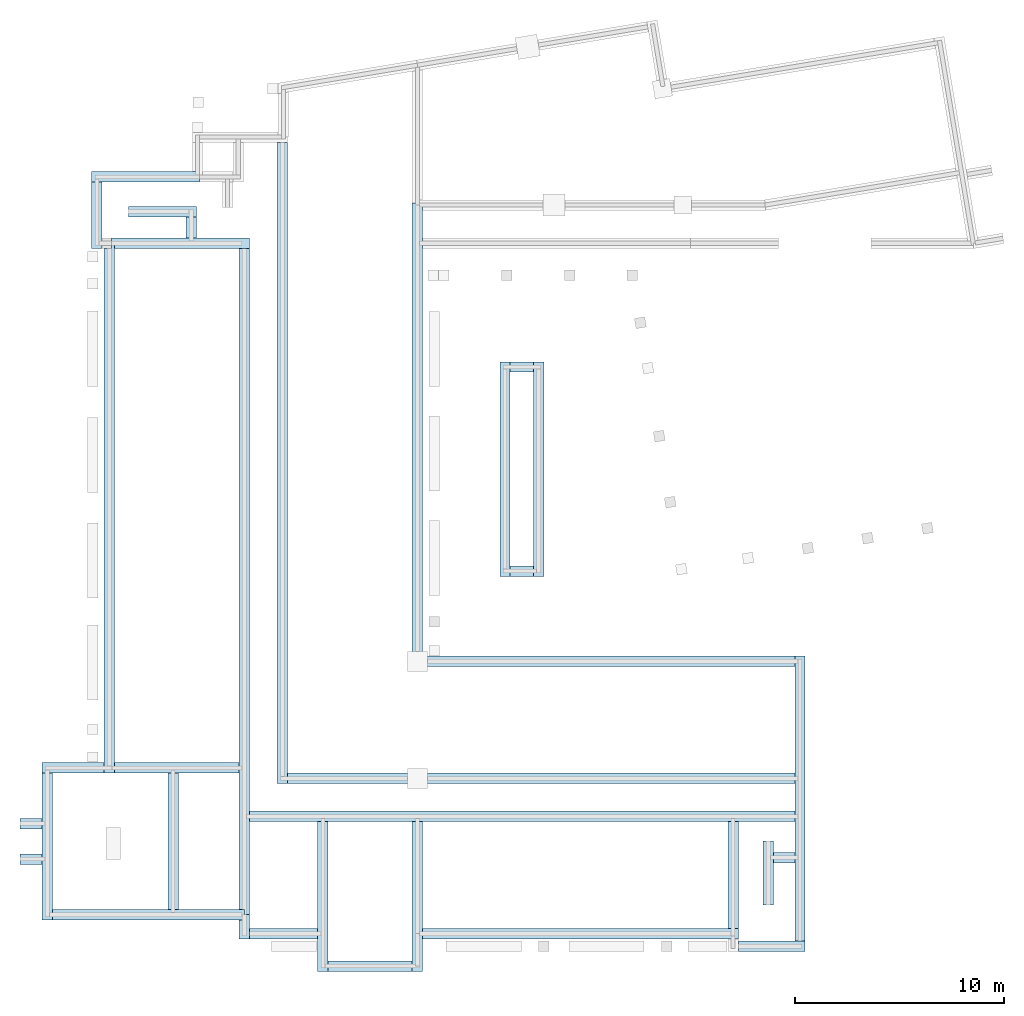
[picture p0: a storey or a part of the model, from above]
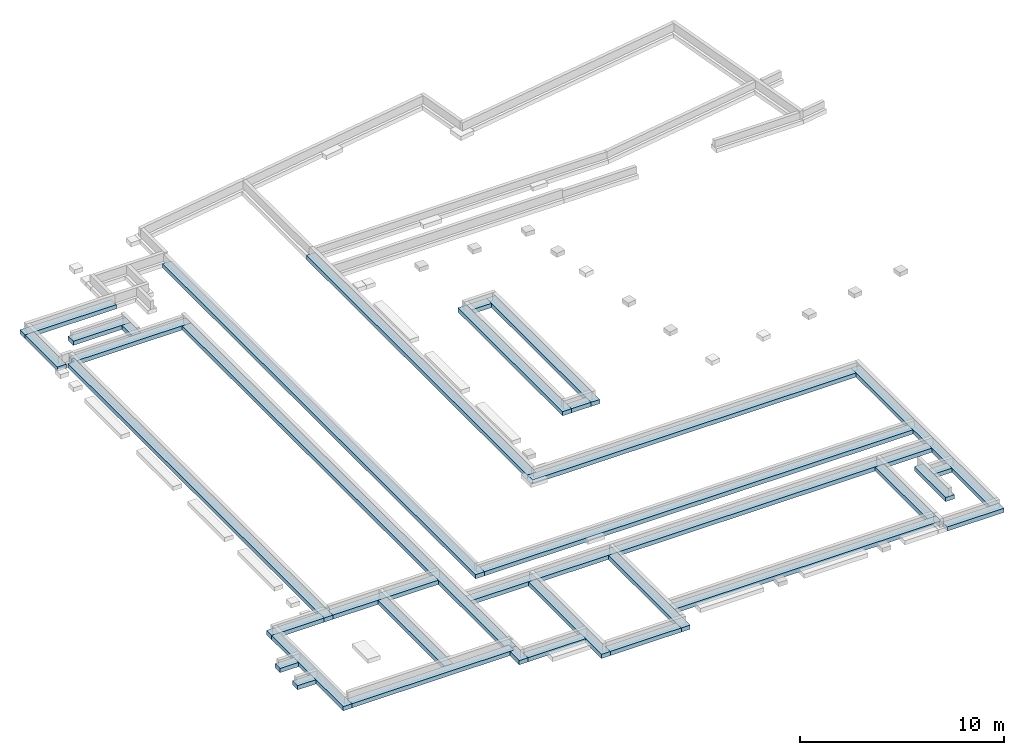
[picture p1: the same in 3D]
Properties of the parts of a building model (IFC4), part 1 of 5

# File
Description: ViewDefinition [ReferenceView_V1.2], ExchangeRequirement [Architecture]
File name: 0001
Time: 2023-01-23T10:33:38+01:00
Written by: ODA SDAI 22.12
Made in: 23.0.11.19 - Exporter 23.0.11.19 - Interface utilisateur alternative 23.0.11.19

# IfcProject, 0001
LongName: Nom du projet; Phase: Etat du projet

# IfcSite, Default
RefLatitude: 48, 51, 23, 999633; RefLongitude: 2, 21, 3, 553905; RefElevation: 0 m
Pset_SiteCommon - Reference: Informations sur le projet

# IfcBuilding
Pset_BuildingCommon - Reference: Informations sur le projet; NumberOfStoreys: 9
Pset_BuildingElementProxyCommon - Reference: Informations sur le projet; IsExternal: no
Pset_BuildingStoreyCommon - Reference: Informations sur le projet; sets with these values: 2

# IfcBuildingStorey: Niveau:Ligne du Niveau (9)
Pset_BuildingStoreyCommon - Reference: Ligne du Niveau
Name | LongName | Elevation (m)
Arase inf soubassement | Arase inf soubassement | -0.88
Arase inf longrines | Arase inf longrines | -0.63
RDC | RDC | 0
R+1 fini | R+1 fini | 3.6
Aras inf plancher haut RDC (dalle 29cm) | Aras inf plancher haut RDC (dalle 29cm) | 3.7
Aras sup plancher haut RDC | Aras sup plancher haut RDC | 3.99
Aras plafond 2.6 R+1 | Aras plafond 2.6 R+1 | 6.2
Aras plafond 3 R+1 | Aras plafond 3 R+1 | 6.6
Aras sup mur R+1 | Aras sup mur R+1 | 7.1

# IfcSpace: Agent entretien 4:1338018, 4
In: RDC
LongName: Agent entretien; PredefinedType: SPACE
Pset_SpaceCommon - IsExternal: no; Reference: Agent entretien 4
Pset_SpaceHeaterTypeCommon - Reference: Agent entretien 4
Qto_SpaceBaseQuantities - Height: 2.4384 m; GrossVolume: 48.8675 m3; NetVolume: 48.8675 m3

# IfcSpace: Animateur 7:1338027, 7
In: RDC
LongName: Animateur; PredefinedType: SPACE
Pset_SpaceCommon - IsExternal: no; Reference: Animateur 7
Pset_SpaceHeaterTypeCommon - Reference: Animateur 7
Qto_SpaceBaseQuantities - Height: 2.4384 m; GrossVolume: 35.9447 m3; NetVolume: 35.9447 m3

# IfcSpace: Ascenseur 79:1772514, 79
In: RDC
LongName: Ascenseur; PredefinedType: SPACE
Pset_SpaceCommon - IsExternal: no; Reference: Ascenseur 79
Pset_SpaceHeaterTypeCommon - Reference: Ascenseur 79
Qto_SpaceBaseQuantities - Height: 2.6 m; GrossVolume: 7.735 m3; NetVolume: 7.735 m3

# IfcSpace: Bagagerie 3:1338015, 3
In: RDC
LongName: Bagagerie; PredefinedType: SPACE
Pset_SpaceCommon - IsExternal: no; Reference: Bagagerie 3
Pset_SpaceHeaterTypeCommon - Reference: Bagagerie 3
Qto_SpaceBaseQuantities - Height: 2.4384 m; GrossVolume: 51.1568 m3; NetVolume: 51.1568 m3

# IfcSpace: Billard 2:1338012, 2
In: RDC
LongName: Billard; PredefinedType: SPACE
Pset_SpaceCommon - IsExternal: no; Reference: Billard 2
Pset_SpaceHeaterTypeCommon - Reference: Billard 2
Qto_SpaceBaseQuantities - Height: 2.4384 m; GrossVolume: 53.5814 m3; NetVolume: 53.5814 m3

# IfcSpace: Blanchisserie 6:1338024, 6
In: RDC
LongName: Blanchisserie; PredefinedType: SPACE
Pset_SpaceCommon - IsExternal: no; Reference: Blanchisserie 6
Pset_SpaceHeaterTypeCommon - Reference: Blanchisserie 6
Qto_SpaceBaseQuantities - Height: 2.4384 m; GrossVolume: 48.788 m3; NetVolume: 48.788 m3

# IfcSpace: Chambre 1 47:1339767, 47
In: RDC
LongName: Chambre 1; PredefinedType: SPACE
Pset_SpaceCommon - IsExternal: no; Reference: Chambre 1 47
Pset_SpaceHeaterTypeCommon - Reference: Chambre 1 47
Qto_SpaceBaseQuantities - Height: 2.4384 m; GrossVolume: 58.6162 m3; NetVolume: 58.6162 m3

# IfcSpace: Chambre 10 36:1339734, 36
In: RDC
LongName: Chambre 10; PredefinedType: SPACE
Pset_SpaceCommon - IsExternal: no; Reference: Chambre 10 36
Pset_SpaceHeaterTypeCommon - Reference: Chambre 10 36
Qto_SpaceBaseQuantities - Height: 2.4384 m; GrossVolume: 26.3973 m3; NetVolume: 26.3973 m3

# IfcSpace: Chambre 11 37:1339737, 37
In: RDC
LongName: Chambre 11; PredefinedType: SPACE
Pset_SpaceCommon - IsExternal: no; Reference: Chambre 11 37
Pset_SpaceHeaterTypeCommon - Reference: Chambre 11 37
Qto_SpaceBaseQuantities - Height: 2.4384 m; GrossVolume: 27.7189 m3; NetVolume: 27.7189 m3

# IfcSpace: Chambre 12 27:1338818, 27
In: RDC
LongName: Chambre 12; PredefinedType: SPACE
Pset_SpaceCommon - IsExternal: no; Reference: Chambre 12 27
Pset_SpaceHeaterTypeCommon - Reference: Chambre 12 27
Qto_SpaceBaseQuantities - Height: 2.4384 m; GrossVolume: 28.3696 m3; NetVolume: 28.3696 m3

# IfcSpace: Chambre 13 28:1339710, 28
In: RDC
LongName: Chambre 13; PredefinedType: SPACE
Pset_SpaceCommon - IsExternal: no; Reference: Chambre 13 28
Pset_SpaceHeaterTypeCommon - Reference: Chambre 13 28
Qto_SpaceBaseQuantities - Height: 2.4384 m; GrossVolume: 28.4378 m3; NetVolume: 28.4378 m3

# IfcSpace: Chambre 14 29:1339713, 29
In: RDC
LongName: Chambre 14; PredefinedType: SPACE
Pset_SpaceCommon - IsExternal: no; Reference: Chambre 14 29
Pset_SpaceHeaterTypeCommon - Reference: Chambre 14 29
Qto_SpaceBaseQuantities - Height: 2.4384 m; GrossVolume: 27.6278 m3; NetVolume: 27.6278 m3

# IfcSpace: Chambre 15 30:1339716, 30
In: RDC
LongName: Chambre 15; PredefinedType: SPACE
Pset_SpaceCommon - IsExternal: no; Reference: Chambre 15 30
Pset_SpaceHeaterTypeCommon - Reference: Chambre 15 30
Qto_SpaceBaseQuantities - Height: 2.4384 m; GrossVolume: 27.1823 m3; NetVolume: 27.1823 m3

# IfcSpace: Chambre 16 31:1339719, 31
In: RDC
LongName: Chambre 16; PredefinedType: SPACE
Pset_SpaceCommon - IsExternal: no; Reference: Chambre 16 31
Pset_SpaceHeaterTypeCommon - Reference: Chambre 16 31
Qto_SpaceBaseQuantities - Height: 2.4384 m; GrossVolume: 26.2068 m3; NetVolume: 26.2068 m3

# IfcSpace: Chambre 17 32:1339722, 32
In: RDC
LongName: Chambre 17; PredefinedType: SPACE
Pset_SpaceCommon - IsExternal: no; Reference: Chambre 17 32
Pset_SpaceHeaterTypeCommon - Reference: Chambre 17 32
Qto_SpaceBaseQuantities - Height: 2.4384 m; GrossVolume: 26.0209 m3; NetVolume: 26.0209 m3

# IfcSpace: Chambre 18 41:1339749, 41
In: RDC
LongName: Chambre 18; PredefinedType: SPACE
Pset_SpaceCommon - IsExternal: no; Reference: Chambre 18 41
Pset_SpaceHeaterTypeCommon - Reference: Chambre 18 41
Qto_SpaceBaseQuantities - Height: 2.4384 m; GrossVolume: 59.6883 m3; NetVolume: 59.6883 m3

# IfcSpace: Chambre 19 42:1339752, 42
In: RDC
LongName: Chambre 19; PredefinedType: SPACE
Pset_SpaceCommon - IsExternal: no; Reference: Chambre 19 42
Pset_SpaceHeaterTypeCommon - Reference: Chambre 19 42
Qto_SpaceBaseQuantities - Height: 2.4384 m; GrossVolume: 61.8927 m3; NetVolume: 61.8927 m3

# IfcSpace: Chambre 2 44:1339758, 44
In: RDC
LongName: Chambre 2; PredefinedType: SPACE
Pset_SpaceCommon - IsExternal: no; Reference: Chambre 2 44
Pset_SpaceHeaterTypeCommon - Reference: Chambre 2 44
Qto_SpaceBaseQuantities - Height: 2.4384 m; GrossVolume: 59.9449 m3; NetVolume: 59.9449 m3

# IfcSpace: Chambre 20 45:1339761, 45
In: RDC
LongName: Chambre 20; PredefinedType: SPACE
Pset_SpaceCommon - IsExternal: no; Reference: Chambre 20 45
Pset_SpaceHeaterTypeCommon - Reference: Chambre 20 45
Qto_SpaceBaseQuantities - Height: 2.4384 m; GrossVolume: 60.4265 m3; NetVolume: 60.4265 m3

# IfcSpace: Chambre 21 46:1339764, 46
In: RDC
LongName: Chambre 21; PredefinedType: SPACE
Pset_SpaceCommon - IsExternal: no; Reference: Chambre 21 46
Pset_SpaceHeaterTypeCommon - Reference: Chambre 21 46
Qto_SpaceBaseQuantities - Height: 2.4384 m; GrossVolume: 61.8682 m3; NetVolume: 61.8682 m3

# IfcSpace: Chambre 22 74:1519061, 74
In: R+1 fini
LongName: Chambre 22; PredefinedType: SPACE
Pset_SpaceCommon - IsExternal: no; Reference: Chambre 22 74
Pset_SpaceHeaterTypeCommon - Reference: Chambre 22 74
Qto_SpaceBaseQuantities - Height: 2.6 m; GrossVolume: 62.5554 m3; NetVolume: 62.5554 m3

# IfcSpace: Chambre 23 71:1519052, 71
In: R+1 fini
LongName: Chambre 23; PredefinedType: SPACE
Pset_SpaceCommon - IsExternal: no; Reference: Chambre 23 71
Pset_SpaceHeaterTypeCommon - Reference: Chambre 23 71
Qto_SpaceBaseQuantities - Height: 2.6 m; GrossVolume: 63.4638 m3; NetVolume: 63.4638 m3

# IfcSpace: Chambre 24 70:1519049, 70
In: R+1 fini
LongName: Chambre 24; PredefinedType: SPACE
Pset_SpaceCommon - IsExternal: no; Reference: Chambre 24 70
Pset_SpaceHeaterTypeCommon - Reference: Chambre 24 70
Qto_SpaceBaseQuantities - Height: 2.6 m; GrossVolume: 64.3113 m3; NetVolume: 64.3113 m3

# IfcSpace: Chambre 25 67:1519040, 67
In: R+1 fini
LongName: Chambre 25; PredefinedType: SPACE
Pset_SpaceCommon - IsExternal: no; Reference: Chambre 25 67
Pset_SpaceHeaterTypeCommon - Reference: Chambre 25 67
Qto_SpaceBaseQuantities - Height: 2.6 m; GrossVolume: 61.9334 m3; NetVolume: 61.9334 m3

# IfcSpace: Chambre 26 (PMR) 66:1519037, 66
In: R+1 fini
LongName: Chambre 26 (PMR); PredefinedType: SPACE
Pset_SpaceCommon - IsExternal: no; Reference: Chambre 26 (PMR) 66
Pset_SpaceHeaterTypeCommon - Reference: Chambre 26 (PMR) 66
Qto_SpaceBaseQuantities - Height: 2.6 m; GrossVolume: 62.758 m3; NetVolume: 62.758 m3

# IfcSpace: Chambre 27 (veilleur de nuit) 62:1519025, 62
In: R+1 fini
LongName: Chambre 27 (veilleur de nuit); PredefinedType: SPACE
Pset_SpaceCommon - IsExternal: no; Reference: Chambre 27 (veilleur de nuit) 62
Pset_SpaceHeaterTypeCommon - Reference: Chambre 27 (veilleur de nuit) 62
Qto_SpaceBaseQuantities - Height: 2.6 m; GrossVolume: 29.6416 m3; NetVolume: 29.6416 m3

# IfcSpace: Chambre 28 (PMR) 61:1519022, 61
In: R+1 fini
LongName: Chambre 28 (PMR); PredefinedType: SPACE
Pset_SpaceCommon - IsExternal: no; Reference: Chambre 28 (PMR) 61
Pset_SpaceHeaterTypeCommon - Reference: Chambre 28 (PMR) 61
Qto_SpaceBaseQuantities - Height: 2.6 m; GrossVolume: 34.8429 m3; NetVolume: 34.8429 m3

# IfcSpace: Chambre 29 59:1519016, 59
In: R+1 fini
LongName: Chambre 29; PredefinedType: SPACE
Pset_SpaceCommon - IsExternal: no; Reference: Chambre 29 59
Pset_SpaceHeaterTypeCommon - Reference: Chambre 29 59
Qto_SpaceBaseQuantities - Height: 2.6 m; GrossVolume: 33.7835 m3; NetVolume: 33.7835 m3

# IfcSpace: Chambre 3 43:1339755, 43
In: RDC
LongName: Chambre 3; PredefinedType: SPACE
Pset_SpaceCommon - IsExternal: no; Reference: Chambre 3 43
Pset_SpaceHeaterTypeCommon - Reference: Chambre 3 43
Qto_SpaceBaseQuantities - Height: 2.4384 m; GrossVolume: 59.8766 m3; NetVolume: 59.8766 m3

# IfcSpace: Chambre 30 58:1519013, 58
In: R+1 fini
LongName: Chambre 30; PredefinedType: SPACE
Pset_SpaceCommon - IsExternal: no; Reference: Chambre 30 58
Pset_SpaceHeaterTypeCommon - Reference: Chambre 30 58
Qto_SpaceBaseQuantities - Height: 2.6 m; GrossVolume: 28.125 m3; NetVolume: 28.125 m3

# IfcSpace: Chambre 31 57:1519010, 57
In: R+1 fini
LongName: Chambre 31; PredefinedType: SPACE
Pset_SpaceCommon - IsExternal: no; Reference: Chambre 31 57
Pset_SpaceHeaterTypeCommon - Reference: Chambre 31 57
Qto_SpaceBaseQuantities - Height: 2.6 m; GrossVolume: 28.1467 m3; NetVolume: 28.1467 m3

# IfcSpace: Chambre 32 56:1519007, 56
In: R+1 fini
LongName: Chambre 32; PredefinedType: SPACE
Pset_SpaceCommon - IsExternal: no; Reference: Chambre 32 56
Pset_SpaceHeaterTypeCommon - Reference: Chambre 32 56
Qto_SpaceBaseQuantities - Height: 2.6 m; GrossVolume: 28.2171 m3; NetVolume: 28.2171 m3

# IfcSpace: Chambre 33 55:1519004, 55
In: R+1 fini
LongName: Chambre 33; PredefinedType: SPACE
Pset_SpaceCommon - IsExternal: no; Reference: Chambre 33 55
Pset_SpaceHeaterTypeCommon - Reference: Chambre 33 55
Qto_SpaceBaseQuantities - Height: 2.6 m; GrossVolume: 29.4854 m3; NetVolume: 29.4854 m3

# IfcSpace: Chambre 35 50:1518989, 50
In: R+1 fini
LongName: Chambre 35; PredefinedType: SPACE
Pset_SpaceCommon - IsExternal: no; Reference: Chambre 35 50
Pset_SpaceHeaterTypeCommon - Reference: Chambre 35 50
Qto_SpaceBaseQuantities - Height: 2.6 m; GrossVolume: 30.2575 m3; NetVolume: 30.2575 m3

# IfcSpace: Chambre 36 51:1518992, 51
In: R+1 fini
LongName: Chambre 36; PredefinedType: SPACE
Pset_SpaceCommon - IsExternal: no; Reference: Chambre 36 51
Pset_SpaceHeaterTypeCommon - Reference: Chambre 36 51
Qto_SpaceBaseQuantities - Height: 2.6 m; GrossVolume: 29.3948 m3; NetVolume: 29.3948 m3

# IfcSpace: Chambre 37 52:1518995, 52
In: R+1 fini
LongName: Chambre 37; PredefinedType: SPACE
Pset_SpaceCommon - IsExternal: no; Reference: Chambre 37 52
Pset_SpaceHeaterTypeCommon - Reference: Chambre 37 52
Qto_SpaceBaseQuantities - Height: 2.6 m; GrossVolume: 28.9234 m3; NetVolume: 28.9234 m3

# IfcSpace: Chambre 38 53:1518998, 53
In: R+1 fini
LongName: Chambre 38; PredefinedType: SPACE
Pset_SpaceCommon - IsExternal: no; Reference: Chambre 38 53
Pset_SpaceHeaterTypeCommon - Reference: Chambre 38 53
Qto_SpaceBaseQuantities - Height: 2.6 m; GrossVolume: 27.8849 m3; NetVolume: 27.8849 m3

# IfcSpace: Chambre 39 54:1519001, 54
In: R+1 fini
LongName: Chambre 39; PredefinedType: SPACE
Pset_SpaceCommon - IsExternal: no; Reference: Chambre 39 54
Pset_SpaceHeaterTypeCommon - Reference: Chambre 39 54
Qto_SpaceBaseQuantities - Height: 2.6 m; GrossVolume: 27.6892 m3; NetVolume: 27.6892 m3

# IfcSpace: Chambre 4 40:1339746, 40
In: RDC
LongName: Chambre 4; PredefinedType: SPACE
Pset_SpaceCommon - IsExternal: no; Reference: Chambre 4 40
Pset_SpaceHeaterTypeCommon - Reference: Chambre 4 40
Qto_SpaceBaseQuantities - Height: 2.4384 m; GrossVolume: 58.1102 m3; NetVolume: 58.1102 m3

# IfcSpace: Chambre 40 68:1519043, 68
In: R+1 fini
LongName: Chambre 40; PredefinedType: SPACE
Pset_SpaceCommon - IsExternal: no; Reference: Chambre 40 68
Pset_SpaceHeaterTypeCommon - Reference: Chambre 40 68
Qto_SpaceBaseQuantities - Height: 2.6 m; GrossVolume: 63.1735 m3; NetVolume: 63.1735 m3

# IfcSpace: Chambre 41 69:1519046, 69
In: R+1 fini
LongName: Chambre 41; PredefinedType: SPACE
Pset_SpaceCommon - IsExternal: no; Reference: Chambre 41 69
Pset_SpaceHeaterTypeCommon - Reference: Chambre 41 69
Qto_SpaceBaseQuantities - Height: 2.6 m; GrossVolume: 66.1915 m3; NetVolume: 66.1915 m3

# IfcSpace: Chambre 42 72:1519055, 72
In: R+1 fini
LongName: Chambre 42; PredefinedType: SPACE
Pset_SpaceCommon - IsExternal: no; Reference: Chambre 42 72
Pset_SpaceHeaterTypeCommon - Reference: Chambre 42 72
Qto_SpaceBaseQuantities - Height: 2.6 m; GrossVolume: 64.2993 m3; NetVolume: 64.2993 m3

# IfcSpace: Chambre 43 73:1519058, 73
In: R+1 fini
LongName: Chambre 43; PredefinedType: SPACE
Pset_SpaceCommon - IsExternal: no; Reference: Chambre 43 73
Pset_SpaceHeaterTypeCommon - Reference: Chambre 43 73
Qto_SpaceBaseQuantities - Height: 2.6 m; GrossVolume: 65.6704 m3; NetVolume: 65.6704 m3

# IfcSpace: Chambre 44 75:1519064, 75
In: R+1 fini
LongName: Chambre 44; PredefinedType: SPACE
Pset_SpaceCommon - IsExternal: no; Reference: Chambre 44 75
Pset_SpaceHeaterTypeCommon - Reference: Chambre 44 75
Qto_SpaceBaseQuantities - Height: 2.6 m; GrossVolume: 64.3191 m3; NetVolume: 64.3191 m3

# IfcSpace: Chambre 5 PMR 39:1339743, 39
In: RDC
LongName: Chambre 5 PMR; PredefinedType: SPACE
Pset_SpaceCommon - IsExternal: no; Reference: Chambre 5 PMR 39
Pset_SpaceHeaterTypeCommon - Reference: Chambre 5 PMR 39
Qto_SpaceBaseQuantities - Height: 2.4384 m; GrossVolume: 58.8659 m3; NetVolume: 58.8659 m3

# IfcSpace: Chambre 6 38:1339740, 38
In: RDC
LongName: Chambre 6; PredefinedType: SPACE
Pset_SpaceCommon - IsExternal: no; Reference: Chambre 6 38
Pset_SpaceHeaterTypeCommon - Reference: Chambre 6 38
Qto_SpaceBaseQuantities - Height: 2.4384 m

# IfcSpace: Chambre 7 33:1339725, 33
In: RDC
LongName: Chambre 7; PredefinedType: SPACE
Pset_SpaceCommon - IsExternal: no; Reference: Chambre 7 33
Pset_SpaceHeaterTypeCommon - Reference: Chambre 7 33
Qto_SpaceBaseQuantities - Height: 2.4384 m; GrossVolume: 31.6837 m3; NetVolume: 31.6837 m3

# IfcSpace: Chambre 8 34:1339728, 34
In: RDC
LongName: Chambre 8; PredefinedType: SPACE
Pset_SpaceCommon - IsExternal: no; Reference: Chambre 8 34
Pset_SpaceHeaterTypeCommon - Reference: Chambre 8 34
Qto_SpaceBaseQuantities - Height: 2.4384 m; GrossVolume: 26.3973 m3; NetVolume: 26.3973 m3

# IfcSpace: Chambre 9 35:1339731, 35
In: RDC
LongName: Chambre 9; PredefinedType: SPACE
Pset_SpaceCommon - IsExternal: no; Reference: Chambre 9 35
Pset_SpaceHeaterTypeCommon - Reference: Chambre 9 35
Qto_SpaceBaseQuantities - Height: 2.4384 m; GrossVolume: 26.3973 m3; NetVolume: 26.3973 m3

# IfcSpace: Chambre34 49:1518985, 49
In: R+1 fini
LongName: Chambre34; PredefinedType: SPACE
Pset_SpaceCommon - IsExternal: no; Reference: Chambre34 49
Pset_SpaceHeaterTypeCommon - Reference: Chambre34 49
Qto_SpaceBaseQuantities - Height: 2.6 m; GrossVolume: 30.1847 m3; NetVolume: 30.1847 m3

# IfcSpace: Chaufferie 18:1338604, 18
In: RDC
LongName: Chaufferie; PredefinedType: SPACE
Pset_SpaceCommon - IsExternal: no; Reference: Chaufferie 18
Pset_SpaceHeaterTypeCommon - Reference: Chaufferie 18
Qto_SpaceBaseQuantities - Height: 2.4384 m; GrossVolume: 121.654 m3; NetVolume: 121.654 m3

# IfcSpace: Dégagement 15:1338595, 15
In: RDC
LongName: Dégagement; PredefinedType: SPACE
Pset_SpaceCommon - IsExternal: no; Reference: Dégagement 15
Pset_SpaceHeaterTypeCommon - Reference: Dégagement 15
Qto_SpaceBaseQuantities - Height: 2.4384 m; GrossVolume: 36.2378 m3; NetVolume: 36.2378 m3

# IfcSpace: Dégagement 16:1338598, 16
In: RDC
LongName: Dégagement; PredefinedType: SPACE
Pset_SpaceCommon - IsExternal: no; Reference: Dégagement 16
Pset_SpaceHeaterTypeCommon - Reference: Dégagement 16
Qto_SpaceBaseQuantities - Height: 2.4384 m; GrossVolume: 148.132 m3; NetVolume: 148.132 m3

# IfcSpace: Dégagement 17:1338601, 17
In: RDC
LongName: Dégagement; PredefinedType: SPACE
Pset_SpaceCommon - IsExternal: no; Reference: Dégagement 17
Pset_SpaceHeaterTypeCommon - Reference: Dégagement 17
Qto_SpaceBaseQuantities - Height: 2.4384 m; GrossVolume: 88.0575 m3; NetVolume: 88.0575 m3

# IfcSpace: Dégagement 26:1338812, 26
In: RDC
LongName: Dégagement; PredefinedType: SPACE
Pset_SpaceCommon - IsExternal: no; Reference: Dégagement 26
Pset_SpaceHeaterTypeCommon - Reference: Dégagement 26
Qto_SpaceBaseQuantities - Height: 2.4384 m; GrossVolume: 28.3128 m3; NetVolume: 28.3128 m3

# IfcSpace: Dégagement 48:1345402, 48
In: RDC
LongName: Dégagement; PredefinedType: SPACE
Pset_SpaceCommon - IsExternal: no; Reference: Dégagement 48
Pset_SpaceHeaterTypeCommon - Reference: Dégagement 48
Qto_SpaceBaseQuantities - Height: 2.4384 m; GrossVolume: 59.0178 m3; NetVolume: 59.0178 m3

# IfcSpace: Dégagement 76:1519067, 76
In: R+1 fini
LongName: Dégagement; PredefinedType: SPACE
Pset_SpaceCommon - IsExternal: no; Reference: Dégagement 76
Pset_SpaceHeaterTypeCommon - Reference: Dégagement 76
Qto_SpaceBaseQuantities - Height: 2.6 m; GrossVolume: 63.8807 m3; NetVolume: 63.8807 m3

# IfcSpace: Dégagement 77:1519070, 77
In: R+1 fini
LongName: Dégagement; PredefinedType: SPACE
Pset_SpaceCommon - IsExternal: no; Reference: Dégagement 77
Pset_SpaceHeaterTypeCommon - Reference: Dégagement 77
Qto_SpaceBaseQuantities - Height: 2.6 m; GrossVolume: 91.2279 m3; NetVolume: 91.2279 m3

# IfcSpace: Dégagement 78:1519073, 78
In: R+1 fini
LongName: Dégagement; PredefinedType: SPACE
Pset_SpaceCommon - IsExternal: no; Reference: Dégagement 78
Pset_SpaceHeaterTypeCommon - Reference: Dégagement 78
Qto_SpaceBaseQuantities - Height: 2.6 m; GrossVolume: 92.7482 m3; NetVolume: 92.7482 m3

# IfcSpace: Dépôt 9:1338033, 9
In: RDC
LongName: Dépôt; PredefinedType: SPACE
Pset_SpaceCommon - IsExternal: no; Reference: Dépôt 9
Pset_SpaceHeaterTypeCommon - Reference: Dépôt 9
Qto_SpaceBaseQuantities - Height: 2.4384 m; GrossVolume: 13.607 m3; NetVolume: 13.607 m3

# IfcSpace: Entrée 13:1338589, 13
In: RDC
LongName: Entrée; PredefinedType: SPACE
Pset_SpaceCommon - IsExternal: no; Reference: Entrée 13
Pset_SpaceHeaterTypeCommon - Reference: Entrée 13
Qto_SpaceBaseQuantities - Height: 2.4384 m; GrossVolume: 25.9487 m3; NetVolume: 25.9487 m3

# IfcSpace: Foyer 1:1338004, 1
In: RDC
LongName: Foyer; PredefinedType: SPACE
Pset_SpaceCommon - Reference: Foyer 1; IsExternal: no
Pset_SpaceHeaterTypeCommon - Reference: Foyer 1
Qto_SpaceBaseQuantities - Height: 2.4384 m; GrossVolume: 227.898 m3; NetVolume: 227.898 m3

# IfcSpace: Garage 19:1338607, 19
In: RDC
LongName: Garage; PredefinedType: SPACE
Pset_SpaceCommon - IsExternal: no; Reference: Garage 19
Pset_SpaceHeaterTypeCommon - Reference: Garage 19
Qto_SpaceBaseQuantities - Height: 2.4384 m; GrossVolume: 49.9287 m3; NetVolume: 49.9287 m3

# IfcSpace: Lingerie 60:1519019, 60
In: R+1 fini
LongName: Lingerie; PredefinedType: SPACE
Pset_SpaceCommon - IsExternal: no; Reference: Lingerie 60
Pset_SpaceHeaterTypeCommon - Reference: Lingerie 60
Qto_SpaceBaseQuantities - Height: 2.6 m; GrossVolume: 18.8833 m3; NetVolume: 18.8833 m3

# IfcSpace: Local ménage 20:1338782, 20
In: RDC
LongName: Local ménage; PredefinedType: SPACE
Pset_SpaceCommon - IsExternal: no; Reference: Local ménage 20
Pset_SpaceHeaterTypeCommon - Reference: Local ménage 20
Qto_SpaceBaseQuantities - Height: 2.4384 m; GrossVolume: 16.2834 m3; NetVolume: 16.2834 m3

# IfcSpace: Local ménage 21:1338785, 21
In: RDC
LongName: Local ménage; PredefinedType: SPACE
Pset_SpaceCommon - IsExternal: no; Reference: Local ménage 21
Pset_SpaceHeaterTypeCommon - Reference: Local ménage 21
Qto_SpaceBaseQuantities - Height: 2.4384 m; GrossVolume: 11.8994 m3; NetVolume: 11.8994 m3

# IfcSpace: Local ménage 64:1519031, 64
In: R+1 fini
LongName: Local ménage; PredefinedType: SPACE
Pset_SpaceCommon - IsExternal: no; Reference: Local ménage 64
Pset_SpaceHeaterTypeCommon - Reference: Local ménage 64
Qto_SpaceBaseQuantities - Height: 2.6 m; GrossVolume: 13.9194 m3; NetVolume: 13.9194 m3

# IfcSpace: Musculation 12:1338042, 12
In: RDC
LongName: Musculation; PredefinedType: SPACE
Pset_SpaceCommon - IsExternal: no; Reference: Musculation 12
Pset_SpaceHeaterTypeCommon - Reference: Musculation 12
Qto_SpaceBaseQuantities - Height: 2.4384 m; GrossVolume: 46.9502 m3; NetVolume: 46.9502 m3

# IfcSpace: Réserve 8:1338030, 8
In: RDC
LongName: Réserve; PredefinedType: SPACE
Pset_SpaceCommon - IsExternal: no; Reference: Réserve 8
Pset_SpaceHeaterTypeCommon - Reference: Réserve 8
Qto_SpaceBaseQuantities - Height: 2.4384 m; GrossVolume: 20.3332 m3; NetVolume: 20.3332 m3

# IfcSpace: Salle informatique 5:1338021, 5
In: RDC
LongName: Salle informatique; PredefinedType: SPACE
Pset_SpaceCommon - IsExternal: no; Reference: Salle informatique 5
Pset_SpaceHeaterTypeCommon - Reference: Salle informatique 5
Qto_SpaceBaseQuantities - Height: 2.4384 m; GrossVolume: 48.8675 m3; NetVolume: 48.8675 m3

# IfcSpace: Salle polyvalente 11:1338039, 11
In: RDC
LongName: Salle polyvalente; PredefinedType: SPACE
Pset_SpaceCommon - IsExternal: no; Reference: Salle polyvalente 11
Pset_SpaceHeaterTypeCommon - Reference: Salle polyvalente 11
Qto_SpaceBaseQuantities - Height: 2.4384 m; GrossVolume: 49.4307 m3; NetVolume: 49.4307 m3

# IfcSpace: Sanitaires F 63:1519028, 63
In: R+1 fini
LongName: Sanitaires F; PredefinedType: SPACE
Pset_SpaceCommon - IsExternal: no; Reference: Sanitaires F 63
Pset_SpaceHeaterTypeCommon - Reference: Sanitaires F 63
Qto_SpaceBaseQuantities - Height: 2.6 m; GrossVolume: 12.6625 m3; NetVolume: 12.6625 m3

# IfcSpace: Sanitaires G 65:1519034, 65
In: R+1 fini
LongName: Sanitaires G; PredefinedType: SPACE
Pset_SpaceCommon - IsExternal: no; Reference: Sanitaires G 65
Pset_SpaceHeaterTypeCommon - Reference: Sanitaires G 65
Qto_SpaceBaseQuantities - Height: 2.6 m; GrossVolume: 24.1341 m3; NetVolume: 24.1341 m3

# IfcSpace: Sanitaires filles 22:1338791, 22
In: RDC
LongName: Sanitaires filles; PredefinedType: SPACE
Pset_SpaceCommon - IsExternal: no; Reference: Sanitaires filles 22
Pset_SpaceHeaterTypeCommon - Reference: Sanitaires filles 22
Qto_SpaceBaseQuantities - Height: 2.4384 m; GrossVolume: 7.18231 m3; NetVolume: 7.18231 m3

# IfcSpace: Sanitaires filles 23:1338794, 23
In: RDC
LongName: Sanitaires filles; PredefinedType: SPACE
Pset_SpaceCommon - IsExternal: no; Reference: Sanitaires filles 23
Pset_SpaceHeaterTypeCommon - Reference: Sanitaires filles 23
Qto_SpaceBaseQuantities - Height: 2.4384 m; GrossVolume: 13.1405 m3; NetVolume: 13.1405 m3

# IfcSpace: Sanitaires garçons 24:1338800, 24
In: RDC
LongName: Sanitaires garçons; PredefinedType: SPACE
Pset_SpaceCommon - IsExternal: no; Reference: Sanitaires garçons 24
Pset_SpaceHeaterTypeCommon - Reference: Sanitaires garçons 24
Qto_SpaceBaseQuantities - Height: 2.4384 m; GrossVolume: 22.0787 m3; NetVolume: 22.0787 m3

# IfcSpace: Sanitaires garçons 25:1338803, 25
In: RDC
LongName: Sanitaires garçons; PredefinedType: SPACE
Pset_SpaceCommon - IsExternal: no; Reference: Sanitaires garçons 25
Pset_SpaceHeaterTypeCommon - Reference: Sanitaires garçons 25
Qto_SpaceBaseQuantities - Height: 2.4384 m; GrossVolume: 31.5398 m3; NetVolume: 31.5398 m3

# IfcSpace: TV 10:1338036, 10
In: RDC
LongName: TV; PredefinedType: SPACE
Pset_SpaceCommon - IsExternal: no; Reference: TV 10
Pset_SpaceHeaterTypeCommon - Reference: TV 10
Qto_SpaceBaseQuantities - Height: 2.4384 m; GrossVolume: 96.4751 m3; NetVolume: 96.4808 m3

# IfcAirTerminal: Metalaire V-1:V-1 (7)
Type - Material: Steel
Type - Pset_ManufacturerTypeInformation - Manufacturer: Metalaire ®
Pset_AirTerminalBoxTypeCommon - Reference: V-1; sets with these values: 3
Name (Metalaire V-1:V-1:...) | In
1335432 | 17
1336199 | RDC
1337224 | 16
1337436 | 17
1337644 | RDC
1337893 | RDC
1345734 | 15

# IfcBuildingElementProxy: Door Closers_Door closer DC500_ASSA ABLOY ES_DC500…EV1 with Guide rail G461:Door closer DC500_DC500…EV1 (29)
Type - Material: Silver
Type - Pset_BuildingElementProxyCommon - IsExternal: no
Type - Pset_ManufacturerTypeInformation - ArticleNumber: DC500…EV1; Manufacturer: ASSA ABLOY
Pset_BuildingElementProxyCommon - Reference: Door closer DC500_DC500…EV1
Pset_EnvironmentalImpactIndicators - Reference: Door closer DC500_DC500…EV1
Name (Door Closers_Door closer DC500_ASSA ABLOY ES_DC500…EV1 with Guide rail G461:Door closer DC500_DC500…EV1:...) | In | NetSurfaceArea (m2) | NetVolume (m3)
1307158 | RDC | 0.390628 | 0.00384205
1307209 | RDC | 0.390628 | 0.00384205
1307669 | RDC | 0.390628 | 0.00384205
1307704 | RDC | 0.390628 | 0.00384205
1307769 | RDC | 0.390628 | 0.00384205
1308141 | RDC | 0.360308 | 0.00356485
1308186 | RDC | 0.390628 | 0.00384205
1308226 | RDC | 0.390628 | 0.00384205
1308302 | RDC | 0.390628 | 0.00384205
1308543 | RDC | 0.390628 | 0.00384205
1309056 | RDC | 0.390628 | 0.00384205
1309595 | RDC | 0.390628 | 0.00384205
1309628 | RDC | 0.390628 | 0.00384205
1320047 | RDC | 0.390628 | 0.00384205
1321609 | RDC | 0.390628 | 0.00384205
1348412 | RDC | 0.420948 | 0.00411925
1383802 | R+1 fini | 0.390628 | 0.00384205
1383828 | R+1 fini | 0.390628 | 0.00384205
1384052 | R+1 fini | 0.390628 | 0.00384205
1384083 | R+1 fini | 0.390628 | 0.00384205
1385412 | R+1 fini | 0.390628 | 0.00384205
1385452 | R+1 fini | 0.390628 | 0.00384205
1385711 | R+1 fini | 0.390628 | 0.00384205
1385756 | R+1 fini | 0.390628 | 0.00384205
1385789 | R+1 fini | 0.390628 | 0.00384205
1385851 | R+1 fini | 0.390628 | 0.00384205
1385891 | R+1 fini | 0.390628 | 0.00384205
1385956 | R+1 fini | 0.390628 | 0.00384205
1410007 | R+1 fini | 0.390628 | 0.00384205

# IfcBuildingElementProxy: Electrical_Outlets-Sockets_ELKO_PLUS-switch-1-pole-two-way-screwless-pol:Default (187)
Type - Material: PLUS switch 1-pole/two-way screwless polar white - EKO03891 - white
Type - Pset_BuildingElementProxyCommon - IsExternal: no
Pset_BuildingElementProxyCommon - Reference: Default
Pset_EnvironmentalImpactIndicators - Reference: Default
Qto_BuildingElementProxyQuantities - NetSurfaceArea: 0.0388076 m2; NetVolume: 0.0000849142 m3
Name (Electrical_Outlets-Sockets_ELKO_PLUS-switch-1-pole-two-way-screwless-pol:Default:...) | In
1168618 | 40
1168721 | 40
1168944 | RDC
1169311 | RDC
1169772 | RDC
1170127 | RDC
1171485 | 43
1173084 | RDC
1173319 | RDC
1173722 | RDC
1173855 | RDC
1174014 | 43
1174161 | 43
1176295 | 44
1176562 | RDC
1176791 | RDC
1176940 | 43
1177433 | RDC
1177835 | RDC
1177990 | RDC
1178117 | RDC
1178337 | 44
1180549 | RDC
1180670 | RDC
1180943 | RDC
1181122 | RDC
1181327 | 47
1181572 | 47
1183457 | 46
1183714 | RDC
1183949 | RDC
1184034 | 46
1184437 | RDC
1184648 | RDC
1185069 | RDC
1185264 | RDC
1185413 | RDC
1185586 | RDC
1185953 | RDC
1186082 | 45
1190289 | RDC
1190676 | RDC
1190851 | RDC
1191008 | 42
1191283 | RDC
1191460 | RDC
1191541 | RDC
1191744 | RDC
1191911 | 41
1192050 | RDC
1192553 | RDC
1192658 | RDC
1196246 | RDC
1196457 | RDC
1196730 | 32
1197121 | RDC
1197228 | RDC
1197393 | RDC
1197758 | RDC
1197909 | RDC
1198294 | 29
1198771 | RDC
1199002 | RDC
1199251 | RDC
1199506 | RDC
1199611 | RDC
1199720 | RDC
1199913 | RDC
1200134 | 27
1200591 | RDC
1200854 | RDC
1201176 | RDC
1201496 | RDC
1201687 | RDC
1202020 | RDC
1202153 | RDC
1202616 | RDC
1202653 | RDC
1202800 | RDC
1203037 | RDC
1203166 | RDC
1203335 | RDC
1203442 | 33
1203653 | RDC
1203750 | 18
1203967 | RDC
1204240 | 18
1313866 | RDC
1314507 | RDC
1314972 | RDC
1315123 | RDC
1315316 | RDC
1315459 | RDC
1315706 | RDC
1316368 | RDC
1316775 | RDC
1729687 | 49
1730380 | R+1 fini
1730817 | R+1 fini
1731214 | R+1 fini
1731451 | R+1 fini
1731746 | R+1 fini
1731945 | R+1 fini
1732470 | R+1 fini
1732577 | R+1 fini
1732840 | R+1 fini
1732987 | R+1 fini
1733266 | 54
1733413 | R+1 fini
1734254 | R+1 fini
1734439 | R+1 fini
1734672 | R+1 fini
1734923 | R+1 fini
1735306 | R+1 fini
1735589 | 58
1735966 | R+1 fini
1736397 | R+1 fini
1736678 | 59
1736947 | R+1 fini
1737228 | 61
1737497 | R+1 fini
1737768 | R+1 fini
1738133 | R+1 fini
1738450 | 66
1739099 | R+1 fini
1740134 | R+1 fini
1740391 | R+1 fini
1740686 | R+1 fini
1741047 | R+1 fini
1741404 | R+1 fini
1741863 | R+1 fini
1742218 | R+1 fini
1742521 | R+1 fini
1742792 | R+1 fini
1743257 | R+1 fini
1743676 | R+1 fini
1744037 | 73
1744314 | 72
1744707 | R+1 fini
1745178 | R+1 fini
1745771 | 69
1746122 | 68
1746569 | R+1 fini
1747684 | R+1 fini
1748533 | 56
1748992 | R+1 fini
1749941 | 61
1750552 | 49
1751683 | R+1 fini
1751784 | 52
1752567 | 53
1753557 | R+1 fini
1754209 | R+1 fini
1754664 | 66
1754907 | 66
1755336 | 67
1755663 | 67
1755928 | R+1 fini
1756411 | R+1 fini
1756710 | 70
1757223 | 70
1757648 | R+1 fini
1757897 | 71
1758298 | 71
1758883 | R+1 fini
1759108 | 74
1759559 | 74
1760044 | R+1 fini
1760740 | 75
1761043 | 75
1761400 | 75
1761837 | 75
1762168 | 73
1762469 | R+1 fini
1762858 | 73
1763437 | R+1 fini
1763930 | 72
1764513 | 72
1764930 | 72
1765125 | 69
1765370 | 69
1765627 | 69
1766094 | R+1 fini
1766413 | 68
1766678 | 68
1766915 | 68
1767264 | 68

# IfcBuildingElementProxy: Electrical_Outlets-Sockets_ELKO_PLUS-switch-2-circuits-screwless-polar-w:Default (6)
In: RDC
Type - Material: PLUS switch 2-circuits screwless polar white - EKO03890 - white
Type - Pset_BuildingElementProxyCommon - IsExternal: no
Pset_BuildingElementProxyCommon - Reference: Default
Pset_EnvironmentalImpactIndicators - Reference: Default
Qto_BuildingElementProxyQuantities - NetSurfaceArea: 0.0387649 m2; NetVolume: 0.000079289 m3
Name (Electrical_Outlets-Sockets_ELKO_PLUS-switch-2-circuits-screwless-polar-w:Default:...)
1160659
1160898
1161299
1161478
1161855
1162070

# IfcBuildingElementProxy: Electrical_Outlets-Sockets_ELKO_Single-socket-outlet-RS16-flush-PureWhit:Default (410)
Type - Material: Single socket outlet RS16 flush PureWhite - EKO07241 - white
Type - Pset_BuildingElementProxyCommon - IsExternal: no
Pset_BuildingElementProxyCommon - Reference: Default
Pset_EnvironmentalImpactIndicators - Reference: Default
Qto_BuildingElementProxyQuantities - NetSurfaceArea: 0.0259509 m2; NetVolume: 0.0000522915 m3
Name (Electrical_Outlets-Sockets_ELKO_Single-socket-outlet-RS16-flush-PureWhit:Default:...) | In
1149916 | 39
1157957 | 39
1157965 | 39
1157975 | 39
1158353 | 39
1158402 | 39
1158483 | 39
1158576 | 39
1158801 | 39
1158995 | RDC
1165972 | 40
1166075 | 40
1166378 | 40
1166489 | 40
1166788 | 40
1166891 | 40
1167018 | 40
1167129 | 40
1167568 | RDC
1168014 | RDC
1170437 | 43
1170576 | 43
1170685 | 43
1170782 | 43
1171548 | 43
1171785 | 43
1171854 | 43
1172145 | 43
1172397 | RDC
1174423 | 44
1174532 | 44
1174661 | 44
1174762 | 44
1175019 | 44
1175250 | 44
1175441 | 44
1175506 | 44
1175695 | 44
1176137 | RDC
1178668 | 47
1178815 | 47
1178914 | 47
1179005 | 47
1179250 | 47
1179496 | RDC
1179792 | 47
1179953 | 47
1180152 | 47
1180241 | 47
1182002 | 46
1182063 | 46
1182110 | 46
1182253 | 46
1182452 | 46
1182565 | 46
1182610 | 46
1182679 | 46
1182816 | 46
1183112 | RDC
1186421 | 45
1186750 | 45
1186867 | 45
1186980 | 45
1187075 | 45
1187376 | 45
1187439 | 45
1187576 | 45
1187681 | 45
1187993 | RDC
1188424 | 42
1188663 | 42
1188760 | 42
1188855 | 42
1188998 | 42
1189141 | 42
1189240 | 42
1189325 | 42
1189400 | 42
1189972 | RDC
1192940 | 41
1193133 | 41
1193286 | 41
1193337 | 41
1193420 | 41
1193485 | 41
1193688 | 41
1193799 | 41
1193902 | 41
1194234 | RDC
1195090 | 32
1195389 | 32
1195466 | 32
1195850 | RDC
1204627 | 18
1204952 | 18
1205007 | 18
1205152 | 33
1205291 | 33
1205352 | 33
1205866 | RDC
1206061 | RDC
1206344 | RDC
1206435 | RDC
1206570 | RDC
1206871 | RDC
1207368 | RDC
1207697 | RDC
1207778 | RDC
1207879 | RDC
1208351 | 18
1208746 | 34
1209053 | 34
1209122 | 35
1209401 | 35
1209460 | 36
1209543 | 36
1209790 | 37
1209879 | 37
1210068 | 37
1210191 | 36
1210518 | 35
1210693 | 34
1211283 | 31
1211420 | 31
1211591 | 30
1211716 | 30
1211781 | 29
1211894 | 29
1212107 | 28
1212172 | 28
1212289 | 27
1212402 | 27
1212688 | 27
1212767 | 28
1212992 | 29
1213483 | 30
1213862 | 31
1214536 | 4
1214711 | RDC
1214784 | 4
1214853 | 4
1215044 | 4
1215115 | 4
1215304 | 4
1215455 | 5
1215670 | 5
1216135 | 5
1216326 | 5
1216415 | 5
1216590 | 5
1216629 | 5
1216676 | 5
1216795 | 5
1216996 | 6
1217245 | 6
1217354 | 6
1217459 | 6
1217646 | 6
1217829 | 6
1217904 | 6
1217959 | 6
1218904 | 7
1218991 | 7
1219030 | 7
1219285 | 7
1219446 | 7
1219515 | 7
1219596 | 7
1219715 | 7
1220166 | 7
1220393 | 10
1220528 | 10
1220569 | 10
1220776 | 10
1220837 | 10
1220924 | 10
1220983 | 10
1221200 | 11
1221327 | 11
1221424 | 11
1221817 | 11
1221834 | 11
1221895 | 11
1221952 | 11
1222097 | 11
1222150 | 11
1222319 | 12
1222374 | 12
1222409 | 12
1223180 | 12
1223464 | 2
1223525 | 2
1223792 | 3
1223861 | 3
1223988 | 1
1224251 | 1
1224320 | 1
1224584 | 1
1224651 | 1
1224698 | 1
1224747 | 1
1224954 | 1
1225053 | 1
1225112 | 1
1225269 | 1
1225440 | 1
1225499 | 1
1225709 | 1
1225938 | 1
1309772 | RDC
1309851 | RDC
1309866 | RDC
1310015 | RDC
1310224 | RDC
1310335 | RDC
1310378 | RDC
1310633 | RDC
1310690 | RDC
1310741 | RDC
1310918 | RDC
1311263 | RDC
1311442 | RDC
1311630 | RDC
1311749 | RDC
1311786 | RDC
1312250 | 19
1312353 | 19
1312672 | 19
1313483 | RDC
1313610 | RDC
1316905 | 18
1317811 | 17
1317908 | 17
1318133 | 17
1318366 | 24
1318479 | 23
1318798 | 21
1318979 | 16
1319152 | 16
1319253 | 16
1319518 | 16
1319723 | 16
1320213 | 26
1320292 | 25
1320429 | RDC
1320814 | 15
1321143 | 15
1321820 | 48
1322097 | 48
1322368 | 13
1443349 | 49
1444538 | 49
1445728 | 49
1447014 | R+1 fini
1447528 | R+1 fini
1448278 | 50
1448791 | 50
1448876 | 50
1450235 | 51
1451390 | 51
1451575 | 51
1452093 | R+1 fini
1452320 | R+1 fini
1452637 | 52
1453246 | 52
1454081 | 52
1454362 | 53
1455420 | R+1 fini
1455988 | 53
1456227 | 53
1456354 | 54
1456685 | 54
1456933 | 54
1457379 | R+1 fini
1458007 | R+1 fini
1458501 | 55
1458662 | 55
1458993 | 55
1459064 | 56
1459629 | 56
1459726 | 56
1460638 | R+1 fini
1460879 | R+1 fini
1462301 | 57
1462668 | 57
1463094 | 57
1463309 | 58
1463708 | 58
1464073 | 58
1464587 | R+1 fini
1464716 | R+1 fini
1465166 | 59
1465427 | 59
1465770 | 59
1465853 | 60
1466466 | 61
1467231 | 61
1467796 | 61
1467877 | 62
1468166 | 62
1469012 | R+1 fini
1469223 | R+1 fini
1469667 | 62
1469976 | 64
1471159 | 63
1471474 | 65
1472103 | 66
1474046 | 66
1474137 | 66
1474470 | 66
1474581 | 66
1475180 | 66
1475277 | 66
1475496 | 66
1475553 | R+1 fini
1476206 | 77
1477147 | 67
1477740 | 67
1478066 | 67
1478325 | 67
1478709 | R+1 fini
1482304 | 67
1482603 | 67
1482864 | 67
1483881 | 67
1484543 | R+1 fini
1485088 | R+1 fini
1485667 | 70
1486158 | 70
1486277 | 70
1486810 | 70
1486909 | R+1 fini
1487496 | 70
1488397 | 70
1488532 | 70
1488801 | 70
1489467 | R+1 fini
1490038 | R+1 fini
1490644 | 71
1490967 | 71
1491310 | 71
1491603 | 71
1492026 | 71
1492464 | 71
1492859 | 71
1492986 | R+1 fini
1494423 | 74
1494754 | 74
1494825 | 74
1495272 | 74
1495470 | 74
1495853 | 74
1495966 | 74
1496559 | 74
1496664 | R+1 fini
1497286 | R+1 fini
1497849 | 75
1498170 | 75
1498613 | 75
1498704 | 75
1499061 | 75
1499154 | 75
1499633 | 75
1499734 | 75
1500047 | 75
1500717 | R+1 fini
1501022 | R+1 fini
1501740 | 73
1502103 | 73
1502202 | 73
1502703 | 73
1502786 | 73
1504347 | 73
1504436 | 73
1504733 | 73
1504882 | 72
1505237 | 72
1505336 | 72
1505691 | 72
1505800 | 72
1506533 | 72
1506650 | 72
1507253 | 72
1507591 | 73
1508206 | 72
1509626 | R+1 fini
1509919 | R+1 fini
1510662 | 69
1510959 | 69
1511178 | 69
1511759 | 69
1511844 | 69
1512375 | 69
1513094 | 69
1513171 | 69
1513822 | 69
1513929 | 68
1514288 | 68
1514421 | 68
1514776 | 68
1514917 | 68
1515851 | R+1 fini
1516577 | 68
1517030 | 68
1517127 | 68
1517646 | 68
1517784 | 77
1729424 | 66
1729432 | 71
1729442 | 74

# IfcBuildingElementProxy: Generic_Summer_Tree_8:Generic_Summer_Tree_8 (2)
In: RDC
Type - Material: <Unnamed>
Type - Pset_BuildingElementProxyCommon - IsExternal: no
Pset_BuildingElementProxyCommon - Reference: Generic_Summer_Tree_8
Pset_EnvironmentalImpactIndicators - Reference: Generic_Summer_Tree_8
Qto_BuildingElementProxyQuantities - NetVolume: 36.8073 m3
Name (Generic_Summer_Tree_8:Generic_Summer_Tree_8:...) | NetSurfaceArea (m2)
1718342 | 9625.2
1718405 | 9625.21

# IfcBuildingElementProxy: Porcher_APPLIQUE-Urinoir-seul:Default (7)
Type - Material: CeramicWhite 9650BEC
Type - Pset_BuildingElementProxyCommon - IsExternal: no
Pset_BuildingElementProxyCommon - Reference: Default
Pset_EnvironmentalImpactIndicators - Reference: Default
Name (Porcher_APPLIQUE-Urinoir-seul:Default:...) | In | NetSurfaceArea (m2) | NetVolume (m3)
1058429 | RDC | 0.521287 | 0.00371267
1058957 | RDC | 0.521287 | 0.00371268
1058967 | RDC | 0.521287 | 0.00371269
1114100 | 24 | 0.521287 | 0.00371271
1262773 | RDC | 0.521288 | 0.00371271
1410220 | 65 | 0.521287 | 0.00371269
1410427 | R+1 fini | 0.521287 | 0.0037127

# IfcBuildingElementProxy: flight_square_shower_tray:Default (44)
Type - Material: ba0d584f_fe2e_4741_8812_9e0282e09522, 201f7047_f655_4de7_ac38_938c31436c9b
Type - Pset_BuildingElementProxyCommon - IsExternal: no
Pset_BuildingElementProxyCommon - Reference: Default
Pset_EnvironmentalImpactIndicators - Reference: Default
Qto_BuildingElementProxyQuantities - NetVolume: 0.0260794 m3
Name (flight_square_shower_tray:Default:...) | In | NetSurfaceArea (m2)
1050406 | RDC | 1.81943
1050692 | RDC | 1.81943
1050988 | RDC | 1.81943
1051059 | RDC | 1.81943
1051164 | RDC | 1.81943
1051301 | RDC | 1.81943
1051444 | RDC | 1.81943
1051561 | RDC | 1.81943
1051569 | RDC | 1.81943
1051577 | RDC | 1.81929
1051587 | RDC | 1.81928
1051911 | RDC | 1.81912
1052655 | RDC | 1.81943
1052665 | RDC | 1.81943
1052673 | RDC | 1.81893
1053862 | RDC | 1.81929
1054070 | RDC | 1.81943
1054078 | RDC | 1.81943
1054086 | RDC | 1.8194
1145299 | RDC | 1.81895
1146282 | RDC | 1.81864
1399749 | R+1 fini | 1.81943
1399827 | R+1 fini | 1.81943
1399901 | R+1 fini | 1.81943
1399978 | R+1 fini | 1.81943
1400052 | R+1 fini | 1.81943
1400156 | R+1 fini | 1.81941
1400266 | R+1 fini | 1.81938
1400595 | R+1 fini | 1.81943
1400699 | R+1 fini | 1.81935
1400790 | R+1 fini | 1.81893
1400847 | R+1 fini | 1.81893
1401948 | R+1 fini | 1.81887
1402055 | R+1 fini | 1.81904
1402119 | R+1 fini | 1.81892
1402276 | R+1 fini | 1.81943
1402332 | R+1 fini | 1.81943
1402390 | R+1 fini | 1.81943
1402441 | R+1 fini | 1.81933
1402763 | R+1 fini | 1.8188
1402821 | R+1 fini | 1.81893
1402913 | R+1 fini | 1.81892
1657257 | R+1 fini | 1.81865
1657267 | R+1 fini | 1.81864

# IfcColumn: P01:P01, P01:P01:338347
In: RDC
Type - PredefinedType: COLUMN; Material: <Unnamed>
Type - Pset_ColumnCommon - IsExternal: no; LoadBearing: yes
Qto_ColumnBaseQuantities - Length: 7.51 m; CrossSectionArea: 0.068 m2; OuterSurfaceArea: 8.1108 m2; GrossVolume: 0.51068 m3; NetVolume: 0.51068 m3
Pset_ColumnCommon - Reference: P01
Pset_EnvironmentalImpactIndicators - Reference: P01; sets with these values: 2

# IfcColumn: P10:P01, P10:P01:573226
In: RDC
Type - PredefinedType: COLUMN; Material: <Unnamed>
Type - Pset_ColumnCommon - IsExternal: no; LoadBearing: yes
Qto_ColumnBaseQuantities - Length: 7.51 m; CrossSectionArea: 0.068 m2; OuterSurfaceArea: 8.1108 m2; GrossVolume: 0.51068 m3; NetVolume: 0.51068 m3
Pset_ColumnCommon - Reference: P01
Pset_EnvironmentalImpactIndicators - Reference: P01; sets with these values: 2

# IfcColumn: P11:P01, P11:P01:573893
In: RDC
Type - PredefinedType: COLUMN; Material: <Unnamed>
Type - Pset_ColumnCommon - IsExternal: no; LoadBearing: yes
Qto_ColumnBaseQuantities - Length: 7.51 m; CrossSectionArea: 0.068 m2; OuterSurfaceArea: 8.1108 m2; GrossVolume: 0.51068 m3; NetVolume: 0.51068 m3
Pset_ColumnCommon - Reference: P01
Pset_EnvironmentalImpactIndicators - Reference: P01; sets with these values: 2

# IfcColumn: P12:P01, P12:P01:970952
In: RDC
Type - PredefinedType: COLUMN; Material: <Unnamed>
Type - Pset_ColumnCommon - IsExternal: no; LoadBearing: yes
Qto_ColumnBaseQuantities - Length: 3.4 m; CrossSectionArea: 0.068 m2; OuterSurfaceArea: 3.672 m2; GrossVolume: 0.2312 m3; NetVolume: 0.2312 m3
Pset_ColumnCommon - Reference: P01
Pset_EnvironmentalImpactIndicators - Reference: P01; sets with these values: 2

# IfcColumn: P13:P01, P13:P01:971308
In: RDC
Type - PredefinedType: COLUMN; Material: <Unnamed>
Type - Pset_ColumnCommon - IsExternal: no; LoadBearing: yes
Qto_ColumnBaseQuantities - Length: 3.4 m; CrossSectionArea: 0.068 m2; OuterSurfaceArea: 3.672 m2; GrossVolume: 0.2312 m3; NetVolume: 0.2312 m3
Pset_ColumnCommon - Reference: P01
Pset_EnvironmentalImpactIndicators - Reference: P01; sets with these values: 2

# IfcColumn: P14:P01, P14:P01:971981
In: RDC
Type - PredefinedType: COLUMN; Material: <Unnamed>
Type - Pset_ColumnCommon - IsExternal: no; LoadBearing: yes
Qto_ColumnBaseQuantities - Length: 3.4 m; CrossSectionArea: 0.068 m2; OuterSurfaceArea: 3.672 m2; GrossVolume: 0.2312 m3; NetVolume: 0.2312 m3
Pset_ColumnCommon - Reference: P01
Pset_EnvironmentalImpactIndicators - Reference: P01; sets with these values: 2

# IfcColumn: P15:P01, P15:P01:972001
In: RDC
Type - PredefinedType: COLUMN; Material: <Unnamed>
Type - Pset_ColumnCommon - IsExternal: no; LoadBearing: yes
Qto_ColumnBaseQuantities - Length: 3.4 m; CrossSectionArea: 0.0686217 m2; OuterSurfaceArea: 3.69314 m2; GrossVolume: 0.233314 m3; NetVolume: 0.233314 m3
Pset_ColumnCommon - Reference: P01
Pset_EnvironmentalImpactIndicators - Reference: P01; sets with these values: 2

# IfcColumn: P16:P01, P16:P01:972488
In: RDC
Type - PredefinedType: COLUMN; Material: <Unnamed>
Type - Pset_ColumnCommon - IsExternal: no; LoadBearing: yes
Qto_ColumnBaseQuantities - Length: 3.4 m; CrossSectionArea: 0.0686217 m2; OuterSurfaceArea: 3.69314 m2; GrossVolume: 0.233314 m3; NetVolume: 0.233314 m3
Pset_ColumnCommon - Reference: P01
Pset_EnvironmentalImpactIndicators - Reference: P01; sets with these values: 2

# IfcColumn: P17:P01, P17:P01:972805
In: RDC
Type - PredefinedType: COLUMN; Material: <Unnamed>
Type - Pset_ColumnCommon - IsExternal: no; LoadBearing: yes
Qto_ColumnBaseQuantities - Length: 3.4 m; CrossSectionArea: 0.0686217 m2; OuterSurfaceArea: 3.69314 m2; GrossVolume: 0.233314 m3; NetVolume: 0.233314 m3
Pset_ColumnCommon - Reference: P01
Pset_EnvironmentalImpactIndicators - Reference: P01; sets with these values: 2

# IfcColumn: P18:P01, P18:P01:973127
In: RDC
Type - PredefinedType: COLUMN; Material: <Unnamed>
Type - Pset_ColumnCommon - IsExternal: no; LoadBearing: yes
Qto_ColumnBaseQuantities - Length: 3.4 m; CrossSectionArea: 0.0686217 m2; OuterSurfaceArea: 3.69314 m2; GrossVolume: 0.233314 m3; NetVolume: 0.233314 m3
Pset_ColumnCommon - Reference: P01
Pset_EnvironmentalImpactIndicators - Reference: P01; sets with these values: 2

# IfcColumn: P19:P01, P19:P01:973333
In: RDC
Type - PredefinedType: COLUMN; Material: <Unnamed>
Type - Pset_ColumnCommon - IsExternal: no; LoadBearing: yes
Qto_ColumnBaseQuantities - Length: 4.39814 m; CrossSectionArea: 0.0621718 m2; OuterSurfaceArea: 4.61198 m2; GrossVolume: 0.27344 m3; NetVolume: 0.27344 m3
Pset_ColumnCommon - Reference: P01
Pset_EnvironmentalImpactIndicators - Reference: P01; sets with these values: 2

# IfcColumn: P1:P01, P1:P01:558573
In: RDC
Type - PredefinedType: COLUMN; Material: <Unnamed>
Type - Pset_ColumnCommon - IsExternal: no; LoadBearing: yes
Qto_ColumnBaseQuantities - Length: 7.51 m; CrossSectionArea: 0.068 m2; OuterSurfaceArea: 8.1108 m2; GrossVolume: 0.51068 m3; NetVolume: 0.51068 m3
Pset_ColumnCommon - Reference: P01
Pset_EnvironmentalImpactIndicators - Reference: P01; sets with these values: 2

# IfcColumn: P20:P01, P20:P01:973715
In: RDC
Type - PredefinedType: COLUMN; Material: <Unnamed>
Type - Pset_ColumnCommon - IsExternal: no; LoadBearing: yes
Qto_ColumnBaseQuantities - Length: 4.39752 m; CrossSectionArea: 0.0648227 m2; OuterSurfaceArea: 4.67928 m2; GrossVolume: 0.285059 m3; NetVolume: 0.285059 m3
Pset_ColumnCommon - Reference: P01
Pset_EnvironmentalImpactIndicators - Reference: P01; sets with these values: 2

# IfcColumn: P21:P01, P21:P01:973735
In: RDC
Type - PredefinedType: COLUMN; Material: <Unnamed>
Type - Pset_ColumnCommon - IsExternal: no; LoadBearing: yes
Qto_ColumnBaseQuantities - Length: 4.39343 m; CrossSectionArea: 0.0649772 m2; OuterSurfaceArea: 4.67888 m2; GrossVolume: 0.285473 m3; NetVolume: 0.285473 m3
Pset_ColumnCommon - Reference: P01
Pset_EnvironmentalImpactIndicators - Reference: P01; sets with these values: 2

# IfcColumn: P22:P01, P22:P01:973753
In: RDC
Type - PredefinedType: COLUMN; Material: <Unnamed>
Type - Pset_ColumnCommon - IsExternal: no; LoadBearing: yes
Qto_ColumnBaseQuantities - Length: 4.39732 m; CrossSectionArea: 0.0649607 m2; OuterSurfaceArea: 4.6826 m2; GrossVolume: 0.285653 m3; NetVolume: 0.285653 m3
Pset_ColumnCommon - Reference: P01
Pset_EnvironmentalImpactIndicators - Reference: P01; sets with these values: 2

# IfcColumn: P23:P01, P23:P01:974791
In: RDC
Type - PredefinedType: COLUMN; Material: <Unnamed>
Type - Pset_ColumnCommon - IsExternal: no; LoadBearing: yes
Qto_ColumnBaseQuantities - Length: 4.39216 m; CrossSectionArea: 0.0686217 m2; OuterSurfaceArea: 4.77084 m2; GrossVolume: 0.301397 m3; NetVolume: 0.301397 m3
Pset_ColumnCommon - Reference: P01
Pset_EnvironmentalImpactIndicators - Reference: P01; sets with these values: 2

# IfcColumn: P24:P01, P24:P01:975086
In: RDC
Type - PredefinedType: COLUMN; Material: <Unnamed>
Type - Pset_ColumnCommon - IsExternal: no; LoadBearing: yes
Qto_ColumnBaseQuantities - Length: 4.38851 m; CrossSectionArea: 0.0686217 m2; OuterSurfaceArea: 4.76687 m2; GrossVolume: 0.301147 m3; NetVolume: 0.301147 m3
Pset_ColumnCommon - Reference: P01
Pset_EnvironmentalImpactIndicators - Reference: P01; sets with these values: 2

# IfcColumn: P25:P01, P25:P01:976207
In: RDC
Type - PredefinedType: COLUMN; Material: <Unnamed>
Type - Pset_ColumnCommon - IsExternal: no; LoadBearing: yes
Qto_ColumnBaseQuantities - Length: 4.39161 m; CrossSectionArea: 0.0686217 m2; OuterSurfaceArea: 4.77024 m2; GrossVolume: 0.30136 m3; NetVolume: 0.30136 m3
Pset_ColumnCommon - Reference: P01
Pset_EnvironmentalImpactIndicators - Reference: P01; sets with these values: 2

# IfcColumn: P26:P01, P26:P01:976577
In: RDC
Type - PredefinedType: COLUMN; Material: <Unnamed>
Type - Pset_ColumnCommon - IsExternal: no; LoadBearing: yes
Qto_ColumnBaseQuantities - Length: 4.40071 m; CrossSectionArea: 0.0686217 m2; OuterSurfaceArea: 4.78012 m2; GrossVolume: 0.301984 m3; NetVolume: 0.301984 m3
Pset_ColumnCommon - Reference: P01
Pset_EnvironmentalImpactIndicators - Reference: P01; sets with these values: 2

# IfcColumn: P27:P01, P27:P01:977055
In: RDC
Type - PredefinedType: COLUMN; Material: <Unnamed>
Type - Pset_ColumnCommon - IsExternal: no; LoadBearing: yes
Qto_ColumnBaseQuantities - Length: 4.39674 m; CrossSectionArea: 0.0686217 m2; OuterSurfaceArea: 4.77582 m2; GrossVolume: 0.301712 m3; NetVolume: 0.301712 m3
Pset_ColumnCommon - Reference: P01
Pset_EnvironmentalImpactIndicators - Reference: P01; sets with these values: 2

# IfcColumn: P28:P01, P28:P01:978856
In: RDC
Type - PredefinedType: COLUMN; Material: <Unnamed>
Type - Pset_ColumnCommon - IsExternal: no; LoadBearing: yes
Qto_ColumnBaseQuantities - Length: 4.38493 m; CrossSectionArea: 0.0686217 m2; OuterSurfaceArea: 4.76298 m2; GrossVolume: 0.300901 m3; NetVolume: 0.300901 m3
Pset_ColumnCommon - Reference: P01
Pset_EnvironmentalImpactIndicators - Reference: P01; sets with these values: 2

# IfcColumn: P2:P01, P2:P01:558919
In: RDC
Type - PredefinedType: COLUMN; Material: <Unnamed>
Type - Pset_ColumnCommon - IsExternal: no; LoadBearing: yes
Qto_ColumnBaseQuantities - Length: 7.51 m; CrossSectionArea: 0.068 m2; OuterSurfaceArea: 8.1108 m2; GrossVolume: 0.51068 m3; NetVolume: 0.51068 m3
Pset_ColumnCommon - Reference: P01
Pset_EnvironmentalImpactIndicators - Reference: P01; sets with these values: 2

# IfcColumn: P3:P01, P3:P01:560454
In: RDC
Type - PredefinedType: COLUMN; Material: <Unnamed>
Type - Pset_ColumnCommon - IsExternal: no; LoadBearing: yes
Qto_ColumnBaseQuantities - Length: 7.51 m; CrossSectionArea: 0.068 m2; OuterSurfaceArea: 8.1108 m2; GrossVolume: 0.51068 m3; NetVolume: 0.51068 m3
Pset_ColumnCommon - Reference: P01
Pset_EnvironmentalImpactIndicators - Reference: P01; sets with these values: 2

# IfcColumn: P4:P01, P4:P01:569721
In: RDC
Type - PredefinedType: COLUMN; Material: <Unnamed>
Type - Pset_ColumnCommon - IsExternal: no; LoadBearing: yes
Qto_ColumnBaseQuantities - Length: 7.51 m; CrossSectionArea: 0.068 m2; OuterSurfaceArea: 8.1108 m2; GrossVolume: 0.51068 m3; NetVolume: 0.51068 m3
Pset_ColumnCommon - Reference: P01
Pset_EnvironmentalImpactIndicators - Reference: P01; sets with these values: 2

# IfcColumn: P5:P01, P5:P01:570127
In: RDC
Type - PredefinedType: COLUMN; Material: <Unnamed>
Type - Pset_ColumnCommon - IsExternal: no; LoadBearing: yes
Qto_ColumnBaseQuantities - Length: 7.51 m; CrossSectionArea: 0.068 m2; OuterSurfaceArea: 8.1108 m2; GrossVolume: 0.51068 m3; NetVolume: 0.51068 m3
Pset_ColumnCommon - Reference: P01
Pset_EnvironmentalImpactIndicators - Reference: P01; sets with these values: 2

# IfcColumn: P6:P01, P6:P01:570771
In: RDC
Type - PredefinedType: COLUMN; Material: <Unnamed>
Type - Pset_ColumnCommon - IsExternal: no; LoadBearing: yes
Qto_ColumnBaseQuantities - Length: 7.51 m; CrossSectionArea: 0.068 m2; OuterSurfaceArea: 8.1108 m2; GrossVolume: 0.51068 m3; NetVolume: 0.51068 m3
Pset_ColumnCommon - Reference: P01
Pset_EnvironmentalImpactIndicators - Reference: P01; sets with these values: 2

# IfcColumn: P7:P01, P7:P01:571499
In: RDC
Type - PredefinedType: COLUMN; Material: <Unnamed>
Type - Pset_ColumnCommon - IsExternal: no; LoadBearing: yes
Qto_ColumnBaseQuantities - Length: 7.51 m; CrossSectionArea: 0.068 m2; OuterSurfaceArea: 8.1108 m2; GrossVolume: 0.51068 m3; NetVolume: 0.51068 m3
Pset_ColumnCommon - Reference: P01
Pset_EnvironmentalImpactIndicators - Reference: P01; sets with these values: 2

# IfcColumn: P8:P01, P8:P01:571884
In: RDC
Type - PredefinedType: COLUMN; Material: <Unnamed>
Type - Pset_ColumnCommon - IsExternal: no; LoadBearing: yes
Qto_ColumnBaseQuantities - Length: 7.51 m; CrossSectionArea: 0.068 m2; OuterSurfaceArea: 8.1108 m2; GrossVolume: 0.51068 m3; NetVolume: 0.51068 m3
Pset_ColumnCommon - Reference: P01
Pset_EnvironmentalImpactIndicators - Reference: P01; sets with these values: 2

# IfcColumn: P9:P01, P9:P01:572352
In: RDC
Type - PredefinedType: COLUMN; Material: <Unnamed>
Type - Pset_ColumnCommon - IsExternal: no; LoadBearing: yes
Qto_ColumnBaseQuantities - Length: 7.51 m; CrossSectionArea: 0.068 m2; OuterSurfaceArea: 8.1108 m2; GrossVolume: 0.51068 m3; NetVolume: 0.51068 m3
Pset_ColumnCommon - Reference: P01
Pset_EnvironmentalImpactIndicators - Reference: P01; sets with these values: 2

# IfcColumn: Poteaux support métallique10:Poteaux support métallique, Poteaux support métallique10:Poteaux support métallique:1629356
In: Arase inf longrines
Type - PredefinedType: COLUMN; Material: Maçonnerie - Béton
Type - Pset_ColumnCommon - IsExternal: no
Qto_ColumnBaseQuantities - Length: 3.33465 m; CrossSectionArea: 0.0628235 m2; OuterSurfaceArea: 2.9631 m2; GrossVolume: 0.209495 m3; NetVolume: 0.209513 m3
Pset_ColumnCommon - Reference: Poteaux support métallique
Pset_EnvironmentalImpactIndicators - Reference: Poteaux support métallique; sets with these values: 2

# IfcColumn: Poteaux support métallique11:Poteaux support métallique, Poteaux support métallique11:Poteaux support métallique:1629373
In: Arase inf longrines
Type - PredefinedType: COLUMN; Material: Maçonnerie - Béton
Type - Pset_ColumnCommon - IsExternal: no
Qto_ColumnBaseQuantities - Length: 3.35323 m; CrossSectionArea: 0.0628235 m2; OuterSurfaceArea: 2.97961 m2; GrossVolume: 0.210662 m3; NetVolume: 0.21068 m3
Pset_ColumnCommon - Reference: Poteaux support métallique
Pset_EnvironmentalImpactIndicators - Reference: Poteaux support métallique; sets with these values: 2

# IfcColumn: Poteaux support métallique12:Poteaux support métallique, Poteaux support métallique12:Poteaux support métallique:1629538
In: Arase inf longrines
Type - PredefinedType: COLUMN; Material: Maçonnerie - Béton
Type - Pset_ColumnCommon - IsExternal: no
Qto_ColumnBaseQuantities - Length: 3.34392 m; CrossSectionArea: 0.0628235 m2; OuterSurfaceArea: 2.97133 m2; GrossVolume: 0.210077 m3; NetVolume: 0.210095 m3
Pset_ColumnCommon - Reference: Poteaux support métallique
Pset_EnvironmentalImpactIndicators - Reference: Poteaux support métallique; sets with these values: 2

# IfcColumn: Poteaux support métallique13:Poteaux support métallique, Poteaux support métallique13:Poteaux support métallique:1629591
In: Arase inf longrines
Type - PredefinedType: COLUMN; Material: Maçonnerie - Béton
Type - Pset_ColumnCommon - IsExternal: no
Qto_ColumnBaseQuantities - Length: 8.13319 m; CrossSectionArea: 0.0628235 m2; OuterSurfaceArea: 7.22697 m2; GrossVolume: 0.510955 m3; NetVolume: 0.510999 m3
Pset_ColumnCommon - Reference: Poteaux support métallique
Pset_EnvironmentalImpactIndicators - Reference: Poteaux support métallique; sets with these values: 2

# IfcColumn: Poteaux support métallique14:Poteaux support métallique, Poteaux support métallique14:Poteaux support métallique:1629606
In: Arase inf longrines
Type - PredefinedType: COLUMN; Material: Maçonnerie - Béton
Type - Pset_ColumnCommon - IsExternal: no
Qto_ColumnBaseQuantities - Length: 8.13318 m; CrossSectionArea: 0.0628235 m2; OuterSurfaceArea: 7.22695 m2; GrossVolume: 0.510954 m3; NetVolume: 0.510998 m3
Pset_ColumnCommon - Reference: Poteaux support métallique
Pset_EnvironmentalImpactIndicators - Reference: Poteaux support métallique; sets with these values: 2

# IfcColumn: Poteaux support métallique15:Poteaux support métallique, Poteaux support métallique15:Poteaux support métallique:1629623
In: Arase inf longrines
Type - PredefinedType: COLUMN; Material: Maçonnerie - Béton
Type - Pset_ColumnCommon - IsExternal: no
Qto_ColumnBaseQuantities - Length: 8.13254 m; CrossSectionArea: 0.0628235 m2; OuterSurfaceArea: 7.22639 m2; GrossVolume: 0.510914 m3; NetVolume: 0.510958 m3
Pset_ColumnCommon - Reference: Poteaux support métallique
Pset_EnvironmentalImpactIndicators - Reference: Poteaux support métallique; sets with these values: 2

# IfcColumn: Poteaux support métallique16:Poteaux support métallique, Poteaux support métallique16:Poteaux support métallique:1629638
In: Arase inf longrines
Type - PredefinedType: COLUMN; Material: Maçonnerie - Béton
Type - Pset_ColumnCommon - IsExternal: no
Qto_ColumnBaseQuantities - Length: 8.13693 m; CrossSectionArea: 0.0628235 m2; OuterSurfaceArea: 7.23029 m2; GrossVolume: 0.51119 m3; NetVolume: 0.511234 m3
Pset_ColumnCommon - Reference: Poteaux support métallique
Pset_EnvironmentalImpactIndicators - Reference: Poteaux support métallique; sets with these values: 2

# IfcColumn: Poteaux support métallique17:Poteaux support métallique, Poteaux support métallique17:Poteaux support métallique:1629655
In: Arase inf longrines
Type - PredefinedType: COLUMN; Material: Maçonnerie - Béton
Type - Pset_ColumnCommon - IsExternal: no
Qto_ColumnBaseQuantities - Length: 8.14792 m; CrossSectionArea: 0.0628235 m2; OuterSurfaceArea: 7.24005 m2; GrossVolume: 0.51188 m3; NetVolume: 0.511925 m3
Pset_ColumnCommon - Reference: Poteaux support métallique
Pset_EnvironmentalImpactIndicators - Reference: Poteaux support métallique; sets with these values: 2

# IfcColumn: Poteaux support métallique18:Poteaux support métallique, Poteaux support métallique18:Poteaux support métallique:1629670
In: Arase inf longrines
Type - PredefinedType: COLUMN; Material: Maçonnerie - Béton
Type - Pset_ColumnCommon - IsExternal: no
Qto_ColumnBaseQuantities - Length: 8.13573 m; CrossSectionArea: 0.0628235 m2; OuterSurfaceArea: 7.22922 m2; GrossVolume: 0.511115 m3; NetVolume: 0.511159 m3
Pset_ColumnCommon - Reference: Poteaux support métallique
Pset_EnvironmentalImpactIndicators - Reference: Poteaux support métallique; sets with these values: 2

# IfcColumn: Poteaux support métallique19:Poteaux support métallique, Poteaux support métallique19:Poteaux support métallique:1629687
In: Arase inf longrines
Type - PredefinedType: COLUMN; Material: Maçonnerie - Béton
Type - Pset_ColumnCommon - IsExternal: no
Qto_ColumnBaseQuantities - Length: 8.13037 m; CrossSectionArea: 0.0628235 m2; OuterSurfaceArea: 7.22446 m2; GrossVolume: 0.510778 m3; NetVolume: 0.510822 m3
Pset_ColumnCommon - Reference: Poteaux support métallique
Pset_EnvironmentalImpactIndicators - Reference: Poteaux support métallique; sets with these values: 2

# IfcColumn: Poteaux support métallique1:Poteaux support métallique, Poteaux support métallique1:Poteaux support métallique:1629158
In: Arase inf longrines
Type - PredefinedType: COLUMN; Material: Maçonnerie - Béton
Type - Pset_ColumnCommon - IsExternal: no
Qto_ColumnBaseQuantities - Length: 3.35312 m; CrossSectionArea: 0.0628235 m2; OuterSurfaceArea: 2.9795 m2; GrossVolume: 0.210654 m3; NetVolume: 0.210673 m3
Pset_ColumnCommon - Reference: Poteaux support métallique
Pset_EnvironmentalImpactIndicators - Reference: Poteaux support métallique; sets with these values: 2

# IfcColumn: Poteaux support métallique20:Poteaux support métallique, Poteaux support métallique20:Poteaux support métallique:1629702
In: Arase inf longrines
Type - PredefinedType: COLUMN; Material: Maçonnerie - Béton
Type - Pset_ColumnCommon - IsExternal: no
Qto_ColumnBaseQuantities - Length: 8.14424 m; CrossSectionArea: 0.0628235 m2; OuterSurfaceArea: 7.23678 m2; GrossVolume: 0.511649 m3; NetVolume: 0.511693 m3
Pset_ColumnCommon - Reference: Poteaux support métallique
Pset_EnvironmentalImpactIndicators - Reference: Poteaux support métallique; sets with these values: 2

# IfcColumn: Poteaux support métallique21:Poteaux support métallique, Poteaux support métallique21:Poteaux support métallique:1629717
In: Arase inf longrines
Type - PredefinedType: COLUMN; Material: Maçonnerie - Béton
Type - Pset_ColumnCommon - IsExternal: no
Qto_ColumnBaseQuantities - Length: 8.1332 m; CrossSectionArea: 0.0628235 m2; OuterSurfaceArea: 7.22697 m2; GrossVolume: 0.510955 m3; NetVolume: 0.511 m3
Pset_ColumnCommon - Reference: Poteaux support métallique
Pset_EnvironmentalImpactIndicators - Reference: Poteaux support métallique; sets with these values: 2

# IfcColumn: Poteaux support métallique22:Poteaux support métallique, Poteaux support métallique22:Poteaux support métallique:1629732
In: Arase inf longrines
Type - PredefinedType: COLUMN; Material: Maçonnerie - Béton
Type - Pset_ColumnCommon - IsExternal: no
Qto_ColumnBaseQuantities - Length: 8.13414 m; CrossSectionArea: 0.0628235 m2; OuterSurfaceArea: 7.22781 m2; GrossVolume: 0.511015 m3; NetVolume: 0.511059 m3
Pset_ColumnCommon - Reference: Poteaux support métallique
Pset_EnvironmentalImpactIndicators - Reference: Poteaux support métallique; sets with these values: 2

# IfcColumn: Poteaux support métallique23:Poteaux support métallique, Poteaux support métallique23:Poteaux support métallique:1629747
In: Arase inf longrines
Type - PredefinedType: COLUMN; Material: Maçonnerie - Béton
Type - Pset_ColumnCommon - IsExternal: no
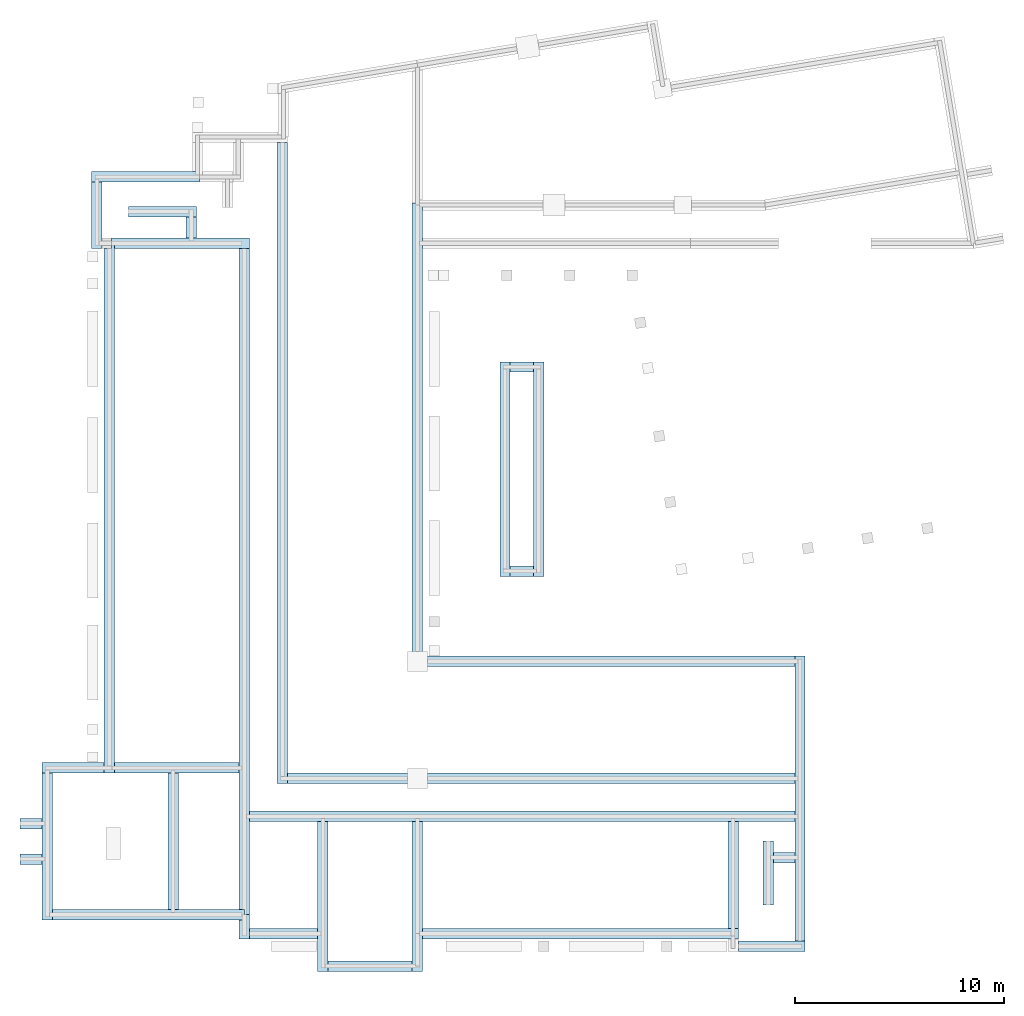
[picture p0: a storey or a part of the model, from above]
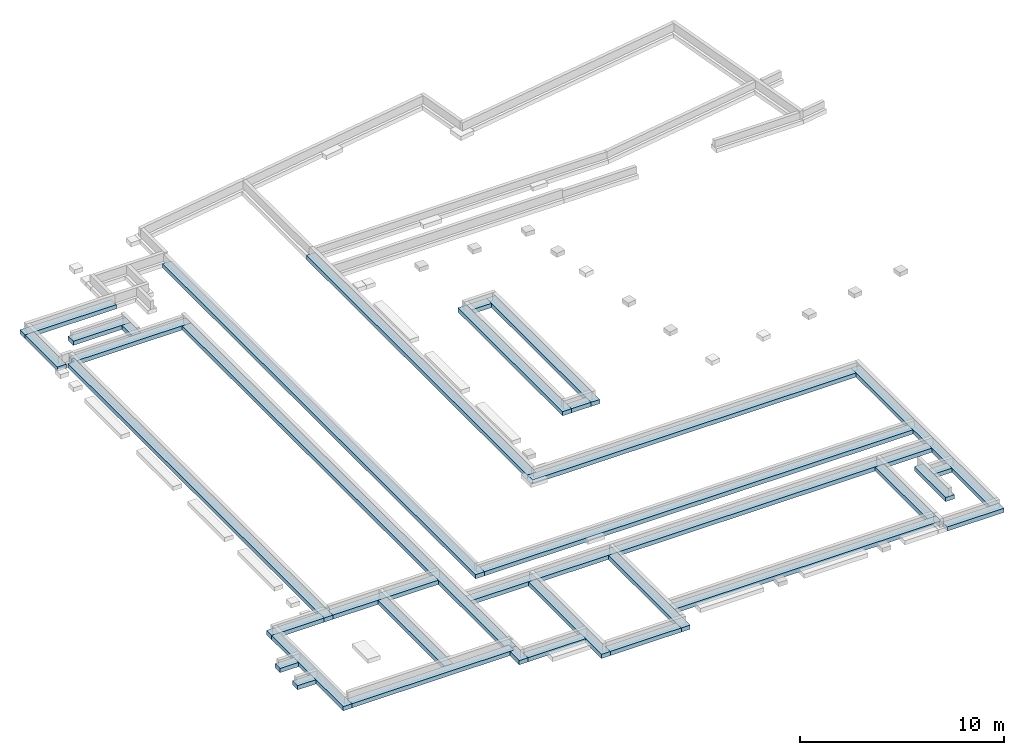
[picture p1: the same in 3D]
Properties of the parts of a building model (IFC4), part 2 of 5

# IfcColumn: Poteaux support métallique23:Poteaux support métallique, Poteaux support métallique23:Poteaux support métallique:1629747
Qto_ColumnBaseQuantities - Length: 8.1483 m; CrossSectionArea: 0.0628235 m2; OuterSurfaceArea: 7.24038 m2; GrossVolume: 0.511904 m3; NetVolume: 0.511948 m3
Pset_ColumnCommon - Reference: Poteaux support métallique
Pset_EnvironmentalImpactIndicators - Reference: Poteaux support métallique; sets with these values: 2

# IfcColumn: Poteaux support métallique24:Poteaux support métallique, Poteaux support métallique24:Poteaux support métallique:1629936
In: Arase inf longrines
Type - PredefinedType: COLUMN; Material: Maçonnerie - Béton
Type - Pset_ColumnCommon - IsExternal: no
Qto_ColumnBaseQuantities - Length: 4.16067 m; CrossSectionArea: 0.0628235 m2; OuterSurfaceArea: 3.69707 m2; GrossVolume: 0.261388 m3; NetVolume: 0.26141 m3
Pset_ColumnCommon - Reference: Poteaux support métallique
Pset_EnvironmentalImpactIndicators - Reference: Poteaux support métallique; sets with these values: 2

# IfcColumn: Poteaux support métallique25:Poteaux support métallique, Poteaux support métallique25:Poteaux support métallique:1629953
In: Arase inf longrines
Type - PredefinedType: COLUMN; Material: Maçonnerie - Béton
Type - Pset_ColumnCommon - IsExternal: no
Qto_ColumnBaseQuantities - Length: 4.14475 m; CrossSectionArea: 0.0628235 m2; OuterSurfaceArea: 3.68293 m2; GrossVolume: 0.260387 m3; NetVolume: 0.26041 m3
Pset_ColumnCommon - Reference: Poteaux support métallique
Pset_EnvironmentalImpactIndicators - Reference: Poteaux support métallique; sets with these values: 2

# IfcColumn: Poteaux support métallique26:Poteaux support métallique, Poteaux support métallique26:Poteaux support métallique:1629968
In: Arase inf longrines
Type - PredefinedType: COLUMN; Material: Maçonnerie - Béton
Type - Pset_ColumnCommon - IsExternal: no
Qto_ColumnBaseQuantities - Length: 4.13504 m; CrossSectionArea: 0.0628235 m2; OuterSurfaceArea: 3.6743 m2; GrossVolume: 0.259777 m3; NetVolume: 0.2598 m3
Pset_ColumnCommon - Reference: Poteaux support métallique
Pset_EnvironmentalImpactIndicators - Reference: Poteaux support métallique; sets with these values: 2

# IfcColumn: Poteaux support métallique27:Poteaux support métallique, Poteaux support métallique27:Poteaux support métallique:1629989
In: Arase inf longrines
Type - PredefinedType: COLUMN; Material: Maçonnerie - Béton
Type - Pset_ColumnCommon - IsExternal: no
Qto_ColumnBaseQuantities - Length: 8.12732 m; CrossSectionArea: 0.0628235 m2; OuterSurfaceArea: 7.22175 m2; GrossVolume: 0.510586 m3; NetVolume: 0.51063 m3
Pset_ColumnCommon - Reference: Poteaux support métallique
Pset_EnvironmentalImpactIndicators - Reference: Poteaux support métallique; sets with these values: 2

# IfcColumn: Poteaux support métallique28:Poteaux support métallique, Poteaux support métallique28:Poteaux support métallique:1630004
In: Arase inf longrines
Type - PredefinedType: COLUMN; Material: Maçonnerie - Béton
Type - Pset_ColumnCommon - IsExternal: no
Qto_ColumnBaseQuantities - Length: 8.15699 m; CrossSectionArea: 0.0628235 m2; OuterSurfaceArea: 7.24811 m2; GrossVolume: 0.51245 m3; NetVolume: 0.512495 m3
Pset_ColumnCommon - Reference: Poteaux support métallique
Pset_EnvironmentalImpactIndicators - Reference: Poteaux support métallique; sets with these values: 2

# IfcColumn: Poteaux support métallique29:Poteaux support métallique, Poteaux support métallique29:Poteaux support métallique:1630023
In: Arase inf longrines
Type - PredefinedType: COLUMN; Material: Maçonnerie - Béton
Type - Pset_ColumnCommon - IsExternal: no
Qto_ColumnBaseQuantities - Length: 8.13044 m; CrossSectionArea: 0.0628235 m2; OuterSurfaceArea: 7.22452 m2; GrossVolume: 0.510782 m3; NetVolume: 0.510826 m3
Pset_ColumnCommon - Reference: Poteaux support métallique
Pset_EnvironmentalImpactIndicators - Reference: Poteaux support métallique; sets with these values: 2

# IfcColumn: Poteaux support métallique2:Poteaux support métallique, Poteaux support métallique2:Poteaux support métallique:1629232
In: Arase inf longrines
Type - PredefinedType: COLUMN; Material: Maçonnerie - Béton
Type - Pset_ColumnCommon - IsExternal: no
Qto_ColumnBaseQuantities - Length: 3.34696 m; CrossSectionArea: 0.0628235 m2; OuterSurfaceArea: 2.97403 m2; GrossVolume: 0.210268 m3; NetVolume: 0.210286 m3
Pset_ColumnCommon - Reference: Poteaux support métallique
Pset_EnvironmentalImpactIndicators - Reference: Poteaux support métallique; sets with these values: 2

# IfcColumn: Poteaux support métallique30:Poteaux support métallique, Poteaux support métallique30:Poteaux support métallique:1630040
In: Arase inf longrines
Type - PredefinedType: COLUMN; Material: Maçonnerie - Béton
Type - Pset_ColumnCommon - IsExternal: no
Qto_ColumnBaseQuantities - Length: 8.13044 m; CrossSectionArea: 0.0628235 m2; OuterSurfaceArea: 7.22452 m2; GrossVolume: 0.510782 m3; NetVolume: 0.510826 m3
Pset_ColumnCommon - Reference: Poteaux support métallique
Pset_EnvironmentalImpactIndicators - Reference: Poteaux support métallique; sets with these values: 2

# IfcColumn: Poteaux support métallique31:Poteaux support métallique, Poteaux support métallique31:Poteaux support métallique:1630057
In: Arase inf longrines
Type - PredefinedType: COLUMN; Material: Maçonnerie - Béton
Type - Pset_ColumnCommon - IsExternal: no
Qto_ColumnBaseQuantities - Length: 8.13696 m; CrossSectionArea: 0.0628235 m2; OuterSurfaceArea: 7.23031 m2; GrossVolume: 0.511192 m3; NetVolume: 0.511236 m3
Pset_ColumnCommon - Reference: Poteaux support métallique
Pset_EnvironmentalImpactIndicators - Reference: Poteaux support métallique; sets with these values: 2

# IfcColumn: Poteaux support métallique32:Poteaux support métallique, Poteaux support métallique32:Poteaux support métallique:1630076
In: Arase inf longrines
Type - PredefinedType: COLUMN; Material: Maçonnerie - Béton
Type - Pset_ColumnCommon - IsExternal: no
Qto_ColumnBaseQuantities - Length: 8.14946 m; CrossSectionArea: 0.0628235 m2; OuterSurfaceArea: 7.24142 m2; GrossVolume: 0.511977 m3; NetVolume: 0.512022 m3
Pset_ColumnCommon - Reference: Poteaux support métallique
Pset_EnvironmentalImpactIndicators - Reference: Poteaux support métallique; sets with these values: 2

# IfcColumn: Poteaux support métallique33:Poteaux support métallique, Poteaux support métallique33:Poteaux support métallique:1630091
In: Arase inf longrines
Type - PredefinedType: COLUMN; Material: Maçonnerie - Béton
Type - Pset_ColumnCommon - IsExternal: no
Qto_ColumnBaseQuantities - Length: 8.1472 m; CrossSectionArea: 0.0628235 m2; OuterSurfaceArea: 7.23941 m2; GrossVolume: 0.511835 m3; NetVolume: 0.511879 m3
Pset_ColumnCommon - Reference: Poteaux support métallique
Pset_EnvironmentalImpactIndicators - Reference: Poteaux support métallique; sets with these values: 2

# IfcColumn: Poteaux support métallique34:Poteaux support métallique, Poteaux support métallique34:Poteaux support métallique:1630106
In: Arase inf longrines
Type - PredefinedType: COLUMN; Material: Maçonnerie - Béton
Type - Pset_ColumnCommon - IsExternal: no
Qto_ColumnBaseQuantities - Length: 8.19522 m; CrossSectionArea: 0.0628235 m2; OuterSurfaceArea: 7.28208 m2; GrossVolume: 0.514852 m3; NetVolume: 0.514896 m3
Pset_ColumnCommon - Reference: Poteaux support métallique
Pset_EnvironmentalImpactIndicators - Reference: Poteaux support métallique; sets with these values: 2

# IfcColumn: Poteaux support métallique35:Poteaux support métallique, Poteaux support métallique35:Poteaux support métallique:1630125
In: Arase inf longrines
Type - PredefinedType: COLUMN; Material: Maçonnerie - Béton
Type - Pset_ColumnCommon - IsExternal: no
Qto_ColumnBaseQuantities - Length: 8.13653 m; CrossSectionArea: 0.0628235 m2; OuterSurfaceArea: 7.22993 m2; GrossVolume: 0.511165 m3; NetVolume: 0.511209 m3
Pset_ColumnCommon - Reference: Poteaux support métallique
Pset_EnvironmentalImpactIndicators - Reference: Poteaux support métallique; sets with these values: 2

# IfcColumn: Poteaux support métallique36:Poteaux support métallique, Poteaux support métallique36:Poteaux support métallique:1630140
In: Arase inf longrines
Type - PredefinedType: COLUMN; Material: Maçonnerie - Béton
Type - Pset_ColumnCommon - IsExternal: no
Qto_ColumnBaseQuantities - Length: 8.1484 m; CrossSectionArea: 0.0628235 m2; OuterSurfaceArea: 7.24047 m2; GrossVolume: 0.51191 m3; NetVolume: 0.511954 m3
Pset_ColumnCommon - Reference: Poteaux support métallique
Pset_EnvironmentalImpactIndicators - Reference: Poteaux support métallique; sets with these values: 2

# IfcColumn: Poteaux support métallique37:Poteaux support métallique, Poteaux support métallique37:Poteaux support métallique:1630157
In: Arase inf longrines
Type - PredefinedType: COLUMN; Material: Maçonnerie - Béton
Type - Pset_ColumnCommon - IsExternal: no
Qto_ColumnBaseQuantities - Length: 8.12167 m; CrossSectionArea: 0.0628235 m2; OuterSurfaceArea: 7.21672 m2; GrossVolume: 0.510231 m3; NetVolume: 0.510275 m3
Pset_ColumnCommon - Reference: Poteaux support métallique
Pset_EnvironmentalImpactIndicators - Reference: Poteaux support métallique; sets with these values: 2

# IfcColumn: Poteaux support métallique38:Poteaux support métallique, Poteaux support métallique38:Poteaux support métallique:1630172
In: Arase inf longrines
Type - PredefinedType: COLUMN; Material: Maçonnerie - Béton
Type - Pset_ColumnCommon - IsExternal: no
Qto_ColumnBaseQuantities - Length: 8.1503 m; CrossSectionArea: 0.0628235 m2; OuterSurfaceArea: 7.24216 m2; GrossVolume: 0.51203 m3; NetVolume: 0.512074 m3
Pset_ColumnCommon - Reference: Poteaux support métallique
Pset_EnvironmentalImpactIndicators - Reference: Poteaux support métallique; sets with these values: 2

# IfcColumn: Poteaux support métallique39:Poteaux support métallique, Poteaux support métallique39:Poteaux support métallique:1630187
In: Arase inf longrines
Type - PredefinedType: COLUMN; Material: Maçonnerie - Béton
Type - Pset_ColumnCommon - IsExternal: no
Qto_ColumnBaseQuantities - Length: 8.16632 m; CrossSectionArea: 0.0628235 m2; OuterSurfaceArea: 7.2564 m2; GrossVolume: 0.513036 m3; NetVolume: 0.513081 m3
Pset_ColumnCommon - Reference: Poteaux support métallique
Pset_EnvironmentalImpactIndicators - Reference: Poteaux support métallique; sets with these values: 2

# IfcColumn: Poteaux support métallique3:Poteaux support métallique, Poteaux support métallique3:Poteaux support métallique:1629247
In: Arase inf longrines
Type - PredefinedType: COLUMN; Material: Maçonnerie - Béton
Type - Pset_ColumnCommon - IsExternal: no
Qto_ColumnBaseQuantities - Length: 3.36218 m; CrossSectionArea: 0.0628235 m2; OuterSurfaceArea: 2.98755 m2; GrossVolume: 0.211224 m3; NetVolume: 0.211242 m3
Pset_ColumnCommon - Reference: Poteaux support métallique
Pset_EnvironmentalImpactIndicators - Reference: Poteaux support métallique; sets with these values: 2

# IfcColumn: Poteaux support métallique40:Poteaux support métallique, Poteaux support métallique40:Poteaux support métallique:1630202
In: Arase inf longrines
Type - PredefinedType: COLUMN; Material: Maçonnerie - Béton
Type - Pset_ColumnCommon - IsExternal: no
Qto_ColumnBaseQuantities - Length: 8.15328 m; CrossSectionArea: 0.0628235 m2; OuterSurfaceArea: 7.24481 m2; GrossVolume: 0.512217 m3; NetVolume: 0.512261 m3
Pset_ColumnCommon - Reference: Poteaux support métallique
Pset_EnvironmentalImpactIndicators - Reference: Poteaux support métallique; sets with these values: 2

# IfcColumn: Poteaux support métallique41:Poteaux support métallique, Poteaux support métallique41:Poteaux support métallique:1631169
In: Arase inf longrines
Type - PredefinedType: COLUMN; Material: Maçonnerie - Béton
Type - Pset_ColumnCommon - IsExternal: no
Qto_ColumnBaseQuantities - Length: 8.15047 m; CrossSectionArea: 0.0628235 m2; OuterSurfaceArea: 7.24232 m2; GrossVolume: 0.512041 m3; NetVolume: 0.512085 m3
Pset_ColumnCommon - Reference: Poteaux support métallique
Pset_EnvironmentalImpactIndicators - Reference: Poteaux support métallique; sets with these values: 2

# IfcColumn: Poteaux support métallique42:Poteaux support métallique, Poteaux support métallique42:Poteaux support métallique:1630274
In: Arase inf longrines
Type - PredefinedType: COLUMN; Material: Maçonnerie - Béton
Type - Pset_ColumnCommon - IsExternal: no
Qto_ColumnBaseQuantities - Length: 8.15908 m; CrossSectionArea: 0.0628235 m2; OuterSurfaceArea: 7.24997 m2; GrossVolume: 0.512581 m3; NetVolume: 0.512626 m3
Pset_ColumnCommon - Reference: Poteaux support métallique
Pset_EnvironmentalImpactIndicators - Reference: Poteaux support métallique; sets with these values: 2

# IfcColumn: Poteaux support métallique43:Poteaux support métallique, Poteaux support métallique43:Poteaux support métallique:1630289
In: Arase inf longrines
Type - PredefinedType: COLUMN; Material: Maçonnerie - Béton
Type - Pset_ColumnCommon - IsExternal: no
Qto_ColumnBaseQuantities - Length: 8.14542 m; CrossSectionArea: 0.0628235 m2; OuterSurfaceArea: 7.23783 m2; GrossVolume: 0.511723 m3; NetVolume: 0.511767 m3
Pset_ColumnCommon - Reference: Poteaux support métallique
Pset_EnvironmentalImpactIndicators - Reference: Poteaux support métallique; sets with these values: 2

# IfcColumn: Poteaux support métallique44:Poteaux support métallique, Poteaux support métallique44:Poteaux support métallique:1630302
In: RDC
Type - PredefinedType: COLUMN; Material: Maçonnerie - Béton
Type - Pset_ColumnCommon - IsExternal: no
Qto_ColumnBaseQuantities - Length: 7.53028 m; CrossSectionArea: 0.0628235 m2; OuterSurfaceArea: 6.69123 m2; GrossVolume: 0.473078 m3; NetVolume: 0.473119 m3
Pset_ColumnCommon - Reference: Poteaux support métallique
Pset_EnvironmentalImpactIndicators - Reference: Poteaux support métallique; sets with these values: 2

# IfcColumn: Poteaux support métallique45:Poteaux support métallique, Poteaux support métallique45:Poteaux support métallique:1630317
In: Arase inf longrines
Type - PredefinedType: COLUMN; Material: Maçonnerie - Béton
Type - Pset_ColumnCommon - IsExternal: no
Qto_ColumnBaseQuantities - Length: 8.13346 m; CrossSectionArea: 0.0628235 m2; OuterSurfaceArea: 7.2272 m2; GrossVolume: 0.510972 m3; NetVolume: 0.511016 m3
Pset_ColumnCommon - Reference: Poteaux support métallique
Pset_EnvironmentalImpactIndicators - Reference: Poteaux support métallique; sets with these values: 2

# IfcColumn: Poteaux support métallique46:Poteaux support métallique, Poteaux support métallique46:Poteaux support métallique:1630332
In: Arase inf longrines
Type - PredefinedType: COLUMN; Material: Maçonnerie - Béton
Type - Pset_ColumnCommon - IsExternal: no
Qto_ColumnBaseQuantities - Length: 8.13003 m; CrossSectionArea: 0.0628235 m2; OuterSurfaceArea: 7.22415 m2; GrossVolume: 0.510757 m3; NetVolume: 0.510801 m3
Pset_ColumnCommon - Reference: Poteaux support métallique
Pset_EnvironmentalImpactIndicators - Reference: Poteaux support métallique; sets with these values: 2

# IfcColumn: Poteaux support métallique47:Poteaux support métallique, Poteaux support métallique47:Poteaux support métallique:1630347
In: Arase inf longrines
Type - PredefinedType: COLUMN; Material: Maçonnerie - Béton
Type - Pset_ColumnCommon - IsExternal: no
Qto_ColumnBaseQuantities - Length: 8.1318 m; CrossSectionArea: 0.0628235 m2; OuterSurfaceArea: 7.22573 m2; GrossVolume: 0.510868 m3; NetVolume: 0.510912 m3
Pset_ColumnCommon - Reference: Poteaux support métallique
Pset_EnvironmentalImpactIndicators - Reference: Poteaux support métallique; sets with these values: 2

# IfcColumn: Poteaux support métallique48:Poteaux support métallique, Poteaux support métallique48:Poteaux support métallique:1630362
In: Arase inf longrines
Type - PredefinedType: COLUMN; Material: Maçonnerie - Béton
Type - Pset_ColumnCommon - IsExternal: no
Qto_ColumnBaseQuantities - Length: 8.14409 m; CrossSectionArea: 0.0628235 m2; OuterSurfaceArea: 7.23665 m2; GrossVolume: 0.51164 m3; NetVolume: 0.511684 m3
Pset_ColumnCommon - Reference: Poteaux support métallique
Pset_EnvironmentalImpactIndicators - Reference: Poteaux support métallique; sets with these values: 2

# IfcColumn: Poteaux support métallique49:Poteaux support métallique, Poteaux support métallique49:Poteaux support métallique:1630377
In: Arase inf longrines
Type - PredefinedType: COLUMN; Material: Maçonnerie - Béton
Type - Pset_ColumnCommon - IsExternal: no
Qto_ColumnBaseQuantities - Length: 8.14289 m; CrossSectionArea: 0.0628235 m2; OuterSurfaceArea: 7.23559 m2; GrossVolume: 0.511565 m3; NetVolume: 0.511609 m3
Pset_ColumnCommon - Reference: Poteaux support métallique
Pset_EnvironmentalImpactIndicators - Reference: Poteaux support métallique; sets with these values: 2

# IfcColumn: Poteaux support métallique4:Poteaux support métallique, Poteaux support métallique4:Poteaux support métallique:1629262
In: Arase inf longrines
Type - PredefinedType: COLUMN; Material: Maçonnerie - Béton
Type - Pset_ColumnCommon - IsExternal: no
Qto_ColumnBaseQuantities - Length: 3.36842 m; CrossSectionArea: 0.0628235 m2; OuterSurfaceArea: 2.9931 m2; GrossVolume: 0.211615 m3; NetVolume: 0.211634 m3
Pset_ColumnCommon - Reference: Poteaux support métallique
Pset_EnvironmentalImpactIndicators - Reference: Poteaux support métallique; sets with these values: 2

# IfcColumn: Poteaux support métallique50:Poteaux support métallique, Poteaux support métallique50:Poteaux support métallique:1630392
In: Arase inf longrines
Type - PredefinedType: COLUMN; Material: Maçonnerie - Béton
Type - Pset_ColumnCommon - IsExternal: no
Qto_ColumnBaseQuantities - Length: 8.1274 m; CrossSectionArea: 0.0628235 m2; OuterSurfaceArea: 7.22181 m2; GrossVolume: 0.510591 m3; NetVolume: 0.510635 m3
Pset_ColumnCommon - Reference: Poteaux support métallique
Pset_EnvironmentalImpactIndicators - Reference: Poteaux support métallique; sets with these values: 2

# IfcColumn: Poteaux support métallique51:Poteaux support métallique, Poteaux support métallique51:Poteaux support métallique:1630407
In: Arase inf longrines
Type - PredefinedType: COLUMN; Material: Maçonnerie - Béton
Type - Pset_ColumnCommon - IsExternal: no
Qto_ColumnBaseQuantities - Length: 8.14166 m; CrossSectionArea: 0.0628235 m2; OuterSurfaceArea: 7.23449 m2; GrossVolume: 0.511487 m3; NetVolume: 0.511531 m3
Pset_ColumnCommon - Reference: Poteaux support métallique
Pset_EnvironmentalImpactIndicators - Reference: Poteaux support métallique; sets with these values: 2

# IfcColumn: Poteaux support métallique52:Poteaux support métallique, Poteaux support métallique52:Poteaux support métallique:1630422
In: Arase inf longrines
Type - PredefinedType: COLUMN; Material: Maçonnerie - Béton
Type - Pset_ColumnCommon - IsExternal: no
Qto_ColumnBaseQuantities - Length: 8.13108 m; CrossSectionArea: 0.0628235 m2; OuterSurfaceArea: 7.22509 m2; GrossVolume: 0.510822 m3; NetVolume: 0.510867 m3
Pset_ColumnCommon - Reference: Poteaux support métallique
Pset_EnvironmentalImpactIndicators - Reference: Poteaux support métallique; sets with these values: 2

# IfcColumn: Poteaux support métallique53:Poteaux support métallique, Poteaux support métallique53:Poteaux support métallique:1630437
In: Arase inf longrines
Type - PredefinedType: COLUMN; Material: Maçonnerie - Béton
Type - Pset_ColumnCommon - IsExternal: no
Qto_ColumnBaseQuantities - Length: 8.14577 m; CrossSectionArea: 0.0628235 m2; OuterSurfaceArea: 7.23814 m2; GrossVolume: 0.511745 m3; NetVolume: 0.51179 m3
Pset_ColumnCommon - Reference: Poteaux support métallique
Pset_EnvironmentalImpactIndicators - Reference: Poteaux support métallique; sets with these values: 2

# IfcColumn: Poteaux support métallique54:Poteaux support métallique, Poteaux support métallique54:Poteaux support métallique:1630452
In: Arase inf longrines
Type - PredefinedType: COLUMN; Material: Maçonnerie - Béton
Type - Pset_ColumnCommon - IsExternal: no
Qto_ColumnBaseQuantities - Length: 8.1218 m; CrossSectionArea: 0.0628235 m2; OuterSurfaceArea: 7.21684 m2; GrossVolume: 0.510239 m3; NetVolume: 0.510283 m3
Pset_ColumnCommon - Reference: Poteaux support métallique
Pset_EnvironmentalImpactIndicators - Reference: Poteaux support métallique; sets with these values: 2

# IfcColumn: Poteaux support métallique55:Poteaux support métallique, Poteaux support métallique55:Poteaux support métallique:1630569
In: Arase inf longrines
Type - PredefinedType: COLUMN; Material: Maçonnerie - Béton
Type - Pset_ColumnCommon - IsExternal: no
Qto_ColumnBaseQuantities - Length: 8.12618 m; CrossSectionArea: 0.0628235 m2; OuterSurfaceArea: 7.22074 m2; GrossVolume: 0.510515 m3; NetVolume: 0.510559 m3
Pset_ColumnCommon - Reference: Poteaux support métallique
Pset_EnvironmentalImpactIndicators - Reference: Poteaux support métallique; sets with these values: 2

# IfcColumn: Poteaux support métallique56:Poteaux support métallique, Poteaux support métallique56:Poteaux support métallique:1631184
In: Arase inf longrines
Type - PredefinedType: COLUMN; Material: Maçonnerie - Béton
Type - Pset_ColumnCommon - IsExternal: no
Qto_ColumnBaseQuantities - Length: 8.14666 m; CrossSectionArea: 0.0628235 m2; OuterSurfaceArea: 7.23893 m2; GrossVolume: 0.511801 m3; NetVolume: 0.511845 m3
Pset_ColumnCommon - Reference: Poteaux support métallique
Pset_EnvironmentalImpactIndicators - Reference: Poteaux support métallique; sets with these values: 2

# IfcColumn: Poteaux support métallique57:Poteaux support métallique, Poteaux support métallique57:Poteaux support métallique:1637283
In: Aras sup plancher haut RDC
Type - PredefinedType: COLUMN; Material: Maçonnerie - Béton
Type - Pset_ColumnCommon - IsExternal: no
Qto_ColumnBaseQuantities - Length: 3.52802 m; CrossSectionArea: 0.0628235 m2; OuterSurfaceArea: 3.13492 m2; GrossVolume: 0.221643 m3; NetVolume: 0.221662 m3
Pset_ColumnCommon - Reference: Poteaux support métallique
Pset_EnvironmentalImpactIndicators - Reference: Poteaux support métallique; sets with these values: 2

# IfcColumn: Poteaux support métallique58:Poteaux support métallique, Poteaux support métallique58:Poteaux support métallique:1637648
In: Aras sup plancher haut RDC
Type - PredefinedType: COLUMN; Material: Maçonnerie - Béton
Type - Pset_ColumnCommon - IsExternal: no
Qto_ColumnBaseQuantities - Length: 3.52877 m; CrossSectionArea: 0.0628235 m2; OuterSurfaceArea: 3.13558 m2; GrossVolume: 0.22169 m3; NetVolume: 0.221709 m3
Pset_ColumnCommon - Reference: Poteaux support métallique
Pset_EnvironmentalImpactIndicators - Reference: Poteaux support métallique; sets with these values: 2

# IfcColumn: Poteaux support métallique59:Poteaux support métallique, Poteaux support métallique59:Poteaux support métallique:1658704
In: Aras sup plancher haut RDC
Type - PredefinedType: COLUMN; Material: Maçonnerie - Béton
Type - Pset_ColumnCommon - IsExternal: no
Qto_ColumnBaseQuantities - Length: 3.52877 m; CrossSectionArea: 0.0628235 m2; OuterSurfaceArea: 3.13558 m2; GrossVolume: 0.22169 m3; NetVolume: 0.221709 m3
Pset_ColumnCommon - Reference: Poteaux support métallique
Pset_EnvironmentalImpactIndicators - Reference: Poteaux support métallique; sets with these values: 2

# IfcColumn: Poteaux support métallique5:Poteaux support métallique, Poteaux support métallique5:Poteaux support métallique:1629277
In: Arase inf longrines
Type - PredefinedType: COLUMN; Material: Maçonnerie - Béton
Type - Pset_ColumnCommon - IsExternal: no
Qto_ColumnBaseQuantities - Length: 3.3397 m; CrossSectionArea: 0.0628235 m2; OuterSurfaceArea: 2.96758 m2; GrossVolume: 0.209811 m3; NetVolume: 0.20983 m3
Pset_ColumnCommon - Reference: Poteaux support métallique
Pset_EnvironmentalImpactIndicators - Reference: Poteaux support métallique; sets with these values: 2

# IfcColumn: Poteaux support métallique60:Poteaux support métallique, Poteaux support métallique60:Poteaux support métallique:1658719
In: Aras sup plancher haut RDC
Type - PredefinedType: COLUMN; Material: Maçonnerie - Béton
Type - Pset_ColumnCommon - IsExternal: no
Qto_ColumnBaseQuantities - Length: 3.52877 m; CrossSectionArea: 0.0628235 m2; OuterSurfaceArea: 3.13558 m2; GrossVolume: 0.22169 m3; NetVolume: 0.221709 m3
Pset_ColumnCommon - Reference: Poteaux support métallique
Pset_EnvironmentalImpactIndicators - Reference: Poteaux support métallique; sets with these values: 2

# IfcColumn: Poteaux support métallique6:Poteaux support métallique, Poteaux support métallique6:Poteaux support métallique:1629292
In: Arase inf longrines
Type - PredefinedType: COLUMN; Material: Maçonnerie - Béton
Type - Pset_ColumnCommon - IsExternal: no
Qto_ColumnBaseQuantities - Length: 3.36342 m; CrossSectionArea: 0.0628235 m2; OuterSurfaceArea: 2.98866 m2; GrossVolume: 0.211302 m3; NetVolume: 0.21132 m3
Pset_ColumnCommon - Reference: Poteaux support métallique
Pset_EnvironmentalImpactIndicators - Reference: Poteaux support métallique; sets with these values: 2

# IfcColumn: Poteaux support métallique7:Poteaux support métallique, Poteaux support métallique7:Poteaux support métallique:1629311
In: RDC
Type - PredefinedType: COLUMN; Material: Maçonnerie - Béton
Type - Pset_ColumnCommon - IsExternal: no
Qto_ColumnBaseQuantities - Length: 3.087 m; CrossSectionArea: 0.0628235 m2; OuterSurfaceArea: 2.74304 m2; GrossVolume: 0.193936 m3; NetVolume: 0.193953 m3
Pset_ColumnCommon - Reference: Poteaux support métallique
Pset_EnvironmentalImpactIndicators - Reference: Poteaux support métallique; sets with these values: 2

# IfcColumn: Poteaux support métallique8:Poteaux support métallique, Poteaux support métallique8:Poteaux support métallique:1629326
In: Arase inf longrines
Type - PredefinedType: COLUMN; Material: Maçonnerie - Béton
Type - Pset_ColumnCommon - IsExternal: no
Qto_ColumnBaseQuantities - Length: 3.36234 m; CrossSectionArea: 0.0628235 m2; OuterSurfaceArea: 2.98769 m2; GrossVolume: 0.211234 m3; NetVolume: 0.211252 m3
Pset_ColumnCommon - Reference: Poteaux support métallique
Pset_EnvironmentalImpactIndicators - Reference: Poteaux support métallique; sets with these values: 2

# IfcColumn: Poteaux support métallique9:Poteaux support métallique, Poteaux support métallique9:Poteaux support métallique:1629341
In: Arase inf longrines
Type - PredefinedType: COLUMN; Material: Maçonnerie - Béton
Type - Pset_ColumnCommon - IsExternal: no
Qto_ColumnBaseQuantities - Length: 3.34426 m; CrossSectionArea: 0.0628235 m2; OuterSurfaceArea: 2.97163 m2; GrossVolume: 0.210098 m3; NetVolume: 0.210116 m3
Pset_ColumnCommon - Reference: Poteaux support métallique
Pset_EnvironmentalImpactIndicators - Reference: Poteaux support métallique; sets with these values: 2

# IfcColumn: Poteaux support métallique:Poteaux support métallique, Poteaux support métallique:Poteaux support métallique:1628664
In: Arase inf longrines
Type - PredefinedType: COLUMN; Material: Maçonnerie - Béton
Type - Pset_ColumnCommon - IsExternal: no
Qto_ColumnBaseQuantities - Length: 3.3348 m; CrossSectionArea: 0.0628235 m2; OuterSurfaceArea: 2.96322 m2; GrossVolume: 0.209503 m3; NetVolume: 0.209522 m3
Pset_ColumnCommon - Reference: Poteaux support métallique
Pset_EnvironmentalImpactIndicators - Reference: Poteaux support métallique; sets with these values: 2

# IfcCovering: Plafond de base:Plafond 600 mm x 1200 mm (67)
Type - PredefinedType: CEILING
Type - Pset_CoveringCommon - IsExternal: no
Material: Faux-plafond - Trame 600 x 600
Pset_CoveringCommon - Reference: Plafond 600 mm x 1200 mm
Pset_EnvironmentalImpactIndicators - Reference: Plafond 600 mm x 1200 mm
Name (Plafond de base:Plafond 600 mm x 1200 mm:...) | In
1259404 | RDC
1259412 | RDC
1259420 | RDC
1259428 | RDC
1259436 | RDC
1259444 | RDC
1259452 | RDC
1259460 | RDC
1259468 | RDC
1259476 | RDC
1259484 | RDC
1259492 | RDC
1259500 | RDC
1259508 | RDC
1259516 | RDC
1259524 | RDC
1259538 | RDC
1259547 | RDC
1259574 | RDC
1259582 | RDC
1259614 | RDC
1259622 | RDC
1259632 | RDC
1259641 | RDC
1259649 | RDC
1259657 | RDC
1259684 | RDC
1259692 | RDC
1259700 | RDC
1259710 | RDC
1259799 | RDC
1259821 | RDC
1259878 | RDC
1292847 | RDC
1292860 | RDC
1292875 | RDC
1306071 | RDC
1519158 | 75
1519168 | 73
1519178 | 72
1519188 | 69
1519198 | 68
1519206 | 74
1519218 | 71
1519230 | 70
1519242 | 67
1519254 | 66
1519267 | 54
1519277 | 53
1519287 | 52
1519297 | 51
1519307 | 50
1519317 | 49
1519327 | 55
1519337 | 56
1519347 | 57
1519358 | 58
1519368 | 59
1519378 | 61
1519638 | 62
1519827 | R+1 fini
1519835 | R+1 fini
1519852 | R+1 fini
1519861 | R+1 fini
1519875 | R+1 fini
1519883 | R+1 fini
1784193 | RDC

# IfcDistributionPort (371)
Description: Flow
Name | FlowDirection | PredefinedType | SystemType
Port_1054396 | SINK | PIPE | DOMESTICCOLDWATER
Port_1054396 | SOURCE | PIPE | SEWAGE
Port_1054515 | SOURCE | PIPE | SEWAGE
Port_1054515 | SINK | PIPE | DOMESTICCOLDWATER
Port_1054692 | SOURCE | PIPE | SEWAGE
Port_1054692 | SINK | PIPE | DOMESTICCOLDWATER
Port_1054869 | SINK | PIPE | DOMESTICCOLDWATER
Port_1054869 | SOURCE | PIPE | SEWAGE
Port_1055000 | SOURCE | PIPE | SEWAGE
Port_1055000 | SINK | PIPE | DOMESTICCOLDWATER
Port_1113427 | SOURCE | PIPE | SEWAGE
Port_1113427 | SINK | PIPE | DOMESTICCOLDWATER
Port_1113542 | SINK | PIPE | DOMESTICCOLDWATER
Port_1113542 | SOURCE | PIPE | SEWAGE
Port_1113601 | SOURCE | PIPE | SEWAGE
Port_1113601 | SINK | PIPE | DOMESTICCOLDWATER
Port_1113758 | SINK | PIPE | DOMESTICCOLDWATER
Port_1113758 | SOURCE | PIPE | SEWAGE
Port_1113811 | SINK | PIPE | DOMESTICCOLDWATER
Port_1113811 | SOURCE | PIPE | SEWAGE
Port_1115067 | SOURCE | PIPE | SEWAGE
Port_1115067 | SINK | PIPE | DOMESTICCOLDWATER
Port_1116840 | SINK | PIPE | DOMESTICCOLDWATER
Port_1116840 | SOURCE | PIPE | SEWAGE
Port_1116975 | SINK | PIPE | DOMESTICCOLDWATER
Port_1116975 | SOURCE | PIPE | SEWAGE
Port_1117072 | SOURCE | PIPE | SEWAGE
Port_1117072 | SINK | PIPE | DOMESTICCOLDWATER
Port_1117151 | SOURCE | PIPE | SEWAGE
Port_1117151 | SINK | PIPE | DOMESTICCOLDWATER
Port_1117240 | SINK | PIPE | DOMESTICCOLDWATER
Port_1117240 | SOURCE | PIPE | SEWAGE
Port_1117479 | SOURCE | PIPE | SEWAGE
Port_1117479 | SINK | PIPE | DOMESTICCOLDWATER
Port_1117574 | SOURCE | PIPE | SEWAGE
Port_1117574 | SINK | PIPE | DOMESTICCOLDWATER
Port_1117655 | SOURCE | PIPE | SEWAGE
Port_1117655 | SINK | PIPE | DOMESTICCOLDWATER
Port_1117730 | SOURCE | PIPE | SEWAGE
Port_1117730 | SINK | PIPE | DOMESTICCOLDWATER
Port_1117837 | SINK | PIPE | DOMESTICCOLDWATER
Port_1117837 | SOURCE | PIPE | SEWAGE
Port_1117892 | SINK | PIPE | DOMESTICCOLDWATER
Port_1117892 | SOURCE | PIPE | SEWAGE
Port_1118042 | SINK | PIPE | DOMESTICCOLDWATER
Port_1118042 | SOURCE | PIPE | SEWAGE
Port_1262448 | SOURCEANDSINK | CABLE | ELECTRICAL
Port_1262819 | SOURCEANDSINK | CABLE | ELECTRICAL
Port_1262829 | SOURCEANDSINK | CABLE | ELECTRICAL
Port_1262837 | SOURCEANDSINK | CABLE | ELECTRICAL
Port_1262845 | SOURCEANDSINK | CABLE | ELECTRICAL
Port_1262855 | SOURCEANDSINK | CABLE | ELECTRICAL
Port_1262863 | SOURCEANDSINK | CABLE | ELECTRICAL
Port_1262873 | SOURCEANDSINK | CABLE | ELECTRICAL
Port_1262883 | SOURCEANDSINK | CABLE | ELECTRICAL
Port_1262891 | SOURCEANDSINK | CABLE | ELECTRICAL
Port_1262899 | SOURCEANDSINK | CABLE | ELECTRICAL
Port_1262907 | SOURCEANDSINK | CABLE | ELECTRICAL
Port_1262919 | SOURCEANDSINK | CABLE | ELECTRICAL
Port_1262929 | SOURCEANDSINK | CABLE | ELECTRICAL
Port_1262939 | SOURCEANDSINK | CABLE | ELECTRICAL
Port_1264078 | SOURCEANDSINK | CABLE | ELECTRICAL
Port_1270324 | SOURCEANDSINK | CABLE | ELECTRICAL
Port_1270332 | SOURCEANDSINK | CABLE | ELECTRICAL
Port_1270344 | SOURCEANDSINK | CABLE | ELECTRICAL
Port_1270352 | SOURCEANDSINK | CABLE | ELECTRICAL
Port_1270360 | SOURCEANDSINK | CABLE | ELECTRICAL
Port_1270370 | SOURCEANDSINK | CABLE | ELECTRICAL
Port_1270378 | SOURCEANDSINK | CABLE | ELECTRICAL
Port_1270386 | SOURCEANDSINK | CABLE | ELECTRICAL
Port_1270394 | SOURCEANDSINK | CABLE | ELECTRICAL
Port_1270406 | SOURCEANDSINK | CABLE | ELECTRICAL
Port_1270414 | SOURCEANDSINK | CABLE | ELECTRICAL
Port_1270424 | SOURCEANDSINK | CABLE | ELECTRICAL
Port_1270432 | SOURCEANDSINK | CABLE | ELECTRICAL
Port_1270440 | SOURCEANDSINK | CABLE | ELECTRICAL
Port_1270448 | SOURCEANDSINK | CABLE | ELECTRICAL
Port_1270456 | SOURCEANDSINK | CABLE | ELECTRICAL
Port_1270470 | SOURCEANDSINK | CABLE | ELECTRICAL
Port_1270482 | SOURCEANDSINK | CABLE | ELECTRICAL
Port_1270494 | SOURCEANDSINK | CABLE | ELECTRICAL
Port_1270506 | SOURCEANDSINK | CABLE | ELECTRICAL
Port_1270514 | SOURCEANDSINK | CABLE | ELECTRICAL
Port_1270522 | SOURCEANDSINK | CABLE | ELECTRICAL
Port_1270530 | SOURCEANDSINK | CABLE | ELECTRICAL
Port_1270538 | SOURCEANDSINK | CABLE | ELECTRICAL
Port_1270546 | SOURCEANDSINK | CABLE | ELECTRICAL
Port_1270556 | SOURCEANDSINK | CABLE | ELECTRICAL
Port_1270564 | SOURCEANDSINK | CABLE | ELECTRICAL
Port_1270574 | SOURCEANDSINK | CABLE | ELECTRICAL
Port_1270582 | SOURCEANDSINK | CABLE | ELECTRICAL
Port_1270590 | SOURCEANDSINK | CABLE | ELECTRICAL
Port_1270598 | SOURCEANDSINK | CABLE | ELECTRICAL
Port_1270606 | SOURCEANDSINK | CABLE | ELECTRICAL
Port_1270612 | SOURCEANDSINK | CABLE | ELECTRICAL
Port_1270785 | SOURCEANDSINK | CABLE | ELECTRICAL
Port_1270795 | SOURCEANDSINK | CABLE | ELECTRICAL
Port_1270805 | SOURCEANDSINK | CABLE | ELECTRICAL
Port_1270813 | SOURCEANDSINK | CABLE | ELECTRICAL
Port_1270821 | SOURCEANDSINK | CABLE | ELECTRICAL
Port_1270829 | SOURCEANDSINK | CABLE | ELECTRICAL
Port_1270839 | SOURCEANDSINK | CABLE | ELECTRICAL
Port_1270847 | SOURCEANDSINK | CABLE | ELECTRICAL
Port_1270855 | SOURCEANDSINK | CABLE | ELECTRICAL
Port_1270863 | SOURCEANDSINK | CABLE | ELECTRICAL
Port_1270871 | SOURCEANDSINK | CABLE | ELECTRICAL
Port_1270932 | SOURCEANDSINK | CABLE | ELECTRICAL
Port_1270938 | SOURCEANDSINK | CABLE | ELECTRICAL
Port_1270946 | SOURCEANDSINK | CABLE | ELECTRICAL
Port_1270956 | SOURCEANDSINK | CABLE | ELECTRICAL
Port_1270964 | SOURCEANDSINK | CABLE | ELECTRICAL
Port_1270974 | SOURCEANDSINK | CABLE | ELECTRICAL
Port_1270982 | SOURCEANDSINK | CABLE | ELECTRICAL
Port_1270990 | SOURCEANDSINK | CABLE | ELECTRICAL
Port_1271000 | SOURCEANDSINK | CABLE | ELECTRICAL
Port_1271826 | SOURCEANDSINK | CABLE | ELECTRICAL
Port_1272537 | SOURCEANDSINK | CABLE | ELECTRICAL
Port_1277623 | SOURCEANDSINK | CABLE | ELECTRICAL
Port_1278510 | SOURCEANDSINK | CABLE | ELECTRICAL
Port_1278511 | SOURCEANDSINK | CABLE | ELECTRICAL
Port_1278591 | SOURCEANDSINK | CABLE | ELECTRICAL
Port_1278592 | SOURCEANDSINK | CABLE | ELECTRICAL
Port_1278602 | SOURCEANDSINK | CABLE | ELECTRICAL
Port_1278603 | SOURCEANDSINK | CABLE | ELECTRICAL
Port_1278661 | SOURCEANDSINK | CABLE | ELECTRICAL
Port_1278662 | SOURCEANDSINK | CABLE | ELECTRICAL
Port_1278701 | SOURCEANDSINK | CABLE | ELECTRICAL
Port_1278745 | SOURCEANDSINK | CABLE | ELECTRICAL
Port_1278805 | SOURCEANDSINK | CABLE | ELECTRICAL
Port_1278813 | SOURCEANDSINK | CABLE | ELECTRICAL
Port_1279236 | SOURCEANDSINK | CABLE | ELECTRICAL
Port_1279237 | SOURCEANDSINK | CABLE | ELECTRICAL
Port_1279243 | SOURCEANDSINK | CABLE | ELECTRICAL
Port_1279244 | SOURCEANDSINK | CABLE | ELECTRICAL
Port_1279252 | SOURCEANDSINK | CABLE | ELECTRICAL
Port_1279253 | SOURCEANDSINK | CABLE | ELECTRICAL
Port_1279261 | SOURCEANDSINK | CABLE | ELECTRICAL
Port_1279262 | SOURCEANDSINK | CABLE | ELECTRICAL
Port_1279272 | SOURCEANDSINK | CABLE | ELECTRICAL
Port_1279273 | SOURCEANDSINK | CABLE | ELECTRICAL
Port_1279310 | SOURCEANDSINK | CABLE | ELECTRICAL
Port_1279318 | SOURCEANDSINK | CABLE | ELECTRICAL
Port_1279326 | SOURCEANDSINK | CABLE | ELECTRICAL
Port_1279334 | SOURCEANDSINK | CABLE | ELECTRICAL
Port_1279500 | SOURCEANDSINK | CABLE | ELECTRICAL
Port_1279530 | SOURCEANDSINK | CABLE | ELECTRICAL
Port_1279584 | SOURCEANDSINK | CABLE | ELECTRICAL
Port_1279703 | SOURCEANDSINK | CABLE | ELECTRICAL
Port_1279771 | SOURCEANDSINK | CABLE | ELECTRICAL
Port_1279779 | SOURCEANDSINK | CABLE | ELECTRICAL
Port_1279938 | SOURCEANDSINK | CABLE | ELECTRICAL
Port_1279946 | SOURCEANDSINK | CABLE | ELECTRICAL
Port_1279956 | SOURCEANDSINK | CABLE | ELECTRICAL
Port_1279990 | SOURCEANDSINK | CABLE | ELECTRICAL
Port_1279998 | SOURCEANDSINK | CABLE | ELECTRICAL
Port_1280006 | SOURCEANDSINK | CABLE | ELECTRICAL
Port_1280053 | SOURCEANDSINK | CABLE | ELECTRICAL
Port_1280061 | SOURCEANDSINK | CABLE | ELECTRICAL
Port_1280975 | SOURCEANDSINK | CABLE | ELECTRICAL
Port_1281329 | SOURCEANDSINK | CABLE | ELECTRICAL
Port_1281449 | SOURCEANDSINK | CABLE | ELECTRICAL
Port_1282304 | SOURCEANDSINK | CABLE | ELECTRICAL
Port_1283196 | SOURCEANDSINK | CABLE | ELECTRICAL
Port_1284496 | SOURCEANDSINK | CABLE | ELECTRICAL
Port_1284953 | SOURCEANDSINK | CABLE | ELECTRICAL
Port_1285541 | SOURCEANDSINK | CABLE | ELECTRICAL
Port_1285883 | SOURCEANDSINK | CABLE | ELECTRICAL
Port_1286123 | SOURCEANDSINK | CABLE | ELECTRICAL
Port_1292902 | SOURCEANDSINK | CABLE | ELECTRICAL
Port_1293112 | SOURCEANDSINK | CABLE | ELECTRICAL
Port_1293442 | SOURCEANDSINK | CABLE | ELECTRICAL
Port_1293602 | SOURCEANDSINK | CABLE | ELECTRICAL
Port_1293842 | SOURCEANDSINK | CABLE | ELECTRICAL
Port_1294112 | SOURCEANDSINK | CABLE | ELECTRICAL
Port_1294412 | SOURCEANDSINK | CABLE | ELECTRICAL
Port_1294612 | SOURCEANDSINK | CABLE | ELECTRICAL
Port_1294902 | SOURCEANDSINK | CABLE | ELECTRICAL
Port_1295102 | SOURCEANDSINK | CABLE | ELECTRICAL
Port_1297216 | SOURCEANDSINK | CABLE | ELECTRICAL
Port_1297438 | SOURCEANDSINK | CABLE | ELECTRICAL
Port_1297788 | SOURCEANDSINK | CABLE | ELECTRICAL
Port_1297948 | SOURCEANDSINK | CABLE | ELECTRICAL
Port_1298238 | SOURCEANDSINK | CABLE | ELECTRICAL
Port_1298518 | SOURCEANDSINK | CABLE | ELECTRICAL
Port_1298788 | SOURCEANDSINK | CABLE | ELECTRICAL
Port_1298988 | SOURCEANDSINK | CABLE | ELECTRICAL
Port_1301492 | SOURCEANDSINK | CABLE | ELECTRICAL
Port_1301561 | SOURCEANDSINK | CABLE | ELECTRICAL
Port_1301750 | SOURCEANDSINK | CABLE | ELECTRICAL
Port_1302616 | SOURCEANDSINK | CABLE | ELECTRICAL
Port_1302713 | SOURCEANDSINK | CABLE | ELECTRICAL
Port_1302798 | SOURCEANDSINK | CABLE | ELECTRICAL
Port_1302972 | SOURCEANDSINK | CABLE | ELECTRICAL
Port_1303047 | SOURCEANDSINK | CABLE | ELECTRICAL
Port_1303155 | SOURCEANDSINK | CABLE | ELECTRICAL
Port_1303216 | SOURCEANDSINK | CABLE | ELECTRICAL
Port_1303281 | SOURCEANDSINK | CABLE | ELECTRICAL
Port_1303361 | SOURCEANDSINK | CABLE | ELECTRICAL
Port_1303449 | SOURCEANDSINK | CABLE | ELECTRICAL
Port_1303516 | SOURCEANDSINK | CABLE | ELECTRICAL
Port_1303572 | SOURCEANDSINK | CABLE | ELECTRICAL
Port_1303646 | SOURCEANDSINK | CABLE | ELECTRICAL
Port_1303711 | SOURCEANDSINK | CABLE | ELECTRICAL
Port_1303914 | SOURCEANDSINK | CABLE | ELECTRICAL
Port_1304065 | SOURCEANDSINK | CABLE | ELECTRICAL
Port_1304136 | SOURCEANDSINK | CABLE | ELECTRICAL
Port_1304228 | SOURCEANDSINK | CABLE | ELECTRICAL
Port_1304279 | SOURCEANDSINK | CABLE | ELECTRICAL
Port_1304386 | SOURCEANDSINK | CABLE | ELECTRICAL
Port_1304542 | SOURCEANDSINK | CABLE | ELECTRICAL
Port_1305290 | SOURCEANDSINK | CABLE | ELECTRICAL
Port_1305780 | SOURCEANDSINK | CABLE | ELECTRICAL
Port_1306140 | SOURCEANDSINK | CABLE | ELECTRICAL
Port_1306202 | SOURCEANDSINK | CABLE | ELECTRICAL
Port_1306442 | SOURCEANDSINK | CABLE | ELECTRICAL
Port_1312796 | SOURCEANDSINK | CABLE | ELECTRICAL
Port_1312874 | SOURCEANDSINK | CABLE | ELECTRICAL
Port_1314657 | SOURCEANDSINK | CABLE | ELECTRICAL
Port_1314685 | SOURCEANDSINK | CABLE | ELECTRICAL
Port_1335432 | SOURCE | DUCT | VENTILATION
Port_1336199 | SOURCE | DUCT | VENTILATION
Port_1337224 | SOURCE | DUCT | VENTILATION
Port_1337436 | SOURCE | DUCT | VENTILATION
Port_1337644 | SOURCE | DUCT | VENTILATION
Port_1337893 | SOURCE | DUCT | VENTILATION
Port_1345734 | SOURCE | DUCT | VENTILATION
Port_1403279 | SOURCE | PIPE | SEWAGE
Port_1403279 | SINK | PIPE | DOMESTICCOLDWATER
Port_1403352 | SINK | PIPE | DOMESTICCOLDWATER
Port_1403352 | SOURCE | PIPE | SEWAGE
Port_1403411 | SOURCE | PIPE | SEWAGE
Port_1403411 | SINK | PIPE | DOMESTICCOLDWATER
Port_1403742 | SINK | PIPE | DOMESTICCOLDWATER
Port_1403742 | SOURCE | PIPE | SEWAGE
Port_1403966 | SINK | PIPE | DOMESTICCOLDWATER
Port_1403966 | SOURCE | PIPE | SEWAGE
Port_1404047 | SINK | PIPE | DOMESTICCOLDWATER
Port_1404047 | SOURCE | PIPE | SEWAGE
Port_1404322 | SOURCE | PIPE | SEWAGE
Port_1404322 | SINK | PIPE | DOMESTICCOLDWATER
Port_1404387 | SOURCE | PIPE | SEWAGE
Port_1404387 | SINK | PIPE | DOMESTICCOLDWATER
Port_1404496 | SINK | PIPE | DOMESTICCOLDWATER
Port_1404496 | SOURCE | PIPE | SEWAGE
Port_1404543 | SOURCE | PIPE | SEWAGE
Port_1404543 | SINK | PIPE | DOMESTICCOLDWATER
Port_1404618 | SOURCE | PIPE | SEWAGE
Port_1404618 | SINK | PIPE | DOMESTICCOLDWATER
Port_1404655 | SINK | PIPE | DOMESTICCOLDWATER
Port_1404655 | SOURCE | PIPE | SEWAGE
Port_1404977 | SOURCE | PIPE | SEWAGE
Port_1404977 | SINK | PIPE | DOMESTICCOLDWATER
Port_1405066 | SINK | PIPE | DOMESTICCOLDWATER
Port_1405066 | SOURCE | PIPE | SEWAGE
Port_1405129 | SOURCE | PIPE | SEWAGE
Port_1405129 | SINK | PIPE | DOMESTICCOLDWATER
Port_1405212 | SINK | PIPE | DOMESTICCOLDWATER
Port_1405212 | SOURCE | PIPE | SEWAGE
Port_1405263 | SINK | PIPE | DOMESTICCOLDWATER
Port_1405263 | SOURCE | PIPE | SEWAGE
Port_1405362 | SINK | PIPE | DOMESTICCOLDWATER
Port_1405362 | SOURCE | PIPE | SEWAGE
Port_1525530 | SOURCEANDSINK | CABLE | ELECTRICAL
Port_1525984 | SOURCEANDSINK | CABLE | ELECTRICAL
Port_1527181 | SOURCEANDSINK | CABLE | ELECTRICAL
Port_1527260 | SOURCEANDSINK | CABLE | ELECTRICAL
Port_1527973 | SOURCEANDSINK | CABLE | ELECTRICAL
Port_1527983 | SOURCEANDSINK | CABLE | ELECTRICAL
Port_1527993 | SOURCEANDSINK | CABLE | ELECTRICAL
Port_1528001 | SOURCEANDSINK | CABLE | ELECTRICAL
Port_1528009 | SOURCEANDSINK | CABLE | ELECTRICAL
Port_1528017 | SOURCEANDSINK | CABLE | ELECTRICAL
Port_1528027 | SOURCEANDSINK | CABLE | ELECTRICAL
Port_1528035 | SOURCEANDSINK | CABLE | ELECTRICAL
Port_1528043 | SOURCEANDSINK | CABLE | ELECTRICAL
Port_1528053 | SOURCEANDSINK | CABLE | ELECTRICAL
Port_1528067 | SOURCEANDSINK | CABLE | ELECTRICAL
Port_1528079 | SOURCEANDSINK | CABLE | ELECTRICAL
Port_1528091 | SOURCEANDSINK | CABLE | ELECTRICAL
Port_1528101 | SOURCEANDSINK | CABLE | ELECTRICAL
Port_1528109 | SOURCEANDSINK | CABLE | ELECTRICAL
Port_1528119 | SOURCEANDSINK | CABLE | ELECTRICAL
Port_1528127 | SOURCEANDSINK | CABLE | ELECTRICAL
Port_1528135 | SOURCEANDSINK | CABLE | ELECTRICAL
Port_1528143 | SOURCEANDSINK | CABLE | ELECTRICAL
Port_1528151 | SOURCEANDSINK | CABLE | ELECTRICAL
Port_1528161 | SOURCEANDSINK | CABLE | ELECTRICAL
Port_1528171 | SOURCEANDSINK | CABLE | ELECTRICAL
Port_1528179 | SOURCEANDSINK | CABLE | ELECTRICAL
Port_1528189 | SOURCEANDSINK | CABLE | ELECTRICAL
Port_1528201 | SOURCEANDSINK | CABLE | ELECTRICAL
Port_1528211 | SOURCEANDSINK | CABLE | ELECTRICAL
Port_1528219 | SOURCEANDSINK | CABLE | ELECTRICAL
Port_1528227 | SOURCEANDSINK | CABLE | ELECTRICAL
Port_1528237 | SOURCEANDSINK | CABLE | ELECTRICAL
Port_1528253 | SOURCEANDSINK | CABLE | ELECTRICAL
Port_1528261 | SOURCEANDSINK | CABLE | ELECTRICAL
Port_1528269 | SOURCEANDSINK | CABLE | ELECTRICAL
Port_1528277 | SOURCEANDSINK | CABLE | ELECTRICAL
Port_1528285 | SOURCEANDSINK | CABLE | ELECTRICAL
Port_1528343 | SOURCEANDSINK | CABLE | ELECTRICAL
Port_1528351 | SOURCEANDSINK | CABLE | ELECTRICAL
Port_1528359 | SOURCEANDSINK | CABLE | ELECTRICAL
Port_1528367 | SOURCEANDSINK | CABLE | ELECTRICAL
Port_1528377 | SOURCEANDSINK | CABLE | ELECTRICAL
Port_1528385 | SOURCEANDSINK | CABLE | ELECTRICAL
Port_1528395 | SOURCEANDSINK | CABLE | ELECTRICAL
Port_1528403 | SOURCEANDSINK | CABLE | ELECTRICAL
Port_1528411 | SOURCEANDSINK | CABLE | ELECTRICAL
Port_1528419 | SOURCEANDSINK | CABLE | ELECTRICAL
Port_1534760 | SOURCEANDSINK | CABLE | ELECTRICAL
Port_1535171 | SOURCEANDSINK | CABLE | ELECTRICAL
Port_1535688 | SOURCEANDSINK | CABLE | ELECTRICAL
Port_1536274 | SOURCEANDSINK | CABLE | ELECTRICAL
Port_1536282 | SOURCEANDSINK | CABLE | ELECTRICAL
Port_1536294 | SOURCEANDSINK | CABLE | ELECTRICAL
Port_1536302 | SOURCEANDSINK | CABLE | ELECTRICAL
Port_1536310 | SOURCEANDSINK | CABLE | ELECTRICAL
Port_1536318 | SOURCEANDSINK | CABLE | ELECTRICAL
Port_1536326 | SOURCEANDSINK | CABLE | ELECTRICAL
Port_1536334 | SOURCEANDSINK | CABLE | ELECTRICAL
Port_1536346 | SOURCEANDSINK | CABLE | ELECTRICAL
Port_1536354 | SOURCEANDSINK | CABLE | ELECTRICAL
Port_1536362 | SOURCEANDSINK | CABLE | ELECTRICAL
Port_1536374 | SOURCEANDSINK | CABLE | ELECTRICAL
Port_1536384 | SOURCEANDSINK | CABLE | ELECTRICAL
Port_1536394 | SOURCEANDSINK | CABLE | ELECTRICAL
Port_1536402 | SOURCEANDSINK | CABLE | ELECTRICAL
Port_1536535 | SOURCEANDSINK | CABLE | ELECTRICAL
Port_1536543 | SOURCEANDSINK | CABLE | ELECTRICAL
Port_1536555 | SOURCEANDSINK | CABLE | ELECTRICAL
Port_1536565 | SOURCEANDSINK | CABLE | ELECTRICAL
Port_1536573 | SOURCEANDSINK | CABLE | ELECTRICAL
Port_1536581 | SOURCEANDSINK | CABLE | ELECTRICAL
Port_1536593 | SOURCEANDSINK | CABLE | ELECTRICAL
Port_1536601 | SOURCEANDSINK | CABLE | ELECTRICAL
Port_1536609 | SOURCEANDSINK | CABLE | ELECTRICAL
Port_1536627 | SOURCEANDSINK | CABLE | ELECTRICAL
Port_1537447 | SOURCEANDSINK | CABLE | ELECTRICAL
Port_1541164 | SOURCEANDSINK | CABLE | ELECTRICAL
Port_1543258 | SOURCEANDSINK | CABLE | ELECTRICAL
Port_1544161 | SOURCEANDSINK | CABLE | ELECTRICAL
Port_1545642 | SOURCEANDSINK | CABLE | ELECTRICAL
Port_1545746 | SOURCEANDSINK | CABLE | ELECTRICAL
Port_1545962 | SOURCEANDSINK | CABLE | ELECTRICAL
Port_1546088 | SOURCEANDSINK | CABLE | ELECTRICAL
Port_1546740 | SOURCEANDSINK | CABLE | ELECTRICAL
Port_1547298 | SOURCEANDSINK | CABLE | ELECTRICAL
Port_1549350 | SOURCEANDSINK | CABLE | ELECTRICAL
Port_1550614 | SOURCEANDSINK | CABLE | ELECTRICAL
Port_1550710 | SOURCEANDSINK | CABLE | ELECTRICAL
Port_1551598 | SOURCEANDSINK | CABLE | ELECTRICAL
Port_1551970 | SOURCEANDSINK | CABLE | ELECTRICAL
Port_1552462 | SOURCEANDSINK | CABLE | ELECTRICAL
Port_1552846 | SOURCEANDSINK | CABLE | ELECTRICAL
Port_1554380 | SOURCEANDSINK | CABLE | ELECTRICAL
Port_1555074 | SOURCEANDSINK | CABLE | ELECTRICAL
Port_1555236 | SOURCEANDSINK | CABLE | ELECTRICAL
Port_1555500 | SOURCEANDSINK | CABLE | ELECTRICAL
Port_1555932 | SOURCEANDSINK | CABLE | ELECTRICAL
Port_1556052 | SOURCEANDSINK | CABLE | ELECTRICAL
Port_1556328 | SOURCEANDSINK | CABLE | ELECTRICAL
Port_1556868 | SOURCEANDSINK | CABLE | ELECTRICAL
Port_1557252 | SOURCEANDSINK | CABLE | ELECTRICAL
Port_1557492 | SOURCEANDSINK | CABLE | ELECTRICAL
Port_1558116 | SOURCEANDSINK | CABLE | ELECTRICAL
Port_1558511 | SOURCEANDSINK | CABLE | ELECTRICAL
Port_1558939 | SOURCEANDSINK | CABLE | ELECTRICAL
Port_1559648 | SOURCEANDSINK | CABLE | ELECTRICAL
Port_1559740 | SOURCEANDSINK | CABLE | ELECTRICAL
Port_1567274 | SOURCEANDSINK | CABLE | ELECTRICAL

# IfcDoor: Doors - Industrial-Novoferm-Porte_de_garage_DL-3D:Doors - Industrial-Novoferm-Porte_de_garage_DL-3D, Doors - Industrial-Novoferm-Porte_de_garage_DL-3D:Doors - Industrial-Novoferm-Porte_de_garage_DL-3D:1701797
In: RDC
Type - PredefinedType: DOOR; Material: Stainless Steel, Aluminium
Type - Pset_DoorCommon - IsExternal: no
Type - Pset_ManufacturerTypeInformation - Manufacturer: Novoferm
OverallHeight: 2.4 m; OverallWidth: 2 m
Pset_DoorCommon - Reference: Doors - Industrial-Novoferm-Porte_de_garage_DL-3D
Pset_EnvironmentalImpactIndicators - Reference: Doors - Industrial-Novoferm-Porte_de_garage_DL-3D
Qto_DoorBaseQuantities - Area: 0 m2

# IfcDoor: Doors-Other- SOGAL-SOG040009:Galandage STD - simple ventail (630mm), Doors-Other- SOGAL-SOG040009:Galandage STD - simple ventail (630mm):1259147
In: RDC
Type - PredefinedType: DOOR; Material: SOGAL Plastique, SOGAL Aluminium, SOGAL TEFLON, SOGAL MDF Chêne Noisette, SOGAL MDF pré-peint Blanc, <Unnamed>
Type - Pset_DoorCommon - IsExternal: no
Type - Pset_ManufacturerTypeInformation - Manufacturer: SOGAL
OverallHeight: 2.2 m; OverallWidth: 2.29032 m
Pset_DoorCommon - Reference: Galandage STD - simple ventail (630mm)
Pset_EnvironmentalImpactIndicators - Reference: Galandage STD - simple ventail (630mm)
Qto_DoorBaseQuantities - Area: 1.90128 m2

# IfcDoor: Doors-Other- SOGAL-SOG040009:Galandage STD - simple ventail (930mm), Doors-Other- SOGAL-SOG040009:Galandage STD - simple ventail (930mm):1391331
In: R+1 fini
Type - PredefinedType: DOOR; Material: SOGAL Plastique, SOGAL Aluminium, SOGAL TEFLON, SOGAL MDF Chêne Noisette, SOGAL MDF pré-peint Blanc, <Unnamed>
Type - Pset_DoorCommon - IsExternal: no
Type - Pset_ManufacturerTypeInformation - Manufacturer: SOGAL
OverallHeight: 2.2 m; OverallWidth: 2.29032 m
Pset_DoorCommon - Reference: Galandage STD - simple ventail (930mm)
Pset_EnvironmentalImpactIndicators - Reference: Galandage STD - simple ventail (930mm)
Qto_DoorBaseQuantities - Area: 1.90128 m2

# IfcDoor: Doorset_Fire Rated Double Door_ASSA ABLOY ES_ES04_Hardware 3D:1200 x 2100 mm (1350 x 2175 mm), Doorset_Fire Rated Double Door_ASSA ABLOY ES_ES04_Hardware 3D:1200 x 2100 mm (1350 x 2175 mm):1308139
In: RDC
Type - PredefinedType: DOOR; OperationType: DOUBLE_DOOR_SINGLE_SWING; Material: Hollow Metal_Natural Anodised, Steel_Natural Anodised
Type - Doorset_Fire Rated Double Door_ASSA ABLOY ES_ES04_Hardware 3D:1200 x 2100 mm (1350 x 2175 mm):1308139:1 - PanelOperation: SWINGING
Type - Pset_DoorCommon - IsExternal: no; FireRating: From El30 to El120 (the range depends of frame and door panel)
OverallHeight: 2.185 m; OverallWidth: 1.37 m
Pset_DoorCommon - Reference: 1200 x 2100 mm (1350 x 2175 mm)
Pset_EnvironmentalImpactIndicators - Reference: 1200 x 2100 mm (1350 x 2175 mm)
IfcPermeableCoveringProperties - FrameDepth: 0.055 m
Qto_DoorBaseQuantities - Area: 2.52 m2

# IfcDoor: Doorset_Fire Rated Double Door_ASSA ABLOY ES_ES04_Hardware 3D:1400 x 2100 mm (1550 x 2175 mm) (10)
In: RDC
Type - PredefinedType: DOOR; OperationType: DOUBLE_DOOR_SINGLE_SWING; Material: Hollow Metal_Natural Anodised, Steel_Natural Anodised
Type - Doorset_Fire Rated Double Door_ASSA ABLOY ES_ES04_Hardware 3D:1400 x 2100 mm (1550 x 2175 mm):1307156:1 - PanelOperation: SWINGING
Type - Pset_DoorCommon - IsExternal: no; FireRating: From El30 to El120 (the range depends of frame and door panel)
OverallHeight: 2.185 m; OverallWidth: 1.57 m
Pset_DoorCommon - Reference: 1400 x 2100 mm (1550 x 2175 mm)
Pset_EnvironmentalImpactIndicators - Reference: 1400 x 2100 mm (1550 x 2175 mm)
IfcPermeableCoveringProperties - FrameDepth: 0.055 m
Qto_DoorBaseQuantities - Area: 2.94 m2
Name (Doorset_Fire Rated Double Door_ASSA ABLOY ES_ES04_Hardware 3D:1400 x 2100 mm (1550 x 2175 mm):...)
1307156
1307207
1307667
1307702
1307767
1308184
1308224
1308300
1308541
1309626

# IfcDoor: Doorset_Fire Rated Double Door_ASSA ABLOY ES_ES04_Hardware 3D:1400 x 2100 mm (1550 x 2175 mm) (3)
In: RDC
Type - PredefinedType: DOOR; OperationType: DOUBLE_DOOR_SINGLE_SWING; Material: Hollow Metal_Natural Anodised, Steel_Natural Anodised
Type - Doorset_Fire Rated Double Door_ASSA ABLOY ES_ES04_Hardware 3D:1400 x 2100 mm (1550 x 2175 mm):1309054:1 - PanelOperation: SWINGING
Type - Pset_DoorCommon - IsExternal: no; FireRating: From El30 to El120 (the range depends of frame and door panel)
OverallHeight: 2.185 m; OverallWidth: 1.57 m
Pset_DoorCommon - Reference: 1400 x 2100 mm (1550 x 2175 mm)
Pset_EnvironmentalImpactIndicators - Reference: 1400 x 2100 mm (1550 x 2175 mm)
IfcPermeableCoveringProperties - FrameDepth: 0.055 m
Qto_DoorBaseQuantities - Area: 2.94 m2
Name (Doorset_Fire Rated Double Door_ASSA ABLOY ES_ES04_Hardware 3D:1400 x 2100 mm (1550 x 2175 mm):...)
1309054
1309593
1321607

# IfcDoor: Doorset_Fire Rated Double Door_ASSA ABLOY ES_ES04_Hardware 3D:1400 x 2100 mm (1550 x 2175 mm) (11)
Type - PredefinedType: DOOR; OperationType: DOUBLE_DOOR_SINGLE_SWING; Material: Hollow Metal_Natural Anodised, Steel_Natural Anodised
Type - Doorset_Fire Rated Double Door_ASSA ABLOY ES_ES04_Hardware 3D:1400 x 2100 mm (1550 x 2175 mm):1320045:1 - PanelOperation: SWINGING
Type - Pset_DoorCommon - IsExternal: no; FireRating: From El30 to El120 (the range depends of frame and door panel)
OverallHeight: 2.185 m; OverallWidth: 1.57 m
Pset_DoorCommon - Reference: 1400 x 2100 mm (1550 x 2175 mm)
Pset_EnvironmentalImpactIndicators - Reference: 1400 x 2100 mm (1550 x 2175 mm)
IfcPermeableCoveringProperties - FrameDepth: 0.055 m
Qto_DoorBaseQuantities - Area: 2.94 m2
Name (Doorset_Fire Rated Double Door_ASSA ABLOY ES_ES04_Hardware 3D:1400 x 2100 mm (1550 x 2175 mm):...) | In
1320045 | RDC
1383800 | R+1 fini
1383826 | R+1 fini
1384050 | R+1 fini
1384081 | R+1 fini
1385410 | R+1 fini
1385450 | R+1 fini
1385709 | R+1 fini
1385754 | R+1 fini
1385787 | R+1 fini
1385889 | R+1 fini

# IfcDoor: Doorset_Fire Rated Double Door_ASSA ABLOY ES_ES04_Hardware 3D:1400 x 2100 mm (1550 x 2175 mm) (2)
In: R+1 fini
Type - PredefinedType: DOOR; OperationType: DOUBLE_DOOR_SINGLE_SWING; Material: Hollow Metal_Natural Anodised, Steel_Natural Anodised
Type - Doorset_Fire Rated Double Door_ASSA ABLOY ES_ES04_Hardware 3D:1400 x 2100 mm (1550 x 2175 mm):1385849:1 - PanelOperation: SWINGING
Type - Pset_DoorCommon - IsExternal: no; FireRating: From El30 to El120 (the range depends of frame and door panel)
OverallHeight: 2.185 m; OverallWidth: 1.57 m
Pset_DoorCommon - Reference: 1400 x 2100 mm (1550 x 2175 mm)
Pset_EnvironmentalImpactIndicators - Reference: 1400 x 2100 mm (1550 x 2175 mm)
IfcPermeableCoveringProperties - FrameDepth: 0.055 m
Qto_DoorBaseQuantities - Area: 2.94 m2
Name (Doorset_Fire Rated Double Door_ASSA ABLOY ES_ES04_Hardware 3D:1400 x 2100 mm (1550 x 2175 mm):...)
1385849
1385954

# IfcDoor: Doorset_Fire Rated Double Door_ASSA ABLOY ES_ES04_Hardware 3D:1400 x 2100 mm (1550 x 2175 mm), Doorset_Fire Rated Double Door_ASSA ABLOY ES_ES04_Hardware 3D:1400 x 2100 mm (1550 x 2175 mm):1410005
In: R+1 fini
Type - PredefinedType: DOOR; OperationType: DOUBLE_DOOR_SINGLE_SWING; Material: Hollow Metal_Natural Anodised, Steel_Natural Anodised
Type - Doorset_Fire Rated Double Door_ASSA ABLOY ES_ES04_Hardware 3D:1400 x 2100 mm (1550 x 2175 mm):1410005:1 - PanelOperation: SWINGING
Type - Pset_DoorCommon - IsExternal: no; FireRating: From El30 to El120 (the range depends of frame and door panel)
OverallHeight: 2.185 m; OverallWidth: 1.57 m
Pset_DoorCommon - Reference: 1400 x 2100 mm (1550 x 2175 mm)
Pset_EnvironmentalImpactIndicators - Reference: 1400 x 2100 mm (1550 x 2175 mm)
IfcPermeableCoveringProperties - FrameDepth: 0.055 m
Qto_DoorBaseQuantities - Area: 2.94 m2

# IfcDoor: Doorset_Fire Rated Double Door_ASSA ABLOY ES_ES04_Hardware 3D:1600 x 2100 mm (1750 x 2175 mm), Doorset_Fire Rated Double Door_ASSA ABLOY ES_ES04_Hardware 3D:1600 x 2100 mm (1750 x 2175 mm):1348410
In: RDC
Type - PredefinedType: DOOR; OperationType: DOUBLE_DOOR_SINGLE_SWING; Material: Hollow Metal_Natural Anodised, Steel_Natural Anodised
Type - Doorset_Fire Rated Double Door_ASSA ABLOY ES_ES04_Hardware 3D:1600 x 2100 mm (1750 x 2175 mm):1348410:1 - PanelOperation: SWINGING
Type - Pset_DoorCommon - IsExternal: no; FireRating: From El30 to El120 (the range depends of frame and door panel)
OverallHeight: 2.185 m; OverallWidth: 1.77 m
Pset_DoorCommon - Reference: 1600 x 2100 mm (1750 x 2175 mm)
Pset_EnvironmentalImpactIndicators - Reference: 1600 x 2100 mm (1750 x 2175 mm)
IfcPermeableCoveringProperties - FrameDepth: 0.055 m
Qto_DoorBaseQuantities - Area: 3.36 m2

# IfcDoor: Int. Simple:PP (0.63m x 2.04m) (22)
Type - PredefinedType: DOOR; Material: Finition Peinture - Blanc satiné, Bois - Panneau de porte, Bois - Cadre de porte (2)
Type - Pset_DoorCommon - IsExternal: no
OverallHeight: 2.075 m; OverallWidth: 0.8 m; Material: Finition Peinture - Blanc satiné, Bois - Panneau de porte, Bois - Cadre de porte
Pset_DoorCommon - Reference: PP (0.63m x 2.04m)
Pset_EnvironmentalImpactIndicators - Reference: PP (0.63m x 2.04m)
Qto_DoorBaseQuantities - Area: 1.4892 m2
Name (Int. Simple:PP (0.63m x 2.04m):...) | In
1017777 | RDC
1017973 | RDC
1018439 | RDC
1018578 | RDC
1043250 | RDC
1043291 | RDC
1043917 | RDC
1043972 | RDC
1045238 | RDC
1307965 | RDC
1383527 | R+1 fini
1383594 | R+1 fini
1383632 | R+1 fini
1390544 | R+1 fini
1390611 | R+1 fini
1390707 | R+1 fini
1390825 | R+1 fini
1390901 | R+1 fini
1390956 | R+1 fini
1390996 | R+1 fini
1391136 | R+1 fini
1391185 | R+1 fini

# IfcDoor: Int. Simple:PP (0.73m x 2.04m) (31)
Type - PredefinedType: DOOR; Material: Finition Peinture - Blanc satiné, Bois - Panneau de porte, Bois - Cadre de porte (2)
Type - Pset_DoorCommon - IsExternal: no; ThermalTransmittance: 3.7021 kg/K/s3
OverallHeight: 2.075 m; OverallWidth: 0.8 m; Material: Finition Peinture - Blanc satiné, Bois - Panneau de porte, Bois - Cadre de porte
Pset_DoorCommon - Reference: PP (0.73m x 2.04m)
Pset_EnvironmentalImpactIndicators - Reference: PP (0.73m x 2.04m)
Qto_DoorBaseQuantities - Area: 1.4892 m2
Name (Int. Simple:PP (0.73m x 2.04m):...) | In
1017392 | RDC
1017514 | RDC
1046237 | RDC
1046280 | RDC
1046309 | RDC
1046356 | RDC
1046381 | RDC
1046417 | RDC
1046453 | RDC
1046531 | RDC
1046565 | RDC
1046593 | RDC
1046623 | RDC
1307840 | RDC
1307901 | RDC
1308352 | RDC
1386057 | R+1 fini
1386096 | R+1 fini
1388147 | R+1 fini
1388201 | R+1 fini
1388227 | R+1 fini
1388277 | R+1 fini
1388305 | R+1 fini
1388345 | R+1 fini
1388387 | R+1 fini
1388460 | R+1 fini
1388488 | R+1 fini
1388513 | R+1 fini
1388550 | R+1 fini
1389227 | R+1 fini
1389253 | R+1 fini

# IfcDoor: Int. Simple:PP (0.83m x 2.04m) (52)
Type - PredefinedType: DOOR; Material: Finition Peinture - Blanc satiné, Bois - Panneau de porte, Bois - Cadre de porte (2)
Type - Pset_DoorCommon - IsExternal: no; ThermalTransmittance: 3.7021 kg/K/s3
OverallHeight: 2.075 m; OverallWidth: 0.9 m; Material: Finition Peinture - Blanc satiné, Bois - Panneau de porte, Bois - Cadre de porte
Pset_DoorCommon - Reference: PP (0.83m x 2.04m)
Pset_EnvironmentalImpactIndicators - Reference: PP (0.83m x 2.04m)
Qto_DoorBaseQuantities - Area: 1.6932 m2
Name (Int. Simple:PP (0.83m x 2.04m):...) | In
1016745 | RDC
1016813 | RDC
1017294 | RDC
1017827 | RDC
1018028 | RDC
1018371 | RDC
1018640 | RDC
1043350 | RDC
1043424 | RDC
1044047 | RDC
1044104 | RDC
1044425 | RDC
1044468 | RDC
1044680 | RDC
1044905 | RDC
1045949 | RDC
1046028 | RDC
1046067 | RDC
1046112 | RDC
1046152 | RDC
1046210 | RDC
1046691 | RDC
1046747 | RDC
1046787 | RDC
1046820 | RDC
1046860 | RDC
1388095 | R+1 fini
1388611 | R+1 fini
1388665 | R+1 fini
1388700 | R+1 fini
1388738 | R+1 fini
1388779 | R+1 fini
1388830 | R+1 fini
1388908 | R+1 fini
1388956 | R+1 fini
1389014 | R+1 fini
1389066 | R+1 fini
1389157 | R+1 fini
1389353 | R+1 fini
1389451 | R+1 fini
1389502 | R+1 fini
1389708 | R+1 fini
1389756 | R+1 fini
1389992 | R+1 fini
1390048 | R+1 fini
1390119 | R+1 fini
1390160 | R+1 fini
1390211 | R+1 fini
1390272 | R+1 fini
1390328 | R+1 fini
1390387 | R+1 fini
1390434 | R+1 fini

# IfcDoor: Int. Simple:PP (0.93m x 2.04m) (35)
Type - PredefinedType: DOOR; Material: Finition Peinture - Blanc satiné, Bois - Panneau de porte, Bois - Cadre de porte (2)
Type - Pset_DoorCommon - IsExternal: no
OverallHeight: 2.075 m; OverallWidth: 1 m; Material: Finition Peinture - Blanc satiné, Bois - Panneau de porte, Bois - Cadre de porte
Pset_DoorCommon - Reference: PP (0.93m x 2.04m)
Pset_EnvironmentalImpactIndicators - Reference: PP (0.93m x 2.04m)
Qto_DoorBaseQuantities - Area: 1.8972 m2
Name (Int. Simple:PP (0.93m x 2.04m):...) | In
1017082 | RDC
1017149 | RDC
1044512 | RDC
1044596 | RDC
1045145 | RDC
1046899 | RDC
1215908 | RDC
1386270 | R+1 fini
1386381 | R+1 fini
1386432 | R+1 fini
1386523 | R+1 fini
1386580 | R+1 fini
1386642 | R+1 fini
1386674 | R+1 fini
1386738 | R+1 fini
1386813 | R+1 fini
1386921 | R+1 fini
1386968 | R+1 fini
1387041 | R+1 fini
1387085 | R+1 fini
1387166 | R+1 fini
1387225 | R+1 fini
1387313 | R+1 fini
1387372 | R+1 fini
1387401 | R+1 fini
1387455 | R+1 fini
1387596 | R+1 fini
1387673 | R+1 fini
1387706 | R+1 fini
1387764 | R+1 fini
1387796 | R+1 fini
1387856 | R+1 fini
1388026 | R+1 fini
1389581 | R+1 fini
1389666 | R+1 fini

# IfcDoor: Int. Simple:PP Iso (0.93m x 2.04m), Int. Simple:PP Iso (0.93m x 2.04m):1046990
In: RDC
Type - PredefinedType: DOOR; Material: Finition Peinture - Blanc satiné, Bois - Panneau de porte, Bois - Cadre de porte (2)
Type - Pset_DoorCommon - IsExternal: no
OverallHeight: 2.075 m; OverallWidth: 1 m; Material: Finition Peinture - Blanc satiné, Bois - Panneau de porte, Bois - Cadre de porte
Pset_DoorCommon - IsExternal: yes; Reference: PP Iso (0.93m x 2.04m)
Pset_EnvironmentalImpactIndicators - Reference: PP Iso (0.93m x 2.04m)
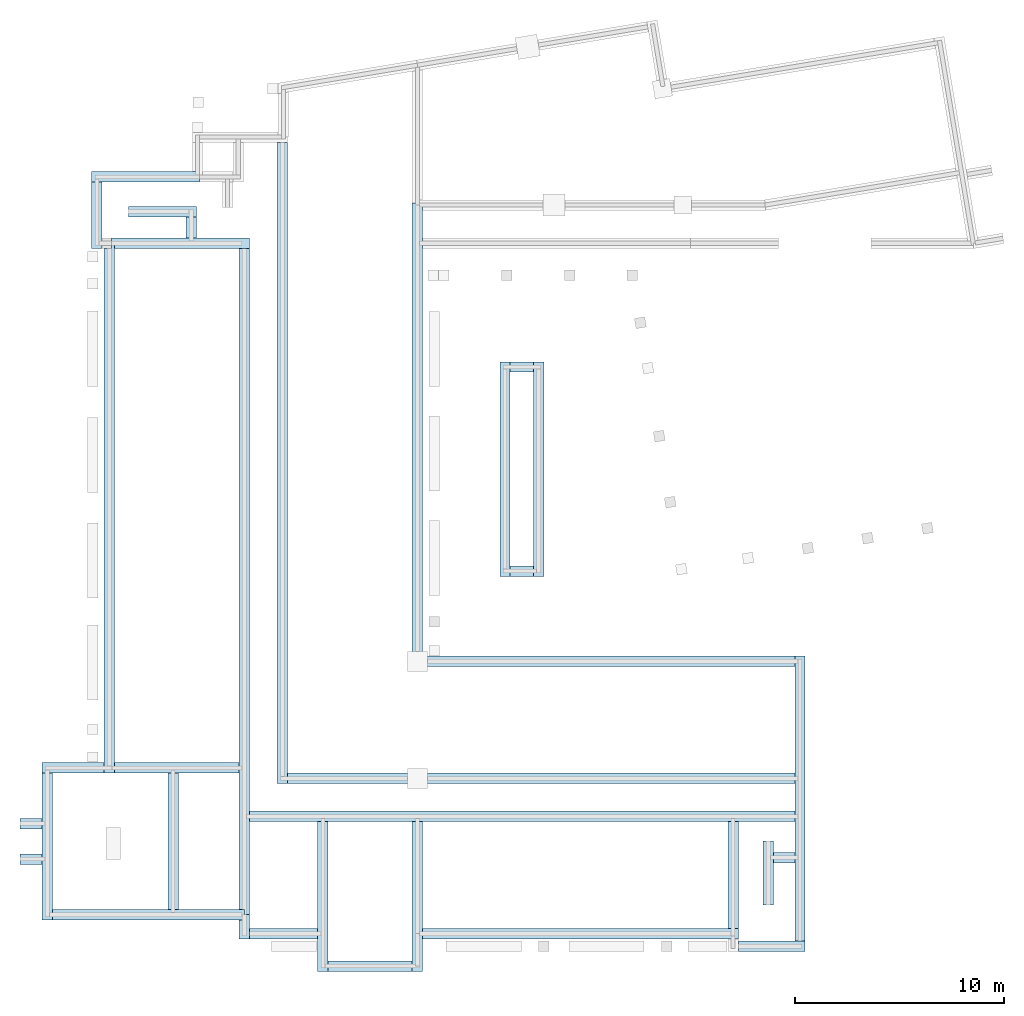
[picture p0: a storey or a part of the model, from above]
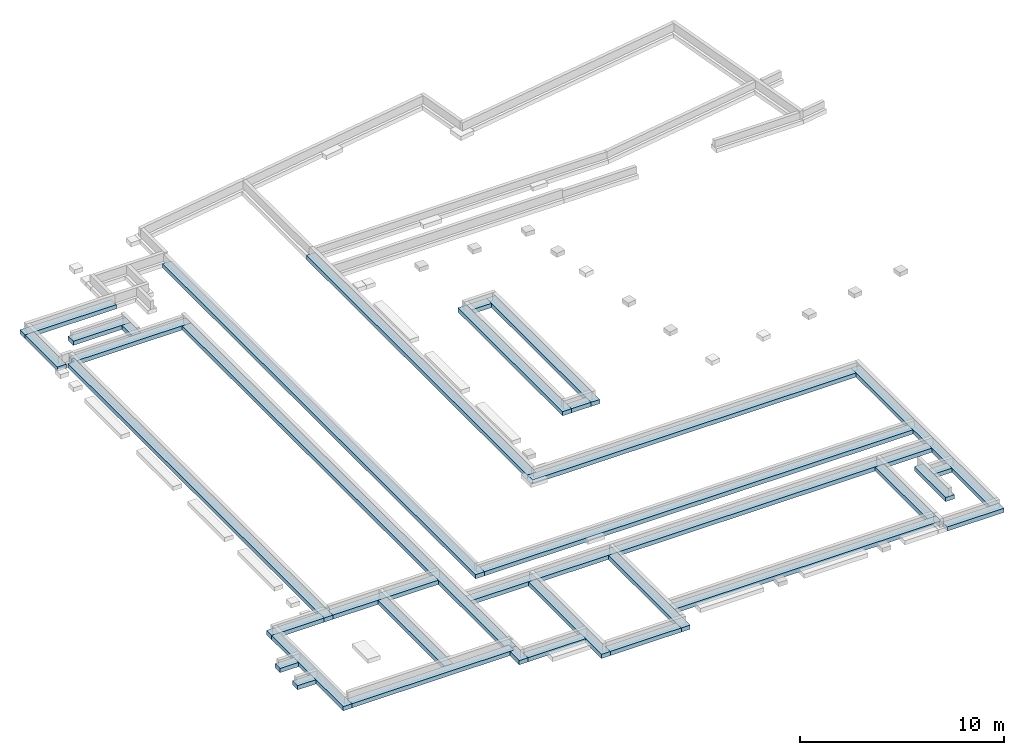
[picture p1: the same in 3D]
Properties of the parts of a building model (IFC4), part 3 of 5

# IfcDoor: Int. Simple:PP Iso (0.93m x 2.04m), Int. Simple:PP Iso (0.93m x 2.04m):1046990
Qto_DoorBaseQuantities - Area: 1.8972 m2

# IfcDoor: Int. Simple:PP PF 1/2h (0.93m x 2.04m) (37)
In: RDC
Type - PredefinedType: DOOR; Material: Finition Peinture - Blanc satiné, Bois - Panneau de porte, Bois - Cadre de porte (2)
Type - Pset_DoorCommon - IsExternal: no
OverallHeight: 2.075 m; OverallWidth: 1 m; Material: Finition Peinture - Blanc satiné, Bois - Panneau de porte, Bois - Cadre de porte
Pset_DoorCommon - Reference: PP PF 1/2h (0.93m x 2.04m)
Pset_EnvironmentalImpactIndicators - Reference: PP PF 1/2h (0.93m x 2.04m)
Qto_DoorBaseQuantities - Area: 1.8972 m2
Name (Int. Simple:PP PF 1/2h (0.93m x 2.04m):...)
1016908
1017017
1017195
1017902
1018095
1018238
1018295
1043497
1043554
1043774
1043852
1044213
1044270
1045014
1045081
1045310
1045332
1045390
1045452
1045503
1045542
1045599
1045657
1045709
1045828
1045900
1047044
1047104
1047146
1047177
1047226
1047337
1047363
1047400
1047440
1047537
1218352

# IfcDoor: K-LINE PORTE GT NEUF KLGT-1VT-FRA:K-LINE PORTE GT NEUF KLGT-1VT-FRA, K-LINE PORTE GT NEUF KLGT-1VT-FRA:K-LINE PORTE GT NEUF KLGT-1VT-FRA:1428674
In: R+1 fini
Type - PredefinedType: DOOR; Classification: B2030110 Exterior Glazed Doors - Aluminum (Uniformat); Material: Acier inoxydable, brossé, Verre, K.Line Intemporel Taupe (7022 S) - JK (2), K.Line Accessoire Blanc - KQ (2), K.Line Vintage Anodisé Argent - AC
Type - Pset_DoorCommon - IsExternal: yes
Type - Pset_ManufacturerTypeInformation - Manufacturer: K.LINE
OverallHeight: 2.132 m; OverallWidth: 1.2765 m; Material: Acier inoxydable, brossé, Verre, K.Line Intemporel Taupe (7022 S) - JK, K.Line Accessoire Blanc - KQ, K.Line Vintage Anodisé Argent - AC
Pset_DoorCommon - Reference: K-LINE PORTE GT NEUF KLGT-1VT-FRA
Pset_EnvironmentalImpactIndicators - Reference: K-LINE PORTE GT NEUF KLGT-1VT-FRA
Qto_DoorBaseQuantities - Area: 2.25225 m2

# IfcDoor: K-LINE PORTE GT RENO-applique-KLGT-2VT-FRA-IM:K-LINE PORTE GT RENO-applique-KLGT-2VT-FRA-IM (3)
In: RDC
Type - PredefinedType: DOOR; Classification: B2030110 Exterior Glazed Doors - Aluminum (Uniformat); Material: K.Line Intemporel Blanc satiné (9016 S) - KQ (4), Bois, Isolant rigide, Verre, Acier inoxydable, brossé, K.Line Vintage Anodisé Argent - AC
Type - Pset_DoorCommon - IsExternal: yes
Type - Pset_ManufacturerTypeInformation - Manufacturer: K.LINE
OverallHeight: 1.8 m; OverallWidth: 2.8 m; Material: K.Line Intemporel Blanc satiné (9016 S) - KQ, Bois, Isolant rigide, Verre, Acier inoxydable, brossé, K.Line Vintage Anodisé Argent - AC
Pset_DoorCommon - Reference: K-LINE PORTE GT RENO-applique-KLGT-2VT-FRA-IM
Pset_EnvironmentalImpactIndicators - Reference: K-LINE PORTE GT RENO-applique-KLGT-2VT-FRA-IM
Qto_DoorBaseQuantities - Area: 5.04 m2
Name (K-LINE PORTE GT RENO-applique-KLGT-2VT-FRA-IM:K-LINE PORTE GT RENO-applique-KLGT-2VT-FRA-IM:...)
847966
848532
1341801

# IfcDoor: K-LINE PORTE GT RENO-applique-KLGT-2VT-FRA:K-LINE PORTE GT RENO-applique-KLGT-2VT-FRA, K-LINE PORTE GT RENO-applique-KLGT-2VT-FRA:K-LINE PORTE GT RENO-applique-KLGT-2VT-FRA:850735
In: RDC
Type - PredefinedType: DOOR; Classification: B2030110 Exterior Glazed Doors - Aluminum (Uniformat); Material: K.Line Intemporel Blanc satiné (9016 S) - KQ (2), Bois, K.Line Intemporel Taupe (7022 S) - JK (2), Verre, K.Line Accessoire Blanc - KQ, Acier inoxydable, brossé, K.Line Accessoires Noir - FQ, K.Line Vintage Anodisé Argent - AC
Type - Pset_DoorCommon - IsExternal: yes
Type - Pset_ManufacturerTypeInformation - Manufacturer: K.LINE
OverallHeight: 1.92 m; OverallWidth: 2.31 m; Material: K.Line Intemporel Blanc satiné (9016 S) - KQ, Bois, K.Line Intemporel Taupe (7022 S) - JK, Verre, K.Line Accessoire Blanc - KQ, Acier inoxydable, brossé, K.Line Accessoires Noir - FQ, K.Line Vintage Anodisé Argent - AC
Pset_DoorCommon - Reference: K-LINE PORTE GT RENO-applique-KLGT-2VT-FRA
Pset_EnvironmentalImpactIndicators - Reference: K-LINE PORTE GT RENO-applique-KLGT-2VT-FRA
Qto_DoorBaseQuantities - Area: 4.4352 m2

# IfcDoor: K-LINE PORTE GT RENO-tunnel-KLGT-2VT-FRA-2F:K-LINE PORTE GT RENO-tunnel-KLGT-2VT-FRA-2F, K-LINE PORTE GT RENO-tunnel-KLGT-2VT-FRA-2F:K-LINE PORTE GT RENO-tunnel-KLGT-2VT-FRA-2F:846886
In: RDC
Type - PredefinedType: DOOR; Classification: B2030110 Exterior Glazed Doors - Aluminum (Uniformat); Material: Verre, K.Line Intemporel Blanc satiné (9016 S) - KQ (3), K.Line Intemporel Taupe (7022 S) - JK (2), K.Line Accessoire Blanc - KQ, Acier inoxydable, brossé, K.Line Accessoires Noir - FQ, K.Line Vintage Anodisé Argent - AC
Type - Pset_DoorCommon - IsExternal: yes
Type - Pset_ManufacturerTypeInformation - Manufacturer: K.LINE
OverallHeight: 3 m; OverallWidth: 2.8 m; Material: Verre, K.Line Intemporel Blanc satiné (9016 S) - KQ, K.Line Intemporel Taupe (7022 S) - JK, K.Line Accessoire Blanc - KQ, Acier inoxydable, brossé, K.Line Accessoires Noir - FQ, K.Line Vintage Anodisé Argent - AC
Pset_DoorCommon - Reference: K-LINE PORTE GT RENO-tunnel-KLGT-2VT-FRA-2F
Pset_EnvironmentalImpactIndicators - Reference: K-LINE PORTE GT RENO-tunnel-KLGT-2VT-FRA-2F
Qto_DoorBaseQuantities - Area: 8.4 m2

# IfcDoor: K-LINE PORTE GT RENO-tunnel-KLGT-2VT-FRA:K-LINE PORTE GT RENO-tunnel-KLGT-2VT-FRA (2)
In: RDC
Type - PredefinedType: DOOR; Classification: B2030110 Exterior Glazed Doors - Aluminum (Uniformat); Material: Verre, K.Line Intemporel Taupe (7022 S) - JK (2), K.Line Intemporel Blanc satiné (9016 S) - KQ (2), K.Line Accessoire Blanc - KQ, Acier inoxydable, brossé, K.Line Accessoires Noir - FQ, K.Line Vintage Anodisé Argent - AC
Type - Pset_DoorCommon - IsExternal: yes
Type - Pset_ManufacturerTypeInformation - Manufacturer: K.LINE
OverallHeight: 2.225 m; OverallWidth: 1.4021 m; Material: Verre, K.Line Intemporel Taupe (7022 S) - JK, K.Line Intemporel Blanc satiné (9016 S) - KQ, K.Line Accessoire Blanc - KQ, Acier inoxydable, brossé, K.Line Accessoires Noir - FQ, K.Line Vintage Anodisé Argent - AC
Pset_DoorCommon - Reference: K-LINE PORTE GT RENO-tunnel-KLGT-2VT-FRA
Pset_EnvironmentalImpactIndicators - Reference: K-LINE PORTE GT RENO-tunnel-KLGT-2VT-FRA
Qto_DoorBaseQuantities - Area: 3.11967 m2
Name (K-LINE PORTE GT RENO-tunnel-KLGT-2VT-FRA:K-LINE PORTE GT RENO-tunnel-KLGT-2VT-FRA:...)
849318
849695

# IfcDoor: K-LINE RENO-tunnel Porte Entrée 1vt - Perspective MAHJONG:K-LINE RENO-tunnel Porte Entrée 1vt - Perspective MAHJONG, K-LINE RENO-tunnel Porte Entrée 1vt - Perspective MAHJONG:K-LINE RENO-tunnel Porte Entrée 1vt - Perspective MAHJONG:958533
In: RDC
Type - PredefinedType: DOOR; Classification: B2030110 Exterior Glazed Doors - Aluminum (Uniformat); Material: K.Line Intemporel Gris foncé (7016 S) - EC (2), K.Line Vintage Anodisé Argent - AC (2), K.Line Acier inoxydable, brossé, Verre sablé, K.Line Tendance Gris sablé (2900) - NX
Type - Pset_DoorCommon - IsExternal: yes
Type - Pset_ManufacturerTypeInformation - Manufacturer: K.LINE
OverallHeight: 0.91 m; OverallWidth: 2.155 m; Material: K.Line Intemporel Gris foncé (7016 S) - EC, K.Line Vintage Anodisé Argent - AC, K.Line Acier inoxydable, brossé, Verre sablé, K.Line Tendance Gris sablé (2900) - NX
Pset_DoorCommon - Reference: K-LINE RENO-tunnel Porte Entrée 1vt - Perspective MAHJONG
Pset_EnvironmentalImpactIndicators - Reference: K-LINE RENO-tunnel Porte Entrée 1vt - Perspective MAHJONG
Qto_DoorBaseQuantities - Area: 1.96105 m2

# IfcFlowTerminal: 135042737:135042737 (71)
Type - Material: CERAMICA BLANCA, <Unnamed>
Pset_EnvironmentalImpactIndicators - Reference: 135042737
Name (135042737:135042737:...) | In
1064316 | RDC
1064507 | RDC
1064711 | RDC
1064789 | RDC
1064841 | RDC
1064873 | RDC
1064907 | RDC
1064939 | RDC
1064973 | RDC
1065005 | RDC
1065043 | RDC
1065075 | RDC
1065109 | RDC
1065126 | RDC
1065149 | RDC
1065168 | RDC
1065187 | RDC
1065206 | RDC
1114299 | RDC
1114586 | RDC
1114671 | RDC
1115221 | 18
1115347 | RDC
1115434 | RDC
1115535 | RDC
1115616 | RDC
1115711 | RDC
1115878 | RDC
1115909 | RDC
1116192 | RDC
1116253 | RDC
1116324 | RDC
1116669 | RDC
1118422 | RDC
1405522 | R+1 fini
1405677 | R+1 fini
1405728 | R+1 fini
1405797 | R+1 fini
1405840 | R+1 fini
1405911 | R+1 fini
1405980 | R+1 fini
1406117 | R+1 fini
1406162 | R+1 fini
1406213 | R+1 fini
1406258 | R+1 fini
1406373 | R+1 fini
1406612 | R+1 fini
1406669 | R+1 fini
1406906 | R+1 fini
1407039 | 64
1407198 | R+1 fini
1407847 | R+1 fini
1407960 | R+1 fini
1408027 | R+1 fini
1408132 | R+1 fini
1408165 | R+1 fini
1408334 | R+1 fini
1408389 | R+1 fini
1408510 | R+1 fini
1408671 | R+1 fini
1408808 | R+1 fini
1408977 | R+1 fini
1409140 | R+1 fini
1409201 | R+1 fini
1409354 | R+1 fini
1409403 | R+1 fini
1409526 | R+1 fini
1409577 | R+1 fini
1409690 | R+1 fini
1409733 | R+1 fini
1409860 | R+1 fini

# IfcFlowTerminal: BC_STROHM_WC_MT-PLUS_BTW WC:Inodoro BTW MT Plus - Blanco (41)
Type - Material: STROHM_Porcelain_White, STROHM_Metal_Chrome
Type - Pset_ManufacturerTypeInformation - Manufacturer: STROHM TEKA
Pset_EnvironmentalImpactIndicators - Reference: Inodoro BTW MT Plus - Blanco
Name (BC_STROHM_WC_MT-PLUS_BTW WC:Inodoro BTW MT Plus - Blanco:...) | In
1054396 | RDC
1054515 | RDC
1054692 | 22
1054869 | RDC
1055000 | RDC
1113427 | RDC
1113542 | RDC
1113601 | RDC
1113758 | RDC
1113811 | RDC
1115067 | 18
1116840 | RDC
1116975 | RDC
1117072 | RDC
1117151 | RDC
1117240 | RDC
1117479 | RDC
1117574 | RDC
1117655 | RDC
1117730 | RDC
1117837 | RDC
1117892 | RDC
1118042 | RDC
1403279 | R+1 fini
1403352 | R+1 fini
1403411 | R+1 fini
1403742 | R+1 fini
1403966 | R+1 fini
1404047 | R+1 fini
1404322 | R+1 fini
1404387 | R+1 fini
1404496 | R+1 fini
1404543 | R+1 fini
1404618 | R+1 fini
1404655 | R+1 fini
1404977 | R+1 fini
1405066 | R+1 fini
1405129 | R+1 fini
1405212 | R+1 fini
1405263 | R+1 fini
1405362 | R+1 fini

# IfcFlowTerminal: Sanitary_Wash-Basins_DELABIE_454122-Wall-mounted-MINERALCAST-wash-tro postraitement:Sanitary_Wash-Basins_DELABIE_454122-Wall-mounted-MINERALCAST-wash-tro postraitement (3)
Type - Material: 454122 Wall-mounted MINERALCAST wash trough - 454122 - BLANC
Pset_EnvironmentalImpactIndicators - Reference: Sanitary_Wash-Basins_DELABIE_454122-Wall-mounted-MINERALCAST-wash-tro postraitement
Name (Sanitary_Wash-Basins_DELABIE_454122-Wall-mounted-MINERALCAST-wash-tro postraitement:Sanitary_Wash-Basins_DELABIE_454122-Wall-mounted-MINERALCAST-wash-tro postraitement:...) | In
1060894 | 25
1114927 | 24
1407619 | 65

# IfcFooting: Semelle filante:SF 50x25ht (55)
In: Arase inf soubassement
Type - PredefinedType: STRIP_FOOTING
Material: Maçonnerie - Béton
Pset_EnvironmentalImpactIndicators - Reference: SF 50x25ht; sets with these values: 4
Qto_FootingBaseQuantities - Length: 0.25 m
Name (Semelle filante:SF 50x25ht:...) | CrossSectionArea (m2) | OuterSurfaceArea (m2) | GrossSurfaceArea (m2) | GrossVolume (m3) = NetVolume (m3) | Width (m) | Height (m)
292364 | 4.9898 | 5.23546 | 15.2151 | 1.24745
292376 | 6.705 | 6.955 | 20.365 | 1.67625 | 13.41 | 0.5
292388 | 1.515 | 1.765 | 4.795 | 0.37875 | 3.03 | 0.5
292396 | 5.58359 | 5.83359 | 17.0008 | 1.3959 | 11.1672 | 0.5
292511 | 3.37672 | 3.62844 | 10.3819 | 0.84418
292529 | 1.05988 | 1.3116 | 3.43135 | 0.264969
294629 | 2.58 | 2.83 | 7.99 | 0.645 | 5.16 | 0.5
294641 | 1.59 | 1.84 | 5.02 | 0.3975 | 3.18 | 0.5
294653 | 0.22 | 0.47 | 0.91 | 0.055 | 0.44 | 0.5
294665 | 12.585 | 12.9225 | 38.0925 | 3.14625
294677 | 1.485 | 1.735 | 4.705 | 0.37125 | 2.97 | 0.5
294685 | 3.51 | 3.76 | 10.78 | 0.8775 | 7.02 | 0.5
294697 | 4.59 | 4.84 | 14.02 | 1.1475 | 0.5 | 9.18
294709 | 0.5175 | 0.83 | 1.865 | 0.129375
294727 | 1.63 | 1.88 | 5.14 | 0.4075 | 3.26 | 0.5
294745 | 7.55 | 7.8 | 22.9 | 1.8875 | 15.1 | 0.5
294757 | 0.3 | 0.55 | 1.15 | 0.075 | 0.6 | 0.5
294769 | 1.6 | 1.85 | 5.05 | 0.4 | 3.2 | 0.5
294797 | 6.815 | 7.065 | 20.695 | 1.70375 | 13.63 | 0.5
294809 | 9.15 | 9.4 | 27.7 | 2.2875 | 18.3 | 0.5
294823 | 10.8375 | 11.0875 | 32.7625 | 2.70937 | 21.675 | 0.5
294841 | 6.40851 | 6.65851 | 19.4755 | 1.60213 | 12.817 | 0.5
299845 | 5.13 | 5.38 | 15.64 | 1.2825 | 10.26 | 0.5
299857 | 5.13 | 5.38 | 15.64 | 1.2825 | 10.26 | 0.5
299869 | 0.555 | 0.805 | 1.915 | 0.13875 | 1.11 | 0.5
299881 | 0.555 | 0.805 | 1.915 | 0.13875 | 1.11 | 0.5
299899 | 2.38402 | 2.69584 | 7.46388 | 0.596005
299911 | 0.665083 | 0.980379 | 2.31054 | 0.166271
299933 | 0.6 | 0.85 | 2.05 | 0.15 | 1.2 | 0.5
299947 | 2.105 | 2.355 | 6.565 | 0.52625 | 4.21 | 0.5
299959 | 8.22738 | 8.56531 | 25.0201 | 2.05685
299979 | 4.63579 | 4.88621 | 14.1578 | 1.15895
299993 | 3.13098 | 3.4202 | 9.68217 | 0.782746
300005 | 2.16705 | 2.53 | 6.8641 | 0.541763
300017 | 0.7375 | 1.075 | 2.55 | 0.184375
300029 | 0.95 | 1.2 | 3.1 | 0.2375 | 1.9 | 0.5
300041 | 0.7625 | 1.05 | 2.575 | 0.190625
300059 | 0.605 | 0.855 | 2.065 | 0.15125 | 1.21 | 0.5
300077 | 1.62 | 1.87 | 5.11 | 0.405 | 3.24 | 0.5
300089 | 0.51 | 0.76 | 1.78 | 0.1275 | 1.02 | 0.5
300101 | 3.2675 | 3.555 | 10.09 | 0.816875
300113 | 15.87 | 16.1825 | 47.9225 | 3.9675
300121 | 15.3375 | 15.5875 | 46.2625 | 3.83437 | 30.675 | 0.5
300133 | 2.98 | 3.23 | 9.19 | 0.745 | 5.96 | 0.5
300145 | 3.26 | 3.51 | 10.03 | 0.815 | 6.52 | 0.5
300157 | 13.04 | 13.29 | 39.37 | 3.26 | 26.08 | 0.5
300169 | 12.13 | 12.38 | 36.64 | 3.0325 | 24.26 | 0.5
300181 | 3.58 | 3.83 | 10.99 | 0.895 | 7.16 | 0.5
300193 | 3.58 | 3.83 | 10.99 | 0.895 | 7.16 | 0.5
300201 | 2.01 | 2.26 | 6.28 | 0.5025 | 4.02 | 0.5
300219 | 2.555 | 2.805 | 7.915 | 0.63875 | 5.11 | 0.5
300237 | 1.535 | 1.785 | 4.855 | 0.38375 | 3.07 | 0.5
300249 | 0.51 | 0.76 | 1.78 | 0.1275 | 1.02 | 0.5
300932 | 0.525 | 0.775 | 1.825 | 0.13125 | 1.05 | 0.5
300950 | 0.525 | 0.775 | 1.825 | 0.13125 | 1.05 | 0.5

# IfcFurniture: Furniture_Armchairs_CIDER-LA-MANUFACTURE_Curl-Fauteuil:Curl-Fauteuil (2)
In: 10
Type - Material: Laiton, Mica Secret
Type - Pset_FurnitureTypeCommon - NominalHeight: 0.74 m
Type - Pset_ManufacturerTypeInformation - Manufacturer: CIDER
Pset_EnvironmentalImpactIndicators - Reference: Curl-Fauteuil; sets with these values: 2
Name (Furniture_Armchairs_CIDER-LA-MANUFACTURE_Curl-Fauteuil:Curl-Fauteuil:...)
1241746
1242144

# IfcFurniture: Furniture_Chairs-Stools-Benches_CIDER-LA-MANUFACTURE_I-Task-Chaise-de-bureau:ITask - Chaise de bureau (2)
Type - Material: Noir, Sera Mare
Type - Pset_ManufacturerTypeInformation - Manufacturer: CIDER
Pset_EnvironmentalImpactIndicators - Reference: ITask - Chaise de bureau; sets with these values: 2
Name (Furniture_Chairs-Stools-Benches_CIDER-LA-MANUFACTURE_I-Task-Chaise-de-bureau:ITask - Chaise de bureau:...) | In
1243950 | 7
1246357 | 4

# IfcFurniture: Furniture_Chairs-Stools-Benches_Enea_Lottus-chair:Lottus chair (136)
Type - Material: <Unnamed>, RAL 9005 - Jet Black
Pset_EnvironmentalImpactIndicators - Reference: Lottus chair; sets with these values: 2
Name (Furniture_Chairs-Stools-Benches_Enea_Lottus-chair:Lottus chair:...) | In
1133052 | 39
1133175 | 39
1133306 | 39
1133471 | 40
1133504 | 40
1135682 | 43
1135715 | 43
1135750 | 44
1135787 | 44
1135824 | 47
1135857 | 47
1140434 | 40
1140638 | 47
1140670 | 47
1141082 | 44
1141116 | 44
1141260 | 43
1141290 | 43
1141591 | 46
1141839 | 46
1142242 | 46
1142335 | 46
1142592 | 45
1142610 | 45
1143006 | 45
1143024 | 45
1143470 | 42
1143490 | 42
1143696 | 42
1143718 | 42
1144064 | 41
1144084 | 41
1144315 | 30
1144333 | 41
1144894 | 31
1144977 | 28
1145144 | 27
1145190 | 32
1145270 | 29
1145742 | 18
1145861 | 33
1145897 | 35
1145931 | 37
1145967 | 34
1146001 | 36
1150254 | 40
1240383 | 11
1240454 | 11
1240579 | 11
1240664 | 11
1244219 | 7
1244406 | 7
1244495 | 7
1244618 | 7
1245444 | 5
1245519 | 5
1245582 | 5
1245651 | 5
1245730 | 5
1245837 | 5
1245894 | 5
1245955 | 5
1246026 | 5
1246069 | 5
1246128 | 5
1246275 | 5
1246358 | 4
1246359 | 4
1246926 | 1
1247031 | 1
1247092 | 1
1247149 | 1
1247204 | 1
1247285 | 1
1247360 | 1
1247421 | 1
1247466 | 1
1247583 | 1
1247670 | 1
1247727 | 1
1247860 | 1
1247933 | 1
1248000 | 1
1248093 | 1
1437041 | 75
1437208 | 75
1437272 | 75
1437351 | 75
1437440 | 73
1437523 | 73
1437576 | 73
1437703 | 73
1437772 | 72
1437873 | 72
1437924 | 69
1437985 | 69
1438048 | 72
1438141 | 72
1438204 | 69
1438291 | 69
1438354 | 68
1438421 | 68
1438486 | 68
1438581 | 68
1438658 | 54
1438817 | 53
1438898 | 51
1438971 | 52
1439062 | 50
1439213 | 49
1439352 | 56
1439433 | 55
1439520 | 57
1439593 | 59
1439678 | 58
1439749 | 61
1439930 | 62
1440013 | 66
1440172 | 66
1440245 | 67
1440328 | 67
1440373 | 66
1440476 | 67
1440531 | 67
1440590 | 70
1440673 | 70
1440714 | 70
1440793 | 70
1440852 | 71
1440909 | 71
1441045 | 71
1441173 | 71
1441226 | 74
1441343 | 74
1441410 | 74
1441497 | 74

# IfcFurniture: Furniture_Sofas-Armchairs_CIDER-LA-MANUFACTURE_Hawai-Canape-Modulable-module-droit:Hawai-Canape_Modulable_Droit (5)
In: 10
Type - Material: Sera Berry, Noir
Type - Pset_ManufacturerTypeInformation - Manufacturer: CIDER
Pset_EnvironmentalImpactIndicators - Reference: Hawai-Canape_Modulable_Droit; sets with these values: 2
Name (Furniture_Sofas-Armchairs_CIDER-LA-MANUFACTURE_Hawai-Canape-Modulable-module-droit:Hawai-Canape_Modulable_Droit:...)
1240925
1241150
1241247
1241426
1241453

# IfcFurniture: SSG_Firehouse_Bed_3_Drawers_LAM:Default (99)
Type - Classification: E20 Furnishings (Uniformat); Material: SSG_Metal_Nickel_Satin, SSG_7929_Huntington_Maple_WI, SSG_Wood_Plywood, SSG_Fabric
Type - Pset_ManufacturerTypeInformation - Manufacturer: Southwest Solutions Group_LEG
Pset_EnvironmentalImpactIndicators - Reference: Default; sets with these values: 2
Name (SSG_Firehouse_Bed_3_Drawers_LAM:Default:...) | In
1128503 | 39
1128882 | 39
1128999 | 39
1133633 | 40
1133643 | 40
1133651 | 40
1133663 | 40
1133673 | 43
1133681 | 43
1133689 | 43
1133697 | 43
1133707 | 44
1133717 | 44
1133725 | 44
1133735 | 44
1133743 | 47
1133751 | 47
1133759 | 47
1133767 | 47
1138631 | 46
1138838 | 46
1138846 | 45
1138854 | 42
1138862 | 41
1138926 | 45
1138934 | 42
1138942 | 41
1138990 | 46
1139057 | 46
1139067 | 45
1139079 | 42
1139089 | 41
1139216 | 45
1139226 | 42
1139236 | 41
1144545 | 30
1144555 | 31
1144978 | 28
1145145 | 27
1145191 | 32
1145268 | 29
1145548 | 18
1145862 | 33
1145898 | 35
1145932 | 37
1145965 | 34
1145999 | 36
1391515 | 49
1391694 | 50
1391799 | 51
1391936 | 52
1392046 | 53
1392161 | 54
1392313 | 55
1392462 | 56
1392573 | 57
1392666 | 58
1392775 | 59
1392931 | 61
1393044 | 62
1393518 | 66
1393631 | 66
1393828 | 66
1393885 | 67
1394016 | 67
1394122 | 67
1394255 | 67
1394320 | 70
1394433 | 70
1394534 | 70
1394779 | 70
1395019 | 71
1395136 | 71
1395227 | 71
1395390 | 71
1395654 | 74
1395777 | 74
1395880 | 74
1396069 | 74
1396291 | 68
1396404 | 68
1396497 | 68
1396694 | 68
1396978 | 69
1397121 | 69
1397385 | 69
1397582 | 69
1397738 | 72
1397895 | 72
1397976 | 72
1398129 | 72
1398393 | 73
1398492 | 73
1398581 | 73
1398822 | 73
1399016 | 75
1399167 | 75
1399252 | 75
1399419 | 75

# IfcFurniture: SSG_Table_Educational_Rectangle_LAM:Default (4)
Type - Classification: E20 Furnishings (Uniformat); Material: <Unnamed>, SSG_MIB_Paint_Silver, SSG_Designer_White_082_HAM
Type - Pset_ManufacturerTypeInformation - Manufacturer: Southwest Solutions Group_MIB
Pset_EnvironmentalImpactIndicators - Reference: Default; sets with these values: 2
Name (SSG_Table_Educational_Rectangle_LAM:Default:...) | In
1242323 | 7
1242568 | 7
1246355 | 4
1246356 | 4

# IfcFurniture: USM Kitos E table 900x900 700-1100:Pos. 1.8 (900x900/700-1110 mm = 35x35/28-44 inch) (100)
Type - Material: Acier, forgé, Caoutchouc, noir, <Unnamed>
Type - Pset_ManufacturerTypeInformation - Manufacturer: USM
Pset_EnvironmentalImpactIndicators - Reference: Pos. 1.8 (900x900/700-1110 mm = 35x35/28-44 inch); sets with these values: 2
Name (USM Kitos E table 900x900 700-1100:Pos. 1.8 (900x900/700-1110 mm = 35x35/28-44 inch):...) | In
1132670 | 39
1132787 | 39
1132882 | 39
1133470 | 40
1133503 | 40
1135681 | 43
1135714 | 43
1135749 | 44
1135786 | 44
1135823 | 47
1135856 | 47
1139433 | 47
1139588 | 47
1139950 | 44
1139984 | 44
1140051 | 43
1140148 | 43
1140234 | 40
1141590 | 46
1141838 | 46
1142241 | 46
1142334 | 46
1142591 | 45
1142609 | 45
1143005 | 45
1143023 | 45
1143469 | 42
1143489 | 42
1143695 | 42
1143717 | 42
1144063 | 41
1144083 | 41
1144314 | 30
1144332 | 41
1144893 | 31
1144976 | 28
1145143 | 27
1145189 | 32
1145269 | 29
1145741 | 18
1145860 | 33
1145896 | 35
1145930 | 37
1145966 | 34
1146000 | 36
1150253 | 40
1239912 | 11
1240336 | 11
1429060 | 49
1429149 | 50
1429325 | 51
1429418 | 52
1429543 | 53
1429628 | 54
1429880 | 59
1430015 | 58
1430072 | 57
1430175 | 56
1430224 | 55
1430603 | 62
1430688 | 61
1430935 | 66
1431014 | 66
1431125 | 66
1431293 | 67
1431428 | 67
1431891 | 67
1432006 | 67
1432485 | 70
1432493 | 70
1432708 | 70
1432718 | 70
1432728 | 71
1432736 | 71
1432744 | 71
1432752 | 71
1432760 | 74
1432768 | 74
1432776 | 74
1432784 | 74
1433874 | 75
1433995 | 75
1434487 | 75
1434568 | 75
1434635 | 73
1434716 | 73
1434791 | 73
1434894 | 73
1434941 | 72
1435016 | 72
1435083 | 72
1435192 | 72
1435245 | 69
1435300 | 69
1435357 | 69
1435416 | 69
1435479 | 68
1435548 | 68
1435597 | 68
1435678 | 68

# IfcFurniture: USM Kitos E table diam 1100 740 mm:Pos. 1.1 (diam 1100/700-1110 mm = 43/28-44 inch) (4)
In: 1
Type - Material: Acier, forgé, Caoutchouc, noir, <Unnamed>
Type - Pset_ManufacturerTypeInformation - Manufacturer: USM
Pset_EnvironmentalImpactIndicators - Reference: Pos. 1.1 (diam 1100/700-1110 mm = 43/28-44 inch); sets with these values: 2
Name (USM Kitos E table diam 1100 740 mm:Pos. 1.1 (diam 1100/700-1110 mm = 43/28-44 inch):...)
1246462
1246583
1246638
1246739

# IfcFurniture: USM Kitos M Plus table 1600x800 700-1200mm:Pos. 1.6 (1600x800/700-1200 mm = 63x32/28-47 inch) (3)
In: 5
Type - Material: Caoutchouc, noir, Acier, forgé, <Unnamed>
Type - Pset_ManufacturerTypeInformation - Manufacturer: USM
Pset_EnvironmentalImpactIndicators - Reference: Pos. 1.6 (1600x800/700-1200 mm = 63x32/28-47 inch); sets with these values: 2
Name (USM Kitos M Plus table 1600x800 700-1200mm:Pos. 1.6 (1600x800/700-1200 mm = 63x32/28-47 inch):...)
1245043
1245212
1245275

# IfcLightFixture: plafonnier led cfa type 2:497537 MADERA 3 LED LED 620X620MM 5200LM 840 IP44 PRM WHITE(41W) (24)
Type - Material: Materiał Przesłony PMMA LENA, WHITE
Type - Pset_ElectricalDeviceCommon - PowerFactor: 0.93
Type - Pset_ManufacturerTypeInformation - Manufacturer: LENA LIGHTING S. A.
Pset_EnvironmentalImpactIndicators - Reference: 497537 MADERA 3 LED LED 620X620MM 5200LM 840 IP44 PRM WHITE(41W); sets with these values: 2
Name (plafonnier led cfa type 2:497537 MADERA 3 LED LED 620X620MM 5200LM 840 IP44 PRM WHITE(41W):...) | In
1264078 | Arase inf longrines
1301492 | RDC
1301561 | RDC
1301750 | RDC
1302616 | RDC
1302713 | RDC
1302798 | RDC
1302972 | RDC
1303047 | RDC
1303155 | RDC
1303216 | RDC
1303281 | RDC
1303361 | RDC
1303449 | RDC
1303516 | RDC
1303572 | RDC
1303646 | RDC
1303711 | RDC
1303914 | RDC
1304065 | RDC
1304136 | RDC
1304228 | RDC
1304279 | RDC
1304386 | RDC

# IfcLightFixture: plafonnier led type 4:TYPE - (Ref 350 - Plafonnier Pline lg1128mm - 17W) Colour - (RADIAL RAL9003) (61)
Type - Material: RADIAN RAL7047, RADIAN RAL9003
Pset_EnvironmentalImpactIndicators - Reference: TYPE - (Ref 350 - Plafonnier Pline lg1128mm - 17W) Colour - (RADIAL RAL9003); sets with these values: 2
Name (plafonnier led type 4:TYPE - (Ref 350 - Plafonnier Pline lg1128mm - 17W) Colour - (RADIAL RAL9003):...) | In
1277623 | RDC
1280975 | RDC
1281329 | RDC
1281449 | RDC
1282304 | RDC
1283196 | RDC
1284496 | RDC
1284953 | RDC
1285541 | RDC
1285883 | RDC
1286123 | RDC
1292902 | RDC
1293112 | RDC
1293442 | RDC
1293602 | RDC
1293842 | RDC
1294112 | RDC
1294412 | RDC
1294612 | RDC
1294902 | RDC
1295102 | RDC
1297216 | RDC
1297438 | RDC
1297788 | RDC
1297948 | RDC
1298238 | RDC
1298518 | RDC
1298788 | RDC
1298988 | RDC
1537447 | RDC
1541164 | R+1 fini
1543258 | RDC
1544161 | RDC
1545642 | RDC
1545746 | RDC
1545962 | RDC
1546088 | RDC
1546740 | R+1 fini
1547298 | R+1 fini
1549350 | R+1 fini
1550614 | R+1 fini
1550710 | R+1 fini
1551598 | R+1 fini
1551970 | R+1 fini
1552462 | R+1 fini
1552846 | R+1 fini
1554380 | R+1 fini
1555074 | R+1 fini
1555236 | R+1 fini
1555500 | R+1 fini
1555932 | R+1 fini
1556052 | R+1 fini
1556328 | R+1 fini
1556868 | R+1 fini
1557252 | R+1 fini
1557492 | R+1 fini
1558116 | R+1 fini
1558511 | R+1 fini
1558939 | R+1 fini
1559648 | R+1 fini
1559740 | R+1 fini

# IfcLightFixture: plafonnier led type 4:TYPE - (Ref 351 - Plafonnier Pline lg1408mm - 21W) Colour - (RADIAL RAL9003) (6)
In: RDC
Type - Material: RADIAN RAL9003, RADIAN RAL7047
Pset_EnvironmentalImpactIndicators - Reference: TYPE - (Ref 351 - Plafonnier Pline lg1408mm - 21W) Colour - (RADIAL RAL9003); sets with these values: 2
Name (plafonnier led type 4:TYPE - (Ref 351 - Plafonnier Pline lg1408mm - 21W) Colour - (RADIAL RAL9003):...)
1304542
1305290
1305780
1306140
1306202
1306442

# IfcLightFixture: spot encastré:210 lm 2W 840 max.700mA 3,1V 90° IP20 (191)
Type - Material: Intra lighting - White
Type - Pset_ManufacturerTypeInformation - Manufacturer: Intra lighting
Pset_EnvironmentalImpactIndicators - Reference: 210 lm 2W 840 max.700mA 3,1V 90° IP20; sets with these values: 2
Name (spot encastré:210 lm 2W 840 max.700mA 3,1V 90° IP20:...) | In
1262448 | RDC
1262819 | RDC
1262829 | RDC
1262837 | RDC
1262845 | RDC
1262855 | RDC
1262863 | RDC
1262873 | RDC
1262883 | RDC
1262891 | RDC
1262899 | RDC
1262907 | RDC
1262919 | RDC
1262929 | RDC
1262939 | RDC
1270324 | RDC
1270332 | RDC
1270344 | RDC
1270352 | RDC
1270360 | RDC
1270370 | RDC
1270378 | RDC
1270386 | RDC
1270394 | RDC
1270406 | RDC
1270414 | RDC
1270424 | RDC
1270432 | RDC
1270440 | RDC
1270448 | RDC
1270456 | RDC
1270470 | RDC
1270482 | RDC
1270494 | RDC
1270506 | RDC
1270514 | RDC
1270522 | RDC
1270530 | RDC
1270538 | RDC
1270546 | RDC
1270556 | RDC
1270564 | RDC
1270574 | RDC
1270582 | RDC
1270590 | RDC
1270598 | RDC
1270606 | RDC
1270612 | RDC
1270785 | RDC
1270795 | RDC
1270805 | RDC
1270813 | RDC
1270821 | RDC
1270829 | RDC
1270839 | RDC
1270847 | RDC
1270855 | RDC
1270863 | RDC
1270871 | RDC
1270932 | RDC
1270938 | RDC
1270946 | RDC
1270956 | RDC
1270964 | RDC
1270974 | RDC
1270982 | RDC
1270990 | RDC
1271000 | RDC
1271826 | RDC
1272537 | 37
1278510 | 36
1278511 | RDC
1278591 | RDC
1278592 | 35
1278602 | 34
1278603 | RDC
1278661 | RDC
1278662 | 33
1278701 | 18
1278745 | 18
1278805 | RDC
1278813 | 32
1279236 | 31
1279237 | RDC
1279243 | RDC
1279244 | 30
1279252 | 29
1279253 | RDC
1279261 | RDC
1279262 | 28
1279272 | RDC
1279273 | 27
1279310 | RDC
1279318 | 39
1279326 | RDC
1279334 | 40
1279500 | 43
1279530 | RDC
1279584 | RDC
1279703 | 44
1279771 | 47
1279779 | RDC
1279938 | 46
1279946 | RDC
1279956 | 45
1279990 | RDC
1279998 | RDC
1280006 | 42
1280053 | 41
1280061 | RDC
1312796 | RDC
1312874 | RDC
1314657 | RDC
1314685 | RDC
1525530 | Aras plafond 2.6 R+1
1525984 | 49
1527181 | Aras inf plancher haut RDC (dalle 29cm)
1527260 | 51
1527973 | Aras plafond 2.6 R+1
1527983 | 50
1527993 | 51
1528001 | Aras plafond 2.6 R+1
1528009 | Aras plafond 2.6 R+1
1528017 | 52
1528027 | 53
1528035 | Aras plafond 2.6 R+1
1528043 | Aras plafond 2.6 R+1
1528053 | 54
1528067 | Aras plafond 2.6 R+1
1528079 | 55
1528091 | 56
1528101 | Aras plafond 2.6 R+1
1528109 | Aras plafond 2.6 R+1
1528119 | 57
1528127 | 58
1528135 | Aras plafond 2.6 R+1
1528143 | Aras plafond 2.6 R+1
1528151 | 59
1528161 | 61
1528171 | Aras plafond 2.6 R+1
1528179 | Aras plafond 2.6 R+1
1528189 | 62
1528201 | 66
1528211 | Aras plafond 2.6 R+1
1528219 | Aras plafond 2.6 R+1
1528227 | 67
1528237 | 70
1528253 | Aras plafond 2.6 R+1
1528261 | Aras plafond 2.6 R+1
1528269 | 71
1528277 | 74
1528285 | Aras plafond 2.6 R+1
1528343 | 75
1528351 | Aras plafond 2.6 R+1
1528359 | Aras plafond 2.6 R+1
1528367 | 73
1528377 | 72
1528385 | Aras plafond 2.6 R+1
1528395 | Aras plafond 2.6 R+1
1528403 | 69
1528411 | 68
1528419 | Aras plafond 2.6 R+1
1534760 | R+1 fini
1535171 | Aras plafond 3 R+1
1535688 | R+1 fini
1536274 | R+1 fini
1536282 | R+1 fini
1536294 | R+1 fini
1536302 | R+1 fini
1536310 | R+1 fini
1536318 | R+1 fini
1536326 | R+1 fini
1536334 | R+1 fini
1536346 | R+1 fini
1536354 | R+1 fini
1536362 | R+1 fini
1536374 | R+1 fini
1536384 | R+1 fini
1536394 | R+1 fini
1536402 | R+1 fini
1536535 | R+1 fini
1536543 | R+1 fini
1536555 | R+1 fini
1536565 | R+1 fini
1536573 | R+1 fini
1536581 | R+1 fini
1536593 | R+1 fini
1536601 | R+1 fini
1536609 | R+1 fini
1536627 | R+1 fini
1567274 | R+1 fini

# IfcOpeningElement (373)
Name | In | PredefinedType | Depth (m) | Height (m) | Width (m)
Mur de base:Ext. Brique 20:322070 | RDC | OPENING | 0.2 | 1.8 | 2.84297 | Pset_EnvironmentalImpactIndicators - Reference: Ext. Brique 20; sets with these values: 2
Mur de base:Ext. Brique 20:322070 | RDC | RECESS | 0.11 | 1.8 | 2.8 | Pset_EnvironmentalImpactIndicators - Reference: K-LINE PORTE GT RENO-applique-KLGT-2VT-FRA-IM; sets with these values: 2
Mur de base:Ext. Brique 20:322618 | RDC | OPENING | 0.2 | 2.9995 | 2.77979 | Pset_EnvironmentalImpactIndicators - Reference: Ext. Brique 20; sets with these values: 2
Mur de base:Ext. Brique 20:322618 | RDC | RECESS | 0.11 | 3 | 2.8 | Pset_EnvironmentalImpactIndicators - Reference: K-LINE PORTE GT RENO-tunnel-KLGT-2VT-FRA-2F; sets with these values: 2
Mur de base:Ext. Brique 20:324371 | RDC | OPENING | 0.8 | 2.075 | 0.18 | Pset_EnvironmentalImpactIndicators - Reference: PP (0.73m x 2.04m); sets with these values: 2
Mur de base:Ext. Brique 20:324371 | RDC | OPENING | 0.8 | 2.075 | 0.2 | Pset_EnvironmentalImpactIndicators - Reference: PP (0.63m x 2.04m); sets with these values: 2
Mur de base:Ext. Brique 20:325546 | RDC | OPENING | Pset_EnvironmentalImpactIndicators - Reference: 2-OF Ouvrant à la française; sets with these values: 2; Qto_OpeningElementBaseQuantities - Area: 1.215 m2; Volume: 0.119252 m3
Mur de base:Ext. Brique 20:326305 | RDC | OPENING | 0.5048 | Pset_EnvironmentalImpactIndicators - Reference: ITE; sets with these values: 2; Qto_OpeningElementBaseQuantities - Area: 187.275 m2
Mur de base:Ext. Brique 20:326305 | RDC | OPENING | Pset_EnvironmentalImpactIndicators - Reference: 1-OF 0.9*1.55; sets with these values: 2; Qto_OpeningElementBaseQuantities - Area: 1.395 m2; Volume: 0.13231 m3
2 x Mur de base:ITE:348913 | RDC | OPENING | Pset_EnvironmentalImpactIndicators - Reference: 2-C Coulissant pvc 1.8*2.25; sets with these values: 2; Qto_OpeningElementBaseQuantities - Area: 4.05 m2; Volume: 0.289453 m3
Mur de base:ITE:348913 | RDC | OPENING | Pset_EnvironmentalImpactIndicators - Reference: 3 - OF Ouvrant francaise 0.9*1.35; sets with these values: 2; Qto_OpeningElementBaseQuantities - Area: 1.215 m2; Volume: 0.119252 m3
Mur de base:ITE:349132 | RDC | OPENING | Pset_EnvironmentalImpactIndicators - Reference: 2-C Coulissant pvc 1.8*2.25; sets with these values: 2; Qto_OpeningElementBaseQuantities - Area: 4.05 m2; Volume: 0.289453 m3
4 x Mur de base:ITE:349132 | RDC | OPENING | Pset_EnvironmentalImpactIndicators - Reference: 3 - OF Ouvrant francaise 0.9*1.35; sets with these values: 2; Qto_OpeningElementBaseQuantities - Area: 1.215 m2; Volume: 0.119252 m3
Mur de base:ITE:349132 | RDC | OPENING | 3.048 | 2 | 2.4 | Pset_EnvironmentalImpactIndicators - Reference: Doors - Industrial-Novoferm-Porte_de_garage_DL-3D; sets with these values: 2
5 x Mur de base:ITE:349801 | RDC | OPENING | Pset_EnvironmentalImpactIndicators - Reference: 1-OF 0.9*1.55; sets with these values: 2; Qto_OpeningElementBaseQuantities - Area: 1.395 m2; Volume: 0.13231 m3
5 x Mur de base:ITE:349801 | RDC | OPENING | Pset_EnvironmentalImpactIndicators - Reference: 2-OF Ouvrant à la française; sets with these values: 2; Qto_OpeningElementBaseQuantities - Area: 1.215 m2; Volume: 0.119252 m3
Mur de base:ITE:350511 | RDC | OPENING | Pset_EnvironmentalImpactIndicators - Reference: EN-2 Ensembles chassis fixes et à soufflet 1*5.65; sets with these values: 2; Qto_OpeningElementBaseQuantities - Area: 5.65 m2; Volume: 0.425762 m3
Mur de base:ITE:350811 | RDC | OPENING | 0.11 | 1.4 | 2.275 | Pset_EnvironmentalImpactIndicators - Reference: ITE; sets with these values: 2
Mur de base:ITE:350811 | RDC | OPENING | 0.2 | 2.225 | 1.4021 | Pset_EnvironmentalImpactIndicators - Reference: K-LINE PORTE GT RENO-tunnel-KLGT-2VT-FRA; sets with these values: 2
Mur de base:ITE:350811 | RDC | OPENING | 0.8 | 2.075 | 0.18 | Pset_EnvironmentalImpactIndicators - Reference: PP (0.73m x 2.04m); sets with these values: 2
Mur de base:ITE:350811 | RDC | OPENING | 0.8 | 2.075 | 0.2 | Pset_EnvironmentalImpactIndicators - Reference: PP (0.63m x 2.04m); sets with these values: 2
Mur de base:ITE:350811 | RDC | OPENING | Pset_EnvironmentalImpactIndicators - Reference: 2-OF Ouvrant à la française; sets with these values: 2; Qto_OpeningElementBaseQuantities - Area: 1.215 m2; Volume: 0.119252 m3
6 x Mur de base:ITE:351062 | RDC | OPENING | Pset_EnvironmentalImpactIndicators - Reference: 1-OF 0.9*1.55; sets with these values: 2; Qto_OpeningElementBaseQuantities - Area: 1.395 m2; Volume: 0.13231 m3
6 x Mur de base:ITE:351062 | RDC | OPENING | Pset_EnvironmentalImpactIndicators - Reference: 2-OF Ouvrant à la française; sets with these values: 2; Qto_OpeningElementBaseQuantities - Area: 1.215 m2; Volume: 0.119252 m3
8 x Mur de base:ITE:351445 | RDC | OPENING | Pset_EnvironmentalImpactIndicators - Reference: 1-OF 0.9*1.55; sets with these values: 2; Qto_OpeningElementBaseQuantities - Area: 1.395 m2; Volume: 0.13231 m3
7 x Mur de base:ITE:351445 | RDC | OPENING | Pset_EnvironmentalImpactIndicators - Reference: 2-OF Ouvrant à la française; sets with these values: 2; Qto_OpeningElementBaseQuantities - Area: 1.215 m2; Volume: 0.119252 m3
Mur de base:ITE:351445 | RDC | OPENING | Pset_EnvironmentalImpactIndicators - Reference: 4-OF fenêtre accés pompier; sets with these values: 2; Qto_OpeningElementBaseQuantities - Area: 1.665 m2; Volume: 0.151897 m3
Mur de base:ITE:351644 | RDC | OPENING | 0.11 | 1.8 | 2.7858 | Pset_EnvironmentalImpactIndicators - Reference: ITE; sets with these values: 2
2 x Mur de base:ITE:351644 | RDC | OPENING | 0.11 | 1.5 | 2.3 | Pset_EnvironmentalImpactIndicators - Reference: ITE; sets with these values: 2
2 x Mur de base:ITE:351940 | RDC | OPENING | Pset_EnvironmentalImpactIndicators - Reference: 1-OS châssis à sopufflet PVC + imposte fixes 1.5*2.3; sets with these values: 2; Qto_OpeningElementBaseQuantities - Area: 3.45 m2; Volume: 0.256752 m3
Mur de base:ITE:352209 | RDC | OPENING | 0.11 | 1.82 | 2.8 | Pset_EnvironmentalImpactIndicators - Reference: ITE; sets with these values: 2
2 x Mur de base:ITE:352209 | RDC | OPENING | Pset_EnvironmentalImpactIndicators - Reference: 1-OS châssis à sopufflet PVC + imposte fixes 1.5*2.3; sets with these values: 2; Qto_OpeningElementBaseQuantities - Area: 3.45 m2; Volume: 0.256752 m3
Mur de base:ITE:352209 | RDC | OPENING | 0.2 | 1.8 | 2.8 | Pset_EnvironmentalImpactIndicators - Reference: K-LINE PORTE GT RENO-applique-KLGT-2VT-FRA-IM; sets with these values: 2
6 x Mur de base:ITE:352759 | RDC | OPENING | Pset_EnvironmentalImpactIndicators - Reference: 1-OB Châssis OB + Imposte fixe 0.8*2.3; sets with these values: 2; Qto_OpeningElementBaseQuantities - Area: 1.84 m2; Volume: 0.168698 m3
4 x Mur de base:ITE:352759 | RDC | OPENING | Pset_EnvironmentalImpactIndicators - Reference: 1-F Châssis fixe + Imposte fixe 0.8*2.3; sets with these values: 2; Qto_OpeningElementBaseQuantities - Area: 1.84 m2; Volume: 0.168698 m3
3 x Mur de base:ITE:352921 | RDC | OPENING | Pset_EnvironmentalImpactIndicators - Reference: 1-F Châssis fixe + Imposte fixe 0.8*2.3; sets with these values: 2; Qto_OpeningElementBaseQuantities - Area: 1.84 m2; Volume: 0.168698 m3
3 x Mur de base:ITE:352921 | RDC | OPENING | Pset_EnvironmentalImpactIndicators - Reference: 1-OB Châssis OB + Imposte fixe 0.8*2.3; sets with these values: 2; Qto_OpeningElementBaseQuantities - Area: 1.84 m2; Volume: 0.168698 m3
4 x Mur de base:ITE:353265 | RDC | OPENING | Pset_EnvironmentalImpactIndicators - Reference: 1-OB Châssis OB + Imposte fixe 0.8*2.3; sets with these values: 2; Qto_OpeningElementBaseQuantities - Area: 1.84 m2; Volume: 0.168698 m3
3 x Mur de base:ITE:353265 | RDC | OPENING | Pset_EnvironmentalImpactIndicators - Reference: 1-F Châssis fixe + Imposte fixe 0.8*2.3; sets with these values: 2; Qto_OpeningElementBaseQuantities - Area: 1.84 m2; Volume: 0.168698 m3
3 x Mur de base:ITE:353265 | RDC | OPENING | Pset_EnvironmentalImpactIndicators - Reference: 2-OS Châssis à souflet 0.7*0.75; sets with these values: 2; Qto_OpeningElementBaseQuantities - Area: 0.525 m2; Volume: 0.0671256 m3
Mur de base:ITE:353755 | RDC | OPENING | Pset_EnvironmentalImpactIndicators - Reference: EN-2 Ensembles chassis fixes et à soufflet 1*5.65; sets with these values: 2; Qto_OpeningElementBaseQuantities - Area: 5.65 m2; Volume: 0.425762 m3
Mur de base:Ext. Brique 20:354626 | RDC | OPENING | 0.2 | 1.92 | 2.36551 | Pset_EnvironmentalImpactIndicators - Reference: Ext. Brique 20; sets with these values: 2
Mur de base:Ext. Brique 20:354626 | RDC | RECESS | 0.11 | 1.92 | 2.31 | Pset_EnvironmentalImpactIndicators - Reference: K-LINE PORTE GT RENO-applique-KLGT-2VT-FRA; sets with these values: 2
Mur de base:ITE:355384 | RDC | OPENING | 0.11 | 1.13649 | 2.1692 | Pset_EnvironmentalImpactIndicators - Reference: ITE; sets with these values: 2
Mur de base:ITE:355384 | RDC | OPENING | Pset_EnvironmentalImpactIndicators - Reference: K-LINE PORTE GT NEUF KLGT-1VT-FRA; sets with these values: 2; Qto_OpeningElementBaseQuantities - Area: 2.25225 m2; Volume: 0.452496 m3
Mur de base:Int. Plâtre 100 mm:980557 | RDC | OPENING | 1 | 2.075 | 0.07 | Pset_EnvironmentalImpactIndicators - Reference: PP PF 1/2h (0.93m x 2.04m); sets with these values: 2
Mur de base:Générique - Int. 70 mm:1004303 | RDC | OPENING | 0.8 | 2.075 | 0.07 | Pset_EnvironmentalImpactIndicators - Reference: PP (0.63m x 2.04m); sets with these values: 2
Mur de base:Générique - Int. 70 mm:1004499 | RDC | OPENING | 0.8 | 2.075 | 0.07 | Pset_EnvironmentalImpactIndicators - Reference: PP (0.63m x 2.04m); sets with these values: 2
Mur de base:Générique - Int. 70 mm:1006930 | RDC | OPENING | 1 | 2.075 | 0.07 | Pset_EnvironmentalImpactIndicators - Reference: PP (0.93m x 2.04m); sets with these values: 2
Mur de base:Générique - Int. 70 mm:1013973 | RDC | OPENING | 0.8 | 2.075 | 0.07 | Pset_EnvironmentalImpactIndicators - Reference: PP (0.63m x 2.04m); sets with these values: 2
Mur de base:Générique - Int. 70 mm:1014823 | RDC | OPENING | 0.8 | 2.075 | 0.07 | Pset_EnvironmentalImpactIndicators - Reference: PP (0.63m x 2.04m); sets with these values: 2
Mur de base:Générique - Int. 70 mm:1015947 | RDC | OPENING | 0.8 | 2.075 | 0.07 | Pset_EnvironmentalImpactIndicators - Reference: PP (0.63m x 2.04m); sets with these values: 2
Mur de base:Int. Plâtre 100 mm:1355637 | R+1 fini | OPENING | 0.9 | 2.075 | 0.1 | Pset_EnvironmentalImpactIndicators - Reference: PP (0.83m x 2.04m); sets with these values: 2
Mur de base:Générique - Int. 70 mm:1380232 | R+1 fini | OPENING | 1 | 2.075 | 0.07 | Pset_EnvironmentalImpactIndicators - Reference: PP (0.93m x 2.04m); sets with these values: 2
Mur de base:Ext. Brique 20:321509 | RDC | OPENING | 0.2 | 1.8 | 2.8
2 x Mur de base:Ext. Brique 20:321509 | RDC | OPENING
2 x Mur de base:Ext. Brique 20:322070 | RDC | OPENING
10 x Mur de base:Ext. Brique 20:322618 | RDC | OPENING
10 x Mur de base:Ext. Brique 20:323265 | RDC | OPENING
12 x Mur de base:Ext. Brique 20:324200 | RDC | OPENING
Mur de base:Ext. Brique 20:324371 | RDC | OPENING | 0.2 | 2.225 | 1.4021
Mur de base:Ext. Brique 20:324371 | RDC | OPENING
Mur de base:Ext. Brique 20:324618 | RDC | OPENING
2 x Mur de base:Ext. Brique 20:325546 | RDC | OPENING
Mur de base:Ext. Brique 20:326493 | RDC | OPENING
Int. Simple:PP PF 1/2h (0.93m x 2.04m):1045081:1 | RDC | OPENING | 0.18 | 1 | 2.075
Int. Simple:PP (0.63m x 2.04m):1045238:1 | RDC | OPENING | 0.18 | 0.8 | 2.075
Int. Simple:PP PF 1/2h (0.93m x 2.04m):1045332:1 | RDC | OPENING | 0.18 | 1 | 2.075
Int. Simple:PP PF 1/2h (0.93m x 2.04m):1045452:1 | RDC | OPENING | 0.18 | 1 | 2.075
Int. Simple:PP PF 1/2h (0.93m x 2.04m):1045542:1 | RDC | OPENING | 0.18 | 1 | 2.075
Int. Simple:PP PF 1/2h (0.93m x 2.04m):1045657:1 | RDC | OPENING | 0.18 | 1 | 2.075
Int. Simple:PP PF 1/2h (0.93m x 2.04m):1045709:1 | RDC | OPENING | 0.18 | 1 | 2.075
Doorset_Fire Rated Double Door_ASSA ABLOY ES_ES04_Hardware 3D:1400 x 2100 mm (1550 x 2175 mm):1307667:1 | RDC | OPENING | 0.18 | 1.57 | 2.185
Doorset_Fire Rated Double Door_ASSA ABLOY ES_ES04_Hardware 3D:1400 x 2100 mm (1550 x 2175 mm):1307702:1 | RDC | OPENING | 0.18 | 1.57 | 2.185
Int. Simple:PP (0.63m x 2.04m):1307965:1 | RDC | OPENING | 0.18 | 0.8 | 2.075
Doorset_Fire Rated Double Door_ASSA ABLOY ES_ES04_Hardware 3D:1400 x 2100 mm (1550 x 2175 mm):1309626:1 | RDC | OPENING | 0.18 | 1.57 | 2.185
Int. Simple:PP PF 1/2h (0.93m x 2.04m):1045014:1 | RDC | OPENING | 0.18 | 1 | 2.075
Int. Simple:PP PF 1/2h (0.93m x 2.04m):1045310:1 | RDC | OPENING | 0.18 | 1 | 2.075
Int. Simple:PP PF 1/2h (0.93m x 2.04m):1045390:1 | RDC | OPENING | 0.18 | 1 | 2.075
Int. Simple:PP PF 1/2h (0.93m x 2.04m):1045503:1 | RDC | OPENING | 0.18 | 1 | 2.075
Int. Simple:PP PF 1/2h (0.93m x 2.04m):1045599:1 | RDC | OPENING | 0.18 | 1 | 2.075
Int. Simple:PP PF 1/2h (0.93m x 2.04m):1045828:1 | RDC | OPENING | 0.18 | 1 | 2.075
Int. Simple:PP PF 1/2h (0.93m x 2.04m):1045900:1 | RDC | OPENING | 0.18 | 1 | 2.075
Doorset_Fire Rated Double Door_ASSA ABLOY ES_ES04_Hardware 3D:1400 x 2100 mm (1550 x 2175 mm):1307207:1 | RDC | OPENING | 0.18 | 1.57 | 2.185
Doorset_Fire Rated Double Door_ASSA ABLOY ES_ES04_Hardware 3D:1400 x 2100 mm (1550 x 2175 mm):1307767:1 | RDC | OPENING | 0.18 | 1.57 | 2.185
Int. Simple:PP (0.73m x 2.04m):1307840:1 | RDC | OPENING | 0.18 | 0.8 | 2.075
Int. Simple:PP (0.73m x 2.04m):1307901:1 | RDC | OPENING | 0.18 | 0.8 | 2.075
Doorset_Fire Rated Double Door_ASSA ABLOY ES_ES04_Hardware 3D:1200 x 2100 mm (1350 x 2175 mm):1308139:1 | RDC | OPENING | 0.18 | 1.37 | 2.185
Int. Simple:PP (0.73m x 2.04m):1017514:1 | RDC | OPENING | 0.18 | 0.8 | 2.075
Int. Simple:PP PF 1/2h (0.93m x 2.04m):1018095:1 | RDC | OPENING | 0.18 | 1 | 2.075
Int. Simple:PP PF 1/2h (0.93m x 2.04m):1018295:1 | RDC | OPENING | 0.18 | 1 | 2.075
Int. Simple:PP PF 1/2h (0.93m x 2.04m):1043554:1 | RDC | OPENING | 0.18 | 1 | 2.075
Int. Simple:PP PF 1/2h (0.93m x 2.04m):1043852:1 | RDC | OPENING | 0.18 | 1 | 2.075
Int. Simple:PP PF 1/2h (0.93m x 2.04m):1044270:1 | RDC | OPENING | 0.18 | 1 | 2.075
Doorset_Fire Rated Double Door_ASSA ABLOY ES_ES04_Hardware 3D:1400 x 2100 mm (1550 x 2175 mm):1308300:1 | RDC | OPENING | 0.18 | 1.57 | 2.185
Int. Simple:PP (0.73m x 2.04m):1308352:1 | RDC | OPENING | 0.18 | 0.8 | 2.075
Doorset_Fire Rated Double Door_ASSA ABLOY ES_ES04_Hardware 3D:1400 x 2100 mm (1550 x 2175 mm):1308541:1 | RDC | OPENING | 0.18 | 1.57 | 2.185
Int. Simple:PP PF 1/2h (0.93m x 2.04m):1047226:1 | RDC | OPENING | 0.18 | 1 | 2.075
Int. Simple:PP PF 1/2h (0.93m x 2.04m):1047337:1 | RDC | OPENING | 0.18 | 1 | 2.075
Int. Simple:PP PF 1/2h (0.93m x 2.04m):1047363:1 | RDC | OPENING | 0.18 | 1 | 2.075
Int. Simple:PP PF 1/2h (0.93m x 2.04m):1047044:1 | RDC | OPENING | 0.18 | 1 | 2.075
Int. Simple:PP PF 1/2h (0.93m x 2.04m):1047104:1 | RDC | OPENING | 0.18 | 1 | 2.075
Int. Simple:PP PF 1/2h (0.93m x 2.04m):1047146:1 | RDC | OPENING | 0.18 | 1 | 2.075
Doorset_Fire Rated Double Door_ASSA ABLOY ES_ES04_Hardware 3D:1400 x 2100 mm (1550 x 2175 mm):1307156:1 | RDC | OPENING | 0.18 | 1.57 | 2.185
Doorset_Fire Rated Double Door_ASSA ABLOY ES_ES04_Hardware 3D:1600 x 2100 mm (1750 x 2175 mm):1348410:1 | RDC | OPENING | 0.2 | 1.77 | 2.185
Mur de base:ITE:348913 | RDC | OPENING | 0.11 | 0.91 | 2.155
Mur de base:ITE:351940 | RDC | OPENING | 0.11 | 1.8 | 2.8
Mur de base:ITE:352759 | RDC | OPENING | 0.11 | 3 | 2.8
Mur de base:ITE:355384 | RDC | OPENING | 0.11 | 2.225 | 1.4021
Mur de base:ITE:355710 | RDC | OPENING | 0.11 | 1.92 | 2.31
Int. Simple:PP (0.93m x 2.04m):1215908:1 | RDC | OPENING | 0.1 | 1 | 2.075
Int. Simple:PP PF 1/2h (0.93m x 2.04m):1047177:1 | RDC | OPENING | 0.1 | 1 | 2.075
Int. Simple:PP PF 1/2h (0.93m x 2.04m):1047440:1 | RDC | OPENING | 0.1 | 1 | 2.075
Int. Simple:PP PF 1/2h (0.93m x 2.04m):1047537:1 | RDC | OPENING | 0.1 | 1 | 2.075
Int. Simple:PP (0.83m x 2.04m):1046210:1 | RDC | OPENING | 0.07 | 0.9 | 2.075
Int. Simple:PP (0.73m x 2.04m):1046356:1 | RDC | OPENING | 0.07 | 0.8 | 2.075
Int. Simple:PP (0.83m x 2.04m):1046152:1 | RDC | OPENING | 0.07 | 0.9 | 2.075
Int. Simple:PP (0.73m x 2.04m):1046309:1 | RDC | OPENING | 0.07 | 0.8 | 2.075
Int. Simple:PP (0.83m x 2.04m):1046112:1 | RDC | OPENING | 0.07 | 0.9 | 2.075
Int. Simple:PP (0.73m x 2.04m):1046280:1 | RDC | OPENING | 0.07 | 0.8 | 2.075
Int. Simple:PP (0.83m x 2.04m):1045949:1 | RDC | OPENING | 0.07 | 0.9 | 2.075
Int. Simple:PP (0.73m x 2.04m):1046237:1 | RDC | OPENING | 0.07 | 0.8 | 2.075
Int. Simple:PP (0.83m x 2.04m):1046067:1 | RDC | OPENING | 0.07 | 0.9 | 2.075
Int. Simple:PP (0.73m x 2.04m):1046417:1 | RDC | OPENING | 0.07 | 0.8 | 2.075
Int. Simple:PP (0.83m x 2.04m):1046028:1 | RDC | OPENING | 0.07 | 0.9 | 2.075
Int. Simple:PP (0.73m x 2.04m):1046381:1 | RDC | OPENING | 0.07 | 0.8 | 2.075
Int. Simple:PP PF 1/2h (0.93m x 2.04m):1047400:1 | RDC | OPENING | 0.1 | 1 | 2.075
Int. Simple:PP (0.73m x 2.04m):1046565:1 | RDC | OPENING | 0.07 | 0.8 | 2.075
Int. Simple:PP (0.83m x 2.04m):1046787:1 | RDC | OPENING | 0.07 | 0.9 | 2.075
Int. Simple:PP (0.73m x 2.04m):1046531:1 | RDC | OPENING | 0.07 | 0.8 | 2.075
Int. Simple:PP (0.83m x 2.04m):1046747:1 | RDC | OPENING | 0.07 | 0.9 | 2.075
Int. Simple:PP (0.73m x 2.04m):1046453:1 | RDC | OPENING | 0.07 | 0.8 | 2.075
Int. Simple:PP (0.83m x 2.04m):1046691:1 | RDC | OPENING | 0.07 | 0.9 | 2.075
Int. Simple:PP (0.73m x 2.04m):1046623:1 | RDC | OPENING | 0.07 | 0.8 | 2.075
Int. Simple:PP (0.83m x 2.04m):1046860:1 | RDC | OPENING | 0.07 | 0.9 | 2.075
Int. Simple:PP (0.73m x 2.04m):1046593:1 | RDC | OPENING | 0.07 | 0.8 | 2.075
Int. Simple:PP (0.83m x 2.04m):1046820:1 | RDC | OPENING | 0.07 | 0.9 | 2.075
Int. Simple:PP PF 1/2h (0.93m x 2.04m):1017195:1 | RDC | OPENING | 0.1 | 1 | 2.075
Int. Simple:PP PF 1/2h (0.93m x 2.04m):1016908:1 | RDC | OPENING | 0.1 | 1 | 2.075
Int. Simple:PP PF 1/2h (0.93m x 2.04m):1017017:1 | RDC | OPENING | 0.1 | 1 | 2.075
Int. Simple:PP (0.93m x 2.04m):1017082:1 | RDC | OPENING | 0.07 | 1 | 2.075
Int. Simple:PP (0.93m x 2.04m):1017149:1 | RDC | OPENING | 0.07 | 1 | 2.075
Int. Simple:PP (0.83m x 2.04m):1017294:1 | RDC | OPENING | 0.07 | 0.9 | 2.075
Int. Simple:PP (0.83m x 2.04m):1016745:1 | RDC | OPENING | 0.07 | 0.9 | 2.075
Int. Simple:PP (0.83m x 2.04m):1016813:1 | RDC | OPENING | 0.07 | 0.9 | 2.075
Int. Simple:PP (0.83m x 2.04m):1018028:1 | RDC | OPENING | 0.07 | 0.9 | 2.075
Int. Simple:PP (0.63m x 2.04m):1017973:1 | RDC | OPENING | 0.07 | 0.8 | 2.075
Int. Simple:PP (0.83m x 2.04m):1018640:1 | RDC | OPENING | 0.07 | 0.9 | 2.075
Int. Simple:PP (0.83m x 2.04m):1043424:1 | RDC | OPENING | 0.07 | 0.9 | 2.075
Int. Simple:PP (0.63m x 2.04m):1018578:1 | RDC | OPENING | 0.07 | 0.8 | 2.075
Int. Simple:PP (0.63m x 2.04m):1043291:1 | RDC | OPENING | 0.07 | 0.8 | 2.075
Int. Simple:PP (0.83m x 2.04m):1044104:1 | RDC | OPENING | 0.07 | 0.9 | 2.075
Int. Simple:PP (0.63m x 2.04m):1043972:1 | RDC | OPENING | 0.07 | 0.8 | 2.075
Int. Simple:PP (0.83m x 2.04m):1044905:1 | RDC | OPENING | 0.1 | 0.9 | 2.075
Int. Simple:PP (0.93m x 2.04m):1044512:1 | RDC | OPENING | 0.07 | 1 | 2.075
Int. Simple:PP (0.83m x 2.04m):1044425:1 | RDC | OPENING | 0.07 | 0.9 | 2.075
Int. Simple:PP (0.83m x 2.04m):1044468:1 | RDC | OPENING | 0.07 | 0.9 | 2.075
Int. Simple:PP (0.93m x 2.04m):1044596:1 | RDC | OPENING | 0.07 | 1 | 2.075
Int. Simple:PP (0.83m x 2.04m):1044680:1 | RDC | OPENING | 0.07 | 0.9 | 2.075
Int. Simple:PP (0.93m x 2.04m):1045145:1 | RDC | OPENING | 0.07 | 1 | 2.075
Int. Simple:PP Iso (0.93m x 2.04m):1046990:1 | RDC | OPENING | 0.32 | 1 | 2.075
Doorset_Fire Rated Double Door_ASSA ABLOY ES_ES04_Hardware 3D:1400 x 2100 mm (1550 x 2175 mm):1320045:1 | RDC | OPENING | 0.2 | 1.57 | 2.185
Mur de base:Int. Plâtre 100 mm:1012093 | RDC | OPENING
Int. Simple:PP (0.63m x 2.04m):1043917:1 | RDC | OPENING | 0.07 | 0.8 | 2.075
Int. Simple:PP (0.83m x 2.04m):1044047:1 | RDC | OPENING | 0.07 | 0.9 | 2.075
Int. Simple:PP (0.83m x 2.04m):1043350:1 | RDC | OPENING | 0.07 | 0.9 | 2.075
Int. Simple:PP (0.83m x 2.04m):1018371:1 | RDC | OPENING | 0.07 | 0.9 | 2.075
Int. Simple:PP (0.63m x 2.04m):1018439:1 | RDC | OPENING | 0.07 | 0.8 | 2.075
Int. Simple:PP (0.63m x 2.04m):1043250:1 | RDC | OPENING | 0.07 | 0.8 | 2.075
Int. Simple:PP (0.83m x 2.04m):1017827:1 | RDC | OPENING | 0.07 | 0.9 | 2.075
Int. Simple:PP (0.63m x 2.04m):1017777:1 | RDC | OPENING | 0.07 | 0.8 | 2.075
Int. Simple:PP (0.93m x 2.04m):1046899:1 | RDC | OPENING | 0.07 | 1 | 2.075
Int. Simple:PP (0.73m x 2.04m):1017392:1 | RDC | OPENING | 0.18 | 0.8 | 2.075
Int. Simple:PP PF 1/2h (0.93m x 2.04m):1017902:1 | RDC | OPENING | 0.18 | 1 | 2.075
Int. Simple:PP PF 1/2h (0.93m x 2.04m):1018238:1 | RDC | OPENING | 0.18 | 1 | 2.075
Int. Simple:PP PF 1/2h (0.93m x 2.04m):1043497:1 | RDC | OPENING | 0.18 | 1 | 2.075
Int. Simple:PP PF 1/2h (0.93m x 2.04m):1043774:1 | RDC | OPENING | 0.18 | 1 | 2.075
Int. Simple:PP PF 1/2h (0.93m x 2.04m):1044213:1 | RDC | OPENING | 0.18 | 1 | 2.075
Int. Simple:PP PF 1/2h (0.93m x 2.04m):1218352:1 | RDC | OPENING | 0.07 | 1 | 2.075
Doorset_Fire Rated Double Door_ASSA ABLOY ES_ES04_Hardware 3D:1400 x 2100 mm (1550 x 2175 mm):1308184:1 | RDC | OPENING | 0.18 | 1.57 | 2.185
Doorset_Fire Rated Double Door_ASSA ABLOY ES_ES04_Hardware 3D:1400 x 2100 mm (1550 x 2175 mm):1308224:1 | RDC | OPENING | 0.18 | 1.57 | 2.185
Doorset_Fire Rated Double Door_ASSA ABLOY ES_ES04_Hardware 3D:1400 x 2100 mm (1550 x 2175 mm):1309054:1 | RDC | OPENING | 0.1 | 1.57 | 2.185
Doorset_Fire Rated Double Door_ASSA ABLOY ES_ES04_Hardware 3D:1400 x 2100 mm (1550 x 2175 mm):1309593:1 | RDC | OPENING | 0.1 | 1.57 | 2.185
Doorset_Fire Rated Double Door_ASSA ABLOY ES_ES04_Hardware 3D:1400 x 2100 mm (1550 x 2175 mm):1321607:1 | RDC | OPENING | 0.1 | 1.57 | 2.185
Mur de base:Ext. Brique 20:1340747 | RDC | OPENING | 0.2 | 1.8 | 2.8
2 x Mur de base:Ext. Brique 20:1340747 | RDC | OPENING
Int. Simple:PP (0.63m x 2.04m):1383527:1 | R+1 fini | OPENING | 0.2 | 0.8 | 2.075
Int. Simple:PP (0.63m x 2.04m):1383594:1 | R+1 fini | OPENING | 0.2 | 0.8 | 2.075
Doorset_Fire Rated Double Door_ASSA ABLOY ES_ES04_Hardware 3D:1400 x 2100 mm (1550 x 2175 mm):1383800:1 | R+1 fini | OPENING | 0.2 | 1.57 | 2.185
Doorset_Fire Rated Double Door_ASSA ABLOY ES_ES04_Hardware 3D:1400 x 2100 mm (1550 x 2175 mm):1384050:1 | R+1 fini | OPENING | 0.2 | 1.57 | 2.185
Doorset_Fire Rated Double Door_ASSA ABLOY ES_ES04_Hardware 3D:1400 x 2100 mm (1550 x 2175 mm):1385450:1 | R+1 fini | OPENING | 0.2 | 1.57 | 2.185
Int. Simple:PP (0.93m x 2.04m):1386270:1 | R+1 fini | OPENING | 0.2 | 1 | 2.075
Int. Simple:PP (0.93m x 2.04m):1386381:1 | R+1 fini | OPENING | 0.2 | 1 | 2.075
Int. Simple:PP (0.93m x 2.04m):1386432:1 | R+1 fini | OPENING | 0.2 | 1 | 2.075
Int. Simple:PP (0.93m x 2.04m):1386523:1 | R+1 fini | OPENING | 0.2 | 1 | 2.075
Int. Simple:PP (0.93m x 2.04m):1386580:1 | R+1 fini | OPENING | 0.2 | 1 | 2.075
Int. Simple:PP (0.93m x 2.04m):1386642:1 | R+1 fini | OPENING | 0.2 | 1 | 2.075
Int. Simple:PP (0.93m x 2.04m):1386674:1 | R+1 fini | OPENING | 0.2 | 1 | 2.075
Doorset_Fire Rated Double Door_ASSA ABLOY ES_ES04_Hardware 3D:1400 x 2100 mm (1550 x 2175 mm):1385787:1 | R+1 fini | OPENING | 0.2 | 1.57 | 2.185
Doorset_Fire Rated Double Door_ASSA ABLOY ES_ES04_Hardware 3D:1400 x 2100 mm (1550 x 2175 mm):1385849:1 | R+1 fini | OPENING | 0.2 | 1.57 | 2.185
Int. Simple:PP (0.73m x 2.04m):1386057:1 | R+1 fini | OPENING | 0.2 | 0.8 | 2.075
Int. Simple:PP (0.93m x 2.04m):1386738:1 | R+1 fini | OPENING | 0.2 | 1 | 2.075
Int. Simple:PP (0.93m x 2.04m):1387455:1 | R+1 fini | OPENING | 0.2 | 1 | 2.075
Int. Simple:PP (0.93m x 2.04m):1387673:1 | R+1 fini | OPENING | 0.2 | 1 | 2.075
Int. Simple:PP (0.93m x 2.04m):1387764:1 | R+1 fini | OPENING | 0.2 | 1 | 2.075
Int. Simple:PP (0.93m x 2.04m):1387856:1 | R+1 fini | OPENING | 0.2 | 1 | 2.075
Int. Simple:PP (0.93m x 2.04m):1388026:1 | R+1 fini | OPENING | 0.2 | 1 | 2.075
Doorset_Fire Rated Double Door_ASSA ABLOY ES_ES04_Hardware 3D:1400 x 2100 mm (1550 x 2175 mm):1385709:1 | R+1 fini | OPENING | 0.2 | 1.57 | 2.185
Doorset_Fire Rated Double Door_ASSA ABLOY ES_ES04_Hardware 3D:1400 x 2100 mm (1550 x 2175 mm):1385754:1 | R+1 fini | OPENING | 0.2 | 1.57 | 2.185
Int. Simple:PP (0.73m x 2.04m):1386096:1 | R+1 fini | OPENING | 0.2 | 0.8 | 2.075
Int. Simple:PP (0.93m x 2.04m):1387372:1 | R+1 fini | OPENING | 0.2 | 1 | 2.075
Int. Simple:PP (0.93m x 2.04m):1387401:1 | R+1 fini | OPENING | 0.2 | 1 | 2.075
Int. Simple:PP (0.93m x 2.04m):1387596:1 | R+1 fini | OPENING | 0.2 | 1 | 2.075
Int. Simple:PP (0.93m x 2.04m):1387706:1 | R+1 fini | OPENING | 0.2 | 1 | 2.075
Int. Simple:PP (0.93m x 2.04m):1387796:1 | R+1 fini | OPENING | 0.2 | 1 | 2.075
Int. Simple:PP (0.63m x 2.04m):1383632:1 | R+1 fini | OPENING | 0.2 | 0.8 | 2.075
Doorset_Fire Rated Double Door_ASSA ABLOY ES_ES04_Hardware 3D:1400 x 2100 mm (1550 x 2175 mm):1383826:1 | R+1 fini | OPENING | 0.2 | 1.57 | 2.185
Doorset_Fire Rated Double Door_ASSA ABLOY ES_ES04_Hardware 3D:1400 x 2100 mm (1550 x 2175 mm):1384081:1 | R+1 fini | OPENING | 0.2 | 1.57 | 2.185
Doorset_Fire Rated Double Door_ASSA ABLOY ES_ES04_Hardware 3D:1400 x 2100 mm (1550 x 2175 mm):1385410:1 | R+1 fini | OPENING | 0.2 | 1.57 | 2.185
Doorset_Fire Rated Double Door_ASSA ABLOY ES_ES04_Hardware 3D:1400 x 2100 mm (1550 x 2175 mm):1385954:1 | R+1 fini | OPENING | 0.2 | 1.57 | 2.185
Int. Simple:PP (0.93m x 2.04m):1386813:1 | R+1 fini | OPENING | 0.2 | 1 | 2.075
Int. Simple:PP (0.93m x 2.04m):1386921:1 | R+1 fini | OPENING | 0.2 | 1 | 2.075
Int. Simple:PP (0.93m x 2.04m):1386968:1 | R+1 fini | OPENING | 0.2 | 1 | 2.075
Int. Simple:PP (0.93m x 2.04m):1387041:1 | R+1 fini | OPENING | 0.2 | 1 | 2.075
Int. Simple:PP (0.93m x 2.04m):1387085:1 | R+1 fini | OPENING | 0.2 | 1 | 2.075
Int. Simple:PP (0.93m x 2.04m):1387166:1 | R+1 fini | OPENING | 0.2 | 1 | 2.075
Int. Simple:PP (0.93m x 2.04m):1387225:1 | R+1 fini | OPENING | 0.2 | 1 | 2.075
Int. Simple:PP (0.93m x 2.04m):1387313:1 | R+1 fini | OPENING | 0.2 | 1 | 2.075
Mur de base:Ext. Brique 20:1358042 | R+1 fini | OPENING
Int. Simple:PP (0.83m x 2.04m):1389451:1 | R+1 fini | OPENING | 0.1 | 0.9 | 2.075
Int. Simple:PP (0.83m x 2.04m):1388095:1 | R+1 fini | OPENING | 0.07 | 0.9 | 2.075
Int. Simple:PP (0.73m x 2.04m):1388147:1 | R+1 fini | OPENING | 0.07 | 0.8 | 2.075
Int. Simple:PP (0.73m x 2.04m):1388201:1 | R+1 fini | OPENING | 0.07 | 0.8 | 2.075
Int. Simple:PP (0.83m x 2.04m):1388611:1 | R+1 fini | OPENING | 0.07 | 0.9 | 2.075
Int. Simple:PP (0.73m x 2.04m):1388227:1 | R+1 fini | OPENING | 0.07 | 0.8 | 2.075
Int. Simple:PP (0.83m x 2.04m):1388665:1 | R+1 fini | OPENING | 0.07 | 0.9 | 2.075
Int. Simple:PP (0.73m x 2.04m):1388277:1 | R+1 fini | OPENING | 0.07 | 0.8 | 2.075
Int. Simple:PP (0.83m x 2.04m):1388700:1 | R+1 fini | OPENING | 0.07 | 0.9 | 2.075
Int. Simple:PP (0.73m x 2.04m):1388305:1 | R+1 fini | OPENING | 0.07 | 0.8 | 2.075
Int. Simple:PP (0.83m x 2.04m):1388738:1 | R+1 fini | OPENING | 0.07 | 0.9 | 2.075
Int. Simple:PP (0.73m x 2.04m):1388345:1 | R+1 fini | OPENING | 0.07 | 0.8 | 2.075
Int. Simple:PP (0.83m x 2.04m):1388779:1 | R+1 fini | OPENING | 0.07 | 0.9 | 2.075
Int. Simple:PP (0.73m x 2.04m):1388387:1 | R+1 fini | OPENING | 0.07 | 0.8 | 2.075
Int. Simple:PP (0.83m x 2.04m):1388830:1 | R+1 fini | OPENING | 0.07 | 0.9 | 2.075
Int. Simple:PP (0.73m x 2.04m):1388460:1 | R+1 fini | OPENING | 0.07 | 0.8 | 2.075
Int. Simple:PP (0.83m x 2.04m):1388908:1 | R+1 fini | OPENING | 0.07 | 0.9 | 2.075
Int. Simple:PP (0.73m x 2.04m):1388488:1 | R+1 fini | OPENING | 0.07 | 0.8 | 2.075
Int. Simple:PP (0.83m x 2.04m):1388956:1 | R+1 fini | OPENING | 0.07 | 0.9 | 2.075
Int. Simple:PP (0.73m x 2.04m):1388513:1 | R+1 fini | OPENING | 0.07 | 0.8 | 2.075
Int. Simple:PP (0.83m x 2.04m):1389014:1 | R+1 fini | OPENING | 0.07 | 0.9 | 2.075
Int. Simple:PP (0.73m x 2.04m):1388550:1 | R+1 fini | OPENING | 0.07 | 0.8 | 2.075
Int. Simple:PP (0.83m x 2.04m):1389066:1 | R+1 fini | OPENING | 0.07 | 0.9 | 2.075
Int. Simple:PP (0.83m x 2.04m):1389157:1 | R+1 fini | OPENING | 0.07 | 0.9 | 2.075
Int. Simple:PP (0.73m x 2.04m):1389227:1 | R+1 fini | OPENING | 0.07 | 0.8 | 2.075
Int. Simple:PP (0.73m x 2.04m):1389253:1 | R+1 fini | OPENING | 0.07 | 0.8 | 2.075
Int. Simple:PP (0.83m x 2.04m):1389353:1 | R+1 fini | OPENING | 0.07 | 0.9 | 2.075
Mur de base:Générique - Int. 70 mm:1373031 | R+1 fini | OPENING
Int. Simple:PP (0.83m x 2.04m):1390048:1 | R+1 fini | OPENING | 0.07 | 0.9 | 2.075
Int. Simple:PP (0.63m x 2.04m):1391136:1 | R+1 fini | OPENING | 0.07 | 0.8 | 2.075
Int. Simple:PP (0.83m x 2.04m):1390160:1 | R+1 fini | OPENING | 0.07 | 0.9 | 2.075
Int. Simple:PP (0.63m x 2.04m):1390996:1 | R+1 fini | OPENING | 0.07 | 0.8 | 2.075
Int. Simple:PP (0.83m x 2.04m):1390272:1 | R+1 fini | OPENING | 0.07 | 0.9 | 2.075
Int. Simple:PP (0.63m x 2.04m):1390825:1 | R+1 fini | OPENING | 0.07 | 0.8 | 2.075
Int. Simple:PP (0.83m x 2.04m):1390328:1 | R+1 fini | OPENING | 0.07 | 0.9 | 2.075
Int. Simple:PP (0.63m x 2.04m):1390707:1 | R+1 fini | OPENING | 0.07 | 0.8 | 2.075
Int. Simple:PP (0.83m x 2.04m):1390387:1 | R+1 fini | OPENING | 0.07 | 0.9 | 2.075
Int. Simple:PP (0.63m x 2.04m):1390611:1 | R+1 fini | OPENING | 0.07 | 0.8 | 2.075
Int. Simple:PP (0.83m x 2.04m):1390211:1 | R+1 fini | OPENING | 0.07 | 0.9 | 2.075
Int. Simple:PP (0.63m x 2.04m):1390901:1 | R+1 fini | OPENING | 0.07 | 0.8 | 2.075
Int. Simple:PP (0.83m x 2.04m):1390119:1 | R+1 fini | OPENING | 0.07 | 0.9 | 2.075
Int. Simple:PP (0.63m x 2.04m):1390956:1 | R+1 fini | OPENING | 0.07 | 0.8 | 2.075
Int. Simple:PP (0.83m x 2.04m):1389992:1 | R+1 fini | OPENING | 0.07 | 0.9 | 2.075
Int. Simple:PP (0.63m x 2.04m):1391185:1 | R+1 fini | OPENING | 0.07 | 0.8 | 2.075
Int. Simple:PP (0.83m x 2.04m):1390434:1 | R+1 fini | OPENING | 0.07 | 0.9 | 2.075
Int. Simple:PP (0.63m x 2.04m):1390544:1 | R+1 fini | OPENING | 0.07 | 0.8 | 2.075
Doorset_Fire Rated Double Door_ASSA ABLOY ES_ES04_Hardware 3D:1400 x 2100 mm (1550 x 2175 mm):1410005:1 | R+1 fini | OPENING | 0.1 | 1.57 | 2.185
Doorset_Fire Rated Double Door_ASSA ABLOY ES_ES04_Hardware 3D:1400 x 2100 mm (1550 x 2175 mm):1385889:1 | R+1 fini | OPENING | 0.2 | 1.57 | 2.185
Int. Simple:PP (0.93m x 2.04m):1389666:1 | R+1 fini | OPENING | 0.07 | 1 | 2.075
Int. Simple:PP (0.83m x 2.04m):1389708:1 | R+1 fini | OPENING | 0.07 | 0.9 | 2.075
Int. Simple:PP (0.83m x 2.04m):1389756:1 | R+1 fini | OPENING | 0.07 | 0.9 | 2.075
Int. Simple:PP (0.93m x 2.04m):1389581:1 | R+1 fini | OPENING | 0.07 | 1 | 2.075
Int. Simple:PP (0.83m x 2.04m):1389502:1 | R+1 fini | OPENING | 0.07 | 0.9 | 2.075
Doors - Industrial-Novoferm-Porte_de_garage_DL-3D:Doors - Industrial-Novoferm-Porte_de_garage_DL-3D:1701797:1 | RDC | OPENING | 0.2 | 2 | 2.4

# IfcRailing: Garde-corps:Remplissage Inférieur, Garde-corps:Remplissage Inférieur:1652658
In: R+1 fini
Material: Métal - Acier inoxydable, poli, Verre, <Unnamed>
Pset_EnvironmentalImpactIndicators - Reference: Remplissage Inférieur
Pset_RailingCommon - IsExternal: no; Reference: Remplissage Inférieur; Height: 0.9 m

# IfcRailing: Garde-corps:Type Bateau, Garde-corps:Type Bateau:1773920
In: RDC
Material: Peinture - Grise, Pin (1)
Pset_EnvironmentalImpactIndicators - Reference: Type Bateau
Pset_RailingCommon - IsExternal: no; Reference: Type Bateau; Height: 0.9 m

# IfcRoof: Sol:Couvertines acier (3)
In: RDC
Type - Material: Acier inoxydable, brossé
Type - Pset_RoofCommon - IsExternal: yes; ThermalTransmittance: 73.6364 kg/K/s3
Pset_EnvironmentalImpactIndicators - Reference: Couvertines acier
Pset_RoofCommon - LoadBearing: no; Reference: Couvertines acier
Name (Sol:Couvertines acier:...)
1658769
1660796
1660862

# IfcRoof: Sol:Couvertines acier 2 (6)
Type - Material: Acier inoxydable, brossé
Type - Pset_RoofCommon - IsExternal: yes; ThermalTransmittance: 162 kg/K/s3
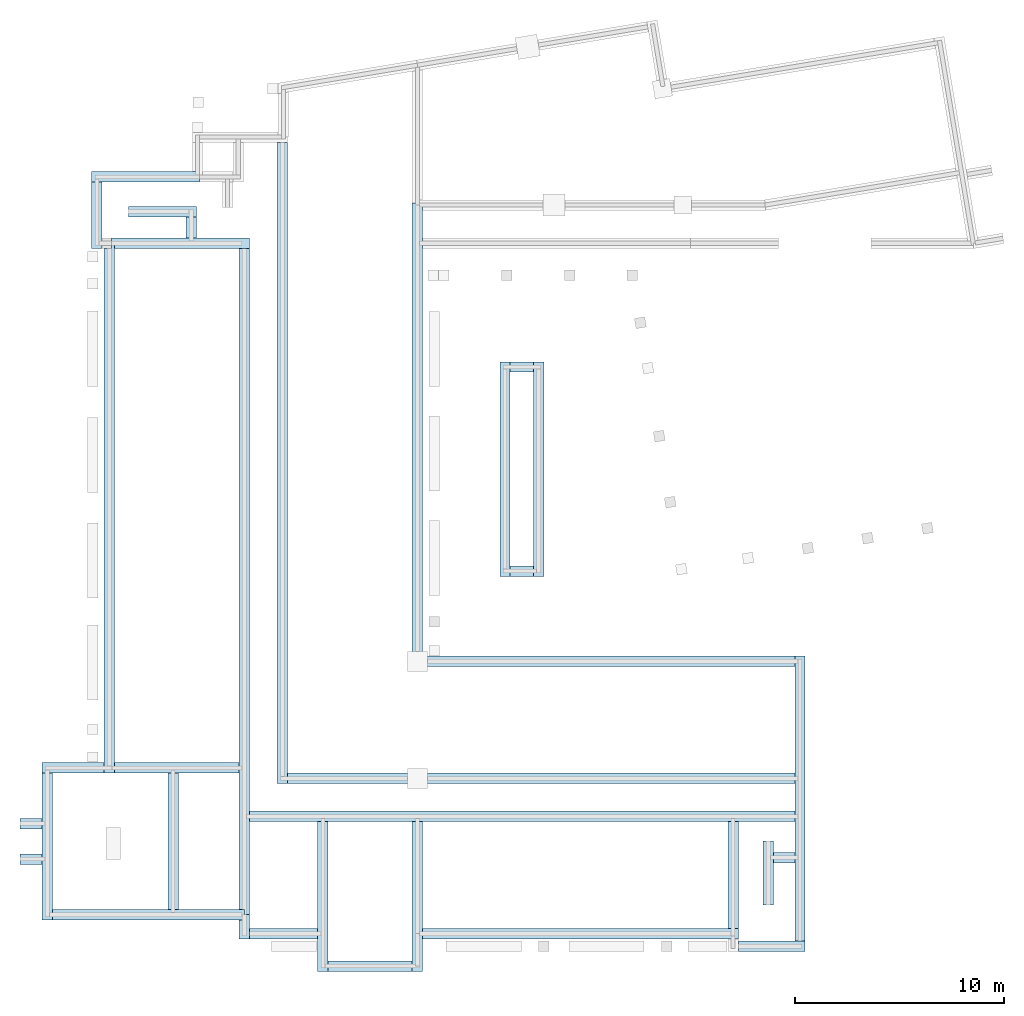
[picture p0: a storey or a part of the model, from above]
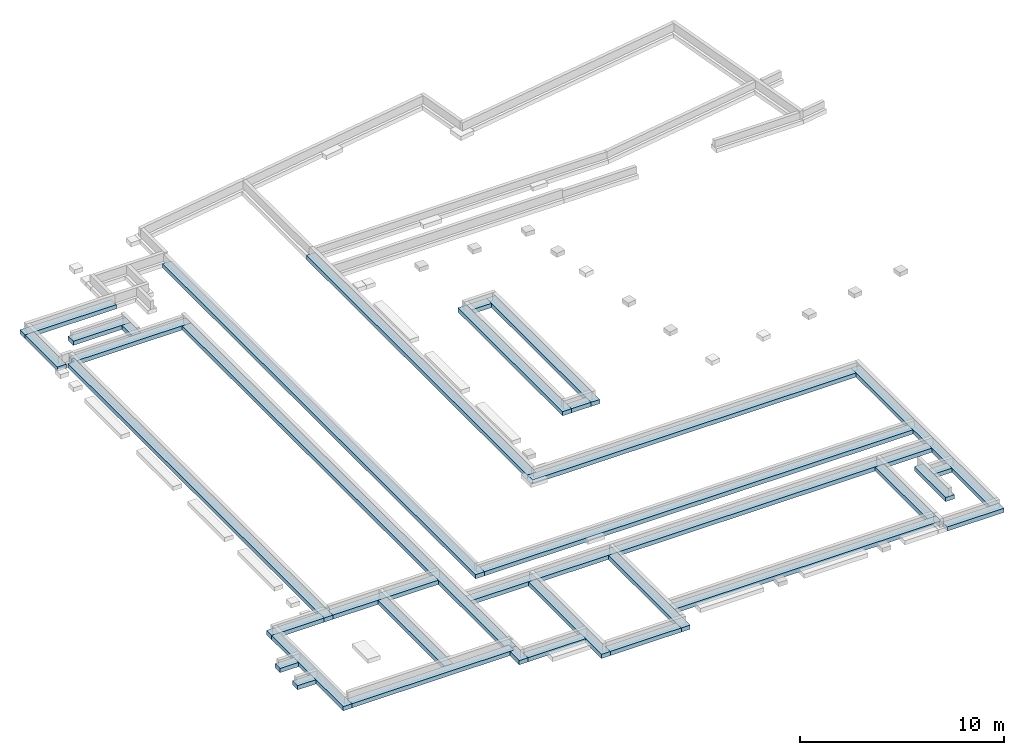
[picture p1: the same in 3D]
Properties of the parts of a building model (IFC4), part 4 of 5

# IfcRoof: Sol:Couvertines acier 2 (6)
Pset_EnvironmentalImpactIndicators - Reference: Couvertines acier 2
Pset_RoofCommon - LoadBearing: no; Reference: Couvertines acier 2
Name (Sol:Couvertines acier 2:...) | In | GrossArea (m2)
1664703 | Aras plafond 3 R+1 | 6.824
1669159 | Aras plafond 3 R+1 | 10.8642
1670787 | Aras plafond 3 R+1 | 4.544
1672299 | Aras sup plancher haut RDC | 29.3428
1675992 | RDC | 2.3684
1676857 | RDC | 6.0264

# IfcRoof: Sol:Préau acier (5)
In: RDC
Type - Material: Acier inoxydable, brossé
Type - Pset_RoofCommon - IsExternal: no; ThermalTransmittance: 202.5 kg/K/s3
Pset_EnvironmentalImpactIndicators - Reference: Préau acier
Pset_RoofCommon - LoadBearing: no; Reference: Préau acier
Name (Sol:Préau acier:...) | GrossArea (m2)
1644276 | 89.6893
1651403 | 8.11715
1714625 | 4.456
1716319 | 7.25549
1716469

# IfcRoof: Toit de base:CTA (2)
In: Aras sup mur R+1
Pset_EnvironmentalImpactIndicators - Reference: CTA
Pset_RoofCommon - IsExternal: yes; Reference: CTA
Qto_RoofBaseQuantities - ProjectedArea: 73.922 m2
Name (Toit de base:CTA:...)
1770260
1770634

# IfcSlab: Lg 02 20*1:Lg 02 20*60, Lg 02 20*1:Lg 02 20*60:304470
In: Arase inf longrines
Type - PredefinedType: BASESLAB
Type - Pset_SlabCommon - IsExternal: no
Pset_EnvironmentalImpactIndicators - Reference: Lg 02 20*60; sets with these values: 2
Pset_SlabCommon - Reference: Lg 02 20*60
Qto_SlabBaseQuantities - Width: 0.49 m; Length: 0.49 m; Depth: 0.49 m; Perimeter: 6.4 m; GrossArea: 0.6 m2; GrossVolume: 0.294 m3; NetVolume: 0.294 m3

# IfcSlab: Lg 02 20*2:Lg 02 20*60, Lg 02 20*2:Lg 02 20*60:304490
In: Arase inf longrines
Type - PredefinedType: BASESLAB
Type - Pset_SlabCommon - IsExternal: no
Pset_EnvironmentalImpactIndicators - Reference: Lg 02 20*60; sets with these values: 2
Pset_SlabCommon - Reference: Lg 02 20*60
Qto_SlabBaseQuantities - Width: 0.49 m; Length: 0.49 m; Depth: 0.49 m; Perimeter: 6.4 m; GrossArea: 0.6 m2; GrossVolume: 0.294 m3; NetVolume: 0.294 m3

# IfcSlab: Lg 02 20*3:Lg 02 20*60, Lg 02 20*3:Lg 02 20*60:304508
In: Arase inf longrines
Type - PredefinedType: BASESLAB
Type - Pset_SlabCommon - IsExternal: no
Pset_EnvironmentalImpactIndicators - Reference: Lg 02 20*60; sets with these values: 2
Pset_SlabCommon - Reference: Lg 02 20*60
Qto_SlabBaseQuantities - Width: 0.49 m; Length: 0.49 m; Depth: 0.49 m; Perimeter: 6.4 m; GrossArea: 0.6 m2; GrossVolume: 0.294 m3; NetVolume: 0.294 m3

# IfcSlab: Lg 02 20*60:Lg 02 20*60, Lg 02 20*60:Lg 02 20*60:304311
In: Arase inf longrines
Type - PredefinedType: BASESLAB
Type - Pset_SlabCommon - IsExternal: no
Pset_EnvironmentalImpactIndicators - Reference: Lg 02 20*60; sets with these values: 2
Pset_SlabCommon - Reference: Lg 02 20*60
Qto_SlabBaseQuantities - Width: 0.49 m; Length: 0.49 m; Depth: 0.49 m; Perimeter: 6.4 m; GrossArea: 0.6 m2; GrossVolume: 0.294 m3; NetVolume: 0.294 m3

# IfcSlab: Lg 03 20*1:Lg 03 20*70, Lg 03 20*1:Lg 03 20*70:305316
In: Arase inf longrines
Type - PredefinedType: BASESLAB
Type - Pset_SlabCommon - IsExternal: no
Pset_EnvironmentalImpactIndicators - Reference: Lg 03 20*70; sets with these values: 2
Pset_SlabCommon - Reference: Lg 03 20*70
Qto_SlabBaseQuantities - Width: 0.63 m; Length: 0.63 m; Depth: 0.63 m; Perimeter: 9.82 m; GrossArea: 0.942 m2; GrossVolume: 0.59346 m3; NetVolume: 0.59346 m3

# IfcSlab: Lg 03 20*2:Lg 03 20*70, Lg 03 20*2:Lg 03 20*70:305338
In: Arase inf longrines
Type - PredefinedType: BASESLAB
Type - Pset_SlabCommon - IsExternal: no
Pset_EnvironmentalImpactIndicators - Reference: Lg 03 20*70; sets with these values: 2
Pset_SlabCommon - Reference: Lg 03 20*70
Qto_SlabBaseQuantities - Width: 0.63 m; Length: 0.63 m; Depth: 0.63 m; Perimeter: 9.33961 m; GrossArea: 0.893961 m2; GrossVolume: 0.563195 m3; NetVolume: 0.563195 m3

# IfcSlab: Lg 03 20*3:Lg 03 20*70, Lg 03 20*3:Lg 03 20*70:305459
In: Arase inf longrines
Type - PredefinedType: BASESLAB
Type - Pset_SlabCommon - IsExternal: no
Pset_EnvironmentalImpactIndicators - Reference: Lg 03 20*70; sets with these values: 2
Pset_SlabCommon - Reference: Lg 03 20*70
Qto_SlabBaseQuantities - Width: 0.63 m; Length: 0.63 m; Depth: 0.63 m; Perimeter: 25.2583 m; GrossArea: 2.48583 m2; GrossVolume: 1.56607 m3; NetVolume: 1.56607 m3

# IfcSlab: Lg 03 20*4:Lg 03 20*70, Lg 03 20*4:Lg 03 20*70:305636
In: Arase inf longrines
Type - PredefinedType: BASESLAB
Type - Pset_SlabCommon - IsExternal: no
Pset_EnvironmentalImpactIndicators - Reference: Lg 03 20*70; sets with these values: 2
Pset_SlabCommon - Reference: Lg 03 20*70
Qto_SlabBaseQuantities - Width: 0.63 m; Length: 0.63 m; Depth: 0.63 m; Perimeter: 20.7537 m; GrossArea: 2.03537 m2; GrossVolume: 1.28228 m3; NetVolume: 1.28228 m3

# IfcSlab: Lg 03 20*70:Lg 03 20*70, Lg 03 20*70:Lg 03 20*70:305188
In: Arase inf longrines
Type - PredefinedType: BASESLAB
Type - Pset_SlabCommon - IsExternal: no
Pset_EnvironmentalImpactIndicators - Reference: Lg 03 20*70; sets with these values: 2
Pset_SlabCommon - Reference: Lg 03 20*70
Qto_SlabBaseQuantities - Width: 0.63 m; Length: 0.63 m; Depth: 0.63 m; Perimeter: 9.18604 m; GrossArea: 0.878604 m2; GrossVolume: 0.553521 m3; NetVolume: 0.553521 m3

# IfcSlab: Lg 04 20*1:Lg 04 20*60, Lg 04 20*1:Lg 04 20*60:306147
In: Arase inf longrines
Type - PredefinedType: BASESLAB
Type - Pset_SlabCommon - IsExternal: no
Pset_EnvironmentalImpactIndicators - Reference: Lg 04 20*60; sets with these values: 2
Pset_SlabCommon - Reference: Lg 04 20*60
Qto_SlabBaseQuantities - Width: 0.6 m; Length: 0.6 m; Depth: 0.6 m; Perimeter: 22.1988 m; GrossArea: 2.17988 m2; GrossVolume: 1.30793 m3; NetVolume: 1.30793 m3

# IfcSlab: Lg 04 20*2:Lg 04 20*60, Lg 04 20*2:Lg 04 20*60:306239
In: Arase inf longrines
Type - PredefinedType: BASESLAB
Type - Pset_SlabCommon - IsExternal: no
Pset_EnvironmentalImpactIndicators - Reference: Lg 04 20*60; sets with these values: 2
Pset_SlabCommon - Reference: Lg 04 20*60
Qto_SlabBaseQuantities - Width: 0.6 m; Length: 0.6 m; Depth: 0.6 m; Perimeter: 9.96321 m; GrossArea: 0.956321 m2; GrossVolume: 0.573793 m3; NetVolume: 0.573793 m3

# IfcSlab: Lg 04 20*60:Lg 04 20*60, Lg 04 20*60:Lg 04 20*60:306053
In: Arase inf longrines
Type - PredefinedType: BASESLAB
Type - Pset_SlabCommon - IsExternal: no
Pset_EnvironmentalImpactIndicators - Reference: Lg 04 20*60; sets with these values: 2
Pset_SlabCommon - Reference: Lg 04 20*60
Qto_SlabBaseQuantities - Width: 0.6 m; Length: 0.6 m; Depth: 0.6 m; Perimeter: 23.775 m; GrossArea: 2.3375 m2; GrossVolume: 1.4025 m3; NetVolume: 1.4025 m3

# IfcSlab: Lg01 20*10:Lg01 20*30, Lg01 20*10:Lg01 20*30:304832
In: Arase inf longrines
Type - PredefinedType: BASESLAB
Type - Pset_SlabCommon - IsExternal: no
Pset_EnvironmentalImpactIndicators - Reference: Lg01 20*30; sets with these values: 2
Pset_SlabCommon - Reference: Lg01 20*30
Qto_SlabBaseQuantities - Width: 0.48 m; Length: 0.48 m; Depth: 0.48 m; Perimeter: 6.46673 m; GrossArea: 0.606673 m2; GrossVolume: 0.291203 m3; NetVolume: 0.291203 m3

# IfcSlab: Lg01 20*11:Lg01 20*30, Lg01 20*11:Lg01 20*30:305011
In: Arase inf longrines
Type - PredefinedType: BASESLAB
Type - Pset_SlabCommon - IsExternal: no
Pset_EnvironmentalImpactIndicators - Reference: Lg01 20*30; sets with these values: 2
Pset_SlabCommon - Reference: Lg01 20*30
Qto_SlabBaseQuantities - Width: 0.3 m; Length: 0.3 m; Depth: 0.3 m; Perimeter: 6.26341 m; GrossArea: 0.586341 m2; GrossVolume: 0.175902 m3; NetVolume: 0.175902 m3

# IfcSlab: Lg01 20*1:Lg01 20*30, Lg01 20*1:Lg01 20*30:303951
In: Arase inf longrines
Type - PredefinedType: BASESLAB
Type - Pset_SlabCommon - IsExternal: no
Pset_EnvironmentalImpactIndicators - Reference: Lg01 20*30; sets with these values: 2
Pset_SlabCommon - Reference: Lg01 20*30
Qto_SlabBaseQuantities - Width: 0.48 m; Length: 0.48 m; Depth: 0.48 m; Perimeter: 6.9 m; GrossArea: 0.65 m2; GrossVolume: 0.312 m3; NetVolume: 0.312 m3

# IfcSlab: Lg01 20*2:Lg01 20*30, Lg01 20*2:Lg01 20*30:304030
In: Arase inf longrines
Type - PredefinedType: BASESLAB
Type - Pset_SlabCommon - IsExternal: no
Pset_EnvironmentalImpactIndicators - Reference: Lg01 20*30; sets with these values: 2
Pset_SlabCommon - Reference: Lg01 20*30
Qto_SlabBaseQuantities - Width: 0.48 m; Length: 0.48 m; Depth: 0.48 m; Perimeter: 6.9 m; GrossArea: 0.65 m2; GrossVolume: 0.312 m3; NetVolume: 0.312 m3

# IfcSlab: Lg01 20*30:Lg01 20*30, Lg01 20*30:Lg01 20*30:303809
In: Arase inf longrines
Type - PredefinedType: BASESLAB
Type - Pset_SlabCommon - IsExternal: no
Pset_EnvironmentalImpactIndicators - Reference: Lg01 20*30; sets with these values: 2
Pset_SlabCommon - Reference: Lg01 20*30
Qto_SlabBaseQuantities - Width: 0.48 m; Length: 0.48 m; Depth: 0.48 m; Perimeter: 6.71214 m; GrossArea: 0.631214 m2; GrossVolume: 0.302983 m3; NetVolume: 0.302983 m3

# IfcSlab: Lg01 20*3:Lg01 20*30, Lg01 20*3:Lg01 20*30:304100
In: Arase inf longrines
Type - PredefinedType: BASESLAB
Type - Pset_SlabCommon - IsExternal: no
Pset_EnvironmentalImpactIndicators - Reference: Lg01 20*30; sets with these values: 2
Pset_SlabCommon - Reference: Lg01 20*30
Qto_SlabBaseQuantities - Width: 0.48 m; Length: 0.48 m; Depth: 0.48 m; Perimeter: 4.86734 m; GrossArea: 0.446734 m2; GrossVolume: 0.214432 m3; NetVolume: 0.214432 m3

# IfcSlab: Lg01 20*4:Lg01 20*30, Lg01 20*4:Lg01 20*30:304213
In: Arase inf longrines
Type - PredefinedType: BASESLAB
Type - Pset_SlabCommon - IsExternal: no
Pset_EnvironmentalImpactIndicators - Reference: Lg01 20*30; sets with these values: 2
Pset_SlabCommon - Reference: Lg01 20*30
Qto_SlabBaseQuantities - Width: 0.48 m; Length: 0.48 m; Depth: 0.48 m; Perimeter: 4.96 m; GrossArea: 0.456 m2; GrossVolume: 0.21888 m3; NetVolume: 0.21888 m3

# IfcSlab: Lg01 20*5:Lg01 20*30, Lg01 20*5:Lg01 20*30:304400
In: Arase inf longrines
Type - PredefinedType: BASESLAB
Type - Pset_SlabCommon - IsExternal: no
Pset_EnvironmentalImpactIndicators - Reference: Lg01 20*30; sets with these values: 2
Pset_SlabCommon - Reference: Lg01 20*30
Qto_SlabBaseQuantities - Width: 0.3 m; Length: 0.3 m; Depth: 0.3 m; Perimeter: 3.34321 m; GrossArea: 0.294321 m2; GrossVolume: 0.0882963 m3; NetVolume: 0.0882963 m3

# IfcSlab: Lg01 20*6:Lg01 20*30, Lg01 20*6:Lg01 20*30:304565
In: Arase inf longrines
Type - PredefinedType: BASESLAB
Type - Pset_SlabCommon - IsExternal: no
Pset_EnvironmentalImpactIndicators - Reference: Lg01 20*30; sets with these values: 2
Pset_SlabCommon - Reference: Lg01 20*30
Qto_SlabBaseQuantities - Width: 0.48 m; Length: 0.48 m; Depth: 0.48 m; Perimeter: 7.07869 m; GrossArea: 0.667869 m2; GrossVolume: 0.320577 m3; NetVolume: 0.320577 m3

# IfcSlab: Lg01 20*7:Lg01 20*30, Lg01 20*7:Lg01 20*30:304744
In: Arase inf longrines
Type - PredefinedType: BASESLAB
Type - Pset_SlabCommon - IsExternal: no
Pset_EnvironmentalImpactIndicators - Reference: Lg01 20*30; sets with these values: 2
Pset_SlabCommon - Reference: Lg01 20*30
Qto_SlabBaseQuantities - Width: 0.48 m; Length: 0.48 m; Depth: 0.48 m; Perimeter: 7.07869 m; GrossArea: 0.667869 m2; GrossVolume: 0.320577 m3; NetVolume: 0.320577 m3

# IfcSlab: Lg01 20*8:Lg01 20*30, Lg01 20*8:Lg01 20*30:304766
In: Arase inf longrines
Type - PredefinedType: BASESLAB
Type - Pset_SlabCommon - IsExternal: no
Pset_EnvironmentalImpactIndicators - Reference: Lg01 20*30; sets with these values: 2
Pset_SlabCommon - Reference: Lg01 20*30
Qto_SlabBaseQuantities - Width: 0.48 m; Length: 0.48 m; Depth: 0.48 m; Perimeter: 7.07869 m; GrossArea: 0.667869 m2; GrossVolume: 0.320577 m3; NetVolume: 0.320577 m3

# IfcSlab: Lg01 20*9:Lg01 20*30, Lg01 20*9:Lg01 20*30:304790
In: Arase inf longrines
Type - PredefinedType: BASESLAB
Type - Pset_SlabCommon - IsExternal: no
Pset_EnvironmentalImpactIndicators - Reference: Lg01 20*30; sets with these values: 2
Pset_SlabCommon - Reference: Lg01 20*30
Qto_SlabBaseQuantities - Width: 0.48 m; Length: 0.48 m; Depth: 0.48 m; Perimeter: 7.07869 m; GrossArea: 0.667869 m2; GrossVolume: 0.320577 m3; NetVolume: 0.320577 m3

# IfcSlab: Palier monobloc:Epaisseur 150 mm (2)
In: RDC
Type - PredefinedType: LANDING
Type - Pset_SlabCommon - IsExternal: no
Material: Maçonnerie - Béton
Pset_EnvironmentalImpactIndicators - Reference: Epaisseur 150 mm; sets with these values: 2
Pset_SlabCommon - PitchAngle: 0 deg; Reference: Epaisseur 150 mm
Name (Escalier coulé sur place:Escalier:...) | NetVolume (m3)
1565086 Landing 1 | 0.649701
1567286 Landing 1 | 0.680524

# IfcSlab: SF 01:SF 01, SF 01:SF 01:289747
In: Arase inf soubassement
Type - PredefinedType: BASESLAB
Type - Pset_SlabCommon - IsExternal: no
Pset_EnvironmentalImpactIndicators - Reference: SF 01; sets with these values: 2
Pset_SlabCommon - Reference: SF 01
Qto_SlabBaseQuantities - Width: 0.25 m; Length: 0.25 m; Depth: 0.25 m; Perimeter: 8.2 m; GrossArea: 1.8 m2; GrossVolume: 0.45 m3; NetVolume: 0.45 m3

# IfcSlab: SF 1:SF 01, SF 1:SF 01:290068
In: Arase inf soubassement
Type - PredefinedType: BASESLAB
Type - Pset_SlabCommon - IsExternal: no
Pset_EnvironmentalImpactIndicators - Reference: SF 01; sets with these values: 2
Pset_SlabCommon - Reference: SF 01
Qto_SlabBaseQuantities - Width: 0.25 m; Length: 0.25 m; Depth: 0.25 m; Perimeter: 8.2 m; GrossArea: 1.8 m2; GrossVolume: 0.45 m3; NetVolume: 0.45 m3

# IfcSlab: SF 2:SF 01, SF 2:SF 01:290088
In: Arase inf soubassement
Type - PredefinedType: BASESLAB
Type - Pset_SlabCommon - IsExternal: no
Pset_EnvironmentalImpactIndicators - Reference: SF 01; sets with these values: 2
Pset_SlabCommon - Reference: SF 01
Qto_SlabBaseQuantities - Width: 0.25 m; Length: 0.25 m; Depth: 0.25 m; Perimeter: 8.2 m; GrossArea: 1.8 m2; GrossVolume: 0.45 m3; NetVolume: 0.45 m3

# IfcSlab: SF 3:SF 01, SF 3:SF 01:290106
In: Arase inf soubassement
Type - PredefinedType: BASESLAB
Type - Pset_SlabCommon - IsExternal: no
Pset_EnvironmentalImpactIndicators - Reference: SF 01; sets with these values: 2
Pset_SlabCommon - Reference: SF 01
Qto_SlabBaseQuantities - Width: 0.25 m; Length: 0.25 m; Depth: 0.25 m; Perimeter: 8.2 m; GrossArea: 1.8 m2; GrossVolume: 0.45 m3; NetVolume: 0.45 m3

# IfcSlab: SF 4:SF 01, SF 4:SF 01:290126
In: Arase inf soubassement
Type - PredefinedType: BASESLAB
Type - Pset_SlabCommon - IsExternal: no
Pset_EnvironmentalImpactIndicators - Reference: SF 01; sets with these values: 2
Pset_SlabCommon - Reference: SF 01
Qto_SlabBaseQuantities - Width: 0.25 m; Length: 0.25 m; Depth: 0.25 m; Perimeter: 8.2 m; GrossArea: 1.8 m2; GrossVolume: 0.45 m3; NetVolume: 0.45 m3

# IfcSlab: SF 5:SF 01, SF 5:SF 01:290144
In: Arase inf soubassement
Type - PredefinedType: BASESLAB
Type - Pset_SlabCommon - IsExternal: no
Pset_EnvironmentalImpactIndicators - Reference: SF 01; sets with these values: 2
Pset_SlabCommon - Reference: SF 01
Qto_SlabBaseQuantities - Width: 0.25 m; Length: 0.25 m; Depth: 0.25 m; Perimeter: 8.2 m; GrossArea: 1.8 m2; GrossVolume: 0.45 m3; NetVolume: 0.45 m3

# IfcSlab: SF 6:SF 01, SF 6:SF 01:290166
In: Arase inf soubassement
Type - PredefinedType: BASESLAB
Type - Pset_SlabCommon - IsExternal: no
Pset_EnvironmentalImpactIndicators - Reference: SF 01; sets with these values: 2
Pset_SlabCommon - Reference: SF 01
Qto_SlabBaseQuantities - Width: 0.25 m; Length: 0.25 m; Depth: 0.25 m; Perimeter: 8.2 m; GrossArea: 1.8 m2; GrossVolume: 0.45 m3; NetVolume: 0.45 m3

# IfcSlab: SF 7:SF 01, SF 7:SF 01:290568
In: Arase inf soubassement
Type - PredefinedType: BASESLAB
Type - Pset_SlabCommon - IsExternal: no
Pset_EnvironmentalImpactIndicators - Reference: SF 01; sets with these values: 2
Pset_SlabCommon - Reference: SF 01
Qto_SlabBaseQuantities - Width: 0.25 m; Length: 0.25 m; Depth: 0.25 m; Perimeter: 8.2 m; GrossArea: 1.8 m2; GrossVolume: 0.45 m3; NetVolume: 0.45 m3

# IfcSlab: SF 8:SF 01, SF 8:SF 01:290666
In: Arase inf soubassement
Type - PredefinedType: BASESLAB
Type - Pset_SlabCommon - IsExternal: no
Pset_EnvironmentalImpactIndicators - Reference: SF 01; sets with these values: 2
Pset_SlabCommon - Reference: SF 01
Qto_SlabBaseQuantities - Width: 0.25 m; Length: 0.25 m; Depth: 0.25 m; Perimeter: 8.2 m; GrossArea: 1.8 m2; GrossVolume: 0.45 m3; NetVolume: 0.45 m3

# IfcSlab: SF01:SF01, SF01:SF01:291165
In: Arase inf soubassement
Type - PredefinedType: BASESLAB
Type - Pset_SlabCommon - IsExternal: no
Pset_EnvironmentalImpactIndicators - Reference: SF01; sets with these values: 2
Pset_SlabCommon - Reference: SF01
Qto_SlabBaseQuantities - Width: 0.25 m; Length: 0.25 m; Depth: 0.25 m; Perimeter: 4.76 m; GrossArea: 0.94 m2; GrossVolume: 0.235 m3; NetVolume: 0.235 m3

# IfcSlab: SF:SF, SF:SF:290996
In: Arase inf soubassement
Type - PredefinedType: BASESLAB
Type - Pset_SlabCommon - IsExternal: no
Pset_EnvironmentalImpactIndicators - Reference: SF; sets with these values: 2
Pset_SlabCommon - Reference: SF
Qto_SlabBaseQuantities - Width: 0.25 m; Length: 0.25 m; Depth: 0.25 m; Perimeter: 5.3 m; GrossArea: 1.075 m2; GrossVolume: 0.26875 m3; NetVolume: 0.26875 m3

# IfcSlab: SI 01:SI 01, SI 01:SI 01:285066
In: Arase inf soubassement
Type - PredefinedType: BASESLAB
Type - Pset_SlabCommon - IsExternal: no
Pset_EnvironmentalImpactIndicators - Reference: SI 01; sets with these values: 2
Pset_SlabCommon - Reference: SI 01
Qto_SlabBaseQuantities - Width: 0.25 m; Length: 0.25 m; Depth: 0.25 m; Perimeter: 3.4 m; GrossArea: 0.7225 m2; GrossVolume: 0.180625 m3; NetVolume: 0.180625 m3

# IfcSlab: SI 02:SI 02, SI 02:SI 02:285431
In: Arase inf soubassement
Type - PredefinedType: BASESLAB
Type - Pset_SlabCommon - IsExternal: no
Pset_EnvironmentalImpactIndicators - Reference: SI 02; sets with these values: 2
Pset_SlabCommon - Reference: SI 02
Qto_SlabBaseQuantities - Width: 0.25 m; Length: 0.25 m; Depth: 0.25 m; Perimeter: 3.8 m; GrossArea: 0.9025 m2; GrossVolume: 0.225625 m3; NetVolume: 0.225625 m3

# IfcSlab: SI 03:SI 03, SI 03:SI 03:285782
In: Arase inf soubassement
Type - PredefinedType: BASESLAB
Type - Pset_SlabCommon - IsExternal: no
Pset_EnvironmentalImpactIndicators - Reference: SI 03; sets with these values: 2
Pset_SlabCommon - Reference: SI 03
Qto_SlabBaseQuantities - Width: 0.25 m; Length: 0.25 m; Depth: 0.25 m; Perimeter: 4.2 m; GrossArea: 1.1025 m2; GrossVolume: 0.275625 m3; NetVolume: 0.275625 m3

# IfcSlab: SI 04:SI 04, SI 04:SI 04:286489
In: Arase inf soubassement
Type - PredefinedType: BASESLAB
Type - Pset_SlabCommon - IsExternal: no
Pset_EnvironmentalImpactIndicators - Reference: SI 04; sets with these values: 2
Pset_SlabCommon - Reference: SI 04
Qto_SlabBaseQuantities - Width: 0.25 m; Length: 0.25 m; Depth: 0.25 m; Perimeter: 4.5 m; GrossArea: 1.085 m2; GrossVolume: 0.27125 m3; NetVolume: 0.27125 m3

# IfcSlab: SI 10:SI 05, SI 10:SI 05:288213
In: Arase inf soubassement
Type - PredefinedType: BASESLAB
Type - Pset_SlabCommon - IsExternal: no
Pset_EnvironmentalImpactIndicators - Reference: SI 05; sets with these values: 2
Pset_SlabCommon - Reference: SI 05
Qto_SlabBaseQuantities - Width: 0.25 m; Length: 0.25 m; Depth: 0.25 m; Perimeter: 1.99705 m; GrossArea: 0.249261 m2; GrossVolume: 0.0623154 m3; NetVolume: 0.0623154 m3

# IfcSlab: SI 11:SI 05, SI 11:SI 05:288231
In: Arase inf soubassement
Type - PredefinedType: BASESLAB
Type - Pset_SlabCommon - IsExternal: no
Pset_EnvironmentalImpactIndicators - Reference: SI 05; sets with these values: 2
Pset_SlabCommon - Reference: SI 05
Qto_SlabBaseQuantities - Width: 0.25 m; Length: 0.25 m; Depth: 0.25 m; Perimeter: 2 m; GrossArea: 0.25 m2; GrossVolume: 0.0625 m3; NetVolume: 0.0625 m3

# IfcSlab: SI 12:SI 05, SI 12:SI 05:288251
In: Arase inf soubassement
Type - PredefinedType: BASESLAB
Type - Pset_SlabCommon - IsExternal: no
Pset_EnvironmentalImpactIndicators - Reference: SI 05; sets with these values: 2
Pset_SlabCommon - Reference: SI 05
Qto_SlabBaseQuantities - Width: 0.25 m; Length: 0.25 m; Depth: 0.25 m; Perimeter: 2 m; GrossArea: 0.25 m2; GrossVolume: 0.0625 m3; NetVolume: 0.0625 m3

# IfcSlab: SI 13:SI 05, SI 13:SI 05:288269
In: Arase inf soubassement
Type - PredefinedType: BASESLAB
Type - Pset_SlabCommon - IsExternal: no
Pset_EnvironmentalImpactIndicators - Reference: SI 05; sets with these values: 2
Pset_SlabCommon - Reference: SI 05
Qto_SlabBaseQuantities - Width: 0.25 m; Length: 0.25 m; Depth: 0.25 m; Perimeter: 2 m; GrossArea: 0.25 m2; GrossVolume: 0.0625 m3; NetVolume: 0.0625 m3

# IfcSlab: SI 14:SI 05, SI 14:SI 05:288289
In: Arase inf soubassement
Type - PredefinedType: BASESLAB
Type - Pset_SlabCommon - IsExternal: no
Pset_EnvironmentalImpactIndicators - Reference: SI 05; sets with these values: 2
Pset_SlabCommon - Reference: SI 05
Qto_SlabBaseQuantities - Width: 0.25 m; Length: 0.25 m; Depth: 0.25 m; Perimeter: 2 m; GrossArea: 0.25 m2; GrossVolume: 0.0625 m3; NetVolume: 0.0625 m3

# IfcSlab: SI 15:SI 05, SI 15:SI 05:288307
In: Arase inf soubassement
Type - PredefinedType: BASESLAB
Type - Pset_SlabCommon - IsExternal: no
Pset_EnvironmentalImpactIndicators - Reference: SI 05; sets with these values: 2
Pset_SlabCommon - Reference: SI 05
Qto_SlabBaseQuantities - Width: 0.25 m; Length: 0.25 m; Depth: 0.25 m; Perimeter: 2 m; GrossArea: 0.25 m2; GrossVolume: 0.0625 m3; NetVolume: 0.0625 m3

# IfcSlab: SI 16:SI 05, SI 16:SI 05:288327
In: Arase inf soubassement
Type - PredefinedType: BASESLAB
Type - Pset_SlabCommon - IsExternal: no
Pset_EnvironmentalImpactIndicators - Reference: SI 05; sets with these values: 2
Pset_SlabCommon - Reference: SI 05
Qto_SlabBaseQuantities - Width: 0.25 m; Length: 0.25 m; Depth: 0.25 m; Perimeter: 2 m; GrossArea: 0.25 m2; GrossVolume: 0.0625 m3; NetVolume: 0.0625 m3

# IfcSlab: SI 17:SI 05, SI 17:SI 05:288345
In: Arase inf soubassement
Type - PredefinedType: BASESLAB
Type - Pset_SlabCommon - IsExternal: no
Pset_EnvironmentalImpactIndicators - Reference: SI 05; sets with these values: 2
Pset_SlabCommon - Reference: SI 05
Qto_SlabBaseQuantities - Width: 0.25 m; Length: 0.25 m; Depth: 0.25 m; Perimeter: 2 m; GrossArea: 0.25 m2; GrossVolume: 0.0625 m3; NetVolume: 0.0625 m3

# IfcSlab: SI 18:SI 05, SI 18:SI 05:288797
In: Arase inf soubassement
Type - PredefinedType: BASESLAB
Type - Pset_SlabCommon - IsExternal: no
Pset_EnvironmentalImpactIndicators - Reference: SI 05; sets with these values: 2
Pset_SlabCommon - Reference: SI 05
Qto_SlabBaseQuantities - Width: 0.25 m; Length: 0.25 m; Depth: 0.25 m; Perimeter: 2 m; GrossArea: 0.25 m2; GrossVolume: 0.0625 m3; NetVolume: 0.0625 m3

# IfcSlab: SI 19:SI 05, SI 19:SI 05:288815
In: Arase inf soubassement
Type - PredefinedType: BASESLAB
Type - Pset_SlabCommon - IsExternal: no
Pset_EnvironmentalImpactIndicators - Reference: SI 05; sets with these values: 2
Pset_SlabCommon - Reference: SI 05
Qto_SlabBaseQuantities - Width: 0.25 m; Length: 0.25 m; Depth: 0.25 m; Perimeter: 2 m; GrossArea: 0.25 m2; GrossVolume: 0.0625 m3; NetVolume: 0.0625 m3

# IfcSlab: SI 1:SI 01, SI 1:SI 01:285173
In: Arase inf soubassement
Type - PredefinedType: BASESLAB
Type - Pset_SlabCommon - IsExternal: no
Pset_EnvironmentalImpactIndicators - Reference: SI 01; sets with these values: 2
Pset_SlabCommon - Reference: SI 01
Qto_SlabBaseQuantities - Width: 0.25 m; Length: 0.25 m; Depth: 0.25 m; Perimeter: 3.4 m; GrossArea: 0.7225 m2; GrossVolume: 0.180625 m3; NetVolume: 0.180625 m3

# IfcSlab: SI 20:SI 05, SI 20:SI 05:288833
In: Arase inf soubassement
Type - PredefinedType: BASESLAB
Type - Pset_SlabCommon - IsExternal: no
Pset_EnvironmentalImpactIndicators - Reference: SI 05; sets with these values: 2
Pset_SlabCommon - Reference: SI 05
Qto_SlabBaseQuantities - Width: 0.25 m; Length: 0.25 m; Depth: 0.25 m; Perimeter: 2 m; GrossArea: 0.25 m2; GrossVolume: 0.0625 m3; NetVolume: 0.0625 m3

# IfcSlab: SI 22:SI 05, SI 22:SI 05:289016
In: Arase inf soubassement
Type - PredefinedType: BASESLAB
Type - Pset_SlabCommon - IsExternal: no
Pset_EnvironmentalImpactIndicators - Reference: SI 05; sets with these values: 2
Pset_SlabCommon - Reference: SI 05
Qto_SlabBaseQuantities - Width: 0.25 m; Length: 0.25 m; Depth: 0.25 m; Perimeter: 2 m; GrossArea: 0.25 m2; GrossVolume: 0.0625 m3; NetVolume: 0.0625 m3

# IfcSlab: SI 23:SI 05, SI 23:SI 05:289148
In: Arase inf soubassement
Type - PredefinedType: BASESLAB
Type - Pset_SlabCommon - IsExternal: no
Pset_EnvironmentalImpactIndicators - Reference: SI 05; sets with these values: 2
Pset_SlabCommon - Reference: SI 05
Qto_SlabBaseQuantities - Width: 0.25 m; Length: 0.25 m; Depth: 0.25 m; Perimeter: 2 m; GrossArea: 0.25 m2; GrossVolume: 0.0625 m3; NetVolume: 0.0625 m3

# IfcSlab: SI 24:SI 05, SI 24:SI 05:289214
In: Arase inf soubassement
Type - PredefinedType: BASESLAB
Type - Pset_SlabCommon - IsExternal: no
Pset_EnvironmentalImpactIndicators - Reference: SI 05; sets with these values: 2
Pset_SlabCommon - Reference: SI 05
Qto_SlabBaseQuantities - Width: 0.25 m; Length: 0.25 m; Depth: 0.25 m; Perimeter: 2 m; GrossArea: 0.25 m2; GrossVolume: 0.0625 m3; NetVolume: 0.0625 m3

# IfcSlab: SI 25:SI 05, SI 25:SI 05:289236
In: Arase inf soubassement
Type - PredefinedType: BASESLAB
Type - Pset_SlabCommon - IsExternal: no
Pset_EnvironmentalImpactIndicators - Reference: SI 05; sets with these values: 2
Pset_SlabCommon - Reference: SI 05
Qto_SlabBaseQuantities - Width: 0.25 m; Length: 0.25 m; Depth: 0.25 m; Perimeter: 2 m; GrossArea: 0.25 m2; GrossVolume: 0.0625 m3; NetVolume: 0.0625 m3

# IfcSlab: SI 26:SI 05, SI 26:SI 05:289254
In: Arase inf soubassement
Type - PredefinedType: BASESLAB
Type - Pset_SlabCommon - IsExternal: no
Pset_EnvironmentalImpactIndicators - Reference: SI 05; sets with these values: 2
Pset_SlabCommon - Reference: SI 05
Qto_SlabBaseQuantities - Width: 0.25 m; Length: 0.25 m; Depth: 0.25 m; Perimeter: 2 m; GrossArea: 0.25 m2; GrossVolume: 0.0625 m3; NetVolume: 0.0625 m3

# IfcSlab: SI 27:SI 05, SI 27:SI 05:289272
In: Arase inf soubassement
Type - PredefinedType: BASESLAB
Type - Pset_SlabCommon - IsExternal: no
Pset_EnvironmentalImpactIndicators - Reference: SI 05; sets with these values: 2
Pset_SlabCommon - Reference: SI 05
Qto_SlabBaseQuantities - Width: 0.25 m; Length: 0.25 m; Depth: 0.25 m; Perimeter: 2 m; GrossArea: 0.25 m2; GrossVolume: 0.0625 m3; NetVolume: 0.0625 m3

# IfcSlab: SI 28:SI 05, SI 28:SI 05:289384
In: Arase inf soubassement
Type - PredefinedType: BASESLAB
Type - Pset_SlabCommon - IsExternal: no
Pset_EnvironmentalImpactIndicators - Reference: SI 05; sets with these values: 2
Pset_SlabCommon - Reference: SI 05
Qto_SlabBaseQuantities - Width: 0.25 m; Length: 0.25 m; Depth: 0.25 m; Perimeter: 2 m; GrossArea: 0.25 m2; GrossVolume: 0.0625 m3; NetVolume: 0.0625 m3

# IfcSlab: SI 29:SI 05, SI 29:SI 05:289404
In: Arase inf soubassement
Type - PredefinedType: BASESLAB
Type - Pset_SlabCommon - IsExternal: no
Pset_EnvironmentalImpactIndicators - Reference: SI 05; sets with these values: 2
Pset_SlabCommon - Reference: SI 05
Qto_SlabBaseQuantities - Width: 0.25 m; Length: 0.25 m; Depth: 0.25 m; Perimeter: 2 m; GrossArea: 0.25 m2; GrossVolume: 0.0625 m3; NetVolume: 0.0625 m3

# IfcSlab: SI 2:SI 02, SI 2:SI 02:285623
In: Arase inf soubassement
Type - PredefinedType: BASESLAB
Type - Pset_SlabCommon - IsExternal: no
Pset_EnvironmentalImpactIndicators - Reference: SI 02; sets with these values: 2
Pset_SlabCommon - Reference: SI 02
Qto_SlabBaseQuantities - Width: 0.25 m; Length: 0.25 m; Depth: 0.25 m; Perimeter: 3.8 m; GrossArea: 0.9025 m2; GrossVolume: 0.225625 m3; NetVolume: 0.225625 m3

# IfcSlab: SI 30:SI 05, SI 30:SI 05:289424
In: Arase inf soubassement
Type - PredefinedType: BASESLAB
Type - Pset_SlabCommon - IsExternal: no
Pset_EnvironmentalImpactIndicators - Reference: SI 05; sets with these values: 2
Pset_SlabCommon - Reference: SI 05
Qto_SlabBaseQuantities - Width: 0.25 m; Length: 0.25 m; Depth: 0.25 m; Perimeter: 2 m; GrossArea: 0.25 m2; GrossVolume: 0.0625 m3; NetVolume: 0.0625 m3

# IfcSlab: SI 31:SI 05, SI 31:SI 05:289444
In: Arase inf soubassement
Type - PredefinedType: BASESLAB
Type - Pset_SlabCommon - IsExternal: no
Pset_EnvironmentalImpactIndicators - Reference: SI 05; sets with these values: 2
Pset_SlabCommon - Reference: SI 05
Qto_SlabBaseQuantities - Width: 0.25 m; Length: 0.25 m; Depth: 0.25 m; Perimeter: 2 m; GrossArea: 0.25 m2; GrossVolume: 0.0625 m3; NetVolume: 0.0625 m3

# IfcSlab: SI 32:SI 05, SI 32:SI 05:289464
In: Arase inf soubassement
Type - PredefinedType: BASESLAB
Type - Pset_SlabCommon - IsExternal: no
Pset_EnvironmentalImpactIndicators - Reference: SI 05; sets with these values: 2
Pset_SlabCommon - Reference: SI 05
Qto_SlabBaseQuantities - Width: 0.25 m; Length: 0.25 m; Depth: 0.25 m; Perimeter: 2 m; GrossArea: 0.25 m2; GrossVolume: 0.0625 m3; NetVolume: 0.0625 m3

# IfcSlab: SI 3:SI 02, SI 3:SI 02:285641
In: Arase inf soubassement
Type - PredefinedType: BASESLAB
Type - Pset_SlabCommon - IsExternal: no
Pset_EnvironmentalImpactIndicators - Reference: SI 02; sets with these values: 2
Pset_SlabCommon - Reference: SI 02
Qto_SlabBaseQuantities - Width: 0.25 m; Length: 0.25 m; Depth: 0.25 m; Perimeter: 3.8 m; GrossArea: 0.9025 m2; GrossVolume: 0.225625 m3; NetVolume: 0.225625 m3

# IfcSlab: SI 4:SI 02, SI 4:SI 02:285663
In: Arase inf soubassement
Type - PredefinedType: BASESLAB
Type - Pset_SlabCommon - IsExternal: no
Pset_EnvironmentalImpactIndicators - Reference: SI 02; sets with these values: 2
Pset_SlabCommon - Reference: SI 02
Qto_SlabBaseQuantities - Width: 0.25 m; Length: 0.25 m; Depth: 0.25 m; Perimeter: 3.8 m; GrossArea: 0.9025 m2; GrossVolume: 0.225625 m3; NetVolume: 0.225625 m3

# IfcSlab: SI 5:SI 03, SI 5:SI 03:285881
In: Arase inf soubassement
Type - PredefinedType: BASESLAB
Type - Pset_SlabCommon - IsExternal: no
Pset_EnvironmentalImpactIndicators - Reference: SI 03; sets with these values: 2
Pset_SlabCommon - Reference: SI 03
Qto_SlabBaseQuantities - Width: 0.25 m; Length: 0.25 m; Depth: 0.25 m; Perimeter: 4.2 m; GrossArea: 1.1025 m2; GrossVolume: 0.275625 m3; NetVolume: 0.275625 m3

# IfcSlab: SI 6:SI 05, SI 6:SI 05:288074
In: Arase inf soubassement
Type - PredefinedType: BASESLAB
Type - Pset_SlabCommon - IsExternal: no
Pset_EnvironmentalImpactIndicators - Reference: SI 05; sets with these values: 2
Pset_SlabCommon - Reference: SI 05
Qto_SlabBaseQuantities - Width: 0.25 m; Length: 0.25 m; Depth: 0.25 m; Perimeter: 2 m; GrossArea: 0.25 m2; GrossVolume: 0.0625 m3; NetVolume: 0.0625 m3

# IfcSlab: SI 7:SI 05, SI 7:SI 05:288092
In: Arase inf soubassement
Type - PredefinedType: BASESLAB
Type - Pset_SlabCommon - IsExternal: no
Pset_EnvironmentalImpactIndicators - Reference: SI 05; sets with these values: 2
Pset_SlabCommon - Reference: SI 05
Qto_SlabBaseQuantities - Width: 0.25 m; Length: 0.25 m; Depth: 0.25 m; Perimeter: 2 m; GrossArea: 0.25 m2; GrossVolume: 0.0625 m3; NetVolume: 0.0625 m3

# IfcSlab: SI 8:SI 05, SI 8:SI 05:288110
In: Arase inf soubassement
Type - PredefinedType: BASESLAB
Type - Pset_SlabCommon - IsExternal: no
Pset_EnvironmentalImpactIndicators - Reference: SI 05; sets with these values: 2
Pset_SlabCommon - Reference: SI 05
Qto_SlabBaseQuantities - Width: 0.25 m; Length: 0.25 m; Depth: 0.25 m; Perimeter: 2 m; GrossArea: 0.25 m2; GrossVolume: 0.0625 m3; NetVolume: 0.0625 m3

# IfcSlab: SI 9:SI 05, SI 9:SI 05:288128
In: Arase inf soubassement
Type - PredefinedType: BASESLAB
Type - Pset_SlabCommon - IsExternal: no
Pset_EnvironmentalImpactIndicators - Reference: SI 05; sets with these values: 2
Pset_SlabCommon - Reference: SI 05
Qto_SlabBaseQuantities - Width: 0.25 m; Length: 0.25 m; Depth: 0.25 m; Perimeter: 2 m; GrossArea: 0.25 m2; GrossVolume: 0.0625 m3; NetVolume: 0.0625 m3

# IfcSlab: Sol:Dalle en béton - 250 mm (8)
In: RDC
Type - PredefinedType: FLOOR; Material: Maçonnerie - Béton
Type - Pset_SlabCommon - IsExternal: no
Pset_EnvironmentalImpactIndicators - Reference: Dalle en béton - 250 mm; sets with these values: 2
Pset_SlabCommon - Reference: Dalle en béton - 250 mm; PitchAngle: 0 deg; LoadBearing: no
Qto_SlabBaseQuantities - Width: 0.28 m; Length: 0.28 m; Depth: 0.28 m
Name (Sol:Dalle en béton - 250 mm:...) | Perimeter (m) | GrossArea (m2) | GrossVolume (m3) = NetVolume (m3)
310518 | 50.4532 | 156.561 | 43.837
313709 | 88.5265 | 339.167 | 94.9667
315388 | 72.9835 | 232.956 | 65.2276
316358 | 18.8759 | 19.0611 | 5.33711
317067 | 26.48 | 43.4644 | 12.17
317523 | 21.66 | 26.0642 | 7.29798
318080 | 148.97 | 463.114 | 129.672
320012 | 110.726 | 300.175 | 84.049

# IfcSlab: Sol:Etanchéité bitumé (2.5cm) (2)
Type - PredefinedType: FLOOR; Material: Asphalte, bitume
Type - Pset_SlabCommon - IsExternal: yes; ThermalTransmittance: 46 kg/K/s3
Pset_EnvironmentalImpactIndicators - Reference: Etanchéité bitumé (2.5cm); sets with these values: 2
Pset_SlabCommon - PitchAngle: 0 deg; LoadBearing: no; Reference: Etanchéité bitumé (2.5cm)
Qto_SlabBaseQuantities - Width: 0.025 m; Length: 0.025 m; Depth: 0.025 m
Name (Sol:Etanchéité bitumé (2.5cm):...) | In | Perimeter (m) | GrossArea (m2) | GrossVolume (m3) = NetVolume (m3)
1613169 | Aras sup plancher haut RDC | 106.124 | 388.883 | 9.72208
1616642 | Aras sup mur R+1 | 143.85 | 729.633 | 18.2408

# IfcSlab: Sol:Isolant toit plat (14 cm) (2)
Type - PredefinedType: FLOOR; Material: Maçonnerie - Isolant
Type - Pset_SlabCommon - IsExternal: yes
Pset_EnvironmentalImpactIndicators - Reference: Isolant toit plat (14 cm); sets with these values: 2
Pset_SlabCommon - PitchAngle: 0 deg; LoadBearing: no; Reference: Isolant toit plat (14 cm)
Qto_SlabBaseQuantities - Width: 0.14 m; Length: 0.14 m; Depth: 0.14 m
Name (Sol:Isolant toit plat (14 cm):...) | In | Perimeter (m) | GrossArea (m2) | GrossVolume (m3) = NetVolume (m3)
1609589 | Aras sup plancher haut RDC | 106.263 | 389.861 | 54.5805
1619376 | Aras sup mur R+1 | 143.85 | 729.633 | 102.149

# IfcSlab: Sol:Plancher béton 10cm, Sol:Plancher béton 10cm:1779210
In: RDC
Type - PredefinedType: FLOOR; Material: Maçonnerie - Béton
Type - Pset_SlabCommon - IsExternal: no
Pset_EnvironmentalImpactIndicators - Reference: Plancher béton 10cm; sets with these values: 2
Pset_SlabCommon - PitchAngle: 0 deg; LoadBearing: no; Reference: Plancher béton 10cm
Qto_SlabBaseQuantities - Width: 0.1 m; Length: 0.1 m; Depth: 0.1 m; Perimeter: 36.0932 m; GrossArea: 59.5621 m2; GrossVolume: 5.95621 m3; NetVolume: 5.95621 m3

# IfcSlab: Sol:Plancher béton 19 cm, Sol:Plancher béton 19 cm:1583300
In: RDC
Type - PredefinedType: FLOOR; Material: Maçonnerie - Béton
Type - Pset_SlabCommon - IsExternal: no
Pset_EnvironmentalImpactIndicators - Reference: Plancher béton 19 cm; sets with these values: 2
Pset_SlabCommon - PitchAngle: 0 deg; LoadBearing: no; Reference: Plancher béton 19 cm
Qto_SlabBaseQuantities - Width: 0.19 m; Length: 0.19 m; Depth: 0.19 m; Perimeter: 17.7889 m; GrossArea: 16.2222 m2; GrossVolume: 3.08222 m3; NetVolume: 3.08222 m3

# IfcSlab: Sol:Plancher béton 20cm (8)
Type - PredefinedType: FLOOR; Material: Maçonnerie - Béton
Type - Pset_SlabCommon - IsExternal: no
Pset_EnvironmentalImpactIndicators - Reference: Plancher béton 20cm; sets with these values: 2
Pset_SlabCommon - PitchAngle: 0 deg; Reference: Plancher béton 20cm
Qto_SlabBaseQuantities - Width: 0.2 m; Length: 0.2 m; Depth: 0.2 m
Name (Sol:Plancher béton 20cm:...) | In | LoadBearing | Perimeter (m) | GrossArea (m2) | GrossVolume (m3) = NetVolume (m3)
1346920 | RDC | yes | 72.2566 | 226.735 | 45.347
1569570 | R+1 fini | no | 9.96 | 5.96 | 1.192
1576678 | RDC | no | 72.2685 | 225.589 | 45.1179
1580209 | RDC | no | 33.8459 | 60.9752 | 12.195
1585653 | RDC | no | 134.81 | 650.151 | 130.03
1590752 | R+1 fini | no | 143.85 | 730.135 | 146.027
1598574 | R+1 fini | no | 32.1 | 62.9486 | 12.5897
1713550 | RDC | no | 9.49232 | 4.40623 | 0.881246

# IfcSlab: Sol:Plancher béton 29cm, Sol:Plancher béton 29cm:1346220
In: Aras inf plancher haut RDC (dalle 29cm)
Type - PredefinedType: FLOOR; Material: Maçonnerie - Béton
Type - Pset_SlabCommon - IsExternal: no
Pset_EnvironmentalImpactIndicators - Reference: Plancher béton 29cm; sets with these values: 2
Pset_SlabCommon - LoadBearing: yes; PitchAngle: 0 deg; Reference: Plancher béton 29cm
Qto_SlabBaseQuantities - Width: 0.29 m; Length: 0.29 m; Depth: 0.29 m; Perimeter: 49.1093 m; GrossArea: 148.683 m2; GrossVolume: 43.1181 m3; NetVolume: 43.1181 m3

# IfcSlab: Toit de base:CTA (4)
In: Aras sup mur R+1
Type - PredefinedType: ROOF
Type - Pset_SlabCommon - IsExternal: yes; ThermalTransmittance: 225 kg/K/s3
Material: Steel, S 460
Pset_EnvironmentalImpactIndicators - Reference: CTA; sets with these values: 2
Pset_SlabCommon - Reference: CTA; PitchAngle: 30 deg
Qto_SlabBaseQuantities - Length: 0.2 m; Depth: 0.2 m; Perimeter: 37.4516 m; GrossArea: 3.965 m2; GrossVolume: 0.793 m3; NetVolume: 17.0716 m3
Name (Toit de base:CTA:...)
2 x 1770260
2 x 1770634

# IfcStair: Escalier coulé sur place:Monobloc (2)
In: RDC
Type - PredefinedType: HALF_TURN_STAIR
Type - Pset_StairCommon - IsExternal: no; NosingLength: 0 m; NumberOfRiser: 0; NumberOfTreads: 0
Type - Pset_StairFlightCommon - NosingLength: 0 m; NumberOfRiser: 0; NumberOfTreads: 0
Pset_EnvironmentalImpactIndicators - Reference: Monobloc
Pset_StairCommon - Reference: Monobloc; RiserHeight: 0.163636 m; TreadLength: 0.29 m; TreadLengthAtOffset: 0.29 m; TreadLengthAtInnerSide: 0.29 m
Pset_StairFlightCommon - Reference: Monobloc; RiserHeight: 0.163636 m; TreadLength: 0.29 m; TreadLengthAtOffset: 0.29 m; TreadLengthAtInnerSide: 0.29 m
Name (Escalier coulé sur place:Escalier:...) | Pset_StairCommon, NumberOfRiser = Pset_StairFlightCommon, NumberOfRiser | Pset_StairCommon, NumberOfTreads = Pset_StairFlightCommon, NumberOfTreads | Pset_StairCommon, WalkingLineOffset (m) = Pset_StairFlightCommon, WalkingLineOffset (m)
1565086 | 23 | 21 | 2.42782
1567286 | 22 | 20 | 2.3294

# IfcStair: Escalier coulé sur place:Monobloc, Escalier coulé sur place:Escalier:1772541
In: RDC
Type - Pset_StairCommon - IsExternal: no; NosingLength: 0 m; NumberOfRiser: 0; NumberOfTreads: 0
Type - Pset_StairFlightCommon - NosingLength: 0 m; NumberOfRiser: 0; NumberOfTreads: 0
Pset_EnvironmentalImpactIndicators - Reference: Monobloc
Pset_StairCommon - Reference: Monobloc; NumberOfRiser: 15; NumberOfTreads: 14; RiserHeight: 0.189474 m; TreadLength: 0.251053 m; WalkingLineOffset: 1.44357 m; TreadLengthAtOffset: 0.251053 m; TreadLengthAtInnerSide: 0.251053 m
Pset_StairFlightCommon - Reference: Monobloc; NumberOfRiser: 15; NumberOfTreads: 14; RiserHeight: 0.189474 m; TreadLength: 0.251053 m; WalkingLineOffset: 1.44357 m; TreadLengthAtOffset: 0.251053 m; TreadLengthAtInnerSide: 0.251053 m

# IfcStairFlight: Volée monobloc:Profondeur de structure 80 mm (4)
In: RDC
Type - PredefinedType: STRAIGHT
Material: Maçonnerie - Béton
Pset_EnvironmentalImpactIndicators - Reference: Profondeur de structure 80 mm
Pset_StairFlightCommon - NosingLength: 0 m; Reference: Profondeur de structure 80 mm; RiserHeight: 0.163636 m; TreadLength: 0.29 m; TreadLengthAtOffset: 0.29 m; TreadLengthAtInnerSide: 0.29 m
Name (Escalier coulé sur place:Escalier:...) | NumberOfRiser | NumberOfTreads | WalkingLineOffset (m) | Length (m) | NetVolume (m3)
1565086 Run 1 | 12 | 11 | 2.42782 | 3.19 | 0.80889
1565086 Run 2 | 11 | 10 | 2.13255 | 2.9 | 0.654756
1567286 Run 1 | 12 | 11 | 2.3294 | 3.19 | 0.786714
1567286 Run 2 | 10 | 9 | 2.3294 | 2.61 | 0.633058

# IfcStairFlight: Volée monobloc:Profondeur de structure 80 mm, Escalier coulé sur place:Escalier:1772541 Run 1
In: RDC
Type - PredefinedType: WINDER
Material: Maçonnerie - Béton
Pset_EnvironmentalImpactIndicators - Reference: Profondeur de structure 80 mm
Pset_StairFlightCommon - NosingLength: 0 m; Reference: Profondeur de structure 80 mm; NumberOfRiser: 15; NumberOfTreads: 14; RiserHeight: 0.189474 m; TreadLength: 0.251053 m; WalkingLineOffset: 1.44357 m; TreadLengthAtOffset: 0.251053 m; TreadLengthAtInnerSide: 0.251053 m
Qto_StairFlightBaseQuantities - Length: 3.52283 m; NetVolume: 0.634043 m3

# IfcWall: Mur de base:Brise vue ext (52)
Type - PredefinedType: STANDARD
Type - Pset_WallCommon - IsExternal: yes; ThermalTransmittance: 110 kg/K/s3
Material: Verre sablé
Qto_WallBaseQuantities - Width: 0.01 m
Pset_EnvironmentalImpactIndicators - Reference: Brise vue ext; sets with these values: 2
Pset_WallCommon - ExtendToStructure: no; LoadBearing: no; Reference: Brise vue ext
Name (Mur de base:Brise vue ext:...) | In | Height (m) | Length (m) | GrossFootprintArea (m2) | GrossVolume (m3) = NetVolume (m3) | GrossSideArea (m2) = NetSideArea (m2)
1720242 | RDC | 1.7 | 1.15858 | 0.0115858 | 0.0196958 | 1.96958
1720597 | RDC | 1.7 | 1.21358 | 0.0121358 | 0.0206308 | 2.06308
1720607 | RDC | 1.7 | 1.28893 | 0.0128893 | 0.0219119 | 2.19119
1720619 | RDC | 1.7 | 1.17716 | 0.0117716 | 0.0200117 | 2.00117
1720629 | RDC | 1.7 | 1.23716 | 0.0123716 | 0.0210317 | 2.10317
1720637 | RDC | 1.7 | 1.17716 | 0.0117716 | 0.0200117 | 2.00117
1720649 | RDC | 1.7 | 1.21358 | 0.0121358 | 0.0206308 | 2.06308
1720657 | RDC | 1.7 | 1.11716 | 0.0111716 | 0.0189917 | 1.89917
1721235 | RDC | 1.7 | 1.07716 | 0.0107716 | 0.0183117 | 1.83117
1721243 | RDC | 1.7 | 1.19716 | 0.0119716 | 0.0203517 | 2.03517
1721251 | RDC | 1.7 | 1.16216 | 0.0116216 | 0.0197567 | 1.97567
1721259 | RDC | 1.7 | 1.13751 | 0.0113751 | 0.0193377 | 1.93377
1721269 | RDC | 1.7 | 1.07716 | 0.0107716 | 0.0183117 | 1.83117
1721277 | RDC | 1.7 | 1.09725 | 0.0109725 | 0.0186532 | 1.86532
1721285 | RDC | 1.7 | 1.07716 | 0.0107716 | 0.0183117 | 1.83117
1721295 | RDC | 1.7 | 1.09725 | 0.0109725 | 0.0186532 | 1.86532
1721305 | RDC | 1.7 | 1.16251 | 0.0116251 | 0.0197627 | 1.97627
1721313 | RDC | 1.7 | 1.08285 | 0.0108285 | 0.0184084 | 1.84084
1722578 | R+1 fini | 1.63 | 1.07716 | 0.0107716 | 0.0175577 | 1.75577
1722832 | R+1 fini | 1.63 | 1.15393 | 0.0115393 | 0.0188091 | 1.88091
1722842 | R+1 fini | 1.63 | 1.16216 | 0.0116216 | 0.0189432 | 1.89432
1722850 | R+1 fini | 1.63 | 1.2 | 0.012 | 0.01956 | 1.956
1722862 | R+1 fini | 1.63 | 1.08 | 0.0108 | 0.017604 | 1.7604
1722870 | R+1 fini | 1.63 | 1.1 | 0.011 | 0.01793 | 1.793
1722878 | R+1 fini | 1.63 | 1.09358 | 0.0109358 | 0.0178253 | 1.78253
1722886 | R+1 fini | 1.63 | 1.11393 | 0.0111393 | 0.0181571 | 1.81571
1722894 | R+1 fini | 1.63 | 1.16107 | 0.0116107 | 0.0189254 | 1.89254
1722904 | R+1 fini | 1.63 | 1.08927 | 0.0108927 | 0.0177551 | 1.77551
1723470 | R+1 fini | 1.63 | 1.12 | 0.0112 | 0.018256 | 1.8256
1723478 | R+1 fini | 1.63 | 1.21358 | 0.0121358 | 0.0197813 | 1.97813
1723488 | R+1 fini | 1.63 | 1.18 | 0.0118 | 0.019234 | 1.9234
1723496 | R+1 fini | 1.63 | 1.23642 | 0.0123642 | 0.0201537 | 2.01537
1723518 | R+1 fini | 1.63 | 1.28 | 0.0128 | 0.020864 | 2.0864
1723528 | R+1 fini | 1.63 | 1.20009 | 0.0120009 | 0.0195614 | 1.95614
1723538 | R+1 fini | 1.59221 | 1.47142 | 0.0147142 | 0.0234282 | 2.34282
1723548 | R+1 fini | 1.63 | 1.12178 | 0.0112178 | 0.0182849 | 1.82849
1723556 | R+1 fini | 1.63 | 1.14035 | 0.0114035 | 0.0185878 | 1.85878
1724447 | RDC | 1.7 | 1.03716 | 0.0103716 | 0.0176317 | 1.76317
1725130 | RDC | 1.7 | 1.20393 | 0.0120393 | 0.0204669 | 2.04669
1725142 | RDC | 1.7 | 1.10695 | 0.0110695 | 0.0188181 | 1.88181
1725152 | RDC | 1.7 | 1.22195 | 0.0122195 | 0.0207731 | 2.07731
1725160 | RDC | 1.7 | 1.32195 | 0.0132195 | 0.0224731 | 2.24731
1725168 | RDC | 1.7 | 1.14012 | 0.0114012 | 0.019382 | 1.9382
1725543 | R+1 fini | 1.63 | 1.03716 | 0.0103716 | 0.0169057 | 1.69057
1725735 | R+1 fini | 1.63 | 0.970376 | 0.00970376 | 0.0158171 | 1.58171
1725749 | R+1 fini | 1.63 | 1.20393 | 0.0120393 | 0.0196241 | 1.96241
1725759 | R+1 fini | 1.63 | 1.1 | 0.011 | 0.01793 | 1.793
1725769 | R+1 fini | 1.63 | 1.21 | 0.0121 | 0.019723 | 1.9723
1725777 | R+1 fini | 1.63 | 1.32 | 0.0132 | 0.021516 | 2.1516
1725785 | R+1 fini | 1.63 | 1.13839 | 0.0113839 | 0.0185557 | 1.85557
1727096 | RDC | 5.79902 | 1.08 | 0.0108 | 0.0626295 | 6.26295
1727650 | RDC | 5.79902 | 1.08 | 0.0108 | 0.0626295 | 6.26295

# IfcWall: Mur de base:CTA (4)
In: Aras sup mur R+1
Type - PredefinedType: STANDARD
Type - Pset_WallCommon - IsExternal: yes; ThermalTransmittance: 450 kg/K/s3
Material: Steel, S 460
Qto_WallBaseQuantities - Height: 1.33791 m; Length: 4.6 m; Width: 0.1 m; GrossFootprintArea: 0.46 m2; GrossVolume: 0.310018 m3; GrossSideArea: 3.10018 m2; NetSideArea: 3.10018 m2; NetVolume: 0.310018 m3
Pset_EnvironmentalImpactIndicators - Reference: CTA; sets with these values: 2
Pset_WallCommon - LoadBearing: no; ExtendToStructure: yes; Reference: CTA
Name (Mur de base:CTA:...)
1771624
1771780
1771870
1772287

# IfcWall: Mur de base:Ext. Brique 20 (51)
Type - PredefinedType: STANDARD
Type - Pset_WallCommon - IsExternal: yes; ThermalTransmittance: 2.7 kg/K/s3
Material: Brique, commune
Pset_EnvironmentalImpactIndicators - Reference: Ext. Brique 20; sets with these values: 2
Pset_WallCommon - LoadBearing: no; Reference: Ext. Brique 20
Name (Mur de base:Ext. Brique 20:...) | In | Height (m) | Length (m) | Width (m) | GrossFootprintArea (m2) | GrossVolume (m3) | GrossSideArea (m2) | NetSideArea (m2) | NetVolume (m3) | ExtendToStructure
321509 | RDC | 4.4 | 13.6149 | 0.2 | 2.72299 | 10.9731 | 54.8657 | 47.8828 | 9.54835 | no
322070 | RDC | 4.4 | 12.2198 | 0.2 | 2.44063 | 9.75215 | 48.7608 | 41.7779 | 8.31271 | no
322618 | RDC | 4.4 | 19.9125 | 0.2 | 3.9825 | 15.8654 | 79.327 | 60.7061 | 12.0004 | no
322892 | RDC |  |  |  |  |  |  |  | 4.31731 | no
323027 | RDC | 4.4 | 3.03 | 0.2 | 0.606 | 2.6664 | 13.332 | 13.332 | 2.6664 | no
323265 | RDC | 4.4 | 17.9841 | 0.2 | 3.59349 | 15.826 | 79.1299 | 64.3158 | 12.7648 | no
323441 | RDC |  |  |  |  |  |  |  | 2.01214 | no
324018 | RDC |  |  |  |  |  |  |  | 25.7783 | no
324200 | RDC | 7.51 | 18.3 | 0.2 | 3.66 | 0.32 | 1.6 | 121.475 | 24.1871 | no
324371 | RDC | 7.51 | 13.63 | 0.2 | 2.726 | 19.8483 | 99.2416 | 98.0018 | 19.592 | no
324618 | RDC | 7.51 | 3.2 | 0.2 | 0.64 | 4.8064 | 24.032 | 18.3544 | 3.63668 | no
324713 | RDC | 7.51 | 0.6 | 0.2 | 0.12 | 0.9012 | 4.506 | 4.506 | 0.9012 | no
325112 | RDC |  |  |  |  |  |  |  | 19.6424 | no
325546 | RDC | 7.51 | 3.86 | 0.2 | 0.772 | 5.65445 | 28.2722 | 25.6125 | 5.10033 | no
325605 | RDC |  |  |  |  |  |  |  | 1.08662 | no
325714 | RDC |  |  |  |  |  |  |  | 9.6188 | no
325846 | RDC |  |  |  |  |  |  |  | 6.84928 | no
325992 | RDC | 6.5 | 2.77 | 0.2 | 0.554 | 3.601 | 18.005 | 18.005 | 3.601 | no
326305 | RDC | 3.6 | 25.195 | 0.2 | 5.039 | 0.288 | 1.44 | 1.44 | 0.216 | no
326350 | RDC | 3.5 | 6.2375 | 0.2 | 1.2475 | 4.36625 | 21.8313 | 21.8313 | 4.36625 | no
326493 | RDC | 7.51 | 3.18 | 0.2 | 0.636 | 4.77636 | 23.8818 | 18.2042 | 3.60664 | no
326686 | RDC | 3.3 | 6.76 | 0.2 | 1.352 | 4.4616 | 22.308 | 22.308 | 4.4616 | no
354562 | RDC | 4.01 | 1.55 | 0.2 | 0.31 | 1.2431 | 6.2155 | 6.2155 | 1.2431 | no
354626 | RDC | 4.01 | 4.52 | 0.2 | 0.904 | 2.73073 | 13.6536 | 13.6536 | 2.73073 | no
354754 | RDC | 4.01 | 6.97 | 0.2 | 1.394 | 5.58994 | 27.9497 | 27.9497 | 5.58994 | no
355014 | RDC |  |  |  |  |  |  |  | 3.0102 | no
355142 | RDC |  |  |  |  |  |  |  | 4.85094 | no
557306 | RDC |  |  |  |  |  |  |  | 32.4219 | no
1011427 | RDC | 3.3 | 1.7 | 0.2 | 0.34 | 1.122 | 5.61 | 5.61 | 1.122 | no
1011802 | RDC | 3.4 | 2.98 | 0.2 | 0.596 | 1.34031 | 6.70155 | 6.70155 | 1.34031 | yes
1340747 | RDC | 4.4 | 13.0105 | 0.2 | 2.59876 | 10.4412 | 52.206 | 45.2232 | 9.00176 | no
1355973 | R+1 fini | 3.3 | 24.75 | 0.2 | 4.95 | 10.7077 | 53.5387 | 53.5387 | 10.7077 | no
1356223 | R+1 fini | 3.3 | 30.465 | 0.2 | 6.093 | 15.9127 | 79.5636 | 79.5636 | 15.9127 | no
1356430 | R+1 fini | 3.3 | 25.095 | 0.2 | 5.019 | 12.7835 | 63.9176 | 63.9176 | 12.7835 | no
1356617 | R+1 fini | 3.3 | 26.38 | 0.2 | 5.276 | 11.0144 | 55.0722 | 55.0722 | 11.0144 | no
1356857 | R+1 fini | 3.3 | 5.42 | 0.2 | 1.084 | 3.5772 | 17.886 | 17.886 | 3.5772 | no
1358042 | R+1 fini | 3.91 | 4.62 | 0.2 | 0.924 | 3.50814 | 17.5407 | 17.5407 | 3.50395 | no
1358543 | R+1 fini | 3.3 | 5.42 | 0.2 | 1.084 | 3.5772 | 17.886 | 17.886 | 3.5772 | no
1365402 | R+1 fini |  |  |  |  |  |  |  | 5.07023 | no
1365800 | R+1 fini |  |  |  |  |  |  |  | 3.36564 | no
1380029 | R+1 fini | 3.3 | 2.98 | 0.2 | 0.596 | 1.28071 | 6.40355 | 6.40355 | 1.28071 | no
1596504 | RDC | 7.51 | 0.7875 | 0.2 | 0.1575 | 1.18282 | 5.91412 | 5.91412 | 1.18282 | no
1604221 | R+1 fini |  |  |  |  |  |  |  | 5.35344 | no
1605043 | R+1 fini | 3.3 | 6.26 | 0.2 | 1.252 | 4.1316 | 20.658 | 20.658 | 4.1316 | no
1639863 | RDC | 0.6 | 1.81 | 0.2 | 0.362 | 0.2172 | 1.086 | 1.086 | 0.2172 | no
1640026 | RDC | 0.6 | 9.76 | 0.2 | 1.952 | 1.1712 | 5.856 | 5.856 | 1.1712 | no
1640123 | RDC | 0.6 | 1.61 | 0.2 | 0.322 | 0.1932 | 0.966 | 0.966 | 0.1932 | no
1640258 | RDC | 0.6 | 9.56 | 0.2 | 1.912 | 1.1472 | 5.736 | 5.736 | 1.1472 | no
1663172 | R+1 fini | 3.91 | 4.61 | 0.2 | 0.922 | 3.60502 | 18.0251 | 18.0251 | 3.60502 | no
1663733 | R+1 fini | 3.3 | 1.9 | 0.2 | 0.38 | 1.254 | 6.27 | 6.27 | 1.254 | no
1663876 | R+1 fini | 3.3 | 1.75 | 0.2 | 0.35 | 1.155 | 5.775 | 5.775 | 1.155 | no

# IfcWall: Mur de base:Ext. Brique 22 (3)
In: R+1 fini
Type - PredefinedType: STANDARD
Type - Pset_WallCommon - IsExternal: yes; ThermalTransmittance: 2.45455 kg/K/s3
Material: Brique, commune
Qto_WallBaseQuantities - Height: 3.3 m; Width: 0.22 m
Pset_EnvironmentalImpactIndicators - Reference: Ext. Brique 22; sets with these values: 2
Pset_WallCommon - ExtendToStructure: no; LoadBearing: no; Reference: Ext. Brique 22
Name (Mur de base:Ext. Brique 22:...) | Length (m) | GrossFootprintArea (m2) | GrossVolume (m3) = NetVolume (m3) | GrossSideArea (m2) = NetSideArea (m2)
1441691 | 1.3 | 0.286 | 0.9438 | 4.29
1441843 | 1.4 | 0.308 | 1.0164 | 4.62
1441998 | 0.9 | 0.198 | 0.6534 | 2.97

# IfcWall: Mur de base:Ext. Brique 22 + Isolant 10, Mur de base:Ext. Brique 22 + Isolant 10:1009441
In: RDC
Type - PredefinedType: STANDARD; Material: Brique, commune, Maçonnerie - Isolant
Type - Pset_WallCommon - IsExternal: yes; ThermalTransmittance: 2.45455 kg/K/s3
Qto_WallBaseQuantities - Brique, commune, Width: 0.22 m; Maçonnerie - Isolant, Width: 0.1 m; Width: 0.32 m; Height: 2.6 m; Length: 6.005 m; GrossVolume: 4.27808 m3; GrossSideArea: 13.369 m2; NetSideArea: 13.369 m2; NetVolume: 4.27808 m3
Pset_EnvironmentalImpactIndicators - Reference: Ext. Brique 22 + Isolant 10; sets with these values: 2
Pset_WallCommon - ExtendToStructure: no; LoadBearing: no; Reference: Ext. Brique 22 + Isolant 10

# IfcWall: Mur de base:Ext. Voile BA 18 (13)
Type - PredefinedType: STANDARD
Type - Pset_WallCommon - IsExternal: yes
Material: Maçonnerie - Voile BA
Qto_WallBaseQuantities - Width: 0.18 m
Pset_EnvironmentalImpactIndicators - Reference: Ext. Voile BA 18; sets with these values: 2
Pset_WallCommon - ExtendToStructure: no; LoadBearing: no; Reference: Ext. Voile BA 18
Name (Mur de base:Ext. Voile BA 18:...) | In | Height (m) | Length (m) | GrossFootprintArea (m2) | GrossVolume (m3) | GrossSideArea (m2) = NetSideArea (m2) | NetVolume (m3)
326970 | RDC | 6.9 | 3.5 | 0.63 | 4.347 | 24.15 | 4.347
327314 | RDC | 3.4 | 26.4 | 4.752 | 11.4658 | 63.6986 | 11.4658
328398 | RDC | 3.4 | 24.75 | 4.455 | 10.1611 | 56.4507 | 10.1611
328893 | RDC | 3.4 | 30.585 | 5.5053 | 15.018 | 83.4331 | 15.018
329149 | RDC | 3.4 | 6.92 | 1.2456 | 4.23504 | 23.528 | 4.23504
329927 | RDC | 3.79 | 9.42901 | 1.69588 | 5.31197 | 29.5109 | 5.3069
330264 | RDC | 3.79 | 16.7372 | 3.01136 | 9.68014 | 53.7785 | 9.67506
330507 | RDC | 6.9 | 3.62083 | 0.651749 | 4.49707 | 24.9837 | 4.49707
1604632 | RDC | 3.4 | 25.195 | 4.5351 | 12.0181 | 66.7671 | 12.0181
1607444 | R+1 fini | 3.3 | 1.33 | 0.2394 | 0.79002 | 4.389 | 0.79002
1607624 | R+1 fini | 3.3 | 1.3 | 0.234 | 0.7722 | 4.29 | 0.7722
1713068 | RDC | 3.5 | 1.23507 | 0.222313 | 0.778096 | 4.32275 | 0.778096
1713290 | RDC | 3.5 | 1.23507 | 0.222313 | 0.778096 | 4.32275 | 0.778096

# IfcWall: Mur de base:Ext. Voile BA 20 (6)
Type - PredefinedType: STANDARD
Type - Pset_WallCommon - IsExternal: yes
Material: Maçonnerie - Voile BA
Pset_EnvironmentalImpactIndicators - Reference: Ext. Voile BA 20; sets with these values: 2
Pset_WallCommon - ExtendToStructure: no; LoadBearing: no; Reference: Ext. Voile BA 20
Name (Mur de base:Ext. Voile BA 20:...) | In | Height (m) | Length (m) | Width (m) | GrossFootprintArea (m2) | GrossVolume (m3) | GrossSideArea (m2) = NetSideArea (m2) | NetVolume (m3)
330965 | RDC | 3.79 | 6.51567 | 0.2 | 1.29981 | 4.93888 | 24.6944 | 4.92626
331514 | RDC | 3.79 | 13.425 | 0.2 | 2.67835 | 9.37745 | 46.8872 | 9.37745
331824 | RDC | 3.6 | 5.42 | 0.2 | 1.084 | 3.9024 | 19.512 | 3.9024
332018 | Arase inf soubassement | 0.25 | 1.55 | 0.2 | 0.31 | 0.0775 | 0.3875 | 0.0775
1009134 | RDC | 2.6 | 1.21 | 0.2 | 0.242 | 0.6292 | 3.146 | 0.6292
1009765 | RDC |  |  |  |  |  |  | 9.55892

# IfcWall: Mur de base:Générique - Int. 70 mm (225)
Type - PredefinedType: STANDARD
Type - Pset_WallCommon - IsExternal: no
Material: Mur par défaut
Qto_WallBaseQuantities - Width: 0.07 m
Pset_EnvironmentalImpactIndicators - Reference: Générique - Int. 70 mm; sets with these values: 2
Pset_WallCommon - ExtendToStructure: no; LoadBearing: no; Reference: Générique - Int. 70 mm
Name (Mur de base:Générique - Int. 70 mm:...) | In | Height (m) | Length (m) | GrossFootprintArea (m2) | GrossVolume (m3) | GrossSideArea (m2) = NetSideArea (m2) | NetVolume (m3)
991286 | RDC | 2.6 | 2.53 | 0.1771 | 0.213535 | 3.0505 | 0.213535
991335 | RDC | 2.6 | 1.74 | 0.1218 | 0.31668 | 4.524 | 0.31668
991461 | RDC | 2.6 | 2.53 | 0.1771 | 0.213535 | 3.0505 | 0.213535
991462 | RDC | 2.6 | 1.75 | 0.1225 | 0.3185 | 4.55 | 0.3185
991474 | RDC | 2.6 | 2.6 | 0.182 | 0.226275 | 3.2325 | 0.226275
991475 | RDC | 2.6 | 1.67 | 0.1169 | 0.30394 | 4.342 | 0.30394
991485 | RDC | 2.6 | 2.565 | 0.17955 | 0.219905 | 3.1415 | 0.219905
991486 | RDC | 2.6 | 1.74 | 0.1218 | 0.31668 | 4.524 | 0.31668
991701 | RDC | 2.6 | 1.67 | 0.1169 | 0.30394 | 4.342 | 0.30394
991777 | RDC | 2.6 | 2.53 | 0.1771 | 0.213535 | 3.0505 | 0.213535
991877 | RDC | 2.6 | 1.67 | 0.1169 | 0.30394 | 4.342 | 0.30394
991878 | RDC | 2.6 | 2.565 | 0.17955 | 0.219905 | 3.1415 | 0.219905
996110 | RDC | 2.6 | 2.6 | 0.182 | 0.226275 | 3.2325 | 0.226275
996168 | RDC | 2.6 | 1.6 | 0.112 | 0.2912 | 4.16 | 0.2912
996474 | RDC | 2.6 | 2.6 | 0.182 | 0.226275 | 3.2325 | 0.226275
996475 | RDC | 2.6 | 1.6 | 0.112 | 0.2912 | 4.16 | 0.2912
996587 | RDC | 2.6 | 2.6 | 0.182 | 0.226275 | 3.2325 | 0.226275
996588 | RDC | 2.6 | 1.6 | 0.112 | 0.2912 | 4.16 | 0.2912
996739 | RDC | 2.6 | 2.595 | 0.18165 | 0.225365 | 3.2195 | 0.225365
996827 | RDC | 2.6 | 1.6 | 0.112 | 0.2912 | 4.16 | 0.2912
996930 | RDC | 2.6 | 2.595 | 0.18165 | 0.225365 | 3.2195 | 0.225365
996931 | RDC | 2.6 | 1.6 | 0.112 | 0.2912 | 4.16 | 0.2912
997097 | RDC | 2.6 | 0.92 | 0.0644 | 0.16744 | 2.392 | 0.16744
997151 | RDC | 2.6 | 0.7 | 0.049 | 0.1274 | 1.82 | 0.1274
997251 | RDC | 2.6 | 0.92 | 0.0644 | 0.16744 | 2.392 | 0.16744
997252 | RDC | 2.6 | 0.71 | 0.0497 | 0.12922 | 1.846 | 0.12922
997260 | RDC | 2.6 | 0.92 | 0.0644 | 0.16744 | 2.392 | 0.16744
997261 | RDC | 2.6 | 0.7 | 0.049 | 0.1274 | 1.82 | 0.1274
997269 | RDC | 2.6 | 0.945 | 0.06615 | 0.17199 | 2.457 | 0.17199
997270 | RDC | 2.6 | 0.7 | 0.049 | 0.1274 | 1.82 | 0.1274
997362 | RDC | 2.6 | 0.92 | 0.0644 | 0.16744 | 2.392 | 0.16744
997416 | RDC | 2.6 | 0.63 | 0.0441 | 0.11466 | 1.638 | 0.11466
997581 | RDC | 2.6 | 0.895 | 0.06265 | 0.16289 | 2.327 | 0.16289
997582 | RDC | 2.6 | 0.6 | 0.042 | 0.1092 | 1.56 | 0.1092
997659 | RDC | 2.6 | 0.7 | 0.049 | 0.1274 | 1.82 | 0.1274
997709 | RDC | 2.6 | 0.85 | 0.0595 | 0.1547 | 2.21 | 0.1547
997790 | RDC | 2.6 | 0.7 | 0.049 | 0.1274 | 1.82 | 0.1274
997791 | RDC | 2.6 | 0.85 | 0.0595 | 0.1547 | 2.21 | 0.1547
997799 | RDC | 2.6 | 0.7 | 0.049 | 0.1274 | 1.82 | 0.1274
997800 | RDC | 2.6 | 0.85 | 0.0595 | 0.1547 | 2.21 | 0.1547
997864 | RDC | 2.6 | 0.92 | 0.0644 | 0.16744 | 2.392 | 0.16744
997898 | RDC | 2.6 | 0.63 | 0.0441 | 0.11466 | 1.638 | 0.11466
997998 | RDC | 2.6 | 0.92 | 0.0644 | 0.16744 | 2.392 | 0.16744
997999 | RDC | 2.6 | 0.63 | 0.0441 | 0.11466 | 1.638 | 0.11466
999270 | RDC | 2.6 | 4.06 | 0.2842 | 0.59367 | 8.481 | 0.59367
999643 | RDC | 2.6 | 2.00971 | 0.140272 | 0.365767 | 5.22524 | 0.364706
1000333 | RDC | 2.6 | 3.96 | 0.2772 | 0.444745 | 6.3535 | 0.444745
1000580 | RDC | 2.6 | 3.24445 | 0.226704 | 0.32904 | 4.70057 | 0.32798
1000730 | RDC | 2.6 | 0.9 | 0.063 | 0.1638 | 2.34 | 0.1638
1000987 | RDC | 2.6 | 0.9 | 0.063 | 0.1638 | 2.34 | 0.1638
1001407 | RDC | 2.6 | 2.57 | 0.1799 | 0.46774 | 6.682 | 0.46774
1001509 | RDC | 2.6 | 2.145 | 0.15015 | 0.259665 | 3.7095 | 0.259665
1002478 | RDC | 2.6 | 1.775 | 0.12425 | 0.20685 | 2.955 | 0.20685
1002694 | RDC | 2.1 | 2.25 | 0.1575 | 0.33075 | 4.725 | 0.33075
1003374 | RDC | 2.1 | 1.75 | 0.1225 | 0.25725 | 3.675 | 0.25725
1003950 | RDC | 2.6 | 0.6 | 0.042 | 0.1092 | 1.56 | 0.1092
1004079 | RDC | 2.6 | 0.6 | 0.042 | 0.1092 | 1.56 | 0.1092
1004248 | RDC | 2.6 | 2.1 | 0.147 | 0.251475 | 3.5925 | 0.251475
1004303 | RDC | 2.6 | 2.5 | 0.175 | 0.455 | 6.5 | 0.453547
1004499 | RDC | 2.6 | 2.57 | 0.1799 | 0.46774 | 6.682 | 0.464835
1004561 | RDC | 2.6 | 2.03 | 0.1421 | 0.238735 | 3.4105 | 0.238735
1004927 | RDC | 2.6 | 1.65 | 0.1155 | 0.185552 | 2.65075 | 0.185552
1005012 | RDC | 2.6 | 1.66 | 0.1162 | 0.188825 | 2.6975 | 0.188825
1005138 | RDC | 2.1 | 1.8 | 0.126 | 0.2646 | 3.78 | 0.2646
1005263 | RDC | 2.1 | 1.8 | 0.126 | 0.2646 | 3.78 | 0.2646
1005354 | RDC | 2.1 | 1.8 | 0.126 | 0.2646 | 3.78 | 0.2646
1005439 | RDC | 2.1 | 1.8 | 0.126 | 0.2646 | 3.78 | 0.2646
1005593 | RDC | 2.6 | 0.6 | 0.042 | 0.1092 | 1.56 | 0.1092
1005660 | RDC | 2.6 | 0.6 | 0.042 | 0.1092 | 1.56 | 0.1092
1005741 | RDC | 2.1 | 1.8 | 0.126 | 0.2646 | 3.78 | 0.2646
1005807 | RDC | 2.1 | 1.8 | 0.126 | 0.2646 | 3.78 | 0.2646
1006186 | RDC | 2.6 | 2.22 | 0.1554 | 0.273315 | 3.9045 | 0.273315
1006252 | RDC | 2.6 | 2.5 | 0.175 | 0.455 | 6.5 | 0.455
1006325 | RDC | 2.6 | 1.79 | 0.1253 | 0.20958 | 2.994 | 0.20958
1006930 | RDC | 2.6 | 1.97 | 0.1379 | 0.35854 | 5.122 | 0.35854
1007005 | RDC | 2.6 | 1.725 | 0.12075 | 0.1687 | 2.41 | 0.1687
1007204 | RDC | 2.6 | 1.7 | 0.119 | 0.3094 | 4.42 | 0.3094
1007401 | RDC | 2.6 | 2.215 | 0.15505 | 0.14168 | 2.024 | 0.14168
1007514 | RDC | 2.6 | 3.49 | 0.2443 | 0.63518 | 9.074 | 0.63518
1007577 | RDC | 2.6 | 1.01 | 0.0707 | 0.18382 | 2.626 | 0.18382
1007651 | RDC | 2.6 | 0.4 | 0.028 | 0.0728 | 1.04 | 0.0728
1007711 | RDC | 2.6 | 0.4 | 0.028 | 0.0728 | 1.04 | 0.0728
1007843 | RDC | 2.6 | 1.47 | 0.1029 | 0.26754 | 3.822 | 0.26754
1007945 | RDC | 2.6 | 1.77 | 0.1239 | 0.17689 | 2.527 | 0.17689
1008025 | RDC | 2.6 | 1.47 | 0.1029 | 0.136815 | 1.9545 | 0.136815
1008279 | RDC | 2.6 | 2.47 | 0.1729 | 0.30429 | 4.347 | 0.30429
1008369 | RDC | 2.6 | 2.355 | 0.16485 | 0.42861 | 6.123 | 0.42861
1008576 | RDC | 2.6 | 0.47 | 0.0329 | 0.08554 | 1.222 | 0.08554
1008626 | RDC | 2.6 | 0.555 | 0.03885 | 0.10101 | 1.443 | 0.10101
1012335 | RDC | 2.6 | 2.24 | 0.1568 | 0.40768 | 5.824 | 0.40768
1012966 | RDC | 2.6 | 0.6 | 0.042 | 0.1092 | 1.56 | 0.1092
1013068 | RDC | 2.1 | 1.8 | 0.126 | 0.2646 | 3.78 | 0.2646
1013265 | RDC | 2.1 | 1.8 | 0.126 | 0.2646 | 3.78 | 0.2646
1013273 | RDC | 2.1 | 1.85 | 0.1295 | 0.27195 | 3.885 | 0.27195
1013283 | RDC | 2.1 | 1.8 | 0.126 | 0.2646 | 3.78 | 0.2646
1013291 | RDC | 2.1 | 1.85 | 0.1295 | 0.27195 | 3.885 | 0.27195
1013301 | RDC | 2.1 | 1.8 | 0.126 | 0.2646 | 3.78 | 0.2646
1013372 | RDC | 2.1 | 1.85 | 0.1295 | 0.27195 | 3.885 | 0.27195
1013382 | RDC | 2.1 | 1.9 | 0.133 | 0.2793 | 3.99 | 0.2793
1013390 | RDC | 2.1 | 1.9 | 0.133 | 0.2793 | 3.99 | 0.2793
1013745 | RDC | 2.6 | 1.71 | 0.1197 | 0.19502 | 2.786 | 0.19502
1013973 | RDC | 2.6 | 2.64 | 0.1848 | 0.48048 | 6.864 | 0.48048
1014028 | RDC | 2.6 | 2.07 | 0.1449 | 0.246015 | 3.5145 | 0.246015
1014554 | RDC | 2.6 | 0.6 | 0.042 | 0.1092 | 1.56 | 0.1092
1014625 | RDC | 2.6 | 0.6 | 0.042 | 0.1092 | 1.56 | 0.1092
1014823 | RDC | 2.6 | 2.57 | 0.1799 | 0.46774 | 6.682 | 0.46774
1014877 | RDC | 2.6 | 2.09 | 0.1463 | 0.249655 | 3.5665 | 0.249655
1015394 | RDC | 2.6 | 2.615 | 0.18305 | 0.47593 | 6.799 | 0.47593
1015503 | RDC | 2.6 | 2.09 | 0.1463 | 0.249655 | 3.5665 | 0.249655
1015683 | RDC | 2.6 | 1.72 | 0.1204 | 0.19684 | 2.812 | 0.19684
1015779 | RDC | 2.6 | 1.72 | 0.1204 | 0.19684 | 2.812 | 0.19684
1015869 | RDC | 2.6 | 0.6 | 0.042 | 0.1092 | 1.56 | 0.1092
1015870 | RDC | 2.6 | 0.6 | 0.042 | 0.1092 | 1.56 | 0.1092
1015947 | RDC | 2.6 | 2.57 | 0.1799 | 0.46774 | 6.682 | 0.46774
1015948 | RDC | 2.6 | 2.08 | 0.1456 | 0.247835 | 3.5405 | 0.247835
1015951 | RDC | 2.6 | 1.72 | 0.1204 | 0.19684 | 2.812 | 0.19684
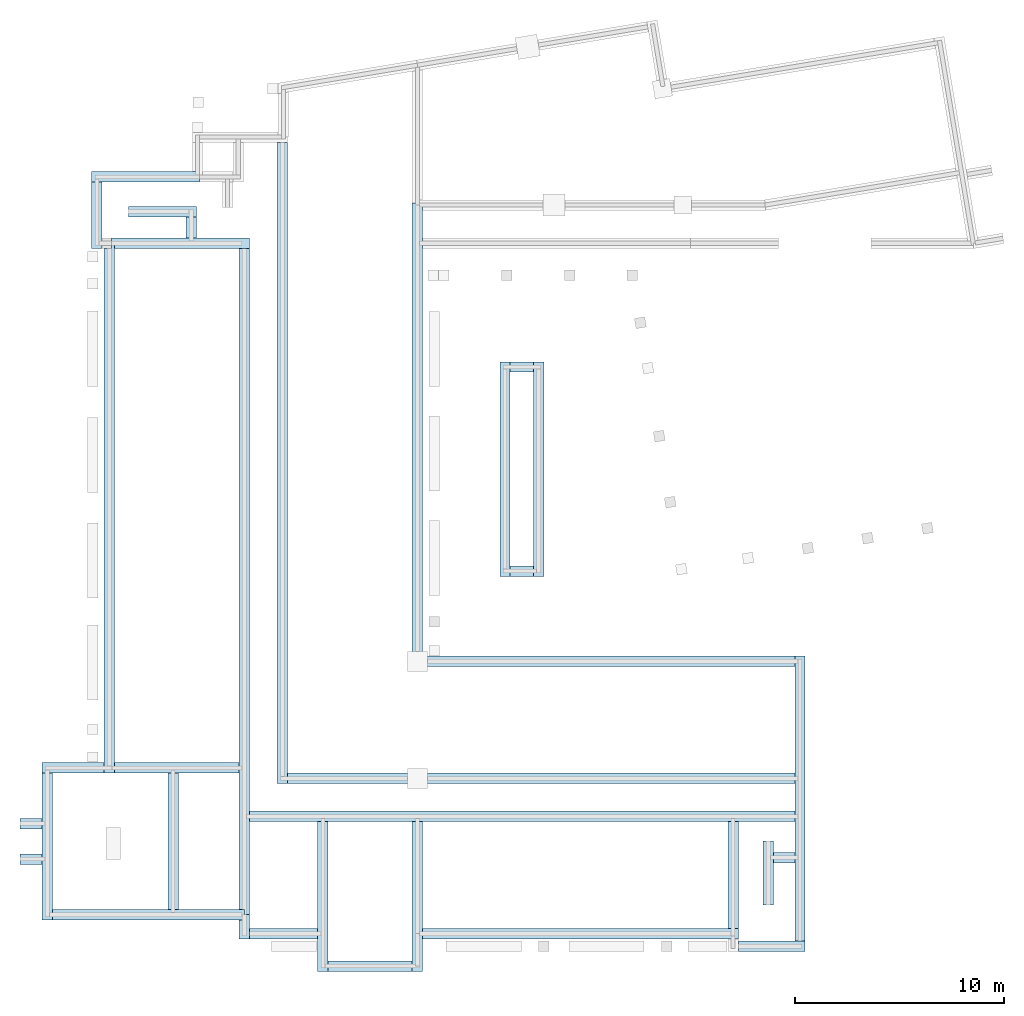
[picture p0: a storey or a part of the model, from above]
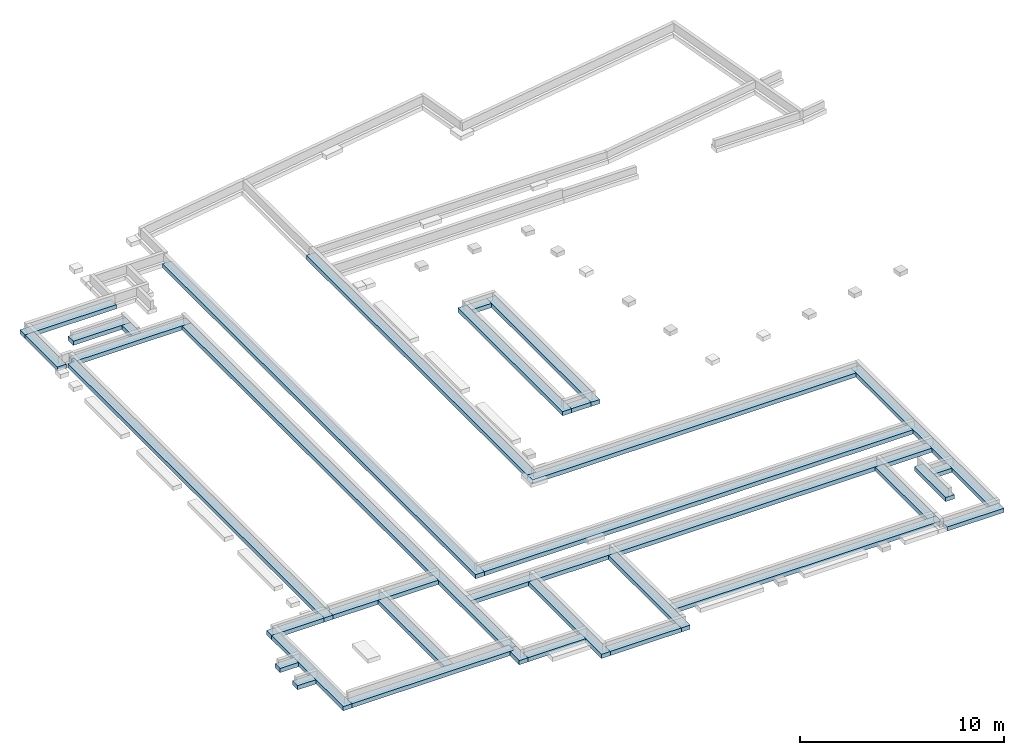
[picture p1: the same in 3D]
Properties of the parts of a building model (IFC4), part 5 of 5

# IfcWall: Mur de base:Générique - Int. 70 mm (225)
Name (Mur de base:Générique - Int. 70 mm:...) | In | Height (m) | Length (m) | GrossFootprintArea (m2) | GrossVolume (m3) | GrossSideArea (m2) = NetSideArea (m2) | NetVolume (m3)
1016049 | RDC | 2.6 | 2.3 | 0.161 | 0.4186 | 5.98 | 0.4186
1016097 | RDC | 2.6 | 1.95 | 0.1365 | 0.20965 | 2.995 | 0.20965
1016205 | RDC | 2.6 | 2.65798 | 0.186058 | 0.483752 | 6.91074 | 0.483752
1367877 | R+1 fini | 2.6 | 1.74 | 0.1218 | 0.31668 | 4.524 | 0.31668
1367992 | R+1 fini | 2.6 | 2.52 | 0.1764 | 0.211715 | 3.0245 | 0.211715
1368070 | R+1 fini | 2.6 | 0.772 | 0.05404 | 0.140504 | 2.0072 | 0.140504
1368150 | R+1 fini | 2.6 | 0.85 | 0.0595 | 0.1547 | 2.21 | 0.1547
1368323 | R+1 fini | 2.6 | 1.75 | 0.1225 | 0.3185 | 4.55 | 0.3185
1368438 | R+1 fini | 2.6 | 2.52 | 0.1764 | 0.211715 | 3.0245 | 0.211715
1368605 | R+1 fini | 2.6 | 0.78 | 0.0546 | 0.14196 | 2.028 | 0.14196
1368658 | R+1 fini | 2.6 | 0.85 | 0.0595 | 0.1547 | 2.21 | 0.1547
1368789 | R+1 fini | 2.6 | 2.59 | 0.1813 | 0.224455 | 3.2065 | 0.224455
1368851 | R+1 fini | 2.6 | 1.6 | 0.112 | 0.2912 | 4.16 | 0.2912
1368941 | R+1 fini | 2.6 | 0.895 | 0.06265 | 0.16289 | 2.327 | 0.16289
1369057 | R+1 fini | 2.6 | 0.6 | 0.042 | 0.1092 | 1.56 | 0.1092
1369207 | R+1 fini | 2.6 | 1.74 | 0.1218 | 0.31668 | 4.524 | 0.31668
1369315 | R+1 fini | 2.6 | 2.52 | 0.1764 | 0.211715 | 3.0245 | 0.211715
1369418 | R+1 fini | 2.6 | 0.77 | 0.0539 | 0.14014 | 2.002 | 0.14014
1369486 | R+1 fini | 2.6 | 0.85 | 0.0595 | 0.1547 | 2.21 | 0.1547
1369643 | R+1 fini | 2.6 | 2.615 | 0.18305 | 0.229005 | 3.2715 | 0.229005
1369690 | R+1 fini | 2.6 | 1.6 | 0.112 | 0.2912 | 4.16 | 0.2912
1369742 | R+1 fini | 2.6 | 0.92 | 0.0644 | 0.16744 | 2.392 | 0.16744
1369834 | R+1 fini | 2.6 | 0.63 | 0.0441 | 0.11466 | 1.638 | 0.11466
1369898 | R+1 fini | 2.6 | 1.74 | 0.1218 | 0.31668 | 4.524 | 0.31668
1370031 | R+1 fini | 2.6 | 2.545 | 0.17815 | 0.216265 | 3.0895 | 0.216265
1370102 | R+1 fini | 2.6 | 0.77 | 0.0539 | 0.14014 | 2.002 | 0.14014
1370161 | R+1 fini | 2.6 | 0.875 | 0.06125 | 0.15925 | 2.275 | 0.15925
1370285 | R+1 fini | 2.6 | 2.6 | 0.182 | 0.226275 | 3.2325 | 0.226275
1370393 | R+1 fini | 2.6 | 1.6 | 0.112 | 0.2912 | 4.16 | 0.2912
1370459 | R+1 fini | 2.6 | 0.92 | 0.0644 | 0.16744 | 2.392 | 0.16744
1370538 | R+1 fini | 2.6 | 0.63 | 0.0441 | 0.11466 | 1.638 | 0.11466
1370663 | R+1 fini | 2.6 | 2.595 | 0.18165 | 0.225365 | 3.2195 | 0.225365
1370729 | R+1 fini | 2.6 | 1.6 | 0.112 | 0.2912 | 4.16 | 0.2912
1370841 | R+1 fini | 2.6 | 0.7 | 0.049 | 0.1274 | 1.82 | 0.1274
1370909 | R+1 fini | 2.6 | 0.85 | 0.0595 | 0.1547 | 2.21 | 0.1547
1371031 | R+1 fini | 2.6 | 2.6 | 0.182 | 0.226275 | 3.2325 | 0.226275
1371126 | R+1 fini | 2.6 | 1.6 | 0.112 | 0.2912 | 4.16 | 0.2912
1371183 | R+1 fini | 2.6 | 0.92 | 0.0644 | 0.16744 | 2.392 | 0.16744
1371236 | R+1 fini | 2.6 | 0.63 | 0.0441 | 0.11466 | 1.638 | 0.11466
1371361 | R+1 fini | 2.6 | 2.6 | 0.182 | 0.226275 | 3.2325 | 0.226275
1371518 | R+1 fini | 2.6 | 1.6 | 0.112 | 0.2912 | 4.16 | 0.2912
1371603 | R+1 fini | 2.6 | 0.92 | 0.0644 | 0.16744 | 2.392 | 0.16744
1371712 | R+1 fini | 2.6 | 0.63 | 0.0441 | 0.11466 | 1.638 | 0.11466
1371857 | R+1 fini | 2.6 | 2.6 | 0.182 | 0.226275 | 3.2325 | 0.226275
1371948 | R+1 fini | 2.6 | 1.6 | 0.112 | 0.2912 | 4.16 | 0.2912
1372010 | R+1 fini | 2.6 | 0.92 | 0.0644 | 0.16744 | 2.392 | 0.16744
1372067 | R+1 fini | 2.6 | 0.63 | 0.0441 | 0.11466 | 1.638 | 0.11466
1372180 | R+1 fini | 2.6 | 2.45 | 0.1715 | 0.198975 | 2.8425 | 0.198975
1372263 | R+1 fini | 2.6 | 2.38 | 0.1666 | 0.43316 | 6.188 | 0.43316
1372441 | R+1 fini | 2.6 | 2.77 | 0.1939 | 0.257215 | 3.6745 | 0.257215
1372486 | R+1 fini | 2.6 | 1.6 | 0.112 | 0.2912 | 4.16 | 0.2912
1372553 | R+1 fini | 2.6 | 0.69 | 0.0483 | 0.12558 | 1.794 | 0.12558
1372629 | R+1 fini | 2.6 | 0.84 | 0.0588 | 0.15288 | 2.184 | 0.15288
1372793 | R+1 fini | 2.6 | 0.87 | 0.0609 | 0.15834 | 2.262 | 0.15834
1372829 | R+1 fini | 2.6 | 0.52 | 0.0364 | 0.09464 | 1.352 | 0.09464
1372944 | R+1 fini | 2.6 | 2.34 | 0.1638 | 0.42588 | 6.084 | 0.42588
1373031 | R+1 fini | 2.6 | 2.65 | 0.1855 | 0.194404 | 2.7772 | 0.194404
1373126 | R+1 fini | 2.6 | 2.64 | 0.1848 | 0.48048 | 6.864 | 0.48048
1373198 | R+1 fini | 2.6 | 2.07 | 0.1449 | 0.246015 | 3.5145 | 0.246015
1373240 | R+1 fini | 2.6 | 1.71 | 0.1197 | 0.19502 | 2.786 | 0.19502
1373390 | R+1 fini | 2.6 | 0.6 | 0.042 | 0.1092 | 1.56 | 0.1092
1373483 | R+1 fini | 2.6 | 0.6 | 0.042 | 0.1092 | 1.56 | 0.1092
1373600 | R+1 fini | 2.6 | 2.6 | 0.182 | 0.4732 | 6.76 | 0.4732
1373735 | R+1 fini | 2.6 | 2.09 | 0.1463 | 0.249655 | 3.5665 | 0.249655
1373854 | R+1 fini | 2.6 | 1.72 | 0.1204 | 0.19684 | 2.812 | 0.19684
1374009 | R+1 fini | 2.6 | 2.575 | 0.18025 | 0.46865 | 6.695 | 0.46865
1374112 | R+1 fini | 2.6 | 2.09 | 0.1463 | 0.249655 | 3.5665 | 0.249655
1374270 | R+1 fini | 2.6 | 1.72 | 0.1204 | 0.19684 | 2.812 | 0.19684
1374393 | R+1 fini | 2.6 | 0.6 | 0.042 | 0.1092 | 1.56 | 0.1092
1374481 | R+1 fini | 2.6 | 0.6 | 0.042 | 0.1092 | 1.56 | 0.1092
1374592 | R+1 fini | 2.6 | 2.15 | 0.1505 | 0.260575 | 3.7225 | 0.260575
1374671 | R+1 fini | 2.6 | 2.5 | 0.175 | 0.455 | 6.5 | 0.455
1374781 | R+1 fini | 2.6 | 1.72 | 0.1204 | 0.19684 | 2.812 | 0.19684
1374941 | R+1 fini | 2.6 | 2.205 | 0.15435 | 0.270585 | 3.8655 | 0.270585
1375014 | R+1 fini | 2.6 | 2.54 | 0.1778 | 0.46228 | 6.604 | 0.46228
1375131 | R+1 fini | 2.6 | 1.775 | 0.12425 | 0.20685 | 2.955 | 0.20685
1375313 | R+1 fini | 2.6 | 0.6 | 0.042 | 0.1092 | 1.56 | 0.1092
1375389 | R+1 fini | 2.6 | 0.6 | 0.042 | 0.1092 | 1.56 | 0.1092
1375934 | R+1 fini | 2.6 | 2.08 | 0.1456 | 0.247835 | 3.5405 | 0.247835
1376042 | R+1 fini | 2.6 | 2.5 | 0.175 | 0.455 | 6.5 | 0.455
1376114 | R+1 fini | 2.6 | 1.65 | 0.1155 | 0.1841 | 2.63 | 0.1841
1376194 | R+1 fini | 2.6 | 2.09 | 0.1463 | 0.249655 | 3.5665 | 0.249655
1376261 | R+1 fini | 2.6 | 2.5 | 0.175 | 0.455 | 6.5 | 0.455
1376348 | R+1 fini | 2.6 | 1.66 | 0.1162 | 0.18592 | 2.656 | 0.18592
1376471 | R+1 fini | 2.6 | 0.6 | 0.042 | 0.1092 | 1.56 | 0.1092
1376547 | R+1 fini | 2.6 | 0.6 | 0.042 | 0.1092 | 1.56 | 0.1092
1376662 | R+1 fini | 2.6 | 2.63 | 0.1841 | 0.47866 | 6.838 | 0.47866
1376779 | R+1 fini | 2.6 | 2.14 | 0.1498 | 0.258755 | 3.6965 | 0.258755
1376871 | R+1 fini | 2.6 | 1.8 | 0.126 | 0.2114 | 3.02 | 0.2114
1377170 | R+1 fini | 2.6 | 2.205 | 0.15435 | 0.270585 | 3.8655 | 0.270585
1377171 | R+1 fini | 2.6 | 2.52406 | 0.176684 | 0.459379 | 6.56256 | 0.459379
1377172 | R+1 fini | 2.6 | 1.775 | 0.12425 | 0.20685 | 2.955 | 0.20685
1380232 | R+1 fini | 2.6 | 2.02 | 0.1414 | 0.36764 | 5.252 | 0.36764
1380287 | R+1 fini | 2.6 | 1.76 | 0.1232 | 0.17507 | 2.501 | 0.17507
1380379 | R+1 fini | 2.6 | 1.7 | 0.119 | 0.3094 | 4.42 | 0.3094
1380549 | R+1 fini | 2.6 | 2.22 | 0.1554 | 0.14259 | 2.037 | 0.14259
1380652 | R+1 fini | 2.6 | 1.47 | 0.1029 | 0.26754 | 3.822 | 0.26754
1380720 | R+1 fini | 2.6 | 3.37 | 0.2359 | 0.61334 | 8.762 | 0.61334
1380793 | R+1 fini | 2.6 | 1.68 | 0.1176 | 0.16051 | 2.293 | 0.16051
1380944 | R+1 fini | 2.6 | 1.3 | 0.091 | 0.2366 | 3.38 | 0.2366
1381106 | R+1 fini | 2.6 | 1.3 | 0.091 | 0.105875 | 1.5125 | 0.105875
1381185 | R+1 fini | 2.6 | 0.6 | 0.042 | 0.1092 | 1.56 | 0.1092
1389898 | R+1 fini | 2.6 | 0.335 | 0.02345 | 0.06097 | 0.871 | 0.06097
1434192 | R+1 fini | 2.6 | 0.6 | 0.042 | 0.1092 | 1.56 | 0.1092
1621580 | R+1 fini | 2.1 | 1.79574 | 0.125702 | 0.263973 | 3.77105 | 0.263973
1621806 | R+1 fini | 2.1 | 1.85 | 0.1295 | 0.27195 | 3.885 | 0.27195
1621969 | R+1 fini | 2.1 | 1.85 | 0.1295 | 0.27195 | 3.885 | 0.27195
1622148 | R+1 fini | 2.1 | 1.85 | 0.1295 | 0.27195 | 3.885 | 0.27195
1622276 | R+1 fini | 2.1 | 1.85 | 0.1295 | 0.27195 | 3.885 | 0.27195

# IfcWall: Mur de base:ITE (37)
Type - PredefinedType: STANDARD
Type - Pset_WallCommon - IsExternal: yes
Material: 73FQT + ISD 0000
Pset_EnvironmentalImpactIndicators - Reference: ITE; sets with these values: 2
Pset_WallCommon - ExtendToStructure: no; LoadBearing: no; Reference: ITE
Name (Mur de base:ITE:...) | In | NetVolume (m3) | Height (m) | Length (m) | Width (m) | GrossFootprintArea (m2) | GrossVolume (m3) | GrossSideArea (m2) | NetSideArea (m2)
348511 | RDC | 17.6631
348623 | RDC | 2.12355 | 6.5 | 2.97 | 0.11 | 0.3267 | 2.12355 | 19.305 | 19.305
348913 | RDC | 3.99728 | 6.5 | 7.33 | 0.11 | 0.8063 | 4.13423 | 37.5839 | 36.3441
348937 | RDC | 0.0396 | 3.6 | 0.1 | 0.11 | 0.011 | 0.04356 | 0.396 | 0.396
349132 | RDC | 5.22113 | 6.5 | 9.43 | 0.11 | 1.0373 | 5.76895 | 52.445 | 47.4856
349262 | RDC | 0.842622 | 7.51 | 1.02 | 0.11 | 0.1122 | 0.842622 | 7.6602 | 7.6602
349355 | RDC | 2.77179
349801 | RDC | 10.8403 | 7.51 | 14.9 | 0.11 | 1.639 | 12.3089 | 111.899 | 98.6005
350336 | RDC | 0.49566 | 7.51 | 0.6 | 0.11 | 0.066 | 0.49566 | 4.506 | 4.506
350511 | RDC | 2.27444 | 7.51 | 3.51 | 0.11 | 0.3861 | 2.89961 | 26.3601 | 20.6825
350811 | RDC | 11.0316 | 7.51 | 13.94 | 0.11 | 1.5334 | 11.1686 | 101.532 | 100.293
351062 | RDC | 13.3554 | 7.51 | 18.3 | 0.11 | 2.013 | 15.1176 | 137.433 | 121.475
351445 | RDC | 13.9452 | 7.51 | 19.785 | 0.11 | 2.17635 | 16.3444 | 148.585 | 126.858
351644 | RDC | 4.83953 | 4.4 | 12.716 | 0.11 | 1.39775 | 6.15455 | 55.9505 | 44.036
351940 | RDC | 4.69613 | 4.4 | 12.4483 | 0.11 | 1.36831 | 5.47058 | 49.7326 | 42.715
352209 | RDC | 5.31188 | 4.4 | 13.7249 | 0.11 | 1.50974 | 6.0823 | 55.2937 | 48.3072
352759 | RDC | 6.76228 | 4.4 | 20.1242 | 0.11 | 2.21366 | 8.81612 | 80.1465 | 61.5215
352921 | RDC | 5.26365 | 4.4 | 13.4149 | 0.11 | 1.47564 | 6.49282 | 59.0257 | 47.8531
353070 | RDC | 1.51976 | 4.4 | 3.14 | 0.11 | 0.3454 | 1.51976 | 13.816 | 13.816
353265 | RDC | 7.21619 | 4.4 | 18.2623 | 0.11 | 2.00785 | 8.83895 | 80.3541 | 65.6865
353431 | RDC | 1.13292 | 4.4 | 2.3499 | 0.11 | 0.257482 | 1.13735 | 10.3396 | 10.3396
353591 | RDC | 4.05615 | 7.51 | 4.91 | 0.11 | 0.5401 | 4.05615 | 36.8741 | 36.8741
353755 | RDC | 2.25792 | 7.51 | 3.49 | 0.11 | 0.3839 | 2.88309 | 26.2099 | 20.5323
353806 | RDC | 0.396528 | 7.51 | 0.48 | 0.11 | 0.0528 | 0.396528 | 3.6048 | 3.6048
355244 | RDC | 1.56959 | 7.51 | 1.9 | 0.11 | 0.209 | 1.56959 | 14.269 | 14.269
355384 | RDC | 2.65701 | 7.51 | 3.96 | 0.11 | 0.4356 | 2.92819 | 26.6199 | 24.1546
355546 | RDC | 0.732226 | 4.01 | 1.66 | 0.11 | 0.1826 | 0.732226 | 6.6566 | 6.6566
355710 | RDC | 1.64264 | 4.01 | 4.83 | 0.11 | 0.5313 | 1.64264 | 14.9331 | 14.9331
355777 | RDC | 0.635184 | 4.01 | 1.44 | 0.11 | 0.1584 | 0.635184 | 5.7744 | 5.7744
1358131 | R+1 fini | 1.8361
1366012 | R+1 fini | 2.77503
1366331 | R+1 fini | 1.76658
1366793 | R+1 fini | 0.106051 | 3.11 | 0.31 | 0.11 | 0.0341 | 0.106051 | 0.9641 | 0.9641
1601099 | R+1 fini | 1.00195 | 1.41 | 6.46 | 0.11 | 0.7106 | 1.00195 | 9.1086 | 9.1086
1602272 | R+1 fini | 1.04072 | 1.41 | 6.71 | 0.11 | 0.7381 | 1.04072 | 9.4611 | 9.4611
1603221 | R+1 fini | 0.02838 | 1.29 | 0.2 | 0.11 | 0.022 | 0.02838 | 0.258 | 0.258
1656545 | R+1 fini | 0.07744 | 3.52 | 0.2 | 0.11 | 0.022 | 0.07744 | 0.704 | 0.704

# IfcWall: Mur de base:Int. Parpaing 100 mm (7)
In: RDC
Type - PredefinedType: STANDARD
Type - Pset_WallCommon - IsExternal: no; ThermalTransmittance: 13 kg/K/s3
Material: Blocs béton manufacturés
Qto_WallBaseQuantities - Width: 0.1 m
Pset_EnvironmentalImpactIndicators - Reference: Int. Parpaing 100 mm; sets with these values: 2
Pset_WallCommon - ExtendToStructure: no; LoadBearing: no; Reference: Int. Parpaing 100 mm
Name (Mur de base:Int. Parpaing 100 mm:...) | Height (m) | Length (m) | GrossFootprintArea (m2) | GrossVolume (m3) = NetVolume (m3) | GrossSideArea (m2) = NetSideArea (m2)
1009546 | 1.42 | 0.61 | 0.061 | 0.08662 | 0.8662
1009603 | 1.41742 | 0.88 | 0.088 | 0.124733 | 1.24733
1308933 | 3.79 | 1.63 | 0.163 | 0.274725 | 2.74725
1309375 | 3.4 | 1.62 | 0.162 | 0.207755 | 2.07755
1321465 | 3.79 | 1.64 | 0.164 | 0.278515 | 2.78515
1337340 | 3.4 | 0.6 | 0.06 | 0.204 | 2.04
1337377 | 3.4 | 0.26 | 0.026 | 0.0884 | 0.884

# IfcWall: Mur de base:Int. Plâtre 100 mm (165)
Type - PredefinedType: SOLIDWALL
Type - Pset_WallCommon - IsExternal: no
Material: Mur par défaut
Qto_WallBaseQuantities - Width: 0.1 m
Pset_EnvironmentalImpactIndicators - Reference: Int. Plâtre 100 mm; sets with these values: 2
Pset_WallCommon - ExtendToStructure: no; LoadBearing: no; Reference: Int. Plâtre 100 mm
Name (Mur de base:Int. Plâtre 100 mm:...) | In | Height (m) | Length (m) | GrossFootprintArea (m2) | GrossVolume (m3) | GrossSideArea (m2) = NetSideArea (m2) | NetVolume (m3)
980036 | RDC | 3.79 | 6.1 | 0.61 | 2.1044 | 21.044 | 2.1044
980275 | RDC | 3.79 | 6.1 | 0.61 | 2.3119 | 23.119 | 2.3119
980557 | RDC | 3.79 | 6.00583 | 0.59975 | 2.27621 | 22.7621 | 2.27305
980882 | RDC | 3.79 | 5.46159 | 0.545327 | 1.86244 | 18.6244 | 1.85929
983048 | RDC | 3.79 | 7.48959 | 0.748127 | 2.83856 | 28.3856 | 2.8354
983179 | RDC | 3.79 | 1.48699 | 0.147866 | 0.563568 | 5.63568 | 0.560414
983331 | RDC | 3.79 | 4.12 | 0.412 | 1.56148 | 15.6148 | 1.56148
984083 | RDC | 3.79 | 7.0069 | 0.699858 | 2.65562 | 26.5562 | 2.65246
984485 | RDC | 3.7 | 10.7028 | 1.06945 | 3.54504 | 35.4504 | 3.54196
984606 | RDC | 3.7 | 4.19593 | 0.419593 | 1.55249 | 15.5249 | 1.55249
984894 | RDC | 3.4 | 5.4 | 0.54 | 1.836 | 18.36 | 1.836
986016 | RDC | 3.4 | 5.4 | 0.54 | 1.836 | 18.36 | 1.836
986725 | RDC | 3.4 | 5.04 | 0.504 | 1.7136 | 17.136 | 1.7136
987364 | RDC | 2.6 | 0.37 | 0.037 | 0.0962 | 0.962 | 0.0962
987418 | RDC | 2.6 | 0.8 | 0.08 | 0.208 | 2.08 | 0.208
987909 | RDC | 2.6 | 0.9 | 0.09 | 0.234 | 2.34 | 0.234
987958 | RDC | 2.6 | 0.26 | 0.026 | 0.0676 | 0.676 | 0.0676
988353 | RDC | 3.4 | 5.41 | 0.541 | 1.8394 | 18.394 | 1.8394
988466 | RDC | 3.4 | 5.04 | 0.504 | 1.7136 | 17.136 | 1.7136
988475 | RDC | 3.4 | 5.41 | 0.541 | 1.8394 | 18.394 | 1.8394
990051 | RDC | 2.6 | 1.79 | 0.179 | 0.4654 | 4.654 | 0.4654
990095 | RDC | 2.6 | 0.26 | 0.026 | 0.0676 | 0.676 | 0.0676
990413 | RDC | 2.6 | 0.27 | 0.027 | 0.0702 | 0.702 | 0.0702
991137 | RDC | 2.6 | 1.71 | 0.171 | 0.4446 | 4.446 | 0.4446
991138 | RDC | 2.6 | 0.26 | 0.026 | 0.0676 | 0.676 | 0.0676
991139 | RDC | 2.6 | 0.27 | 0.027 | 0.0702 | 0.702 | 0.0702
992413 | RDC | 3.79 | 0.8 | 0.08 | 0.3032 | 3.032 | 0.3032
992475 | RDC | 3.79 | 1.78349 | 0.177517 | 0.675942 | 6.75942 | 0.672788
992691 | RDC | 3.7 | 1.96501 | 0.195669 | 0.519554 | 5.19554 | 0.516474
992799 | RDC | 3.7 | 3.82 | 0.382 | 1.4134 | 14.134 | 1.4134
993035 | RDC | 3.4 | 5.41 | 0.541 | 1.8394 | 18.394 | 1.8394
993122 | RDC | 3.4 | 5.05 | 0.505 | 1.717 | 17.17 | 1.717
993130 | RDC | 3.4 | 5.41 | 0.541 | 1.8394 | 18.394 | 1.8394
993138 | RDC | 3.4 | 5.05 | 0.505 | 1.717 | 17.17 | 1.717
994856 | RDC | 2.6 | 1.71 | 0.171 | 0.4446 | 4.446 | 0.4446
994857 | RDC | 2.6 | 0.26 | 0.026 | 0.0676 | 0.676 | 0.0676
994858 | RDC | 2.6 | 0.26 | 0.026 | 0.0676 | 0.676 | 0.0676
995199 | RDC | 2.6 | 2.52 | 0.252 | 0.6552 | 6.552 | 0.6552
995200 | RDC | 2.6 | 0.26 | 0.026 | 0.0676 | 0.676 | 0.0676
995201 | RDC | 2.6 | 0.26 | 0.026 | 0.0676 | 0.676 | 0.0676
995362 | RDC | 2.6 | 0.82 | 0.082 | 0.2132 | 2.132 | 0.2132
995392 | RDC | 2.6 | 0.36 | 0.036 | 0.0936 | 0.936 | 0.0936
998279 | RDC | 3.4 | 3.63 | 0.363 | 1.0267 | 10.267 | 1.0267
999023 | RDC | 3.4 | 6.27 | 0.627 | 1.7168 | 17.168 | 1.7168
999910 | RDC | 3.4 | 2.15 | 0.215 | 0.731 | 7.31 | 0.731
1000095 | RDC | 3.4 | 2.15 | 0.215 | 0.731 | 7.31 | 0.731
1001100 | RDC | 3.4 | 6.26 | 0.626 | 2.1284 | 21.284 | 2.1284
1002210 | RDC | 2.6 | 0.37 | 0.037 | 0.0962 | 0.962 | 0.0962
1002266 | RDC | 2.6 | 0.87 | 0.087 | 0.2262 | 2.262 | 0.2262
1002822 | RDC | 3.4 | 6.26 | 0.626 | 2.1284 | 21.284 | 2.1284
1003580 | RDC | 3.4 | 5.89 | 0.589 | 2.0026 | 20.026 | 2.0026
1003661 | RDC | 3.4 | 6.27 | 0.627 | 2.1318 | 21.318 | 2.1318
1003671 | RDC | 3.4 | 6.27 | 0.627 | 2.1318 | 21.318 | 2.1318
1004705 | RDC | 2.6 | 0.37 | 0.037 | 0.0962 | 0.962 | 0.0962
1004800 | RDC | 2.6 | 1.94 | 0.194 | 0.5044 | 5.044 | 0.5044
1004828 | RDC | 2.6 | 0.28 | 0.028 | 0.0728 | 0.728 | 0.0728
1005941 | RDC | 2.6 | 0.37 | 0.037 | 0.0962 | 0.962 | 0.0962
1006001 | RDC | 2.6 | 0.87 | 0.087 | 0.2262 | 2.262 | 0.2262
1006471 | RDC | 2.6 | 2.1 | 0.21 | 0.546 | 5.46 | 0.546
1006540 | RDC | 2.6 | 2.44 | 0.244 | 0.44765 | 4.4765 | 0.44765
1006672 | RDC | 2.6 | 0.75 | 0.075 | 0.195 | 1.95 | 0.195
1006710 | RDC | 2.6 | 2.06 | 0.206 | 0.5356 | 5.356 | 0.5356
1006770 | RDC | 2.6 | 0.65 | 0.065 | 0.169 | 1.69 | 0.169
1008871 | RDC | 2.6 | 0.37 | 0.037 | 0.0962 | 0.962 | 0.0962
1008915 | RDC | 2.6 | 0.9 | 0.09 | 0.234 | 2.34 | 0.234
1009935 | RDC | 3.4 | 5.9 | 0.59 | 2.006 | 20.06 | 2.006
1010751 | RDC | 3.4 | 4.36 | 0.436 | 1.4824 | 14.824 | 1.4824
1010761 | RDC | 3.4 | 5.89 | 0.589 | 2.0026 | 20.026 | 2.0026
1010771 | RDC | 3.4 | 4.26 | 0.426 | 1.4484 | 14.484 | 1.4484
1012093 | RDC | 2.6 | 2.72 | 0.272 | 0.517072 | 5.17072 | 0.34015
1012456 | RDC | 3.4 | 0.36 | 0.036 | 0.1224 | 1.224 | 0.1224
1012511 | RDC | 3.4 | 1.9 | 0.19 | 0.646 | 6.46 | 0.646
1012545 | RDC | 3.4 | 0.7 | 0.07 | 0.238 | 2.38 | 0.238
1014237 | RDC | 2.6 | 0.26 | 0.026 | 0.0676 | 0.676 | 0.0676
1014293 | RDC | 2.6 | 1.9 | 0.19 | 0.494 | 4.94 | 0.494
1014355 | RDC | 2.6 | 0.26 | 0.026 | 0.0676 | 0.676 | 0.0676
1014423 | RDC | 2.6 | 1.9 | 0.19 | 0.494 | 4.94 | 0.494
1015022 | RDC | 2.6 | 0.37 | 0.037 | 0.0962 | 0.962 | 0.0962
1015087 | RDC | 2.6 | 1.985 | 0.1985 | 0.5161 | 5.161 | 0.5161
1015124 | RDC | 2.6 | 0.27 | 0.027 | 0.0702 | 0.702 | 0.0702
1015865 | RDC | 2.6 | 0.31 | 0.031 | 0.0806 | 0.806 | 0.0806
1015866 | RDC | 2.6 | 1.9 | 0.19 | 0.494 | 4.94 | 0.494
1015867 | RDC | 2.6 | 0.31 | 0.031 | 0.0806 | 0.806 | 0.0806
1015868 | RDC | 2.6 | 1.9 | 0.19 | 0.494 | 4.94 | 0.494
1015949 | RDC | 2.6 | 0.97 | 0.097 | 0.2522 | 2.522 | 0.2522
1015950 | RDC | 2.6 | 0.26 | 0.026 | 0.0676 | 0.676 | 0.0676
1016376 | RDC | 2.6 | 1 | 0.1 | 0.26 | 2.6 | 0.26
1016491 | RDC | 2.6 | 1 | 0.1 | 0.26 | 2.6 | 0.26
1355482 | R+1 fini | 3.3 | 5.39 | 0.539 | 1.7787 | 17.787 | 1.7787
1355599 | R+1 fini | 3.3 | 5.39 | 0.539 | 1.7787 | 17.787 | 1.7787
1355608 | R+1 fini | 3.3 | 5.04 | 0.504 | 1.6632 | 16.632 | 1.6632
1355617 | R+1 fini | 3.3 | 5.39 | 0.539 | 1.7787 | 17.787 | 1.7787
1355626 | R+1 fini | 3.3 | 5.04 | 0.504 | 1.6632 | 16.632 | 1.6632
1355637 | R+1 fini | 3.3 | 5.39 | 0.539 | 1.7787 | 17.787 | 1.7787
1359141 | R+1 fini | 3.3 | 5.42 | 0.542 | 1.7886 | 17.886 | 1.7886
1359348 | R+1 fini | 3.3 | 5.11 | 0.511 | 1.6863 | 16.863 | 1.6863
1359447 | R+1 fini | 3.3 | 6.25 | 0.625 | 2.0625 | 20.625 | 2.0625
1359566 | R+1 fini | 3.3 | 2.34 | 0.234 | 0.7722 | 7.722 | 0.7722
1359683 | R+1 fini | 3.3 | 2.39 | 0.239 | 0.60195 | 6.0195 | 0.60195
1359784 | R+1 fini | 3.3 | 0.74 | 0.074 | 0.2442 | 2.442 | 0.2442
1359843 | R+1 fini | 3.3 | 2.17 | 0.217 | 0.7161 | 7.161 | 0.7161
1359920 | R+1 fini | 3.3 | 0.64 | 0.064 | 0.2112 | 2.112 | 0.2112
1360016 | R+1 fini | 3.3 | 0.35 | 0.035 | 0.1155 | 1.155 | 0.1155
1360060 | R+1 fini | 3.3 | 0.5 | 0.05 | 0.165 | 1.65 | 0.165
1360177 | R+1 fini | 3.3 | 5.9 | 0.59 | 1.947 | 19.47 | 1.947
1360301 | R+1 fini | 3.3 | 6.25 | 0.625 | 2.0625 | 20.625 | 2.0625
1360432 | R+1 fini | 3.3 | 4.235 | 0.4235 | 1.39755 | 13.9755 | 1.39755
1360582 | R+1 fini | 3.3 | 2.025 | 0.2025 | 0.66825 | 6.6825 | 0.66825
1360742 | R+1 fini | 3.3 | 0.52 | 0.052 | 0.1716 | 1.716 | 0.1716
1360836 | R+1 fini | 3.3 | 1.925 | 0.1925 | 0.63525 | 6.3525 | 0.63525
1360880 | R+1 fini | 3.3 | 0.36 | 0.036 | 0.1188 | 1.188 | 0.1188
1360983 | R+1 fini | 3.3 | 2 | 0.2 | 0.66 | 6.6 | 0.66
1361034 | R+1 fini | 3.3 | 0.26 | 0.026 | 0.0858 | 0.858 | 0.0858
1361084 | R+1 fini | 3.3 | 0.34 | 0.034 | 0.1122 | 1.122 | 0.1122
1361213 | R+1 fini | 3.3 | 0.35 | 0.035 | 0.1155 | 1.155 | 0.1155
1361403 | R+1 fini | 3.3 | 1.68 | 0.168 | 0.5544 | 5.544 | 0.5544
1361485 | R+1 fini | 3.3 | 0.25 | 0.025 | 0.0825 | 0.825 | 0.0825
1361578 | R+1 fini | 3.3 | 0.35 | 0.035 | 0.1155 | 1.155 | 0.1155
1361684 | R+1 fini | 3.3 | 1.69 | 0.169 | 0.5577 | 5.577 | 0.5577
1361731 | R+1 fini | 3.3 | 0.25 | 0.025 | 0.0825 | 0.825 | 0.0825
1361809 | R+1 fini | 3.3 | 0.35 | 0.035 | 0.1155 | 1.155 | 0.1155
1361886 | R+1 fini | 3.3 | 0.8 | 0.08 | 0.264 | 2.64 | 0.264
1362009 | R+1 fini | 3.3 | 0.35 | 0.035 | 0.1155 | 1.155 | 0.1155
1362113 | R+1 fini | 3.3 | 0.8 | 0.08 | 0.264 | 2.64 | 0.264
1362488 | R+1 fini | 3.3 | 1.6 | 0.16 | 0.528 | 5.28 | 0.528
1362548 | R+1 fini | 3.3 | 0.305 | 0.0305 | 0.10065 | 1.0065 | 0.10065
1362634 | R+1 fini | 3.3 | 0.3 | 0.03 | 0.099 | 0.99 | 0.099
1362698 | R+1 fini | 3.3 | 0.36 | 0.036 | 0.1188 | 1.188 | 0.1188
1362807 | R+1 fini | 3.3 | 2.48 | 0.248 | 0.8184 | 8.184 | 0.8184
1362860 | R+1 fini | 3.3 | 0.26 | 0.026 | 0.0858 | 0.858 | 0.0858
1362988 | R+1 fini | 3.3 | 0.36 | 0.036 | 0.1188 | 1.188 | 0.1188
1363082 | R+1 fini | 3.3 | 1.67 | 0.167 | 0.5511 | 5.511 | 0.5511
1363120 | R+1 fini | 3.3 | 0.26 | 0.026 | 0.0858 | 0.858 | 0.0858
1363226 | R+1 fini | 3.3 | 0.31 | 0.031 | 0.1023 | 1.023 | 0.1023
1363321 | R+1 fini | 3.3 | 1.68 | 0.168 | 0.5544 | 5.544 | 0.5544
1363376 | R+1 fini | 3.3 | 0.21 | 0.021 | 0.0693 | 0.693 | 0.0693
1363679 | R+1 fini | 3.3 | 5.89 | 0.589 | 1.9437 | 19.437 | 1.9437
1363808 | R+1 fini | 3.3 | 0.37 | 0.037 | 0.1221 | 1.221 | 0.1221
1363956 | R+1 fini | 3.3 | 2 | 0.2 | 0.66 | 6.6 | 0.66
1364008 | R+1 fini | 3.3 | 0.27 | 0.027 | 0.0891 | 0.891 | 0.0891
1364119 | R+1 fini | 3.3 | 4.26 | 0.426 | 1.4058 | 14.058 | 1.4058
1364217 | R+1 fini | 3.3 | 2 | 0.2 | 0.66 | 6.6 | 0.66
1364283 | R+1 fini | 3.3 | 0.52 | 0.052 | 0.1716 | 1.716 | 0.1716
1364406 | R+1 fini | 3.3 | 1.9 | 0.19 | 0.627 | 6.27 | 0.627
1364615 | R+1 fini | 3.3 | 0.36 | 0.036 | 0.1188 | 1.188 | 0.1188
1364706 | R+1 fini | 3.3 | 0.87 | 0.087 | 0.2871 | 2.871 | 0.2871
1364824 | R+1 fini | 3.3 | 0.36 | 0.036 | 0.1188 | 1.188 | 0.1188
1364895 | R+1 fini | 3.3 | 0.87 | 0.087 | 0.2871 | 2.871 | 0.2871
1365121 | R+1 fini | 3.3 | 5.99 | 0.599 | 1.9767 | 19.767 | 1.9767
1366947 | R+1 fini | 3.3 | 5.89 | 0.589 | 1.9437 | 19.437 | 1.9437
1367112 | R+1 fini | 3.3 | 6.25 | 0.625 | 2.0625 | 20.625 | 2.0625
1367318 | R+1 fini | 3.3 | 1.02406 | 0.102406 | 0.33794 | 3.3794 | 0.33794
1367376 | R+1 fini | 3.3 | 0.26 | 0.026 | 0.0858 | 0.858 | 0.0858
1375540 | R+1 fini | 3.3 | 0.36 | 0.036 | 0.1188 | 1.188 | 0.1188
1375689 | R+1 fini | 3.3 | 1.94 | 0.194 | 0.6402 | 6.402 | 0.6402
1375746 | R+1 fini | 3.3 | 0.26 | 0.026 | 0.0858 | 0.858 | 0.0858
1376985 | R+1 fini | 2.6 | 0.34 | 0.034 | 0.0884 | 0.884 | 0.0884
1377074 | R+1 fini | 2.6 | 0.87 | 0.087 | 0.2262 | 2.262 | 0.2262
1379767 | R+1 fini | 2.6 | 1.61 | 0.161 | 0.4186 | 4.186 | 0.4186
1379927 | R+1 fini | 2.6 | 1.63 | 0.163 | 0.080755 | 0.80755 | 0.080755
1385120 | R+1 fini | 3.3 | 5.05 | 0.505 | 1.6665 | 16.665 | 1.6665
1385222 | R+1 fini | 3.3 | 5.05 | 0.505 | 1.6665 | 16.665 | 1.6665
1385233 | R+1 fini | 3.3 | 5.42 | 0.542 | 1.7886 | 17.886 | 1.7886
1385349 | R+1 fini | 3.3 | 5.42 | 0.542 | 1.7886 | 17.886 | 1.7886
1442892 | R+1 fini | 3.3 | 3.45 | 0.345 | 1.1385 | 11.385 | 1.1385

# IfcWall: Mur de base:Int. Plâtre 70 mm (17)
Type - PredefinedType: STANDARD
Type - Pset_WallCommon - IsExternal: no
Material: Mur par défaut
Qto_WallBaseQuantities - Width: 0.07 m
Pset_EnvironmentalImpactIndicators - Reference: Int. Plâtre 70 mm; sets with these values: 2
Pset_WallCommon - ExtendToStructure: no; LoadBearing: no; Reference: Int. Plâtre 70 mm
Name (Mur de base:Int. Plâtre 70 mm:...) | In | Height (m) | Length (m) | GrossFootprintArea (m2) | GrossVolume (m3) = NetVolume (m3) | GrossSideArea (m2) = NetSideArea (m2)
1116649 | RDC | 2.6 | 0.68 | 0.0476 | 0.12376 | 1.768
1218252 | RDC | 3.6 | 3.16973 | 0.221881 | 0.653522 | 9.33602
1377447 | R+1 fini | 2.1 | 1.8 | 0.126 | 0.2646 | 3.78
1377575 | R+1 fini | 2.1 | 1.835 | 0.12845 | 0.269745 | 3.8535
1377589 | R+1 fini | 2.1 | 1.835 | 0.12845 | 0.269745 | 3.8535
1377605 | R+1 fini | 2.1 | 1.835 | 0.12845 | 0.269745 | 3.8535
1377613 | R+1 fini | 2.1 | 1.835 | 0.12845 | 0.269745 | 3.8535
1377621 | R+1 fini | 2.1 | 1.835 | 0.12845 | 0.269745 | 3.8535
1377631 | R+1 fini | 2.1 | 1.845 | 0.12915 | 0.271215 | 3.8745
1378944 | R+1 fini | 2.1 | 1.79838 | 0.125887 | 0.264362 | 3.7766
1378952 | R+1 fini | 2.1 | 1.85 | 0.1295 | 0.27195 | 3.885
1378962 | R+1 fini | 2.1 | 1.87 | 0.1309 | 0.27489 | 3.927
1378970 | R+1 fini | 2.1 | 1.7825 | 0.124775 | 0.262028 | 3.74325
1442300 | R+1 fini | 3.3 | 1.15 | 0.0805 | 0.26565 | 3.795
1442387 | R+1 fini | 3.3 | 2.4 | 0.168 | 0.5544 | 7.92
1442533 | R+1 fini | 3.3 | 1.64 | 0.1148 | 0.37884 | 5.412
1442592 | R+1 fini | 2.3 | 0.91 | 0.0637 | 0.14651 | 2.093

# IfcWall: Mur de base:Libages BA (30)
In: Arase inf soubassement
Type - PredefinedType: STANDARD
Type - Pset_WallCommon - IsExternal: yes
Material: Mur par défaut
Pset_EnvironmentalImpactIndicators - Reference: Libages BA; sets with these values: 2
Pset_WallCommon - LoadBearing: yes; ExtendToStructure: no; Reference: Libages BA
Name (Mur de base:Libages BA:...) | Height (m) | Length (m) | Width (m) | GrossFootprintArea (m2) | GrossVolume (m3) | GrossSideArea (m2) = NetSideArea (m2) | NetVolume (m3)
295289 | 0.4 | 1.2 | 0.2 | 0.24 | 0.096 | 0.48 | 0.096
295526 | 0.4 | 9.42984 | 0.2 | 1.88431 | 0.754387 | 3.77193 | 0.753726
295631 | 0.4 | 16.538 | 0.2 | 3.30595 | 1.32304 | 6.61521 | 1.32238
295812 |  |  |  |  |  |  | 0.624547
296020 | 0.4 | 1.35 | 0.2 | 0.27 | 0.108 | 0.54 | 0.108
296096 | 0.4 | 1.35 | 0.2 | 0.27 | 0.108 | 0.54 | 0.108
296224 | 0.4 | 4.81527 | 0.2 | 0.959725 | 0.385222 | 1.92611 | 0.38389
296308 | 0.4 | 4.21 | 0.2 | 0.842 | 0.3368 | 1.684 | 0.3368
296488 | 0.4 | 24.76 | 0.2 | 4.952 | 1.9808 | 9.904 | 1.9808
296617 | 0.4 | 30.575 | 0.2 | 6.115 | 2.446 | 12.23 | 2.446
296782 | 0.4 | 1.2 | 0.2 | 0.24 | 0.096 | 0.48 | 0.096
296876 | 0.4 | 1.2 | 0.2 | 0.24 | 0.096 | 0.48 | 0.096
297068 | 0.49 | 6.26 | 0.2 | 1.252 | 0.61348 | 3.0674 | 0.61348
297136 | 0.49 | 32.215 | 0.2 | 6.443 | 3.15707 | 15.7854 | 3.15707
297387 | 0.49 | 26.38 | 0.2 | 5.276 | 2.58524 | 12.9262 | 2.58524
297574 | 0.4 | 6.26 | 0.2 | 1.252 | 0.5008 | 2.504 | 0.5008
297635 | 0.49 | 1.52 | 0.2 | 0.304 | 0.14896 | 0.7448 | 0.14896
297719 | 0.4 | 2.89 | 0.2 | 0.578 | 0.2312 | 1.156 | 0.2312
297996 | 0.49 | 1.9 | 0.2 | 0.38 | 0.1862 | 0.931 | 0.1862
298064 |  |  |  |  |  |  | 0.381076
298219 | 0.49 | 1.95 | 0.2 | 0.39 | 0.1911 | 0.9555 | 0.1911
298288 | 0.49 | 1.7 | 0.2 | 0.34 | 0.1666 | 0.833 | 0.1666
298409 | 0.49 | 1.36 | 0.2 | 0.272 | 0.13328 | 0.6664 | 0.13328
298584 | 0.49 | 6.82 | 0.2 | 1.364 | 0.66836 | 3.3418 | 0.66836
298722 | 0.49 | 7.16 | 0.2 | 1.432 | 0.70168 | 3.5084 | 0.70168
298775 | 0.49 | 4.52 | 0.2 | 0.904 | 0.44296 | 2.2148 | 0.44296
298830 | 0.49 | 6.96 | 0.2 | 1.392 | 0.68208 | 3.4104 | 0.68208
298877 | 0.49 | 1.32 | 0.2 | 0.264 | 0.12936 | 0.6468 | 0.12936
298995 | 0.49 | 3.07 | 0.2 | 0.614 | 0.30086 | 1.5043 | 0.30086
299319 | 0.49 | 5.81 | 0.2 | 1.162 | 0.56938 | 2.8469 | 0.56938

# IfcWall: Mur de base:Libages blocs pleins (26)
In: Arase inf soubassement
Type - PredefinedType: STANDARD
Type - Pset_WallCommon - IsExternal: yes
Material: Mur par défaut
Pset_EnvironmentalImpactIndicators - Reference: Libages blocs pleins; sets with these values: 2
Pset_WallCommon - Reference: Libages blocs pleins; LoadBearing: yes; ExtendToStructure: no
Name (Mur de base:Libages blocs pleins:...) | Height (m) | Length (m) | Width (m) | GrossFootprintArea (m2) | GrossVolume (m3) | GrossSideArea (m2) = NetSideArea (m2) | NetVolume (m3)
291487 | 0.48 | 9.94 | 0.2 | 1.988 | 0.95424 | 4.7712 | 0.95424
291604 | 0.48 | 13.41 | 0.2 | 2.682 | 1.28736 | 6.4368 | 1.28736
291667 | 0.48 | 3.03 | 0.2 | 0.606 | 0.29088 | 1.4544 | 0.29088
291733 | 0.48 | 11.3172 | 0.2 | 2.26344 | 1.08645 | 5.43225 | 1.08645
291815 | 0.49 | 6.61802 | 0.2 | 1.32028 | 0.648566 | 3.24283 | 0.646935
292028 |  |  |  |  |  |  | 0.224438
292587 | 0.49 | 5.01 | 0.2 | 1.002 | 0.49098 | 2.4549 | 0.49098
292688 | 0.49 | 3.18 | 0.2 | 0.636 | 0.31164 | 1.5582 | 0.31164
292725 | 0.49 | 0.59 | 0.2 | 0.118 | 0.05782 | 0.2891 | 0.05782
292897 | 0.49 | 25.095 | 0.2 | 5.019 | 2.45931 | 12.2965 | 2.45931
293024 | 0.4 | 3.2 | 0.2 | 0.64 | 0.256 | 1.28 | 0.256
293092 | 0.4 | 7.02 | 0.2 | 1.404 | 0.5616 | 2.808 | 0.5616
293189 | 0.63 | 9.23 | 0.2 | 1.846 | 1.16298 | 5.8149 | 1.16298
293360 | 0.49 | 1.01 | 0.2 | 0.202 | 0.09898 | 0.4949 | 0.09898
293461 | 0.49 | 3.56 | 0.2 | 0.712 | 0.34888 | 1.7444 | 0.34888
293713 | 0.49 | 15.1 | 0.2 | 3.02 | 1.4798 | 7.399 | 1.4798
293835 | 0.49 | 0.6 | 0.2 | 0.12 | 0.0588 | 0.294 | 0.0588
293891 | 0.49 | 3.2 | 0.2 | 0.64 | 0.3136 | 1.568 | 0.3136
294127 | 0.49 | 13.63 | 0.2 | 2.726 | 1.33574 | 6.6787 | 1.33574
294228 | 0.49 | 18.3 | 0.2 | 3.66 | 1.7934 | 8.967 | 1.7934
294368 |  |  |  |  |  |  | 2.13705
294564 | 0.49 | 12.967 | 0.2 | 2.5934 | 1.27077 | 6.35384 | 1.27077
299639 | 0.49 | 1.81 | 0.2 | 0.362 | 0.17738 | 0.8869 | 0.17738
299712 | 0.49 | 9.76 | 0.2 | 1.952 | 0.95648 | 4.7824 | 0.95648
299749 | 0.49 | 1.61 | 0.2 | 0.322 | 0.15778 | 0.7889 | 0.15778
299820 | 0.49 | 9.56 | 0.2 | 1.912 | 0.93688 | 4.6844 | 0.93688

# IfcWindow: 1 Vantail - Droit:1-F Châssis fixe + Imposte fixe 0.8*2.3 (10)
In: RDC
Type - PredefinedType: WINDOW; Material: Fenêtre - Poignée, Fenêtre - Appui, Fenêtre - Vitrage, Fenêtre - Cadre (2)
Type - Pset_WindowCommon - IsExternal: no
OverallHeight: 2.43 m; OverallWidth: 0.9 m; Material: Fenêtre - Poignée, Fenêtre - Appui, Fenêtre - Vitrage, Fenêtre - Cadre
Pset_EnvironmentalImpactIndicators - Reference: 1-F Châssis fixe + Imposte fixe 0.8*2.3
Pset_WindowCommon - Reference: 1-F Châssis fixe + Imposte fixe 0.8*2.3
Qto_WindowBaseQuantities - Area: 1.84 m2
Name (1 Vantail - Droit:1-F Châssis fixe + Imposte fixe 0.8*2.3:...)
575180 | Pset_WindowCommon - IsExternal: yes
575602
575634
576169
576190
576444
576509
576742
577034
577289

# IfcWindow: 1 Vantail - Droit:1-OB Châssis OB + Imposte fixe 0.8*2.3 (13)
In: RDC
Type - PredefinedType: WINDOW; Material: Fenêtre - Poignée, Fenêtre - Appui, Fenêtre - Vitrage, Fenêtre - Cadre (2)
Type - Pset_WindowCommon - IsExternal: no
OverallHeight: 2.43 m; OverallWidth: 0.9 m; Material: Fenêtre - Poignée, Fenêtre - Appui, Fenêtre - Vitrage, Fenêtre - Cadre
Pset_EnvironmentalImpactIndicators - Reference: 1-OB Châssis OB + Imposte fixe 0.8*2.3
Pset_WindowCommon - Reference: 1-OB Châssis OB + Imposte fixe 0.8*2.3
Qto_WindowBaseQuantities - Area: 1.84 m2
Name (1 Vantail - Droit:1-OB Châssis OB + Imposte fixe 0.8*2.3:...)
574887 | Pset_WindowCommon - IsExternal: yes
575427
575496
575504
576031
576113
576303
576391
576574
576682
576853
576924
577131

# IfcWindow: 1 Vantail - Droit:1-OF 0.9*1.55 (30)
In: RDC
Type - PredefinedType: WINDOW; Material: Fenêtre - Poignée, Fenêtre - Appui, Fenêtre - Cadre (2), Fenêtre - Vitrage
Type - Pset_WindowCommon - IsExternal: no
OverallHeight: 1.68 m; OverallWidth: 1 m; Material: Fenêtre - Poignée, Fenêtre - Appui, Fenêtre - Cadre, Fenêtre - Vitrage
Pset_EnvironmentalImpactIndicators - Reference: 1-OF 0.9*1.55
Pset_WindowCommon - Reference: 1-OF 0.9*1.55
Qto_WindowBaseQuantities - Area: 1.395 m2
Name (1 Vantail - Droit:1-OF 0.9*1.55:...)
557786 | Pset_WindowCommon - IsExternal: yes
558350
558413
558617
558796
558866
559036
559139
560693
560833
569255
569534
570008
570075
570215
570384
570655
570935
571414
571700
571819
572181
572274
573057
573172
573744
573841
574081
574182
1367802

# IfcWindow: 1 Vantail - Droit:1-OS châssis à sopufflet PVC + imposte fixes 1.5*2.3 (4)
In: RDC
Type - PredefinedType: WINDOW; Material: Fenêtre - Poignée, Fenêtre - Appui, Fenêtre - Vitrage, Fenêtre - Cadre (2)
Type - Pset_WindowCommon - IsExternal: no
OverallHeight: 2.43 m; OverallWidth: 1.6 m; Material: Fenêtre - Poignée, Fenêtre - Appui, Fenêtre - Vitrage, Fenêtre - Cadre
Pset_EnvironmentalImpactIndicators - Reference: 1-OS châssis à sopufflet PVC + imposte fixes 1.5*2.3
Pset_WindowCommon - Reference: 1-OS châssis à sopufflet PVC + imposte fixes 1.5*2.3
Qto_WindowBaseQuantities - Area: 3.45 m2
Name (1 Vantail - Droit:1-OS châssis à sopufflet PVC + imposte fixes 1.5*2.3:...)
574339 | Pset_WindowCommon - IsExternal: yes
574491
574712
574862

# IfcWindow: 1 Vantail - Droit:2-C Coulissant pvc 1.8*2.25 (3)
In: RDC
Type - PredefinedType: WINDOW; Material: Fenêtre - Poignée, Fenêtre - Appui, Fenêtre - Vitrage, Fenêtre - Cadre (2)
Type - Pset_WindowCommon - IsExternal: no
OverallHeight: 2.38 m; OverallWidth: 1.9 m; Material: Fenêtre - Poignée, Fenêtre - Appui, Fenêtre - Vitrage, Fenêtre - Cadre
Pset_EnvironmentalImpactIndicators - Reference: 2-C Coulissant pvc 1.8*2.25
Pset_WindowCommon - Reference: 2-C Coulissant pvc 1.8*2.25
Qto_WindowBaseQuantities - Area: 4.05 m2
Name (1 Vantail - Droit:2-C Coulissant pvc 1.8*2.25:...)
561159 | Pset_WindowCommon - IsExternal: yes
561272
561328

# IfcWindow: 1 Vantail - Droit:2-F Châssis fixe + impost fixe 1.5*2.3 (2)
In: RDC
Type - PredefinedType: WINDOW; Material: Fenêtre - Poignée, Fenêtre - Appui, Fenêtre - Vitrage, Fenêtre - Cadre (2)
Type - Pset_WindowCommon - IsExternal: no
OverallHeight: 2.43 m; OverallWidth: 1.6 m; Material: Fenêtre - Poignée, Fenêtre - Appui, Fenêtre - Vitrage, Fenêtre - Cadre
Pset_EnvironmentalImpactIndicators - Reference: 2-F Châssis fixe + impost fixe 1.5*2.3
Pset_WindowCommon - Reference: 2-F Châssis fixe + impost fixe 1.5*2.3
Qto_WindowBaseQuantities - Area: 3.45 m2
Name (1 Vantail - Droit:2-F Châssis fixe + impost fixe 1.5*2.3:...)
1341525 | Pset_WindowCommon - IsExternal: yes
1342089

# IfcWindow: 1 Vantail - Droit:2-OF Ouvrant à la française (33)
In: R+1 fini
Type - PredefinedType: WINDOW; Material: Fenêtre - Poignée, Fenêtre - Appui, Fenêtre - Vitrage, Fenêtre - Cadre (2)
Type - Pset_WindowCommon - IsExternal: no
OverallHeight: 1.48 m; OverallWidth: 1 m; Material: Fenêtre - Poignée, Fenêtre - Appui, Fenêtre - Vitrage, Fenêtre - Cadre
Pset_EnvironmentalImpactIndicators - Reference: 2-OF Ouvrant à la française
Pset_WindowCommon - Reference: 2-OF Ouvrant à la française
Qto_WindowBaseQuantities - Area: 1.215 m2
Name (1 Vantail - Droit:2-OF Ouvrant à la française:...)
1410576 | Pset_WindowCommon - IsExternal: yes
1410689
1410762
1410820
1410899
1410940
1410976
1411851
1411910
1411988
1412180
1412251
1412330
1412414
1412457
1412512
1412556
1412836
1413354
1413663
1413727
1413801
1413866
1413912
1413963
1414027
1414080
1414167
1414306
1414342
1414455
1414618
1522200

# IfcWindow: 1 Vantail - Droit:2-OS Châssis à souflet 0.7*0.75 (3)
In: RDC
Type - PredefinedType: WINDOW; Material: Fenêtre - Poignée, Fenêtre - Appui, Fenêtre - Vitrage, Fenêtre - Cadre (2)
Type - Pset_WindowCommon - IsExternal: no
OverallHeight: 1.08 m; OverallWidth: 0.8 m; Material: Fenêtre - Poignée, Fenêtre - Appui, Fenêtre - Vitrage, Fenêtre - Cadre
Pset_EnvironmentalImpactIndicators - Reference: 2-OS Châssis à souflet 0.7*0.75
Pset_WindowCommon - Reference: 2-OS Châssis à souflet 0.7*0.75
Qto_WindowBaseQuantities - Area: 0.525 m2
Name (1 Vantail - Droit:2-OS Châssis à souflet 0.7*0.75:...)
577714 | Pset_WindowCommon - IsExternal: yes
577786
577859

# IfcWindow: 1 Vantail - Droit:3 - OF Ouvrant francaise 0.9*1.35 (5)
Type - PredefinedType: WINDOW; Material: Fenêtre - Poignée, Fenêtre - Appui, Fenêtre - Vitrage, Fenêtre - Cadre (2)
Type - Pset_WindowCommon - IsExternal: no
OverallHeight: 1.48 m; OverallWidth: 1 m; Material: Fenêtre - Poignée, Fenêtre - Appui, Fenêtre - Vitrage, Fenêtre - Cadre
Pset_EnvironmentalImpactIndicators - Reference: 3 - OF Ouvrant francaise 0.9*1.35
Pset_WindowCommon - Reference: 3 - OF Ouvrant francaise 0.9*1.35
Qto_WindowBaseQuantities - Area: 1.215 m2
Name (1 Vantail - Droit:3 - OF Ouvrant francaise 0.9*1.35:...) | In
561449 | RDC | Pset_WindowCommon - IsExternal: yes
1415414 | R+1 fini
1415472 | R+1 fini
1415526 | R+1 fini
1415660 | R+1 fini

# IfcWindow: 1 Vantail - Droit:4-OF fenêtre accés pompier, 1 Vantail - Droit:4-OF fenêtre accés pompier:1415307
In: R+1 fini
Type - PredefinedType: WINDOW; Material: Fenêtre - Poignée, Fenêtre - Appui, Fenêtre - Vitrage, Fenêtre - Cadre (2)
Type - Pset_WindowCommon - IsExternal: no
OverallHeight: 1.98 m; OverallWidth: 1 m; Material: Fenêtre - Poignée, Fenêtre - Appui, Fenêtre - Vitrage, Fenêtre - Cadre
Pset_EnvironmentalImpactIndicators - Reference: 4-OF fenêtre accés pompier
Pset_WindowCommon - IsExternal: yes; Reference: 4-OF fenêtre accés pompier
Qto_WindowBaseQuantities - Area: 1.665 m2

# IfcWindow: 1 Vantail - Droit:EN-2 Ensembles chassis fixes et à soufflet 1*5.65 (2)
In: RDC
Type - PredefinedType: WINDOW; Material: Fenêtre - Poignée, Fenêtre - Appui, Fenêtre - Vitrage, Fenêtre - Cadre (2)
Type - Pset_WindowCommon - IsExternal: no
OverallHeight: 5.78 m; OverallWidth: 1.1 m; Material: Fenêtre - Poignée, Fenêtre - Appui, Fenêtre - Vitrage, Fenêtre - Cadre
Pset_EnvironmentalImpactIndicators - Reference: EN-2 Ensembles chassis fixes et à soufflet 1*5.65
Pset_WindowCommon - Reference: EN-2 Ensembles chassis fixes et à soufflet 1*5.65
Qto_WindowBaseQuantities - Area: 5.65 m2
Name (1 Vantail - Droit:EN-2 Ensembles chassis fixes et à soufflet 1*5.65:...)
570513 | Pset_WindowCommon - IsExternal: yes
577311
